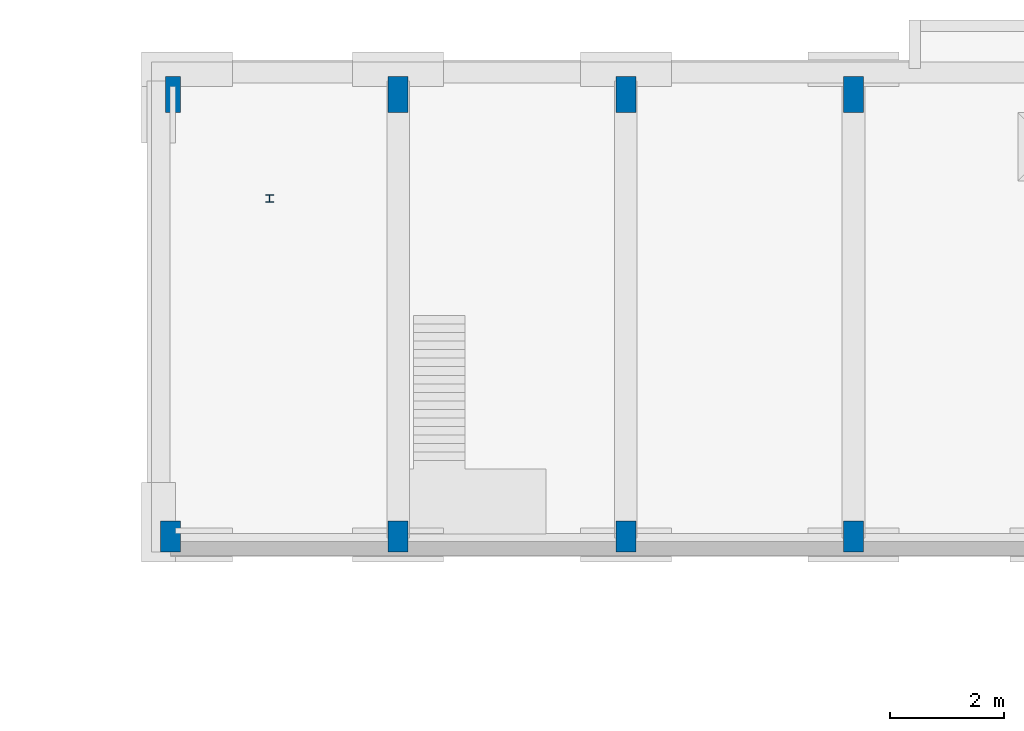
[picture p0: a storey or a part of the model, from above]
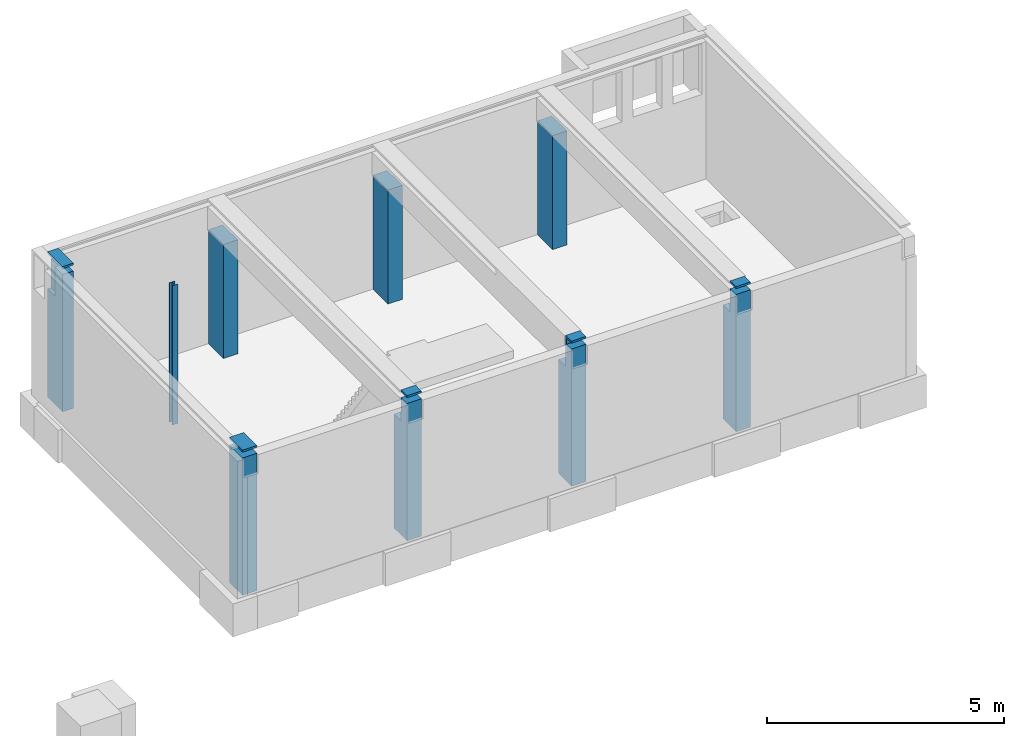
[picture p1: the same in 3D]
Properties of the parts of a building model (IFC2X3), part 1 of 5

# File
Description: ViewDefinition [Basis ILS 2.0, SurfaceGeometryAddOnView, QuantityTakeOffAddOnView], Option [Elements to export: Visible elements (on all stories)], Option [Partial Structure Display: Entire Model], Option [IFC Domain: All], Option [Structural Function: All Elements], Option [Convert Grid elements: On], Option [Convert IFC Annotations and Archicad 2D elements: On], Option [Convert 2D symbols of Doors and Windows: On], Option [Export geometries that Participates in Collision Detection only: On], Option [Split complex elements: On], Option [IFC Model position: Project Origin only], Option [Curtain Wall export mode: Single Element], Option [Railing export mode: Single Element], Option [Stair export mode: Single Element], Option [Properties To Export: Current Scheme properties only], Option [Space containment: Off], Option [Geometry to type objects: On], Option [Element Properties: Off], Option [Building Material Properties: Off], Option [Element Parameters: Off], Option [Component Parameters: Off], Option [IFC Base Quantities: On], Option [Door Window Parameters: Off], Option [IFC Space boundaries: Off], Option [Archicad Zone Categories as IFC Space classification data: Off], Option [Element Classifications: Off]
File name: C:\Users\Briquearchitectenint\BRIQUEarchitecten Dropbox\Kantoor\03-Projecten\BQ2409-ISK Leiden\2409-A-Werkmap\2409-archicad\#publish\ifc\2409-ISK Leiden-nieuw.ifc
Time: 2026-07-10T21:38:03
Author: Architect
Organization: Brique architecten
Written by: DDS_IFC v3.0
Made in: Graphisoft - Archicad - 27.0.0
Authorization: The authorising person

# IfcProject, ISK Leiden
Description: renovatie en verduurzaming; Phase: concept

# IfcSite, <site naam>
RefLatitude: 52, 8, 48, 473880; RefLongitude: 4, 28, 0, 806880; RefElevation: 0 mm
BaseQuantities - GrossPerimeter: 0 mm; GrossArea: 0 m2

# IfcBuilding, <Naam gebouw>
BaseQuantities - GrossFloorArea: 13806 m2

# IfcBuildingStorey (9)
In: <Naam gebouw>
Name | Elevation (mm) | NetHeight (mm) = GrossHeight (mm) = Height (mm) | GrossFloorArea (m2)
Kelder | -3730 | 2630 | 292.087
00 Begane grond | 0 | 3188 | 4961.05
01 1e verdieping | 4250 | 2095 | 4119.65
01 1e tussenverdieping | 3188 | 1062 | 354.603
02 2e tussenverdieping | 6345 | 2155 | 1089.99
02 2e verdieping | 8500 | 1063 | 2567.1
03 3e tussenverdieping | 9563 | 3207 | 387.066
-1 Fundering | -1100 | 1100 | 34.4343
04 4e verdieping | 12770 | 4250 | 0

# IfcSpace: ALG - ALGEMEEN (2)
In: 00 Begane grond
InteriorOrExteriorSpace: INTERNAL
Pset_SpaceCommon - WallCovering: / / /
Name | GrossFloorArea (m2) = NetFloorArea (m2) | GrossPerimeter (mm) = NetPerimeter (mm) | GrossVolume (m3) = NetVolume (m3)
nulpunt | 0.522146 | 7586.11 | 0.0261073
trafo | 0.96 | 4000 | 0.96

# IfcSpace: BVO (17)
InteriorOrExteriorSpace: INTERNAL
Pset_SpaceCommon - WallCovering: / / /
BaseQuantities - FinishFloorHeight: 0 mm
Name | In | LongName | Height (mm) = FinishCeilingHeight (mm) = ClearHeight (mm) | GrossFloorArea (m2) = GrossCeilingArea (m2) | NetFloorArea (m2) = SpaceNetFloorAreaBOMA (m2) = SpaceUsableFloorAreaBOMA (m2) = NetCeilingArea (m2) | GrossWallArea (m2) | NetWallArea (m2) | GrossPerimeter (mm) = NetPerimeter (mm) | GrossVolume (m3) | NetVolume (m3)
 | Kelder | Kelder | 3730 | 142.151 | 142.151 | 272.423 | 272.423 | 50240 | 530.224 | 530.224
 | -1 Fundering | Kelder | 1100 | 25.5443 | 25.5443 | 20.2501 | 20.2501 | 21801.9 | 28.0987 | 28.0987
 | -1 Fundering | Kelder | 1100 | 8.89 | 8.89 | 0 | 0 | 12080 | 9.779 | 9.779
 | 00 Begane grond | Hoogbouw | 4250 | 833.284 | 833.27 | 82.1003 | 71.7503 | 121988 | 3541.46 | 3541.46
 | 00 Begane grond | Aula | 4250 | 481.589 | 481.589 | 69.8649 | 59.5149 | 90371.5 | 2046.75 | 2046.75
 | 00 Begane grond | Bg tussenvp | 3188 | 127.776 | 127.776 | 4.7807 | 4.7807 | 53688.2 | 407.351 | 407.351
 | 00 Begane grond | Bg sport | 6345 | 250.491 | 250.491 | 141.047 | 141.047 | 65568.2 | 1589.37 | 1589.37
 | 01 1e tussenverdieping | 1e tussenvp | 3157 | 123.7 | 123.7 | 0.5059 | 0.5059 | 52370 | 390.521 | 390.521
 | 01 1e verdieping | Aula | 4250 | 542.57 | 542.57 | 61.7838 | 61.7838 | 98850.1 | 2305.92 | 2305.91
 | 01 1e verdieping | Hoogbouw | 4250 | 829.629 | 829.629 | 76.5567 | 66.2067 | 129466 | 3525.92 | 3525.92
 | 01 1e verdieping | Trappenhuis | 4250 | 62.0912 | 62.0912 | 5.95078 | 5.95078 | 34370 | 263.888 | 263.888
 | 02 2e tussenverdieping | 2e tussenvp | 3018 | 114.625 | 114.625 | 14.6042 | 14.6042 | 57628.8 | 345.937 | 345.937
 | 02 2e tussenverdieping | 2e tussenvp sport | 5715 | 252.613 | 252.613 | 153.593 | 153.593 | 66108.2 | 1443.69 | 1443.69
 | 02 2e verdieping | Hoogbouw | 4270 | 823.364 | 823.364 | 85.9745 | 85.9745 | 132562 | 3515.76 | 3515.76
 | 02 2e verdieping | Trappenhuis | 3560 | 62.8175 | 62.8175 | 6.0916 | 6.0916 | 34819.9 | 223.63 | 223.63
 | 03 3e tussenverdieping | 3e tussenvp | 3157 | 25.6769 | 25.6769 | 63.5105 | 63.5105 | 90538.2 | 81.0619 | 81.0619
 | 03 3e tussenverdieping | 3e tussenvp | 3157 | 123 | 123 | 3.11745 | 3.11745 | 52300 | 388.311 | 388.311

# IfcSpace: Badruimte (5)
InteriorOrExteriorSpace: INTERNAL
Pset_SpaceCommon - WallCovering: / / /
BaseQuantities - FinishFloorHeight: 0 mm
Name | In | LongName | Height (mm) = FinishCeilingHeight (mm) = ClearHeight (mm) | GrossFloorArea (m2) = NetFloorArea (m2) = SpaceNetFloorAreaBOMA (m2) = SpaceUsableFloorAreaBOMA (m2) = GrossCeilingArea (m2) = NetCeilingArea (m2) | GrossWallArea (m2) | NetWallArea (m2) | GrossPerimeter (mm) = NetPerimeter (mm) | GrossVolume (m3) | NetVolume (m3)
0.32 | 00 Begane grond | Douche 1 | 6345 | 6.15923 | 30.5355 | 28.4355 | 10283.4 | 39.0803 | 18.3422
0.36 | 00 Begane grond | Douche 2 | 3188 | 6.35991 | 22.1575 | 19.8575 | 10239.9 | 20.2754 | 18.9398
2.04 | 02 2e tussenverdieping | douche 3 | 3218.02 | 5.28496 | 17.8736 | 15.7736 | 9760.6 | 17.0071 | 17.0071
2.08 | 02 2e tussenverdieping | douche 4 | 3218.02 | 5.36145 | 21.682 | 19.612 | 9553.58 | 17.2533 | 16.2882
2.06 | 02 2e tussenverdieping | douche | 3218.02 | 4.24069 | 16.4628 | 14.3928 | 8472.97 | 13.6466 | 13.6466

# IfcSpace: Bergruimte (8)
InteriorOrExteriorSpace: INTERNAL
Pset_SpaceCommon - WallCovering: / / /
BaseQuantities - FinishFloorHeight: 0 mm
Name | In | LongName | Height (mm) = FinishCeilingHeight (mm) = ClearHeight (mm) | GrossFloorArea (m2) = NetFloorArea (m2) = SpaceNetFloorAreaBOMA (m2) = SpaceUsableFloorAreaBOMA (m2) = GrossCeilingArea (m2) = NetCeilingArea (m2) | GrossWallArea (m2) | NetWallArea (m2) | GrossPerimeter (mm) = NetPerimeter (mm) | GrossVolume (m3) | NetVolume (m3)
 | Kelder | Kelder | 2430 | 129.841 | 191.91 | 191.91 | 48240 | 315.514 | 315.514
0.38 | 00 Begane grond | Toestelb. | 3188 | 21.9559 | 27.1165 | 27.1165 | 19474 | 69.9955 | 65.5093
0.18b | 00 Begane grond | Voorraad | 4050 | 9.22525 | 31.1651 | 26.4311 | 12492.3 | 37.3623 | 37.3623
0.15 | 00 Begane grond | Stoelenberging | 4050 | 26.4333 | 40.568 | 36.1925 | 22262.2 | 107.055 | 107.055
1.30 | 01 1e tussenverdieping | Leermiddelen | 3157 | 11.9205 | 21.2914 | 21.2914 | 14479.4 | 37.6332 | 34.8914
1.29 | 01 1e tussenverdieping | Berg. & boiler | 3157 | 6.55712 | 24.395 | 24.395 | 11229.6 | 20.7008 | 19.1927
2.09 | 02 2e tussenverdieping | toestelb. 3 | 3218 | 21.6096 | 43.8857 | 30.1658 | 19979.1 | 69.5398 | 65.1248
3.03b | 02 2e verdieping | wk 3 | 4070 | 3.4722 | 22.8184 | 20.7484 | 7468.2 | 14.1319 | 14.1319

# IfcSpace: Functieruimte, 2.10
In: 02 2e tussenverdieping
LongName: Gymzaal; InteriorOrExteriorSpace: INTERNAL
BaseQuantities - Height: 7690 mm; FinishCeilingHeight: 7690 mm; FinishFloorHeight: 0 mm; ClearHeight: 7690 mm; GrossFloorArea: 223.728 m2; NetFloorArea: 223.728 m2; SpaceNetFloorAreaBOMA: 223.728 m2; SpaceUsableFloorAreaBOMA: 223.728 m2; GrossCeilingArea: 223.728 m2; NetCeilingArea: 223.728 m2; GrossWallArea: 142.568 m2; NetWallArea: 142.568 m2; GrossPerimeter: 63356.6 mm; NetPerimeter: 63356.6 mm; GrossVolume: 1720.47 m3; NetVolume: 1720.47 m3
Pset_SpaceCommon - WallCovering: / / /

# IfcSpace: GO (13)
LongName: GO; InteriorOrExteriorSpace: INTERNAL
Pset_SpaceCommon - WallCovering: / / /
BaseQuantities - FinishFloorHeight: 0 mm
Name | In | Height (mm) = FinishCeilingHeight (mm) = ClearHeight (mm) | GrossFloorArea (m2) = NetFloorArea (m2) = SpaceNetFloorAreaBOMA (m2) = SpaceUsableFloorAreaBOMA (m2) = GrossCeilingArea (m2) = NetCeilingArea (m2) | GrossWallArea (m2) | NetWallArea (m2) | GrossPerimeter (mm) = NetPerimeter (mm) | GrossVolume (m3) = NetVolume (m3)
02 | 00 Begane grond | 4050 | 773.536 | 99.9267 | 97.8567 | 154608 | 3132.82
01 | 00 Begane grond | 4050 | 459.481 | 93.6681 | 83.3181 | 94860 | 1860.9
04 | 00 Begane grond | 6145 | 229.615 | 181.334 | 181.334 | 62952.2 | 1410.98
03 | 00 Begane grond | 2988 | 115.949 | 93.6167 | 69.3387 | 50585.6 | 346.456
05 | 01 1e tussenverdieping | 2957 | 105.499 | 49.4467 | 45.7811 | 57559.4 | 311.961
06 | 01 1e verdieping | 4050 | 506.44 | 114.242 | 114.242 | 104408 | 2051.08
08 | 01 1e verdieping | 4050 | 757.15 | 77.9698 | 77.9698 | 144391 | 3066.46
07 | 01 1e verdieping | 4050 | 33.6334 | 5.95078 | 5.95078 | 23836.9 | 136.215
09 | 02 2e tussenverdieping | 3018 | 110.447 | 52.5559 | 42.3198 | 53405.6 | 333.329
10 | 02 2e tussenverdieping | 6225 | 229.759 | 211.972 | 211.972 | 62966.6 | 1430.25
11 | 02 2e verdieping | 4070 | 31.5014 | 4.89225 | 4.89225 | 23342 | 128.211
12 | 02 2e verdieping | 4070 | 756.798 | 58.1313 | 58.1313 | 144194 | 3080.17
13 | 03 3e tussenverdieping | 2957 | 106.108 | 73.4812 | 62.9368 | 59759.4 | 313.762

# IfcSpace: Kleedruimte (7)
InteriorOrExteriorSpace: INTERNAL
Pset_SpaceCommon - WallCovering: / / /
BaseQuantities - FinishFloorHeight: 0 mm
Name | In | LongName | Height (mm) = FinishCeilingHeight (mm) = ClearHeight (mm) | GrossFloorArea (m2) = NetFloorArea (m2) = SpaceNetFloorAreaBOMA (m2) = SpaceUsableFloorAreaBOMA (m2) = GrossCeilingArea (m2) = NetCeilingArea (m2) | GrossWallArea (m2) | NetWallArea (m2) | GrossPerimeter (mm) = NetPerimeter (mm) | GrossVolume (m3) | NetVolume (m3)
0.31 | 00 Begane grond | Kleedk. 1 | 3188 | 14.0689 | 46.9063 | 42.7363 | 20242 | 44.8515 | 42.0734
0.35 | 00 Begane grond | Kleedk. 2 | 3188 | 14.4726 | 58.2734 | 53.9034 | 20085.6 | 46.1387 | 43.3331
0.34 | 00 Begane grond | docent | 3188 | 8.94912 | 18.3415 | 12.0798 | 12069 | 28.5298 | 26.6505
0.33 | 00 Begane grond | stilte werkplek | 3188 | 4.36008 | 17.5512 | 14.7786 | 9173.4 | 13.8999 | 13.8999
2.03 | 02 2e tussenverdieping | kleedk. 3 | 3218 | 11.755 | 51.3375 | 47.1675 | 18078.1 | 37.8277 | 35.7285
2.07 | 02 2e tussenverdieping | kleedk. 4 | 3218 | 14.4365 | 61.3867 | 57.2467 | 20365.1 | 46.4566 | 43.858
2.05 | 02 2e tussenverdieping | docent | 3218 | 8.26177 | 32.8714 | 25.141 | 11854 | 26.5864 | 25.0993

# IfcSpace: OBJ - SEO Operator (6)
In: 00 Begane grond
InteriorOrExteriorSpace: INTERNAL
Pset_SpaceCommon - WallCovering: / / /
Name | GrossFloorArea (m2) = NetFloorArea (m2) | GrossPerimeter (mm) = NetPerimeter (mm) | GrossVolume (m3) = NetVolume (m3)
nulpunt | 0.0165662 | 5010.03 | 0.0397588
nulpunt | 0.185945 | 3918.91 | 0
2 x nulpunt | 0.005 | 300 | 0.003125
2 x nulpunt | 0.03125 | 1350 | 0.0044375

# IfcSpace: Onbenoemde ruimte (4)
InteriorOrExteriorSpace: INTERNAL
Pset_SpaceCommon - WallCovering: / / /
BaseQuantities - Height: 4050 mm; FinishCeilingHeight: 4050 mm; FinishFloorHeight: 0 mm; ClearHeight: 4050 mm
Name | In | LongName | GrossFloorArea (m2) = NetFloorArea (m2) = SpaceNetFloorAreaBOMA (m2) = SpaceUsableFloorAreaBOMA (m2) = GrossCeilingArea (m2) = NetCeilingArea (m2) | GrossWallArea (m2) | NetWallArea (m2) | GrossPerimeter (mm) = NetPerimeter (mm) | GrossVolume (m3) = NetVolume (m3)
0.18a | 00 Begane grond | Keuken uitgifte | 20.3712 | 53.4764 | 46.2207 | 18282.4 | 82.5033
0.03 | 00 Begane grond | Receptie | 10.125 | 52.335 | 42.6113 | 13100 | 41.0062
1.11 | 01 1e verdieping | garderobe | 7.09431 | 19.2205 | 19.2205 | 10745 | 28.732
1.20 | 01 1e verdieping | stiltewp. | 6.28236 | 34.9928 | 25.409 | 10491.7 | 25.4436

# IfcSpace: Technische ruimte (5)
InteriorOrExteriorSpace: INTERNAL
Pset_SpaceCommon - WallCovering: / / /
BaseQuantities - Height: 4050 mm; FinishCeilingHeight: 4050 mm; FinishFloorHeight: 0 mm; ClearHeight: 4050 mm
Name | In | LongName | GrossFloorArea (m2) = NetFloorArea (m2) = SpaceNetFloorAreaBOMA (m2) = SpaceUsableFloorAreaBOMA (m2) = GrossCeilingArea (m2) = NetCeilingArea (m2) | GrossWallArea (m2) | NetWallArea (m2) | GrossPerimeter (mm) = NetPerimeter (mm) | GrossVolume (m3) = NetVolume (m3)
0.20 | 00 Begane grond | inkoop | 11.2839 | 44.0257 | 44.0257 | 13518.1 | 45.6999
0.21 | 00 Begane grond | trafo | 9.90244 | 31.0377 | 31.0377 | 12599.9 | 40.1049
0.22 | 00 Begane grond | HKL | 1.80277 | 20.0733 | 15.1404 | 7216.32 | 7.3012
0.23 | 00 Begane grond | server | 8.50368 | 35.6978 | 35.6978 | 13048.5 | 34.4399
1.14b | 01 1e verdieping | wk 1 | 3.47188 | 22.778 | 20.708 | 7467.88 | 14.0611

# IfcSpace: Toiletruimte (12)
InteriorOrExteriorSpace: INTERNAL
BaseQuantities - FinishFloorHeight: 0 mm
Pset_SpaceCommon - WallCovering: / / /
Name | In | LongName | Height (mm) = FinishCeilingHeight (mm) = ClearHeight (mm) | GrossFloorArea (m2) = NetFloorArea (m2) = SpaceNetFloorAreaBOMA (m2) = SpaceUsableFloorAreaBOMA (m2) = GrossCeilingArea (m2) = NetCeilingArea (m2) | GrossWallArea (m2) | NetWallArea (m2) | GrossPerimeter (mm) = NetPerimeter (mm) | GrossVolume (m3) | NetVolume (m3)
0.37 | 00 Begane grond | WC | 3188 | 1.66847 | 15.4256 | 13.3556 | 5724.37 | 5.31907 | 4.96869
0.30 | 00 Begane grond | MIVA + douche | 3188 | 8.5775 | 10.2082 | 6.06824 | 12400 | 27.3451 | 25.5438
0.24b | 00 Begane grond | WC | 4050 | 12.8426 | 64.2849 | 64.2849 | 14636.3 | 52.0126 | 52.0126
0.24a | 00 Begane grond | WC | 4050 | 12.8489 | 47.287 | 47.287 | 14640.6 | 52.0381 | 52.0381
0.06 | 00 Begane grond | WC | 4050 | 6.78397 | 24.0019 | 21.9319 | 10696.6 | 27.4751 | 27.4751
0.16 | 00 Begane grond | WC | 4050 | 2.86688 | 0 | 0 | 7737.85 | 11.6108 | 11.6108
1.14a | 01 1e verdieping | WC | 4050 | 15.5571 | 69.3068 | 63.0946 | 17149.8 | 63.0064 | 63.0064
1.13 | 01 1e verdieping | WC | 4050 | 14.6073 | 66.0554 | 61.9131 | 17230.1 | 59.1597 | 59.1597
2.02 | 02 2e tussenverdieping | WC | 3218 | 1.38454 | 11.6355 | 9.56547 | 5091.84 | 4.45545 | 4.20624
2.11 | 02 2e tussenverdieping | WC | 3218 | 1.68421 | 13.8144 | 11.7444 | 5630.43 | 5.4198 | 5.11664
3.02 | 02 2e verdieping | WC | 4050 | 14.6073 | 66.3215 | 62.1792 | 17230.1 | 59.1596 | 59.1596
3.03a | 02 2e verdieping | WC | 4050 | 15.5571 | 69.1785 | 62.9662 | 17149.6 | 63.0061 | 63.0061

# IfcSpace: Verblijfsruimte (48)
InteriorOrExteriorSpace: INTERNAL
Pset_SpaceCommon - WallCovering: / / /
BaseQuantities - FinishFloorHeight: 0 mm
Name | In | LongName | Height (mm) = FinishCeilingHeight (mm) = ClearHeight (mm) | GrossFloorArea (m2) = NetFloorArea (m2) = SpaceNetFloorAreaBOMA (m2) = SpaceUsableFloorAreaBOMA (m2) = GrossCeilingArea (m2) = NetCeilingArea (m2) | GrossWallArea (m2) | NetWallArea (m2) | GrossPerimeter (mm) = NetPerimeter (mm) | GrossVolume (m3) | NetVolume (m3)
0.39 | 00 Begane grond | Gymzaal | 7620 | 223.656 | 140.513 | 140.513 | 62919.4 | 1704.26 | 1704.26
0.17 | 00 Begane grond | Teamleider | 4050 | 22.2198 | 19.0594 | 19.0594 | 19242.7 | 89.9901 | 89.9901
0.19 | 00 Begane grond | Projectruimte hardskills | 4050 | 89.93 | 76.7598 | 76.7598 | 40702.3 | 364.216 | 364.216
0.26b/c | 00 Begane grond | Studio | 4050 | 20.9398 | 54.759 | 47.0663 | 18630 | 84.806 | 84.806
0.11 | 00 Begane grond | Stafkamer | 4050 | 35.3005 | 44.5441 | 39.7316 | 24204.3 | 142.967 | 142.967
0.09 | 00 Begane grond | Ll coord. | 4050 | 12.4388 | 47.2689 | 39.6439 | 14871.3 | 50.3772 | 50.3772
0.07 | 00 Begane grond | Concierge/toezicht | 4050 | 28.5339 | 39.9575 | 33.332 | 21445.9 | 115.562 | 115.562
0.12 | 00 Begane grond | CVB kamer | 4050 | 35.2563 | 65.85 | 46.225 | 23863.3 | 142.788 | 141.899
0.08 | 00 Begane grond | Verzuim | 4050 | 19.4034 | 50.956 | 39.3685 | 17772.9 | 78.5839 | 78.0584
0.10 | 00 Begane grond | BS/HS | 4050 | 12.4388 | 46.8096 | 39.1846 | 14871.3 | 50.3772 | 50.3772
0.13 | 00 Begane grond | ICT | 4050 | 20.8846 | 57.0707 | 45.4457 | 18530 | 84.5827 | 84.0555
0.26d | 00 Begane grond | Tochtportaal | 4050 | 1.626 | 16.2566 | 14.3016 | 5168 | 6.5853 | 6.5853
0.26a | 00 Begane grond | Muzieklokaal | 4050 | 59.2646 | 85.2617 | 71.4739 | 31318 | 240.021 | 240.021
1.32 | 01 1e tussenverdieping | overleg | 3157 | 33.3068 | 30.5259 | 30.5259 | 23679.6 | 105.149 | 105.149
1.31 | 01 1e tussenverdieping | ICT-er | 3157 | 13.5727 | 12.2747 | 12.2747 | 19077.4 | 42.8489 | 39.8127
1.24 | 01 1e verdieping | Theorielokaal 08 | 4050 | 45.641 | 77.0806 | 71.8306 | 27734.2 | 184.846 | 184.846
1.25 | 01 1e verdieping | BiNask | 4050 | 83.3325 | 116.541 | 97.9406 | 39198 | 337.497 | 337.497
1.19 | 01 1e verdieping | Theorielokaal 05 | 4050 | 46.625 | 115.735 | 104.28 | 27639.7 | 188.831 | 188.831
1.15 | 01 1e verdieping | Theorielokaal 01 | 4050 | 45.9188 | 60.5851 | 60.5851 | 27398.7 | 185.971 | 185.971
1.17 | 01 1e verdieping | Theorielokaal 03 | 4050 | 45.9171 | 83.8149 | 72.3599 | 27398.2 | 185.964 | 185.964
1.16 | 01 1e verdieping | Theorielokaal 02 | 4050 | 45.9152 | 60.1034 | 60.1034 | 27397.5 | 185.957 | 185.957
1.18 | 01 1e verdieping | Theorielokaal 04 | 4050 | 45.9195 | 82.6765 | 72.2119 | 27399 | 185.974 | 185.974
1.23 | 01 1e verdieping | Theorielokaal 07 | 4050 | 45.2141 | 76.1875 | 68.8675 | 27198 | 183.117 | 183.117
1.22 | 01 1e verdieping | Theorielokaal 06 | 4050 | 45.2141 | 74.2698 | 69.0199 | 27198 | 183.117 | 183.117
1.06 | 01 1e verdieping | Beeldende vorming | 4050 | 64.6516 | 96.8078 | 77.8037 | 32506.1 | 261.839 | 261.272
1.05 | 01 1e verdieping | Beeldende vorming | 4050 | 61.8525 | 87.2269 | 69.4522 | 31753.3 | 250.503 | 249.694
1.09 | 01 1e verdieping | Teamkamer | 4050 | 86.276 | 79.217 | 69.6918 | 38820.4 | 349.418 | 349.418
1.03 | 01 1e verdieping | zorgmedew. | 4050 | 47.7883 | 81.0056 | 55.4522 | 30431.2 | 193.543 | 192.976
1.21b | 01 1e verdieping | schoolstaf | 4050 | 25.1076 | 38.5458 | 38.5458 | 20300 | 101.686 | 101.686
1.10 | 01 1e verdieping | Team wp. | 4050 | 15.2421 | 24.529 | 21.0578 | 16944.2 | 61.7307 | 61.7307
1.21a | 01 1e verdieping | teamleiders | 4050 | 16.7054 | 28.7552 | 28.7552 | 16580 | 67.6567 | 67.6567
1.08 | 01 1e verdieping | projectruimte softskills | 4050 | 115.906 | 156.512 | 70.5306 | 46231 | 469.418 | 469.418
3.14 | 02 2e verdieping | Lokaal alfa 3 | 8320 | 45.6776 | 75.2023 | 75.2023 | 27316.7 | 380.038 | 380.038
3.15 | 02 2e verdieping | Lokaal alfa 4 | 8320 | 45.6878 | 72.2829 | 72.2829 | 27319.3 | 380.123 | 380.123
3.16 | 02 2e verdieping | Theorielokaal 14 | 8320 | 52.1156 | 90.6495 | 90.6495 | 31197.9 | 433.602 | 433.602
3.12 | 02 2e verdieping | Lokaal alfa 1 | 8320 | 45.1822 | 57.5145 | 57.5145 | 27187.8 | 375.916 | 375.916
3.06 | 02 2e verdieping | Theorielokaal 10 | 8320 | 45.8537 | 66.9357 | 66.9357 | 27376.4 | 381.503 | 381.503
3.05 | 02 2e verdieping | Theorielokaal 09 | 8320 | 45.8728 | 62.1441 | 62.1441 | 27383 | 381.662 | 381.662
3.04 | 02 2e verdieping | Theorielokaal 08 | 8320 | 45.8924 | 60.0628 | 60.0628 | 27389.8 | 381.825 | 381.825
3.08 | 02 2e verdieping | Theorielokaal 12 | 8320 | 46.4185 | 28.9112 | 28.9112 | 27542 | 386.202 | 386.202
3.13 | 02 2e verdieping | Lokaal alfa 2 | 8320 | 45.6925 | 75.4918 | 75.4918 | 27320.5 | 380.162 | 380.162
3.07 | 02 2e verdieping | Theorielokaal 11 | 8320 | 45.8323 | 66.5697 | 66.5697 | 27369.3 | 381.325 | 381.325
3.11 | 02 2e verdieping | Adjuct dir | 4070 | 18.7946 | 47.9346 | 36.5646 | 17498 | 76.4941 | 76.4941
3.10 | 02 2e verdieping | Overleg | 4070 | 19.391 | 50.1403 | 38.1703 | 17898 | 78.9215 | 78.9215
3.09 | 02 2e verdieping | Ontvangst | 3207.5 | 23.6816 | 12.657 | 12.657 | 21556.5 | 75.9586 | 73.8748
3.22 | 03 3e tussenverdieping | Theorielokaal 13 | 3207 | 44.0846 | 52.6872 | 39.5864 | 28201.1 | 141.379 | 141.379
3.20 | 03 3e tussenverdieping | kolfruimte | 7457 | 12.9022 | 39.7428 | 35.5295 | 16390 | 96.2118 | 96.2118
3.21 | 03 3e tussenverdieping | Flexwp. | 3207 | 17.2151 | 35.0503 | 32.9803 | 19143.8 | 55.2088 | 55.2088

# IfcSpace: Verblijfsruimte - Multifunctioneel (2)
In: 00 Begane grond
InteriorOrExteriorSpace: INTERNAL
Pset_SpaceCommon - WallCovering: / / /
BaseQuantities - Height: 4050 mm; FinishCeilingHeight: 4050 mm; FinishFloorHeight: 0 mm; ClearHeight: 4050 mm
Name | LongName | GrossFloorArea (m2) = NetFloorArea (m2) = SpaceNetFloorAreaBOMA (m2) = SpaceUsableFloorAreaBOMA (m2) = GrossCeilingArea (m2) = NetCeilingArea (m2) | GrossWallArea (m2) | NetWallArea (m2) | GrossPerimeter (mm) = NetPerimeter (mm) | GrossVolume (m3) = NetVolume (m3)
0.02b | Ontvangst | 23.6898 | 22.3124 | 14.6324 | 19642 | 95.9435
0.25 | Pauzeruimte | 272.687 | 25.8595 | 25.8595 | 92060.7 | 1104.38

# IfcSpace: Verkeersruimte (23)
InteriorOrExteriorSpace: INTERNAL
Pset_SpaceCommon - WallCovering: / / /
BaseQuantities - FinishFloorHeight: 0 mm
Name | In | LongName | Height (mm) = FinishCeilingHeight (mm) = ClearHeight (mm) | GrossFloorArea (m2) = NetFloorArea (m2) = SpaceNetFloorAreaBOMA (m2) = SpaceUsableFloorAreaBOMA (m2) = GrossCeilingArea (m2) = NetCeilingArea (m2) | GrossWallArea (m2) | NetWallArea (m2) | GrossPerimeter (mm) = NetPerimeter (mm) | GrossVolume (m3) | NetVolume (m3)
0.01 | 00 Begane grond | Entree | 4050 | 22.3862 | 59.1316 | 33.2909 | 19618 | 90.6643 | 90.3821
0.05 | 00 Begane grond | Kluisjes | 4050 | 28.1222 | 59.1745 | 58.8221 | 22640 | 113.895 | 113.895
0.04e | 00 Begane grond | Stilte wp | 3018 | 31.6946 | 34.1227 | 25.9993 | 23174.6 | 95.6542 | 95.6542
0.02a | 00 Begane grond | Gang | 4050 | 70.7586 | 114.954 | 47.5741 | 45863.3 | 286.572 | 286.572
0.04b | 00 Begane grond | Stilte wp/pantry | 4050 | 18.2647 | 57.6545 | 39.8736 | 17544 | 73.9722 | 73.9722
0.04 | 00 Begane grond | Gang | 4050 | 109.969 | 81.9354 | 69.5154 | 101940 | 445.373 | 445.373
0.28 | 00 Begane grond | Lift | 4050 | 4.7519 | 51.2021 | 45.7421 | 8802 | 19.2452 | 19.2452
TR03.0 | 00 Begane grond | Trappenhuis | 4050 | 10.6696 | 9.26868 | 9.26868 | 13231.6 | 43.2117 | 43.2117
0.29 | 00 Begane grond | Gang | 3188 | 20.7786 | 53.2937 | 26.4975 | 18945.6 | 66.2422 | 61.8787
0.27 | 00 Begane grond | Gang | 4050 | 14.3771 | 62.3001 | 25.1901 | 15170 | 58.2271 | 58.2271
0.04c | 00 Begane grond | Stilte wp | 4050 | 3.31585 | 19.4824 | 11.8925 | 7324.91 | 13.4292 | 13.4292
0.04d | 00 Begane grond | Stilte wp | 4050 | 3.31594 | 27.3015 | 19.7115 | 7325 | 13.4295 | 13.4295
0.04a | 00 Begane grond | gang | 4050 | 26.3388 | 74.5939 | 27.8736 | 24950 | 106.672 | 106.672
1.28 | 01 1e tussenverdieping | Gang | 3157 | 44.4902 | 38.9281 | 35.2625 | 31855.6 | 140.456 | 137.598
1.01 | 01 1e verdieping | Gang | 4050 | 76.3796 | 143.516 | 75.3074 | 48392.4 | 309.337 | 309.337
1.26 | 01 1e verdieping | Gang | 4050 | 15.8647 | 0 | 0 | 15938.8 | 64.2519 | 64.2519
1.12 | 01 1e verdieping | Gang | 4050 | 166.942 | 0.6075 | 0.6075 | 86780 | 676.116 | 676.116
1.27 | 01 1e verdieping | Lift | 4050 | 4.75 | 0 | 0 | 8800 | 19.2375 | 19.2375
2.01 | 02 2e tussenverdieping | Gang | 3218 | 21.4588 | 37.3518 | 18.4997 | 23325.6 | 69.0544 | 65.2371
3.17 | 02 2e verdieping | Gang | 4070 | 15.7971 | 53.0432 | 26.2832 | 15940.1 | 64.294 | 64.294
3.01 | 02 2e verdieping | Gang | 4070 | 139.294 | 157.982 | 102.905 | 80051.1 | 566.927 | 566.927
3.18 | 02 2e verdieping | Lift | 4070 | 4.7519 | 51.2562 | 45.7962 | 8802 | 19.3402 | 19.3402
3.19 | 03 3e tussenverdieping | Gang | 3207 | 23.4871 | 41.3802 | 18.9304 | 23325.6 | 75.323 | 75.323

# IfcSpace: Verkeersruimte - trappenhuis (6)
LongName: Trappenhuis; InteriorOrExteriorSpace: INTERNAL
BaseQuantities - FinishFloorHeight: 0 mm
Pset_SpaceCommon - WallCovering: / / /
Name | In | Height (mm) = FinishCeilingHeight (mm) = ClearHeight (mm) | GrossFloorArea (m2) = GrossCeilingArea (m2) | NetFloorArea (m2) = SpaceNetFloorAreaBOMA (m2) = SpaceUsableFloorAreaBOMA (m2) = NetCeilingArea (m2) | GrossWallArea (m2) = NetWallArea (m2) | GrossPerimeter (mm) = NetPerimeter (mm) | GrossVolume (m3) | NetVolume (m3)
TR02.0 | 00 Begane grond | 4050 | 28.9263 | 25.6024 | 94.3165 | 23150 | 117.151 | 88.163
TR01.0 | 00 Begane grond | 4050 | 41.644 | 41.644 | 0 | 26022.8 | 168.658 | 168.658
TR02.1 | 01 1e verdieping | 4050 | 27.7764 | 27.7764 | 0 | 22520 | 112.494 | 112.494
TR01.1 | 01 1e verdieping | 4050 | 69.4572 | 69.4572 | 28.35 | 40926.7 | 281.302 | 281.302
TR02.3 | 02 2e verdieping | 4070 | 27.7768 | 27.7768 | 63.6715 | 22520.2 | 113.052 | 113.052
TR01.3 | 02 2e verdieping | 3530 | 70.0453 | 70.0453 | 48.3927 | 41103.8 | 247.26 | 247.26

# IfcBeam: ALG - ALGEMEEN 100 x 2438, 77_Balk_ALG
In: 01 1e tussenverdieping
Type - PredefinedType: BEAM
Material: ALG - ALGEMEEN
Pset_BeamCommon - Slope: 0 deg; IsExternal: no; LoadBearing: yes; Reference: ALG - ALGEMEEN 100 x 2438
BaseQuantities - NetSurfaceAreaExtrudedSides: 8.04978 m2; Length: 1620 mm; Width: 100 mm; Depth: 2437.5 mm; CrossSectionArea: 0.24375 m2; OuterSurfaceArea: 8.04978 m2; TotalSurfaceArea: 8.53728 m2; GrossSurfaceArea: 8.53728 m2; GrossVolume: 0.443625 m3; NetSurfaceArea: 8.53728 m2; NetVolume: 0.394389 m3

# IfcBeam: ALG - ALGEMEEN 100 x 2518, 77_Balk_ALG
In: 02 2e verdieping
Type - PredefinedType: BEAM
Material: ALG - ALGEMEEN
Pset_BeamCommon - Slope: 0 deg; IsExternal: no; LoadBearing: yes; Reference: ALG - ALGEMEEN 100 x 2518
BaseQuantities - NetSurfaceAreaExtrudedSides: 7.43705 m2; Length: 1450 mm; Width: 100 mm; Depth: 2517.5 mm; CrossSectionArea: 0.25175 m2; OuterSurfaceArea: 7.43705 m2; TotalSurfaceArea: 7.94055 m2; GrossSurfaceArea: 7.94055 m2; GrossVolume: 0.365038 m3; NetSurfaceArea: 7.94055 m2; NetVolume: 0.364603 m3

# IfcBeam: ALG - ALGEMEEN 100 x 900 (12)
Type - PredefinedType: BEAM
Material: ALG - ALGEMEEN
Pset_BeamCommon - Slope: 0 deg; IsExternal: no; LoadBearing: yes; Reference: ALG - ALGEMEEN 100 x 900
BaseQuantities - Width: 100 mm
Name | In | NetSurfaceAreaExtrudedSides (m2) = OuterSurfaceArea (m2) | Length (mm) | Depth (mm) | CrossSectionArea (m2) | TotalSurfaceArea (m2) = GrossSurfaceArea (m2) = NetSurfaceArea (m2) | GrossVolume (m3) = NetVolume (m3)
5 x 77_Balk_ALG | 01 1e tussenverdieping | 2.4 | 1200 | 900 | 0.09 | 2.58 | 0.108
77_Balk_ALG | 01 1e tussenverdieping | 2.37 | 1185 | 900 | 0.09 | 2.55 | 0.10665
77_Balk_ALG | 02 2e verdieping | 2.4 | 1200 | 900.001 | 0.0900001 | 2.58 | 0.108
5 x 77_Balk_ALG | 02 2e verdieping | 2.4 | 1200 | 900 | 0.09 | 2.58 | 0.108

# IfcBeam: ALG - ALGEMEEN 50 x 2518, 77_Balk_ALG
In: 02 2e verdieping
Type - PredefinedType: BEAM
Material: ALG - ALGEMEEN
Pset_BeamCommon - Slope: 0 deg; IsExternal: no; LoadBearing: yes; Reference: ALG - ALGEMEEN 50 x 2518
BaseQuantities - NetSurfaceAreaExtrudedSides: 8.22798 m2; Length: 1620 mm; Width: 50 mm; Depth: 2517.5 mm; CrossSectionArea: 0.125875 m2; OuterSurfaceArea: 8.22798 m2; TotalSurfaceArea: 8.47973 m2; GrossSurfaceArea: 8.47973 m2; GrossVolume: 0.229092 m3; NetSurfaceArea: 8.47973 m2; NetVolume: 0.203674 m3

# IfcBeam: ALG - ALGEMEEN 900 x 550, Info_Balk_ALG
In: 01 1e verdieping
Type - PredefinedType: BEAM
Material: ALG - ALGEMEEN
Pset_BeamCommon - Slope: 0 deg; IsExternal: no; LoadBearing: yes; Reference: ALG - ALGEMEEN 900 x 550
BaseQuantities - NetSurfaceAreaExtrudedSides: 64.8844 m2; Length: 27113.3 mm; Width: 900 mm; Depth: 550 mm; CrossSectionArea: 0.495 m2; OuterSurfaceArea: 64.8844 m2; TotalSurfaceArea: 65.8744 m2; GrossSurfaceArea: 65.8744 m2; GrossVolume: 13.9813 m3; NetSurfaceArea: 65.8744 m2; NetVolume: 10.081 m3

# IfcBeam: ALG - BUITENAFWERKING 120 x 230 (6)
In: 04 4e verdieping
Type - PredefinedType: BEAM
Material: ALG - BUITENAFWERKING
Pset_BeamCommon - IsExternal: no; LoadBearing: no; Reference: ALG - BUITENAFWERKING 120 x 230
BaseQuantities - Width: 120 mm; Depth: 230 mm; CrossSectionArea: 0.0276 m2
Name | Slope (deg) | NetSurfaceAreaExtrudedSides (m2) = OuterSurfaceArea (m2) | Length (mm) | TotalSurfaceArea (m2) = GrossSurfaceArea (m2) = NetSurfaceArea (m2) | GrossVolume (m3) | NetVolume (m3)
47_Balk_ALG | 0 | 5.35987 | 7776.96 | 5.41507 | 0.211332 | 0.211332
47_Balk_ALG | 0 | 2.89469 | 4299.54 | 2.94989 | 0.115985 | 0.115982
47_Balk_ALG | 35.85 | 2.33409 | 3899.11 | 2.38929 | 0.104295 | 0.0931982
47_Balk_ALG | 0 | 2.94163 | 4299.54 | 2.99683 | 0.115985 | 0.115985
47_Balk_ALG | -35.8508 | 1.81897 | 3898.99 | 1.87417 | 0.105559 | 0.105513
47_Balk_ALG | 0 | 1.90159 | 2869.99 | 1.95679 | 0.0761841 | 0.0761825

# IfcBeam: ALG - BUITENAFWERKING 120 x 300, 47_Balk_ALG
In: 04 4e verdieping
Type - PredefinedType: BEAM
Material: ALG - BUITENAFWERKING
Pset_BeamCommon - Slope: 0 deg; IsExternal: no; LoadBearing: no; Reference: ALG - BUITENAFWERKING 120 x 300
BaseQuantities - NetSurfaceAreaExtrudedSides: 5.66682 m2; Length: 6825.58 mm; Width: 120 mm; Depth: 300.001 mm; CrossSectionArea: 0.0360001 m2; OuterSurfaceArea: 5.66682 m2; TotalSurfaceArea: 5.73882 m2; GrossSurfaceArea: 5.73882 m2; GrossVolume: 0.245721 m3; NetSurfaceArea: 5.73882 m2; NetVolume: 0.2429 m3

# IfcBeam: ALG - BUITENAFWERKING 120 x 329 (5)
In: 04 4e verdieping
Type - PredefinedType: BEAM
Material: ALG - BUITENAFWERKING
Pset_BeamCommon - Slope: 0 deg; IsExternal: no; LoadBearing: no; Reference: ALG - BUITENAFWERKING 120 x 329
BaseQuantities - Width: 120 mm
Name | NetSurfaceAreaExtrudedSides (m2) = OuterSurfaceArea (m2) | Length (mm) | Depth (mm) | CrossSectionArea (m2) | TotalSurfaceArea (m2) = GrossSurfaceArea (m2) = NetSurfaceArea (m2) | GrossVolume (m3) | NetVolume (m3)
47_Balk_ALG | 42.9295 | 58390 | 329.252 | 0.0395103 | 43.0085 | 2.30226 | 2.15622
47_Balk_ALG | 15.5458 | 20310 | 329.3 | 0.039516 | 15.6248 | 0.797828 | 0.721311
47_Balk_ALG | 40.4395 | 58390 | 329.3 | 0.039516 | 40.5185 | 2.3026 | 1.85002
47_Balk_ALG | 6.84469 | 7995 | 329.3 | 0.039516 | 6.92372 | 0.313559 | 0.296417
47_Balk_ALG | 4.4974 | 5159.1 | 329.3 | 0.039516 | 4.57643 | 0.201496 | 0.196549

# IfcBeam: ALG - BUITENAFWERKING 120 x 330 (2)
In: 02 2e verdieping
Type - PredefinedType: BEAM
Material: ALG - BUITENAFWERKING
Pset_BeamCommon - Slope: 0 deg; IsExternal: no; LoadBearing: no; Reference: ALG - BUITENAFWERKING 120 x 330
BaseQuantities - Width: 120 mm; Depth: 330 mm; CrossSectionArea: 0.0396 m2
Name | NetSurfaceAreaExtrudedSides (m2) = OuterSurfaceArea (m2) | Length (mm) | TotalSurfaceArea (m2) = GrossSurfaceArea (m2) = NetSurfaceArea (m2) | GrossVolume (m3) | NetVolume (m3)
47_Balk_ALG | 8.94293 | 13975 | 9.02213 | 0.55341 | 0.435943
47_Balk_ALG | 7.09653 | 7885.04 | 7.17573 | 0.312247 | 0.312247

# IfcBeam: ALG - BUITENAFWERKING 120 x 340, 47_Balk_ALG
In: 02 2e verdieping
Type - PredefinedType: BEAM
Material: ALG - BUITENAFWERKING
Pset_BeamCommon - Slope: 0 deg; IsExternal: no; LoadBearing: no; Reference: ALG - BUITENAFWERKING 120 x 340
BaseQuantities - NetSurfaceAreaExtrudedSides: 7.62841 m2; Length: 10229.9 mm; Width: 120 mm; Depth: 339.999 mm; CrossSectionArea: 0.0407998 m2; OuterSurfaceArea: 7.62841 m2; TotalSurfaceArea: 7.71001 m2; GrossSurfaceArea: 7.71001 m2; GrossVolume: 0.41738 m3; NetSurfaceArea: 7.71001 m2; NetVolume: 0.358622 m3

# IfcBeam: ALG - BUITENAFWERKING 120 x 359, 47_Balk_ALG
In: 02 2e verdieping
Type - PredefinedType: BEAM
Material: ALG - BUITENAFWERKING
Pset_BeamCommon - Slope: 0 deg; IsExternal: no; LoadBearing: no; Reference: ALG - BUITENAFWERKING 120 x 359
BaseQuantities - NetSurfaceAreaExtrudedSides: 24.0627 m2; Length: 32090 mm; Width: 120 mm; Depth: 359.111 mm; CrossSectionArea: 0.0430933 m2; OuterSurfaceArea: 24.0627 m2; TotalSurfaceArea: 24.1489 m2; GrossSurfaceArea: 24.1489 m2; GrossVolume: 1.38286 m3; NetSurfaceArea: 24.1489 m2; NetVolume: 1.15479 m3

# IfcBeam: ALG - BUITENAFWERKING 145 x 230, 47_Balk_ALG
In: 04 4e verdieping
Type - PredefinedType: BEAM
Material: ALG - BUITENAFWERKING
Pset_BeamCommon - Slope: 0 deg; IsExternal: no; LoadBearing: no; Reference: ALG - BUITENAFWERKING 145 x 230
BaseQuantities - NetSurfaceAreaExtrudedSides: 5.66513 m2; Length: 7613.51 mm; Width: 145 mm; Depth: 230 mm; CrossSectionArea: 0.03335 m2; OuterSurfaceArea: 5.66513 m2; TotalSurfaceArea: 5.73183 m2; GrossSurfaceArea: 5.73183 m2; GrossVolume: 0.25191 m3; NetSurfaceArea: 5.73183 m2; NetVolume: 0.25191 m3

# IfcBeam: ALG - BUITENAFWERKING 145 x 332 (2)
In: 02 2e verdieping
Type - PredefinedType: BEAM
Material: ALG - BUITENAFWERKING
Pset_BeamCommon - Slope: 0 deg; IsExternal: no; LoadBearing: no; Reference: ALG - BUITENAFWERKING 145 x 332
BaseQuantities - Length: 16320 mm
Name | NetSurfaceAreaExtrudedSides (m2) = OuterSurfaceArea (m2) | Width (mm) | Depth (mm) | CrossSectionArea (m2) | TotalSurfaceArea (m2) = GrossSurfaceArea (m2) = NetSurfaceArea (m2) | GrossVolume (m3) | NetVolume (m3)
47_Balk_ALG | 15.3631 | 145 | 332.065 | 0.0481495 | 15.4594 | 0.785801 | 0.780149
47_Balk_ALG | 15.4885 | 145.002 | 332.067 | 0.0481502 | 15.5848 | 0.785813 | 0.785018

# IfcBeam: ALG - BUITENAFWERKING 159 x 360 (2)
Type - PredefinedType: BEAM
Material: ALG - BUITENAFWERKING
Pset_BeamCommon - Slope: 0 deg; IsExternal: no; LoadBearing: no; Reference: ALG - BUITENAFWERKING 159 x 360
BaseQuantities - Width: 159 mm; Depth: 360 mm; CrossSectionArea: 0.05724 m2
Name | In | NetSurfaceAreaExtrudedSides (m2) = OuterSurfaceArea (m2) | Length (mm) | TotalSurfaceArea (m2) = GrossSurfaceArea (m2) = NetSurfaceArea (m2) | GrossVolume (m3) | NetVolume (m3)
47_Balk_ALG | 02 2e verdieping | 10.013 | 10017.9 | 10.1275 | 0.585562 | 0.560907
47_Balk_ALG | 04 4e verdieping | 6.86584 | 6615.52 | 6.98032 | 0.390696 | 0.378609

# IfcBeam: ALG - BUITENAFWERKING 167 x 276, 47_Balk_ALG
In: 01 1e verdieping
Type - PredefinedType: BEAM
Material: ALG - BUITENAFWERKING
Pset_BeamCommon - Slope: 0 deg; IsExternal: no; LoadBearing: no; Reference: ALG - BUITENAFWERKING 167 x 276
BaseQuantities - NetSurfaceAreaExtrudedSides: 18.6204 m2; Length: 23773.8 mm; Width: 167.01 mm; Depth: 275.996 mm; CrossSectionArea: 0.0460939 m2; OuterSurfaceArea: 18.6204 m2; TotalSurfaceArea: 18.7126 m2; GrossSurfaceArea: 18.7126 m2; GrossVolume: 1.09198 m3; NetSurfaceArea: 18.7126 m2; NetVolume: 1.06291 m3

# IfcBeam: ALG - BUITENAFWERKING 167 x 277, 47_Balk_ALG
In: 01 1e verdieping
Type - PredefinedType: BEAM
Material: ALG - BUITENAFWERKING
Pset_BeamCommon - Slope: 0 deg; IsExternal: no; LoadBearing: no; Reference: ALG - BUITENAFWERKING 167 x 277
BaseQuantities - NetSurfaceAreaExtrudedSides: 3.3104 m2; Length: 4467.18 mm; Width: 167.01 mm; Depth: 276.902 mm; CrossSectionArea: 0.0462453 m2; OuterSurfaceArea: 3.3104 m2; TotalSurfaceArea: 3.40289 m2; GrossSurfaceArea: 3.40289 m2; GrossVolume: 0.202724 m3; NetSurfaceArea: 3.40289 m2; NetVolume: 0.189027 m3

# IfcBeam: ALG - BUITENAFWERKING 170 x 18 (6)
Type - PredefinedType: BEAM
Material: ALG - BUITENAFWERKING
Pset_BeamCommon - Slope: 0 deg; IsExternal: no; LoadBearing: no; Reference: ALG - BUITENAFWERKING 170 x 18
Name | In | NetSurfaceAreaExtrudedSides (m2) = OuterSurfaceArea (m2) | Length (mm) | Width (mm) | Depth (mm) | CrossSectionArea (m2) | TotalSurfaceArea (m2) = GrossSurfaceArea (m2) = NetSurfaceArea (m2) | GrossVolume (m3) | NetVolume (m3)
47_Balk_ALG | 02 2e verdieping | 6.08694 | 16200 | 170.01 | 17.9988 | 0.00305996 | 6.09306 | 0.0495715 | 0.0495514
2 x 47_Balk_ALG | 04 4e verdieping | 21.9179 | 58461.4 | 170 | 18.0026 | 0.00306045 | 21.924 | 0.178398 | 0.178398
47_Balk_ALG | 04 4e verdieping | 2.99233 | 8043.2 | 170 | 18.0026 | 0.00306045 | 2.99845 | 0.0243556 | 0.0243556
47_Balk_ALG | 04 4e verdieping | 7.60901 | 20406.4 | 170 | 18.0026 | 0.00306045 | 7.61513 | 0.0619326 | 0.0619326
47_Balk_ALG | 04 4e verdieping | 0.864801 | 2384.97 | 170 | 18.0026 | 0.00306045 | 0.870922 | 0.00703894 | 0.00703894

# IfcBeam: ALG - BUITENAFWERKING 175 x 18, 47_Balk_ALG
In: 02 2e verdieping
Type - PredefinedType: BEAM
Material: ALG - BUITENAFWERKING
Pset_BeamCommon - Slope: 0 deg; IsExternal: no; LoadBearing: no; Reference: ALG - BUITENAFWERKING 175 x 18
BaseQuantities - NetSurfaceAreaExtrudedSides: 6.25622 m2; Length: 16200 mm; Width: 175.26 mm; Depth: 17.9977 mm; CrossSectionArea: 0.00315427 m2; OuterSurfaceArea: 6.25622 m2; TotalSurfaceArea: 6.26253 m2; GrossSurfaceArea: 6.26253 m2; GrossVolume: 0.0510992 m3; NetSurfaceArea: 6.26253 m2; NetVolume: 0.0510706 m3

# IfcBeam: ALG - BUITENAFWERKING 190 x 18 (2)
In: 01 1e verdieping
Type - PredefinedType: BEAM
Material: ALG - BUITENAFWERKING
Pset_BeamCommon - Slope: 0 deg; IsExternal: no; LoadBearing: no; Reference: ALG - BUITENAFWERKING 190 x 18
Name | NetSurfaceAreaExtrudedSides (m2) = OuterSurfaceArea (m2) | Length (mm) | Width (mm) | Depth (mm) | CrossSectionArea (m2) | TotalSurfaceArea (m2) = GrossSurfaceArea (m2) = NetSurfaceArea (m2) | GrossVolume (m3) = NetVolume (m3)
47_Balk_ALG | 9.86065 | 23769.6 | 190.252 | 18.0022 | 0.00342497 | 9.8675 | 0.0810844
47_Balk_ALG | 1.82969 | 4488.18 | 190.248 | 17.9999 | 0.00342446 | 1.83654 | 0.0150438

# IfcBeam: ALG - BUITENAFWERKING 235 x 80 (14)
In: 04 4e verdieping
Type - PredefinedType: BEAM
Material: ALG - BUITENAFWERKING
Pset_BeamCommon - Slope: 0 deg; IsExternal: no; LoadBearing: no; Reference: ALG - BUITENAFWERKING 235 x 80
BaseQuantities - NetSurfaceAreaExtrudedSides: 0.188285 m2; Length: 300 mm; Width: 235 mm; Depth: 80 mm; CrossSectionArea: 0.0188 m2; OuterSurfaceArea: 0.188285 m2; TotalSurfaceArea: 0.225885 m2; GrossSurfaceArea: 0.225885 m2; GrossVolume: 0.00564 m3; NetSurfaceArea: 0.225885 m2; NetVolume: 0.00561139 m3

# IfcBeam: ALG - BUITENAFWERKING 50 x 400 (8)
In: 03 3e tussenverdieping
Type - PredefinedType: BEAM
Material: ALG - BUITENAFWERKING
BaseQuantities - NetSurfaceAreaExtrudedSides: 0.225 m2; Length: 250 mm; Width: 50 mm; Depth: 400 mm; CrossSectionArea: 0.02 m2; OuterSurfaceArea: 0.225 m2; TotalSurfaceArea: 0.265 m2; GrossSurfaceArea: 0.265 m2; GrossVolume: 0.005 m3; NetSurfaceArea: 0.265 m2; NetVolume: 0.005 m3
Pset_BeamCommon - Slope: 0 deg; IsExternal: no; LoadBearing: no; Reference: ALG - BUITENAFWERKING 50 x 400

# IfcBeam: ALG - BUITENAFWERKING 95 x 95 (2)
Type - PredefinedType: BEAM
Material: ALG - BUITENAFWERKING
Pset_BeamCommon - Slope: 0 deg; IsExternal: no; LoadBearing: no; Reference: ALG - BUITENAFWERKING 95 x 95
BaseQuantities - Length: 19880 mm; Width: 95 mm; Depth: 95 mm; CrossSectionArea: 0.009025 m2; GrossVolume: 0.179417 m3
Name | In | NetSurfaceAreaExtrudedSides (m2) = OuterSurfaceArea (m2) | TotalSurfaceArea (m2) = GrossSurfaceArea (m2) = NetSurfaceArea (m2) | NetVolume (m3)
41_Balk_ALG | 01 1e verdieping | 7.40024 | 7.41829 | 0.174626
41_Balk_ALG | 03 3e tussenverdieping | 7.41967 | 7.43772 | 0.175544

# IfcBeam: Aluminium daktrim (hoofdtrap) 45 x 485 (7)
In: 04 4e verdieping
Type - PredefinedType: BEAM
Pset_BeamCommon - IsExternal: no; LoadBearing: no; Reference: Aluminium daktrim (hoofdtrap) 45 x 485
BaseQuantities - CrossSectionArea: 0.000818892 m2
Name | Slope (deg) | NetSurfaceAreaExtrudedSides (m2) = OuterSurfaceArea (m2) | Length (mm) | TotalSurfaceArea (m2) = GrossSurfaceArea (m2) = NetSurfaceArea (m2) | GrossVolume (m3) = NetVolume (m3)
47_Balk_Aluminium | 0 | 5.84333 | 4399.95 | 5.84497 | 0.00354986
47_Balk_Aluminium | 0 | 5.83357 | 4392.74 | 5.8352 | 0.00354393
47_Balk_Aluminium | 0 | 10.606 | 7846.92 | 10.6077 | 0.00644102
47_Balk_Aluminium | 0 | 10.2705 | 7593.51 | 10.2721 | 0.00623731
47_Balk_Aluminium | -35.85 | 5.17675 | 3981.55 | 5.17839 | 0.0031439
47_Balk_Aluminium | 0 | 3.91115 | 2974.72 | 3.91279 | 0.002374
47_Balk_Aluminium | -35.85 | 5.14705 | 4057.79 | 5.14869 | 0.00312437

# IfcBeam: Aluminium daktrim 45 x 250 (13)
Type - PredefinedType: BEAM
BaseQuantities - CrossSectionArea: 0.000534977 m2
Pset_BeamCommon - Slope: 0 deg; IsExternal: no; LoadBearing: no; Reference: Aluminium daktrim 45 x 250
Name | In | NetSurfaceAreaExtrudedSides (m2) = OuterSurfaceArea (m2) | Length (mm) | TotalSurfaceArea (m2) = GrossSurfaceArea (m2) = NetSurfaceArea (m2) | GrossVolume (m3) | NetVolume (m3)
47_Balk_Aluminium | 03 3e tussenverdieping | 14.4204 | 16440 | 14.4214 | 0.00883763 | 0.00883763
47_Balk_Aluminium | 03 3e tussenverdieping | 12.4132 | 14146 | 12.4143 | 0.00760811 | 0.00760757
47_Balk_Aluminium | 03 3e tussenverdieping | 14.4161 | 16438.8 | 14.4172 | 0.00885199 | 0.00884561
47_Balk_Aluminium | 03 3e tussenverdieping | 28.4613 | 32432 | 28.4624 | 0.0174428 | 0.0174428
47_Balk_Aluminium | 03 3e tussenverdieping | 3.93521 | 4490 | 3.93628 | 0.00241171 | 0.00241171
47_Balk_Aluminium | 03 3e tussenverdieping | 20.8991 | 23819 | 20.9002 | 0.0128082 | 0.0128082
47_Balk_Aluminium | 03 3e tussenverdieping | 3.82207 | 4480 | 3.82314 | 0.00240633 | 0.00234467
47_Balk_Aluminium | 03 3e tussenverdieping | 7.17768 | 8175.02 | 7.17875 | 0.00439893 | 0.00439892
2 x 47_Balk_Aluminium | 04 4e verdieping | 51.3359 | 58485 | 51.337 | 0.0314617 | 0.0314617
47_Balk_Aluminium | 04 4e verdieping | 17.9235 | 20430 | 17.9246 | 0.0109846 | 0.0109846
47_Balk_Aluminium | 04 4e verdieping | 7.06529 | 8055 | 7.06636 | 0.00433002 | 0.00433002
47_Balk_Aluminium | 04 4e verdieping | 4.57536 | 5219.1 | 4.57643 | 0.00280404 | 0.00280404

# IfcBeam: Aluminium waterslag vliesgevel 63 x 132, 47_Balk_Aluminium
In: 02 2e verdieping
Type - PredefinedType: BEAM
Material: aluminium
Pset_BeamCommon - Slope: 0 deg; IsExternal: no; LoadBearing: no; Reference: Aluminium waterslag vliesgevel 63 x 132
BaseQuantities - NetSurfaceAreaExtrudedSides: 4.18195 m2; Length: 10229.9 mm; CrossSectionArea: 0.000403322 m2; OuterSurfaceArea: 4.18195 m2; TotalSurfaceArea: 4.18276 m2; GrossSurfaceArea: 4.18276 m2; GrossVolume: 0.00412597 m3; NetSurfaceArea: 4.18276 m2; NetVolume: 0.00412445 m3

# IfcBeam: Betonbanden 160 x 760 (25)
Type - PredefinedType: BEAM
Material: beton_gewapend_prefab
Pset_BeamCommon - Slope: 0 deg; IsExternal: no; LoadBearing: no; Reference: Betonbanden 160 x 760
BaseQuantities - CrossSectionArea: 0.0571 m2
Name | In | NetSurfaceAreaExtrudedSides (m2) = OuterSurfaceArea (m2) | Length (mm) | TotalSurfaceArea (m2) = GrossSurfaceArea (m2) = NetSurfaceArea (m2) | GrossVolume (m3) | NetVolume (m3)
41_Balk_Betonbanden | 00 Begane grond | 9.2869 | 4650 | 9.4011 | 0.26279 | 0.26279
41_Balk_Betonbanden | 00 Begane grond | 9.1859 | 4600 | 9.3001 | 0.259935 | 0.259935
41_Balk_Betonbanden | 00 Begane grond | 48.3669 | 24049.1 | 48.4811 | 1.36775 | 1.36775
41_Balk_Betonbanden | 01 1e verdieping | 37.0993 | 20650 | 37.2135 | 1.17367 | 1.08546
2 x 41_Balk_Betonbanden | 01 1e verdieping | 24.3921 | 12310 | 24.5063 | 0.700176 | 0.689138
41_Balk_Betonbanden | 01 1e verdieping | 77.5774 | 40645.5 | 77.6916 | 2.31813 | 2.2778
41_Balk_Betonbanden | 01 1e verdieping | 39.0888 | 20590 | 39.203 | 1.17297 | 1.14384
41_Balk_Betonbanden | 01 1e verdieping | 67.2536 | 35964.5 | 67.3678 | 2.05357 | 1.87375
41_Balk_Betonbanden | 01 1e verdieping | 53.2268 | 30275 | 53.341 | 1.7287 | 1.48287
41_Balk_Betonbanden | 01 1e verdieping | 27.1372 | 16660 | 27.2514 | 0.947988 | 0.819529
41_Balk_Betonbanden | 01 1e verdieping | 55.7181 | 32662 | 55.8323 | 1.85955 | 1.62924
41_Balk_Betonbanden | 01 1e verdieping | 3.18041 | 1720.92 | 3.29461 | 0.0955403 | 0.0899545
41_Balk_Betonbanden | 01 1e verdieping | 3.822 | 2275 | 3.9362 | 0.129902 | 0.102147
41_Balk_Betonbanden | 02 2e verdieping | 40.464 | 20650 | 40.5782 | 1.17367 | 1.14256
41_Balk_Betonbanden | 02 2e verdieping | 81.3706 | 40335 | 81.4848 | 2.3004 | 2.3004
41_Balk_Betonbanden | 02 2e verdieping | 67.8576 | 36335 | 67.9718 | 2.072 | 1.89093
41_Balk_Betonbanden | 03 3e tussenverdieping | 64.7142 | 32550 | 64.8284 | 1.8586 | 1.8275
41_Balk_Betonbanden | 03 3e tussenverdieping | 33.4088 | 16660 | 33.523 | 0.951 | 0.946536
41_Balk_Betonbanden | 03 3e tussenverdieping | 65.751 | 32550 | 65.8652 | 1.8586 | 1.8586
41_Balk_Betonbanden | 03 3e tussenverdieping | 33.4077 | 16660 | 33.5219 | 0.951 | 0.946304
41_Balk_Betonbanden | 04 4e verdieping | 39.3442 | 20650 | 39.4584 | 1.17367 | 1.11349
41_Balk_Betonbanden | 04 4e verdieping | 117.996 | 58705 | 118.11 | 3.34661 | 3.33539
41_Balk_Betonbanden | 04 4e verdieping | 41.5008 | 20650 | 41.615 | 1.17367 | 1.17367
41_Balk_Betonbanden | 04 4e verdieping | 118.365 | 58705 | 118.479 | 3.34661 | 3.34647

# IfcBeam: HEB160 160 x 160 (7)
In: 04 4e verdieping
Type - PredefinedType: BEAM
Material: staal C
Pset_BeamCommon - Slope: 0 deg; IsExternal: no; LoadBearing: yes; Reference: HEB160 160 x 160
BaseQuantities - CrossSectionArea: 0.005232 m2
Name | NetSurfaceAreaExtrudedSides (m2) = OuterSurfaceArea (m2) | Length (mm) | TotalSurfaceArea (m2) = GrossSurfaceArea (m2) = NetSurfaceArea (m2) | GrossVolume (m3) | NetVolume (m3)
3 x Info_Balk_HEB160 | 7.26294 | 7770.5 | 7.2734 | 0.040705 | 0.0402124
Info_Balk_HEB160 | 1.3047 | 1382.1 | 1.31516 | 0.00723114 | 0.00723114
3 x Info_Balk_HEB160 | 7.34432 | 7780 | 7.35478 | 0.040705 | 0.040705

# IfcBeam: HEB220 220 x 220 (25)
Type - PredefinedType: BEAM
Material: staal C
Pset_BeamCommon - Slope: 0 deg; IsExternal: no; LoadBearing: yes; Reference: HEB220 220 x 220
BaseQuantities - CrossSectionArea: 0.008826 m2
Name | In | NetSurfaceAreaExtrudedSides (m2) = OuterSurfaceArea (m2) | Length (mm) | TotalSurfaceArea (m2) = GrossSurfaceArea (m2) = NetSurfaceArea (m2) | GrossVolume (m3) | NetVolume (m3)
28_Balk_HEB220 | 01 1e tussenverdieping | 13.0845 | 10057.3 | 13.1022 | 0.0887654 | 0.0887654
28_Balk_HEB220 | 03 3e tussenverdieping | 13.0845 | 10057.3 | 13.1022 | 0.0887654 | 0.0887654
8 x Info_Balk_HEB220 | 04 4e verdieping | 8.3264 | 6400 | 8.34405 | 0.0564864 | 0.0564864
Info_Balk_HEB220 | 04 4e verdieping | 7.7519 | 5960 | 7.76955 | 0.052603 | 0.0525873
Info_Balk_HEB220 | 04 4e verdieping | 10.3079 | 7985.79 | 10.3256 | 0.070608 | 0.0700249
Info_Balk_HEB220 | 04 4e verdieping | 10.3202 | 8000 | 10.3379 | 0.070608 | 0.0700387
3 x Info_Balk_HEB220 | 04 4e verdieping | 8.27905 | 6400 | 8.2967 | 0.0564864 | 0.0559938
9 x Info_Balk_HEB220 | 04 4e verdieping | 7.75396 | 5960 | 7.77161 | 0.052603 | 0.052603

# IfcBeam: Profiel H algemeen 120 x 120, 28_Balk_Profiel
In: 04 4e verdieping
Type - PredefinedType: BEAM
Material: staal C
Pset_BeamCommon - Slope: 0 deg; IsExternal: no; LoadBearing: yes; Reference: Profiel H algemeen 120 x 120
BaseQuantities - NetSurfaceAreaExtrudedSides: 1.26168 m2; Length: 1833 mm; CrossSectionArea: 0.003277 m2; OuterSurfaceArea: 1.26168 m2; TotalSurfaceArea: 1.26824 m2; GrossSurfaceArea: 1.26824 m2; GrossVolume: 0.00622904 m3; NetSurfaceArea: 1.26824 m2; NetVolume: 0.00583032 m3

# IfcBeam: Profiel H algemeen 140 x 133 (5)
Type - PredefinedType: BEAM
Material: staal C
Pset_BeamCommon - Slope: 0 deg; IsExternal: no; LoadBearing: yes; Reference: Profiel H algemeen 140 x 133
BaseQuantities - CrossSectionArea: 0.00301801 m2
Name | In | NetSurfaceAreaExtrudedSides (m2) = OuterSurfaceArea (m2) | Length (mm) | TotalSurfaceArea (m2) = GrossSurfaceArea (m2) = NetSurfaceArea (m2) | GrossVolume (m3) | NetVolume (m3)
28_Balk_Profiel | -1 Fundering | 1.72676 | 2197 | 1.73279 | 0.00647362 | 0.00640391
28_Balk_Profiel | -1 Fundering | 1.4803 | 1895 | 1.48633 | 0.00550786 | 0.00547866
28_Balk_Profiel | -1 Fundering | 1.70673 | 2142.25 | 1.71277 | 0.00664198 | 0.00630527
28_Balk_Profiel | 01 1e tussenverdieping | 1.55775 | 1974 | 1.56378 | 0.00597565 | 0.00574953
28_Balk_Profiel | 02 2e verdieping | 1.55775 | 1974 | 1.56378 | 0.00620178 | 0.00574953

# IfcBeam: Profiel H algemeen 140 x 140 (6)
In: 04 4e verdieping
Type - PredefinedType: BEAM
Material: staal C
Pset_BeamCommon - Slope: 0 deg; IsExternal: no; LoadBearing: yes; Reference: Profiel H algemeen 140 x 140
BaseQuantities - CrossSectionArea: 0.004172 m2
Name | NetSurfaceAreaExtrudedSides (m2) = OuterSurfaceArea (m2) | Length (mm) | TotalSurfaceArea (m2) = GrossSurfaceArea (m2) = NetSurfaceArea (m2) | GrossVolume (m3) | NetVolume (m3)
4 x 28_Balk_Profiel | 3.0149 | 3650 | 3.02324 | 0.0152278 | 0.0152278
2 x 28_Balk_Profiel | 2.57907 | 3218 | 2.58741 | 0.0139308 | 0.0129786

# IfcBeam: Profiel H algemeen 160 x 152 (8)
Type - PredefinedType: BEAM
Material: staal C
Pset_BeamCommon - Slope: 0 deg; IsExternal: no; LoadBearing: yes; Reference: Profiel H algemeen 160 x 152
BaseQuantities - NetSurfaceAreaExtrudedSides: 3.40181 m2; Length: 3650 mm; CrossSectionArea: 0.00368423 m2; OuterSurfaceArea: 3.40181 m2; TotalSurfaceArea: 3.40918 m2; GrossSurfaceArea: 3.40918 m2; GrossVolume: 0.0134474 m3; NetSurfaceArea: 3.40918 m2; NetVolume: 0.0134474 m3
Name | In
4 x 28_Balk_Profiel | 01 1e tussenverdieping
4 x 28_Balk_Profiel | 02 2e verdieping

# IfcBeam: Profiel H algemeen 160 x 160 (3)
In: 04 4e verdieping
Type - PredefinedType: BEAM
Material: staal C
Pset_BeamCommon - Slope: -1 deg; IsExternal: no; LoadBearing: yes; Reference: Profiel H algemeen 160 x 160
BaseQuantities - NetSurfaceAreaExtrudedSides: 1.79388 m2; Length: 1903.08 mm; CrossSectionArea: 0.00584018 m2; OuterSurfaceArea: 1.79388 m2; TotalSurfaceArea: 1.80556 m2; GrossSurfaceArea: 1.80556 m2; GrossVolume: 0.011098 m3; NetSurfaceArea: 1.80556 m2; NetVolume: 0.011098 m3

# IfcBeam: Profiel H algemeen 180 x 171 (4)
Type - PredefinedType: BEAM
Material: staal C
Pset_BeamCommon - Slope: 0 deg; IsExternal: no; LoadBearing: yes; Reference: Profiel H algemeen 180 x 171
BaseQuantities - NetSurfaceAreaExtrudedSides: 3.8325 m2; Length: 3650 mm; CrossSectionArea: 0.00433204 m2; OuterSurfaceArea: 3.8325 m2; TotalSurfaceArea: 3.84117 m2; GrossSurfaceArea: 3.84117 m2; GrossVolume: 0.0158119 m3; NetSurfaceArea: 3.84117 m2; NetVolume: 0.0158119 m3
Name | In
2 x 28_Balk_Profiel | 01 1e tussenverdieping
2 x 28_Balk_Profiel | 02 2e verdieping

# IfcBeam: Profiel H algemeen 180 x 180, 28_Balk_Profiel
In: 02 2e verdieping
Type - PredefinedType: BEAM
Material: staal C
BaseQuantities - NetSurfaceAreaExtrudedSides: 3.95968 m2; Length: 3725 mm; CrossSectionArea: 0.00633203 m2; OuterSurfaceArea: 3.95968 m2; TotalSurfaceArea: 3.97234 m2; GrossSurfaceArea: 3.97234 m2; GrossVolume: 0.0235868 m3; NetSurfaceArea: 3.97234 m2; NetVolume: 0.0235868 m3
Pset_BeamCommon - Slope: 0 deg; IsExternal: no; LoadBearing: yes; Reference: Profiel H algemeen 180 x 180

# IfcBeam: Profiel H algemeen 200 x 200 (6)
Type - PredefinedType: BEAM
Material: staal C
BaseQuantities - CrossSectionArea: 0.00753 m2
Pset_BeamCommon - Slope: 0 deg; IsExternal: no; LoadBearing: yes; Reference: Profiel H algemeen 200 x 200
Name | In | NetSurfaceAreaExtrudedSides (m2) = OuterSurfaceArea (m2) | Length (mm) | TotalSurfaceArea (m2) = GrossSurfaceArea (m2) = NetSurfaceArea (m2) | GrossVolume (m3) | NetVolume (m3)
28_Balk_Profiel | 01 1e tussenverdieping | 4.67303 | 4200 | 4.68809 | 0.0313333 | 0.0289079
2 x 28_Balk_Profiel | 01 1e tussenverdieping | 6.63278 | 5611.49 | 6.64784 | 0.0422545 | 0.0422545
2 x 28_Balk_Profiel | 02 2e tussenverdieping | 6.63278 | 5611.49 | 6.64784 | 0.0422545 | 0.0422545
28_Balk_Profiel | 02 2e tussenverdieping | 4.55654 | 3991 | 4.5716 | 0.0313338 | 0.0289062

# IfcBeam: Profiel IPN algemeen 100 x 200 (3)
In: 02 2e verdieping
Type - PredefinedType: BEAM
Material: staal C
Pset_BeamCommon - Slope: 0 deg; IsExternal: no; LoadBearing: yes; Reference: Profiel IPN algemeen 100 x 200
BaseQuantities - CrossSectionArea: 0.00272488 m2
Name | NetSurfaceAreaExtrudedSides (m2) = OuterSurfaceArea (m2) | Length (mm) | TotalSurfaceArea (m2) = GrossSurfaceArea (m2) = NetSurfaceArea (m2) | GrossVolume (m3) | NetVolume (m3)
28_Balk_Profiel | 12.8212 | 16340 | 12.8266 | 0.0443883 | 0.0442792
28_Balk_Profiel | 25.4252 | 32282.5 | 25.4306 | 0.0878297 | 0.0878297
28_Balk_Profiel | 12.799 | 16287.2 | 12.8045 | 0.0444761 | 0.0441914

# IfcBeam: Profiel IPN algemeen 100 x 96, 28_Balk_Profiel
In: 02 2e verdieping
Type - PredefinedType: BEAM
Material: staal C
Pset_BeamCommon - Slope: 0 deg; IsExternal: no; LoadBearing: yes; Reference: Profiel IPN algemeen 100 x 96
BaseQuantities - NetSurfaceAreaExtrudedSides: 9.31203 m2; Length: 16000 mm; CrossSectionArea: 0.002 m2; OuterSurfaceArea: 9.31203 m2; TotalSurfaceArea: 9.31603 m2; GrossSurfaceArea: 9.31603 m2; GrossVolume: 0.032 m3; NetSurfaceArea: 9.31603 m2; NetVolume: 0.032 m3

# IfcBeam: Profiel IPN algemeen 113 x 260 (7)
In: 02 2e verdieping
Type - PredefinedType: BEAM
Material: staal C
Pset_BeamCommon - Slope: 0 deg; IsExternal: no; LoadBearing: yes; Reference: Profiel IPN algemeen 113 x 260
Name | NetSurfaceAreaExtrudedSides (m2) = OuterSurfaceArea (m2) | Length (mm) | CrossSectionArea (m2) | TotalSurfaceArea (m2) = GrossSurfaceArea (m2) = NetSurfaceArea (m2) | GrossVolume (m3) = NetVolume (m3)
28_Balk_Profiel | 30.6598 | 32165 | 0.00536555 | 30.6705 | 0.172583
5 x 28_Balk_Profiel | 30.6597 | 32165 | 0.00536554 | 30.6705 | 0.172582
28_Balk_Profiel | 15.5277 | 16290 | 0.00536555 | 15.5384 | 0.0874047

# IfcBeam: Profiel UPN algemeen 100 x 300 (4)
Type - PredefinedType: BEAM
Material: staal
Pset_BeamCommon - Slope: 0 deg; IsExternal: no; LoadBearing: yes; Reference: Profiel UPN algemeen 100 x 300
BaseQuantities - NetSurfaceAreaExtrudedSides: 10.78 m2; Length: 11000 mm; CrossSectionArea: 0.00588 m2; OuterSurfaceArea: 10.78 m2; TotalSurfaceArea: 10.7918 m2; GrossSurfaceArea: 10.7918 m2; GrossVolume: 0.06468 m3; NetSurfaceArea: 10.7918 m2; NetVolume: 0.06468 m3
Name | In
2 x 28_Balk_Profiel | 01 1e tussenverdieping
2 x 28_Balk_Profiel | 02 2e verdieping

# IfcBeam: Profiel UPN algemeen 70 x 180 (4)
Type - PredefinedType: BEAM
Material: staal
BaseQuantities - NetSurfaceAreaExtrudedSides: 0.694826 m2; Length: 1113.5 mm; CrossSectionArea: 0.00280401 m2; OuterSurfaceArea: 0.694826 m2; TotalSurfaceArea: 0.700434 m2; GrossSurfaceArea: 0.700434 m2; GrossVolume: 0.00312226 m3; NetSurfaceArea: 0.700434 m2; NetVolume: 0.00312226 m3
Pset_BeamCommon - Slope: 0 deg; IsExternal: no; LoadBearing: yes; Reference: Profiel UPN algemeen 70 x 180
Name | In
2 x 28_Balk_Profiel | 01 1e tussenverdieping
2 x 28_Balk_Profiel | 02 2e verdieping

# IfcBeam: RHS100X100X5 100 x 100 (4)
In: 04 4e verdieping
Type - PredefinedType: BEAM
Material: staal C
Pset_BeamCommon - Slope: 0 deg; IsExternal: no; LoadBearing: yes; Reference: RHS100X100X5 100 x 100
BaseQuantities - CrossSectionArea: 0.0019 m2
Name | NetSurfaceAreaExtrudedSides (m2) = OuterSurfaceArea (m2) | Length (mm) | TotalSurfaceArea (m2) = GrossSurfaceArea (m2) = NetSurfaceArea (m2) | GrossVolume (m3) | NetVolume (m3)
Info_Balk_RHS100X100X5 | 16.5522 | 21952.6 | 16.556 | 0.0418 | 0.0414678
Info_Balk_RHS100X100X5 | 16.6839 | 21952.6 | 16.6877 | 0.041791 | 0.0417098
Info_Balk_RHS100X100X5 | 9.10437 | 11990.5 | 9.10817 | 0.022791 | 0.0227611
Info_Balk_RHS100X100X5 | 9.05875 | 11990.5 | 9.06255 | 0.022791 | 0.0227283

# IfcBeam: beton 335 x 150 (45)
Type - PredefinedType: BEAM
Material: beton
Pset_BeamCommon - Slope: 0 deg; IsExternal: no; LoadBearing: no; Reference: beton 335 x 150
BaseQuantities - Width: 335 mm; Depth: 150 mm; CrossSectionArea: 0.05025 m2
Name | In | NetSurfaceAreaExtrudedSides (m2) = OuterSurfaceArea (m2) | Length (mm) | TotalSurfaceArea (m2) = GrossSurfaceArea (m2) = NetSurfaceArea (m2) | GrossVolume (m3) | NetVolume (m3)
2 x 41_Balk_beton | 00 Begane grond | 5.49359 | 6000 | 5.59409 | 0.3015 | 0.282644
6 x 41_Balk_beton | 00 Begane grond | 5.75695 | 5935 | 5.85745 | 0.3015 | 0.298234
2 x 41_Balk_beton | 00 Begane grond | 5.77682 | 6000 | 5.87732 | 0.3015 | 0.298993
41_Balk_beton | 00 Begane grond | 5.73691 | 6000 | 5.83741 | 0.3015 | 0.295453
41_Balk_beton | 00 Begane grond | 5.71724 | 6000 | 5.81774 | 0.3015 | 0.298018
6 x 41_Balk_beton | 00 Begane grond | 5.47128 | 5640.5 | 5.57178 | 0.283435 | 0.283435
41_Balk_beton | 00 Begane grond | 5.40686 | 5640.5 | 5.50736 | 0.283435 | 0.279396
2 x 41_Balk_beton | 00 Begane grond | 5.45621 | 5640.5 | 5.55671 | 0.283435 | 0.282304
41_Balk_beton | 00 Begane grond | 5.46375 | 5640.5 | 5.56425 | 0.283435 | 0.282776
41_Balk_beton | 00 Begane grond | 5.3484 | 5640.5 | 5.4489 | 0.283435 | 0.282784
41_Balk_beton | 00 Begane grond | 5.39724 | 5640.5 | 5.49774 | 0.283435 | 0.279307
2 x 41_Balk_beton | 01 1e verdieping | 5.72168 | 6000 | 5.82218 | 0.3015 | 0.296095
3 x 41_Balk_beton | 01 1e verdieping | 5.77682 | 6000 | 5.87732 | 0.3015 | 0.298993
41_Balk_beton | 01 1e verdieping | 5.7633 | 6000 | 5.8638 | 0.3015 | 0.299056
4 x 41_Balk_beton | 01 1e verdieping | 5.45621 | 5640.5 | 5.55671 | 0.283435 | 0.282304
41_Balk_beton | 01 1e verdieping | 5.46375 | 5640.5 | 5.56425 | 0.283435 | 0.283247
41_Balk_beton | 01 1e verdieping | 5.43485 | 5640.5 | 5.53535 | 0.283435 | 0.282105
4 x 41_Balk_beton | 02 2e verdieping | 5.45621 | 5640.5 | 5.55671 | 0.283435 | 0.282304
4 x 41_Balk_beton | 02 2e verdieping | 5.77682 | 6000 | 5.87732 | 0.3015 | 0.298993
41_Balk_beton | 02 2e verdieping | 1.70514 | 6000 | 1.80564 | 0.3015 | 0.0293952

# IfcBeam: beton_gewapend C 1000 x 900
In: -1 Fundering
Type - PredefinedType: BEAM
Material: beton_gewapend C
Pset_BeamCommon - Slope: 0 deg; IsExternal: no; LoadBearing: yes; Reference: beton_gewapend C 1000 x 900
BaseQuantities - NetSurfaceAreaExtrudedSides: 3.8 m2; Length: 1000 mm; Width: 1000 mm; Depth: 900 mm; CrossSectionArea: 0.9 m2; OuterSurfaceArea: 3.8 m2; TotalSurfaceArea: 5.6 m2; GrossSurfaceArea: 5.6 m2; GrossVolume: 0.9 m3; NetSurfaceArea: 5.6 m2; NetVolume: 0.9 m3

# IfcBeam: beton_gewapend C 1100 x 620 (5)
In: 01 1e verdieping
Type - PredefinedType: BEAM
Material: beton_gewapend C
Pset_BeamCommon - Slope: 0 deg; IsExternal: no; LoadBearing: yes; Reference: beton_gewapend C 1100 x 620
Name | NetVolume (m3) | GrossVolume (m3) | Length (mm) | NetSurfaceAreaExtrudedSides (m2) = OuterSurfaceArea (m2) | Width (mm) | Depth (mm) | CrossSectionArea (m2) | TotalSurfaceArea (m2) = GrossSurfaceArea (m2) = NetSurfaceArea (m2)
 | 0.74327 | 0.980484 | 1976.78
 | 5.63841 | 8.184 | 13600 | 23.2766 | 1100 | 620 | 0.682 | 24.6406
 | 3.5805 | 3.5805 | 5250 | 18.06 | 1100 | 620 | 0.682 | 19.424
 | 1.68392 | 1.68392 | 3395
 | 6.204 | 8.184 | 12000 | 24.48 | 1100 | 620 | 0.682 | 25.844

# IfcBeam: beton_gewapend C 1200 x 900
In: -1 Fundering
Type - PredefinedType: BEAM
Material: beton_gewapend C
Pset_BeamCommon - Slope: 0 deg; IsExternal: no; LoadBearing: yes; Reference: beton_gewapend C 1200 x 900
BaseQuantities - NetSurfaceAreaExtrudedSides: 6.72 m2; Length: 1600 mm; Width: 1200 mm; Depth: 900 mm; CrossSectionArea: 1.08 m2; OuterSurfaceArea: 6.72 m2; TotalSurfaceArea: 8.88 m2; GrossSurfaceArea: 8.88 m2; GrossVolume: 1.728 m3; NetSurfaceArea: 8.88 m2; NetVolume: 1.728 m3

# IfcBeam: beton_gewapend C 1300 x 600 (2)
In: 01 1e verdieping
Type - PredefinedType: BEAM
Material: beton_gewapend C
BaseQuantities - GrossVolume: 1.008 m3; Length: 1600 mm
Pset_BeamCommon - Slope: 0 deg; IsExternal: no; LoadBearing: yes; Reference: beton_gewapend C 1300 x 600
Name | NetVolume (m3)
 | 0.190606
 | 0.3936

# IfcBeam: beton_gewapend C 1300 x 620 (4)
In: 01 1e verdieping
Type - PredefinedType: BEAM
Material: beton_gewapend C
Pset_BeamCommon - Slope: 0 deg; IsExternal: no; LoadBearing: yes; Reference: beton_gewapend C 1300 x 620
BaseQuantities - GrossVolume: 1.0416 m3; Length: 1600 mm
Name | NetVolume (m3)
3 x  | 0.188
 | 1.0416

# IfcBeam: beton_gewapend C 1400 x 620
In: 01 1e verdieping
Type - PredefinedType: BEAM
Material: beton_gewapend C
Pset_BeamCommon - Slope: 0 deg; IsExternal: no; LoadBearing: yes; Reference: beton_gewapend C 1400 x 620
BaseQuantities - NetSurfaceAreaExtrudedSides: 4.0833 m2; Length: 1745 mm; Width: 1400 mm; Depth: 620 mm; CrossSectionArea: 0.868 m2; OuterSurfaceArea: 4.0833 m2; TotalSurfaceArea: 5.8193 m2; GrossSurfaceArea: 5.8193 m2; GrossVolume: 1.77506 m3; NetSurfaceArea: 5.8193 m2; NetVolume: 1.14821 m3

# IfcBeam: beton_gewapend C 1500 x 620 (6)
In: 01 1e verdieping
Type - PredefinedType: BEAM
Material: beton_gewapend C
Pset_BeamCommon - Slope: 0 deg; IsExternal: no; LoadBearing: yes; Reference: beton_gewapend C 1500 x 620
Name | NetVolume (m3) | GrossVolume (m3) | Length (mm)
 | 1.2896 | 1.2896 | 1600
2 x  | 0.1504 | 1.2896 | 1600
 | 1.88201 | 1.88201 | 2335
 | 1.66991 | 2.24595 | 2355 | BaseQuantities - NetSurfaceAreaExtrudedSides: 5.71404 m2; Width: 1500 mm; Depth: 620 mm; CrossSectionArea: 0.93 m2; OuterSurfaceArea: 5.71404 m2; TotalSurfaceArea: 7.57404 m2; GrossSurfaceArea: 7.57404 m2; NetSurfaceArea: 7.57404 m2
 | 0.17625 | 1.2896 | 1600

# IfcBeam: beton_gewapend C 1600 x 620 (2)
In: 01 1e verdieping
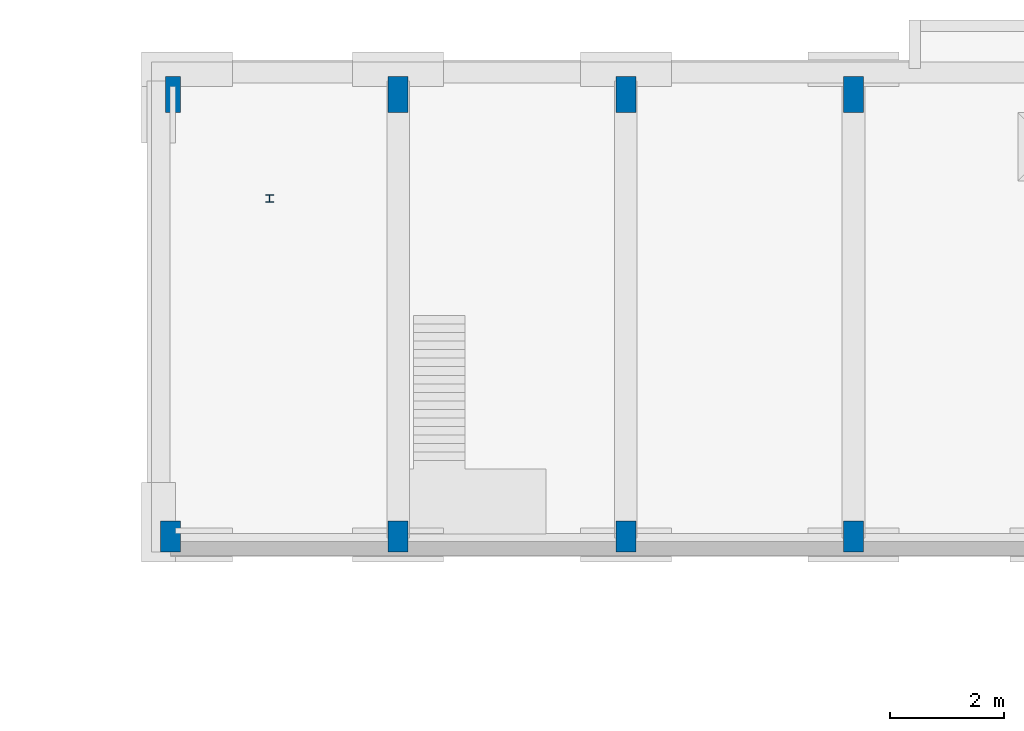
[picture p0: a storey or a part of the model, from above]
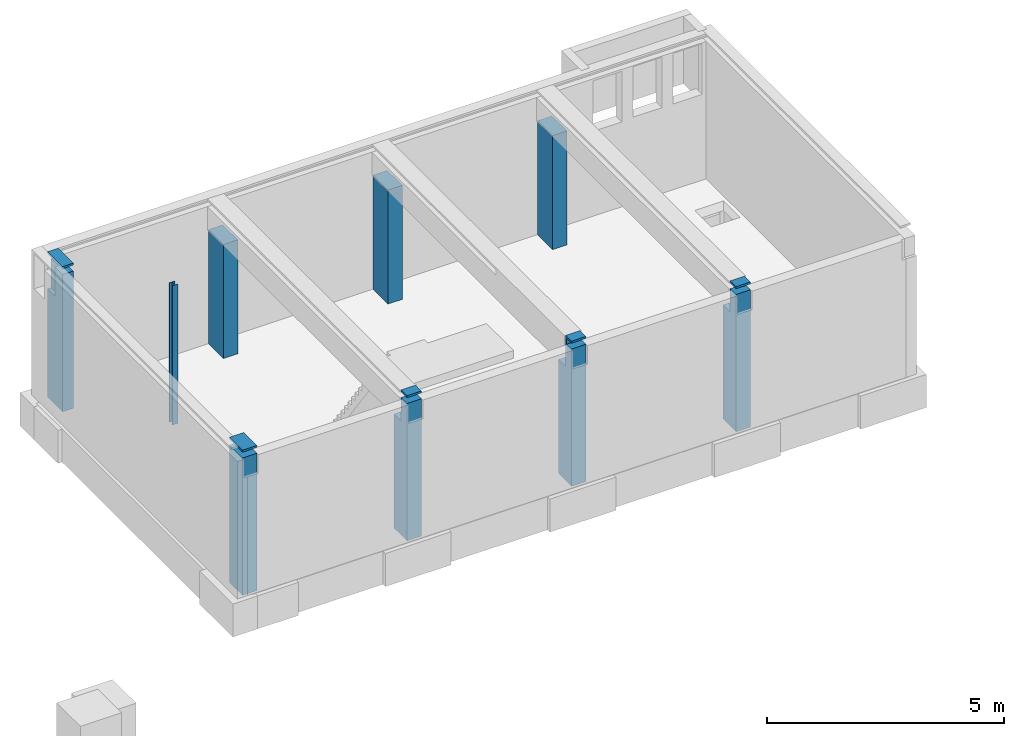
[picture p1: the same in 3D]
Properties of the parts of a building model (IFC2X3), part 2 of 5

# IfcBeam: beton_gewapend C 1600 x 620 (2)
Type - PredefinedType: BEAM
Material: beton_gewapend C
BaseQuantities - Width: 1600 mm; Depth: 620 mm; CrossSectionArea: 0.992 m2; GrossVolume: 8.3328 m3
Pset_BeamCommon - Slope: 0 deg; IsExternal: no; LoadBearing: yes; Reference: beton_gewapend C 1600 x 620
Name | NetSurfaceAreaExtrudedSides (m2) = OuterSurfaceArea (m2) | Length (mm) | TotalSurfaceArea (m2) = GrossSurfaceArea (m2) = NetSurfaceArea (m2) | NetVolume (m3)
 | 19.1284 | 8150 | 21.1124 | 5.67408
 | 17.9282 | 7350 | 19.9122 | 5.31987

# IfcBeam: beton_gewapend C 1600 x 850 (10)
In: Kelder
Type - PredefinedType: BEAM
Material: beton_gewapend C
Pset_BeamCommon - Slope: 0 deg; IsExternal: no; LoadBearing: yes; Reference: beton_gewapend C 1600 x 850
BaseQuantities - Width: 1600 mm; Depth: 850 mm; CrossSectionArea: 1.36 m2; GrossVolume: 0.816 m3
Name | NetSurfaceAreaExtrudedSides (m2) = OuterSurfaceArea (m2) | Length (mm) | TotalSurfaceArea (m2) = GrossSurfaceArea (m2) = NetSurfaceArea (m2) | NetVolume (m3)
2 x  | 0.445 | 200 | 3.165 | 0.145
 | 0.854 | 200 | 3.574 | 0.248
3 x  | 0.73 | 200 | 3.45 | 0.208
2 x  | 2.0115 | 600 | 4.7315 | 0.6244
 | 2.18537 | 600 | 4.90537 | 0.641306
 | 1.37563 | 600 | 4.09563 | 0.341158

# IfcBeam: beton_gewapend C 1600 x 900 (15)
In: -1 Fundering
Type - PredefinedType: BEAM
Material: beton_gewapend C
Pset_BeamCommon - Slope: 0 deg; IsExternal: no; LoadBearing: yes; Reference: beton_gewapend C 1600 x 900
Name | NetVolume (m3) | GrossVolume (m3) | Length (mm) | NetSurfaceAreaExtrudedSides (m2) = OuterSurfaceArea (m2) | Width (mm) | Depth (mm) | CrossSectionArea (m2) | TotalSurfaceArea (m2) = GrossSurfaceArea (m2) = NetSurfaceArea (m2)
 | 0.409172 | 1.02066 | 950
 | 0.768 | 1.152 | 800 | 3.08 | 1600 | 900 | 1.44 | 5.96
 | 0.768 | 1.152 | 600 | 2.64 | 1600 | 900 | 1.44 | 5.52
 | 0.56625 | 1.368 | 800 | 1.85656 | 1600 | 900 | 1.44 | 4.73656
 | 0.464944 | 0.912094 | 1150
 | 0.286125 | 0.792 | 600
 | 0.794599 | 0.99 | 800
2 x  | 1.44 | 1.44 | 1000 | 5 | 1600 | 900 | 1.44 | 7.88
 | 0.942611 | 0.99 | 1000
 | 1.38 | 2.304 | 1600 | 4.24 | 1600 | 900 | 1.44 | 7.12
 | 1.152 | 1.152 | 800 | 4 | 1600 | 900 | 1.44 | 6.88
 | 0.536 | 0.792 | 800
 | 0.576 | 1.152 | 800 | 2 | 1600 | 900 | 1.44 | 4.88
 | 0.268 | 0.792 | 800

# IfcBeam: beton_gewapend C 170 x 600
In: 04 4e verdieping
Type - PredefinedType: BEAM
Material: beton_gewapend C
Pset_BeamCommon - Slope: 0 deg; IsExternal: no; LoadBearing: yes; Reference: beton_gewapend C 170 x 600
BaseQuantities - NetSurfaceAreaExtrudedSides: 7.2788 m2; Length: 5870 mm; Width: 170 mm; Depth: 600 mm; CrossSectionArea: 0.102 m2; OuterSurfaceArea: 7.2788 m2; TotalSurfaceArea: 7.4828 m2; GrossSurfaceArea: 7.4828 m2; GrossVolume: 0.6273 m3; NetSurfaceArea: 7.4828 m2; NetVolume: 0.449055 m3

# IfcBeam: beton_gewapend C 180 x 1063 (3)
Type - PredefinedType: BEAM
Material: beton_gewapend C
Pset_BeamCommon - Slope: 0 deg; IsExternal: no; LoadBearing: yes; Reference: beton_gewapend C 180 x 1063
BaseQuantities - Width: 180 mm; Depth: 1062.5 mm; CrossSectionArea: 0.19125 m2
Name | In | NetSurfaceAreaExtrudedSides (m2) = OuterSurfaceArea (m2) | Length (mm) | TotalSurfaceArea (m2) = GrossSurfaceArea (m2) = NetSurfaceArea (m2) | GrossVolume (m3) | NetVolume (m3)
 | 01 1e verdieping | 8.2038 | 4050 | 8.5863 | 0.774562 | 0.687004
 | 01 1e verdieping | 13.7098 | 6670 | 14.0923 | 1.27564 | 1.14128
 | 02 2e verdieping | 10.2658 | 8470 | 10.6483 | 1.61989 | 0.924964

# IfcBeam: beton_gewapend C 180 x 850
In: 02 2e verdieping
Type - PredefinedType: BEAM
Material: beton_gewapend C
BaseQuantities - NetSurfaceAreaExtrudedSides: 7.88859 m2; Length: 8406 mm; Width: 180 mm; Depth: 850 mm; CrossSectionArea: 0.153 m2; OuterSurfaceArea: 7.88859 m2; TotalSurfaceArea: 8.19459 m2; GrossSurfaceArea: 8.19459 m2; GrossVolume: 1.29591 m3; NetSurfaceArea: 8.19459 m2; NetVolume: 0.789291 m3
Pset_BeamCommon - Slope: 0 deg; IsExternal: no; LoadBearing: yes; Reference: beton_gewapend C 180 x 850

# IfcBeam: beton_gewapend C 200 x 1200 (4)
In: -1 Fundering
Type - PredefinedType: BEAM
Material: beton_gewapend C
Pset_BeamCommon - Slope: 0 deg; IsExternal: no; LoadBearing: yes; Reference: beton_gewapend C 200 x 1200
BaseQuantities - Width: 200 mm; Depth: 1200 mm; CrossSectionArea: 0.24 m2
Name | NetSurfaceAreaExtrudedSides (m2) = OuterSurfaceArea (m2) | Length (mm) | TotalSurfaceArea (m2) = GrossSurfaceArea (m2) = NetSurfaceArea (m2) | GrossVolume (m3) | NetVolume (m3)
 | 78.7687 | 29025 | 79.2487 | 6.966 | 6.74088
 | 9.53509 | 4306.02 | 10.0151 | 1.03344 | 0.854459
 | 32.7066 | 13404.5 | 33.1866 | 3.38973 | 2.83815
 | 10.3382 | 4820.46 | 10.8182 | 1.10373 | 0.889247

# IfcBeam: beton_gewapend C 200 x 1220
In: -1 Fundering
Type - PredefinedType: BEAM
Material: beton_gewapend C
Pset_BeamCommon - Slope: 0 deg; IsExternal: no; LoadBearing: yes; Reference: beton_gewapend C 200 x 1220
BaseQuantities - NetSurfaceAreaExtrudedSides: 120.859 m2; Length: 44940 mm; Width: 200 mm; Depth: 1220 mm; CrossSectionArea: 0.244 m2; OuterSurfaceArea: 120.859 m2; TotalSurfaceArea: 121.347 m2; GrossSurfaceArea: 121.347 m2; GrossVolume: 10.9654 m3; NetSurfaceArea: 121.347 m2; NetVolume: 10.2906 m3

# IfcBeam: beton_gewapend C 200 x 400
In: -1 Fundering
Type - PredefinedType: BEAM
Material: beton_gewapend C
Pset_BeamCommon - Slope: 0 deg; IsExternal: no; LoadBearing: yes; Reference: beton_gewapend C 200 x 400
BaseQuantities - NetSurfaceAreaExtrudedSides: 3.35405 m2; Length: 2900 mm; Width: 200 mm; Depth: 400 mm; CrossSectionArea: 0.08 m2; OuterSurfaceArea: 3.35405 m2; TotalSurfaceArea: 3.51405 m2; GrossSurfaceArea: 3.51405 m2; GrossVolume: 0.2648 m3; NetSurfaceArea: 3.51405 m2; NetVolume: 0.219405 m3

# IfcBeam: beton_gewapend C 230 x 480
In: 01 1e verdieping
Type - PredefinedType: BEAM
Material: beton_gewapend C
BaseQuantities - NetSurfaceAreaExtrudedSides: 1.065 m2; Length: 750 mm; Width: 230 mm; Depth: 480 mm; CrossSectionArea: 0.1104 m2; OuterSurfaceArea: 1.065 m2; TotalSurfaceArea: 1.2858 m2; GrossSurfaceArea: 1.2858 m2; GrossVolume: 0.14673 m3; NetSurfaceArea: 1.2858 m2; NetVolume: 0.0828 m3
Pset_BeamCommon - Slope: 0 deg; IsExternal: no; LoadBearing: yes; Reference: beton_gewapend C 230 x 480

# IfcBeam: beton_gewapend C 250 x 1200 (2)
In: -1 Fundering
Type - PredefinedType: BEAM
Material: beton_gewapend C
BaseQuantities - Width: 250 mm; Depth: 1200 mm; CrossSectionArea: 0.3 m2; GrossVolume: 6.36 m3
Pset_BeamCommon - Slope: 0 deg; IsExternal: no; LoadBearing: yes; Reference: beton_gewapend C 250 x 1200
Name | NetSurfaceAreaExtrudedSides (m2) = OuterSurfaceArea (m2) | Length (mm) | TotalSurfaceArea (m2) = GrossSurfaceArea (m2) = NetSurfaceArea (m2) | NetVolume (m3)
 | 50.6328 | 21375 | 51.2328 | 5.47185
 | 55.2339 | 21200 | 55.8339 | 5.57923

# IfcBeam: beton_gewapend C 250 x 170
In: 02 2e verdieping
Type - PredefinedType: BEAM
Material: beton_gewapend C
Pset_BeamCommon - Slope: 0 deg; IsExternal: no; LoadBearing: yes; Reference: beton_gewapend C 250 x 170
BaseQuantities - NetSurfaceAreaExtrudedSides: 1.4 m2; Length: 4000 mm; Width: 250 mm; Depth: 170 mm; CrossSectionArea: 0.0425 m2; OuterSurfaceArea: 1.4 m2; TotalSurfaceArea: 1.485 m2; GrossSurfaceArea: 1.485 m2; GrossVolume: 0.184875 m3; NetSurfaceArea: 1.485 m2; NetVolume: 0.05 m3

# IfcBeam: beton_gewapend C 250 x 400
In: -1 Fundering
Type - PredefinedType: BEAM
Material: beton_gewapend C
Pset_BeamCommon - Slope: 0 deg; IsExternal: no; LoadBearing: yes; Reference: beton_gewapend C 250 x 400
BaseQuantities - NetSurfaceAreaExtrudedSides: 3.4 m2; Length: 3400 mm; Width: 250 mm; Depth: 400 mm; CrossSectionArea: 0.1 m2; OuterSurfaceArea: 3.4 m2; TotalSurfaceArea: 3.6 m2; GrossSurfaceArea: 3.6 m2; GrossVolume: 0.44 m3; NetSurfaceArea: 3.6 m2; NetVolume: 0.2125 m3

# IfcBeam: beton_gewapend C 250 x 650 (3)
In: Kelder
Type - PredefinedType: BEAM
Material: beton_gewapend C
BaseQuantities - Width: 250 mm; Depth: 650 mm; CrossSectionArea: 0.1625 m2
Pset_BeamCommon - Slope: 0 deg; IsExternal: no; LoadBearing: yes; Reference: beton_gewapend C 250 x 650
Name | NetSurfaceAreaExtrudedSides (m2) = OuterSurfaceArea (m2) | Length (mm) | TotalSurfaceArea (m2) = GrossSurfaceArea (m2) = NetSurfaceArea (m2) | GrossVolume (m3) = NetVolume (m3)
 | 1.71 | 1200 | 2.035 | 0.154375
 | 1.32769 | 862.608 | 1.65269 | 0.119861
 | 1.50769 | 962.608 | 1.83269 | 0.136111

# IfcBeam: beton_gewapend C 2650 x 620
In: 01 1e verdieping
Type - PredefinedType: BEAM
Material: beton_gewapend C
Pset_BeamCommon - Slope: 0 deg; IsExternal: no; LoadBearing: yes; Reference: beton_gewapend C 2650 x 620
BaseQuantities - NetSurfaceAreaExtrudedSides: 5.01315 m2; Length: 2537.73 mm; Width: 2650 mm; Depth: 620 mm; CrossSectionArea: 1.643 m2; OuterSurfaceArea: 5.01315 m2; TotalSurfaceArea: 8.29915 m2; GrossSurfaceArea: 8.29915 m2; GrossVolume: 4.67434 m3; NetSurfaceArea: 8.29915 m2; NetVolume: 1.58685 m3

# IfcBeam: beton_gewapend C 280 x 700 (3)
Type - PredefinedType: BEAM
Material: beton_gewapend C
Pset_BeamCommon - Slope: 0 deg; IsExternal: no; LoadBearing: yes; Reference: beton_gewapend C 280 x 700
BaseQuantities - Length: 19989.1 mm; Width: 280 mm; Depth: 700 mm; CrossSectionArea: 0.196 m2; GrossVolume: 3.91786 m3
Name | In | NetSurfaceAreaExtrudedSides (m2) = OuterSurfaceArea (m2) | TotalSurfaceArea (m2) = GrossSurfaceArea (m2) = NetSurfaceArea (m2) | NetVolume (m3)
 | 00 Begane grond | 35.5876 | 35.9796 | 3.51286
 | 01 1e tussenverdieping | 36.0475 | 36.4395 | 3.57608
 | 01 1e verdieping | 36.1861 | 36.5781 | 3.52884

# IfcBeam: beton_gewapend C 280 x 850 (2)
In: 02 2e verdieping
Type - PredefinedType: BEAM
Material: beton_gewapend C
BaseQuantities - Width: 280 mm; Depth: 850 mm; CrossSectionArea: 0.238 m2
Pset_BeamCommon - Slope: 0 deg; IsExternal: no; LoadBearing: yes; Reference: beton_gewapend C 280 x 850
Name | NetSurfaceAreaExtrudedSides (m2) = OuterSurfaceArea (m2) | Length (mm) | TotalSurfaceArea (m2) = GrossSurfaceArea (m2) = NetSurfaceArea (m2) | GrossVolume (m3) | NetVolume (m3)
 | 39.8123 | 20324.1 | 40.2883 | 4.86212 | 3.98269
 | 34.747 | 20066.6 | 35.223 | 4.77585 | 2.95447

# IfcBeam: beton_gewapend C 300 x 1150 (3)
In: -1 Fundering
Type - PredefinedType: BEAM
Material: beton_gewapend C
BaseQuantities - Width: 300 mm; Depth: 1150 mm; CrossSectionArea: 0.345 m2
Pset_BeamCommon - Slope: 0 deg; IsExternal: no; LoadBearing: yes; Reference: beton_gewapend C 300 x 1150
Name | NetSurfaceAreaExtrudedSides (m2) = OuterSurfaceArea (m2) | Length (mm) | TotalSurfaceArea (m2) = GrossSurfaceArea (m2) = NetSurfaceArea (m2) | GrossVolume (m3) | NetVolume (m3)
 | 29.9698 | 12010 | 30.6598 | 4.24695 | 3.73099
 | 51.4832 | 20070 | 52.1732 | 7.01557 | 6.40663
 | 24.6135 | 10410 | 25.3035 | 4.24695 | 3.21975

# IfcBeam: beton_gewapend C 300 x 470
In: 01 1e verdieping
Type - PredefinedType: BEAM
Material: beton_gewapend C
BaseQuantities - NetSurfaceAreaExtrudedSides: 22.8196 m2; Length: 15510 mm; Width: 300 mm; Depth: 470 mm; CrossSectionArea: 0.141 m2; OuterSurfaceArea: 22.8196 m2; TotalSurfaceArea: 23.1016 m2; GrossSurfaceArea: 23.1016 m2; GrossVolume: 2.27856 m3; NetSurfaceArea: 23.1016 m2; NetVolume: 2.07312 m3
Pset_BeamCommon - Slope: 0 deg; IsExternal: no; LoadBearing: yes; Reference: beton_gewapend C 300 x 470

# IfcBeam: beton_gewapend C 300 x 500 (2)
In: -1 Fundering
Type - PredefinedType: BEAM
Material: beton_gewapend C
BaseQuantities - Width: 300 mm; Depth: 500 mm; CrossSectionArea: 0.15 m2
Pset_BeamCommon - Slope: 0 deg; IsExternal: no; LoadBearing: yes; Reference: beton_gewapend C 300 x 500
Name | NetSurfaceAreaExtrudedSides (m2) = OuterSurfaceArea (m2) | Length (mm) | TotalSurfaceArea (m2) = GrossSurfaceArea (m2) = NetSurfaceArea (m2) | GrossVolume (m3) | NetVolume (m3)
 | 12.775 | 12775 | 13.075 | 2.145 | 1.34137
 | 6.9 | 6900 | 7.2 | 1.2675 | 0.7245

# IfcBeam: beton_gewapend C 300 x 600
In: 01 1e verdieping
Type - PredefinedType: BEAM
Material: beton_gewapend C
Pset_BeamCommon - Slope: 0 deg; IsExternal: no; LoadBearing: yes; Reference: beton_gewapend C 300 x 600
BaseQuantities - NetSurfaceAreaExtrudedSides: 18.387 m2; Length: 10215 mm; Width: 300 mm; Depth: 600 mm; CrossSectionArea: 0.18 m2; OuterSurfaceArea: 18.387 m2; TotalSurfaceArea: 18.747 m2; GrossSurfaceArea: 18.747 m2; GrossVolume: 1.8387 m3; NetSurfaceArea: 18.747 m2; NetVolume: 1.8387 m3

# IfcBeam: beton_gewapend C 300 x 620 (4)
In: 01 1e verdieping
Type - PredefinedType: BEAM
Material: beton_gewapend C
Pset_BeamCommon - Slope: 0 deg; IsExternal: no; LoadBearing: yes; Reference: beton_gewapend C 300 x 620
BaseQuantities - Width: 300 mm; Depth: 620 mm; CrossSectionArea: 0.186 m2
Name | NetSurfaceAreaExtrudedSides (m2) = OuterSurfaceArea (m2) | Length (mm) | TotalSurfaceArea (m2) = GrossSurfaceArea (m2) = NetSurfaceArea (m2) | GrossVolume (m3) | NetVolume (m3)
 | 21.6769 | 12160 | 22.0489 | 2.26176 | 2.17806
 | 37.3016 | 20495 | 37.6736 | 3.81207 | 3.77459
 | 18.7313 | 16140 | 19.1033 | 2.97414 | 2.22172
 | 39.9121 | 32490 | 40.2841 | 5.98734 | 4.53874

# IfcBeam: beton_gewapend C 350 x 1100
In: 01 1e verdieping
Type - PredefinedType: BEAM
Material: beton_gewapend C
Pset_BeamCommon - Slope: 0 deg; IsExternal: no; LoadBearing: yes; Reference: beton_gewapend C 350 x 1100
BaseQuantities - NetSurfaceAreaExtrudedSides: 18.48 m2; Length: 8000 mm; Width: 350 mm; Depth: 1100 mm; CrossSectionArea: 0.385 m2; OuterSurfaceArea: 18.48 m2; TotalSurfaceArea: 19.25 m2; GrossSurfaceArea: 19.25 m2; GrossVolume: 3.08 m3; NetSurfaceArea: 19.25 m2; NetVolume: 2.744 m3

# IfcBeam: beton_gewapend C 350 x 400
In: -1 Fundering
Type - PredefinedType: BEAM
Material: beton_gewapend C
BaseQuantities - NetSurfaceAreaExtrudedSides: 2.93354 m2; Length: 1985.67 mm; Width: 350 mm; Depth: 400 mm; CrossSectionArea: 0.14 m2; OuterSurfaceArea: 2.93354 m2; TotalSurfaceArea: 3.21354 m2; GrossSurfaceArea: 3.21354 m2; GrossVolume: 0.333994 m3; NetSurfaceArea: 3.21354 m2; NetVolume: 0.26557 m3
Pset_BeamCommon - Slope: 0 deg; IsExternal: no; LoadBearing: yes; Reference: beton_gewapend C 350 x 400

# IfcBeam: beton_gewapend C 350 x 550 (11)
In: 04 4e verdieping
Type - PredefinedType: BEAM
Material: beton_gewapend C
BaseQuantities - Length: 4005.55 mm; Width: 350 mm; Depth: 550 mm; CrossSectionArea: 0.1925 m2; GrossVolume: 0.771068 m3
Pset_BeamCommon - Slope: 0 deg; IsExternal: no; LoadBearing: yes; Reference: beton_gewapend C 350 x 550
Name | NetSurfaceAreaExtrudedSides (m2) = OuterSurfaceArea (m2) | TotalSurfaceArea (m2) = GrossSurfaceArea (m2) = NetSurfaceArea (m2) | NetVolume (m3)
 | 5.44722 | 5.83222 | 0.496611
 | 3.35966 | 3.74466 | 0.0993222
9 x  | 5.41355 | 5.79855 | 0.490719

# IfcBeam: beton_gewapend C 350 x 600 (39)
Type - PredefinedType: BEAM
Material: beton_gewapend C
Pset_BeamCommon - Slope: 0 deg; IsExternal: no; LoadBearing: yes; Reference: beton_gewapend C 350 x 600
BaseQuantities - Width: 350 mm; Depth: 600 mm; CrossSectionArea: 0.21 m2
Name | In | NetSurfaceAreaExtrudedSides (m2) = OuterSurfaceArea (m2) | Length (mm) | TotalSurfaceArea (m2) = GrossSurfaceArea (m2) = NetSurfaceArea (m2) | GrossVolume (m3) | NetVolume (m3)
5 x  | 01 1e verdieping | 5.24 | 4000 | 5.66 | 0.84 | 0.672
4 x  | 01 1e verdieping | 10.48 | 8000 | 10.9 | 1.68 | 1.344
 | 02 2e verdieping | 4.5195 | 3450 | 4.9395 | 0.841165 | 0.5796
8 x  | 02 2e verdieping | 4.57505 | 4005.55 | 4.99505 | 0.841165 | 0.589322
 | 02 2e verdieping | 5.24727 | 4005.55 | 5.66727 | 0.841165 | 0.672932
9 x  | 04 4e verdieping | 11.8182 | 8000 | 12.2382 | 1.68 | 1.13872
8 x  | 04 4e verdieping | 11.7832 | 7994.45 | 12.2032 | 1.67884 | 1.13293
 | 04 4e verdieping | 12.492 | 7994.45 | 12.912 | 1.67884 | 1.22329
 | 04 4e verdieping | 8.3274 | 7994.45 | 8.7474 | 1.67884 | 0.263115
 | 04 4e verdieping | 9.9177 | 7994.45 | 10.3377 | 1.67884 | 0.713193

# IfcBeam: beton_gewapend C 350 x 635 (2)
In: 01 1e verdieping
Type - PredefinedType: BEAM
Material: beton_gewapend C
Pset_BeamCommon - Slope: 0 deg; IsExternal: no; LoadBearing: yes; Reference: beton_gewapend C 350 x 635
BaseQuantities - NetSurfaceAreaExtrudedSides: 11.04 m2; Length: 8000 mm; Width: 350 mm; Depth: 635 mm; CrossSectionArea: 0.22225 m2; OuterSurfaceArea: 11.04 m2; TotalSurfaceArea: 11.4845 m2; GrossSurfaceArea: 11.4845 m2; GrossVolume: 1.778 m3; NetSurfaceArea: 11.4845 m2; NetVolume: 1.442 m3

# IfcBeam: beton_gewapend C 350 x 650 (47)
Type - PredefinedType: BEAM
Material: beton_gewapend C
BaseQuantities - Width: 350 mm; Depth: 650 mm; CrossSectionArea: 0.2275 m2
Pset_BeamCommon - Slope: 0 deg; IsExternal: no; LoadBearing: yes; Reference: beton_gewapend C 350 x 650
Name | In | NetSurfaceAreaExtrudedSides (m2) = OuterSurfaceArea (m2) | Length (mm) | TotalSurfaceArea (m2) = GrossSurfaceArea (m2) = NetSurfaceArea (m2) | GrossVolume (m3) | NetVolume (m3)
2 x  | -1 Fundering | 33.082 | 19460 | 33.537 | 4.70015 | 3.4055
 | -1 Fundering | 30.8228 | 19470 | 31.2778 | 4.70243 | 3.19769
 | -1 Fundering | 31.4925 | 18525 | 31.9475 | 4.70015 | 3.24187
 | -1 Fundering | 33.2321 | 20470 | 33.6871 | 4.70242 | 3.29043
 | -1 Fundering | 33.8995 | 19460 | 34.3545 | 4.70015 | 3.54857
 | -1 Fundering | 33.5935 | 19460 | 34.0485 | 4.70015 | 3.45665
 | -1 Fundering | 18.4453 | 10850.2 | 18.9003 | 2.74142 | 1.8988
2 x  | -1 Fundering | 18.785 | 11050 | 19.24 | 2.74138 | 1.93375
 | -1 Fundering | 17.3389 | 10199.4 | 17.7939 | 2.74138 | 1.78489
 | -1 Fundering | 16.3037 | 9799.99 | 16.7587 | 2.20106 | 1.67562
 | 01 1e verdieping | 6.02775 | 4275 | 6.48275 | 0.972563 | 0.793013
9 x  | 01 1e verdieping | 11.28 | 8000 | 11.735 | 1.82 | 1.484
3 x  | 01 1e verdieping | 5.64 | 4000 | 6.095 | 0.91 | 0.742
 | 01 1e verdieping | 5.62875 | 4000 | 6.08375 | 0.91 | 0.736038
 | 01 1e verdieping | 11.3812 | 8225 | 11.8362 | 1.87119 | 1.48794
 | 01 1e verdieping | 11.1307 | 8000 | 11.5857 | 1.82 | 1.40488
4 x  | 02 2e verdieping | 10.2065 | 8000 | 10.6615 | 1.82 | 1.34633
 | 02 2e verdieping | 10.1717 | 7725 | 10.6267 | 1.82 | 1.34059
 | 02 2e verdieping | 9.239 | 7725 | 9.694 | 1.81874 | 0.842655
8 x  | 02 2e verdieping | 10.1987 | 7994.45 | 10.6537 | 1.81874 | 1.3453
 | 02 2e verdieping | 11.2722 | 7994.45 | 11.7272 | 1.81874 | 1.48297
3 x  | 02 2e verdieping | 10.1992 | 8000 | 10.6542 | 1.82 | 1.3454
 | 02 2e verdieping | 10.1993 | 8000 | 10.6543 | 1.82 | 1.3454

# IfcBeam: beton_gewapend C 350 x 850 (8)
Type - PredefinedType: BEAM
Material: beton_gewapend C
BaseQuantities - Width: 350 mm; Depth: 850 mm; CrossSectionArea: 0.2975 m2; GrossVolume: 3.65925 m3
Pset_BeamCommon - Slope: 0 deg; IsExternal: no; LoadBearing: yes; Reference: beton_gewapend C 350 x 850
Name | In | NetSurfaceAreaExtrudedSides (m2) = OuterSurfaceArea (m2) | Length (mm) | TotalSurfaceArea (m2) = GrossSurfaceArea (m2) = NetSurfaceArea (m2) | NetVolume (m3)
3 x  | 01 1e tussenverdieping | 26.3095 | 12300 | 26.9045 | 3.13723
 | 01 1e tussenverdieping | 26.3465 | 12300 | 26.9415 | 3.1437
4 x  | 02 2e verdieping | 25.242 | 12020 | 25.837 | 2.9449

# IfcBeam: beton_gewapend C 350 x 950 (4)
In: -1 Fundering
Type - PredefinedType: BEAM
Material: beton_gewapend C
BaseQuantities - Length: 11650 mm; Width: 350 mm; Depth: 950 mm; CrossSectionArea: 0.3325 m2; GrossVolume: 3.87362 m3
Pset_BeamCommon - Slope: 0 deg; IsExternal: no; LoadBearing: yes; Reference: beton_gewapend C 350 x 950
Name | NetSurfaceAreaExtrudedSides (m2) = OuterSurfaceArea (m2) | TotalSurfaceArea (m2) = GrossSurfaceArea (m2) = NetSurfaceArea (m2) | NetVolume (m3)
 | 21.8181 | 22.4831 | 3.10308
 | 21.8071 | 22.4721 | 3.10115
2 x  | 21.8206 | 22.4856 | 3.10352

# IfcBeam: beton_gewapend C 400 x 800 (7)
Type - PredefinedType: BEAM
Material: beton_gewapend C
Pset_BeamCommon - Slope: 0 deg; IsExternal: no; LoadBearing: yes; Reference: beton_gewapend C 400 x 800
BaseQuantities - Width: 400 mm; Depth: 800 mm; CrossSectionArea: 0.32 m2
Name | In | NetSurfaceAreaExtrudedSides (m2) = OuterSurfaceArea (m2) | Length (mm) | TotalSurfaceArea (m2) = GrossSurfaceArea (m2) = NetSurfaceArea (m2) | GrossVolume (m3) | NetVolume (m3)
 | Kelder | 17.4646 | 8110 | 18.1046 | 2.5952 | 2.1758
 | Kelder | 17.031 | 8110 | 17.671 | 2.5952 | 2.1086
 | Kelder | 17.4645 | 8110 | 18.1045 | 2.5952 | 2.17362
2 x  | -1 Fundering | 17.405 | 7525 | 18.045 | 2.688 | 2.314
 | -1 Fundering | 28.8 | 12000 | 29.44 | 3.84 | 3.84
 | -1 Fundering | 27.84 | 12000 | 28.48 | 3.84 | 3.712

# IfcBeam: beton_gewapend C 400 x 850 (7)
In: Kelder
Type - PredefinedType: BEAM
Material: beton_gewapend C
BaseQuantities - Width: 400 mm; Depth: 850 mm; CrossSectionArea: 0.34 m2
Pset_BeamCommon - Slope: 0 deg; IsExternal: no; LoadBearing: yes; Reference: beton_gewapend C 400 x 850
Name | NetSurfaceAreaExtrudedSides (m2) = OuterSurfaceArea (m2) | Length (mm) | TotalSurfaceArea (m2) = GrossSurfaceArea (m2) = NetSurfaceArea (m2) | GrossVolume (m3) | NetVolume (m3)
 | 12.576 | 7860 | 13.256 | 2.72 | 1.8864
 | 21.6021 | 11460 | 22.2821 | 5.73241 | 2.85068
2 x  | 12.72 | 7950 | 13.4 | 2.72 | 1.908
 | 12.4356 | 6460 | 13.1156 | 2.1964 | 1.67156
 | 13.5712 | 7050 | 14.2512 | 2.397 | 1.82419
 | 30.8 | 16000 | 31.48 | 5.44001 | 4.14001

# IfcBeam: beton_gewapend C 400 x 900 (2)
In: -1 Fundering
Type - PredefinedType: BEAM
Material: beton_gewapend C
Pset_BeamCommon - Slope: 0 deg; IsExternal: no; LoadBearing: yes; Reference: beton_gewapend C 400 x 900
BaseQuantities - Width: 400 mm; Depth: 900 mm; CrossSectionArea: 0.36 m2
Name | NetSurfaceAreaExtrudedSides (m2) = OuterSurfaceArea (m2) | Length (mm) | TotalSurfaceArea (m2) = GrossSurfaceArea (m2) = NetSurfaceArea (m2) | GrossVolume (m3) | NetVolume (m3)
 | 7.91 | 3350 | 8.63 | 1.206 | 1.078
 | 5.434 | 2090 | 6.154 | 0.7524 | 0.7524

# IfcBeam: beton_gewapend C 410 x 650
In: -1 Fundering
Type - PredefinedType: BEAM
Material: beton_gewapend C
Pset_BeamCommon - Slope: 0 deg; IsExternal: no; LoadBearing: yes; Reference: beton_gewapend C 410 x 650
BaseQuantities - NetSurfaceAreaExtrudedSides: 2.0034 m2; Length: 945 mm; Width: 410 mm; Depth: 650 mm; CrossSectionArea: 0.2665 m2; OuterSurfaceArea: 2.0034 m2; TotalSurfaceArea: 2.5364 m2; GrossSurfaceArea: 2.5364 m2; GrossVolume: 0.258505 m3; NetSurfaceArea: 2.5364 m2; NetVolume: 0.251842 m3

# IfcBeam: beton_gewapend C 440 x 600
In: 01 1e verdieping
Type - PredefinedType: BEAM
Material: beton_gewapend C
BaseQuantities - NetSurfaceAreaExtrudedSides: 10.1037 m2; Length: 8000 mm; Width: 440 mm; Depth: 600 mm; CrossSectionArea: 0.264 m2; OuterSurfaceArea: 10.1037 m2; TotalSurfaceArea: 10.6317 m2; GrossSurfaceArea: 10.6317 m2; GrossVolume: 2.112 m3; NetSurfaceArea: 10.6317 m2; NetVolume: 1.6146 m3
Pset_BeamCommon - Slope: 0 deg; IsExternal: no; LoadBearing: yes; Reference: beton_gewapend C 440 x 600

# IfcBeam: beton_gewapend C 440 x 850 (4)
Type - PredefinedType: BEAM
Material: beton_gewapend C
Pset_BeamCommon - Slope: 0 deg; IsExternal: no; LoadBearing: yes; Reference: beton_gewapend C 440 x 850
BaseQuantities - Width: 440 mm; Depth: 850 mm; CrossSectionArea: 0.374 m2; GrossVolume: 4.6002 m3
Name | In | NetSurfaceAreaExtrudedSides (m2) = OuterSurfaceArea (m2) | Length (mm) | TotalSurfaceArea (m2) = GrossSurfaceArea (m2) = NetSurfaceArea (m2) | NetVolume (m3)
 | 01 1e tussenverdieping | 26.7389 | 12300 | 27.4869 | 4.09674
 | 01 1e tussenverdieping | 26.7549 | 12300 | 27.5029 | 4.16737
 | 02 2e verdieping | 26.1097 | 12020 | 26.8577 | 3.12057
 | 02 2e verdieping | 24.5436 | 12300 | 25.2916 | 3.50092

# IfcBeam: beton_gewapend C 450 x 900 (6)
In: -1 Fundering
Type - PredefinedType: BEAM
Material: beton_gewapend C
Pset_BeamCommon - Slope: 0 deg; IsExternal: no; LoadBearing: yes; Reference: beton_gewapend C 450 x 900
BaseQuantities - Width: 450 mm; Depth: 900 mm; CrossSectionArea: 0.405 m2
Name | NetSurfaceAreaExtrudedSides (m2) = OuterSurfaceArea (m2) | Length (mm) | TotalSurfaceArea (m2) = GrossSurfaceArea (m2) = NetSurfaceArea (m2) | GrossVolume (m3) | NetVolume (m3)
 | 40.2792 | 21059.1 | 41.0892 | 8.75472 | 6.93059
 | 40.6378 | 20869.1 | 41.4478 | 8.53298 | 7.00984
 | 21.9339 | 11300 | 22.7439 | 4.6575 | 3.77248
 | 38.619 | 20424.1 | 39.429 | 8.53298 | 6.88713
 | 40.988 | 21154.1 | 41.798 | 8.71118 | 7.08044
 | 19.313 | 9904.08 | 20.123 | 4.01115 | 3.34264

# IfcBeam: beton_gewapend C 465 x 600
In: 01 1e verdieping
Type - PredefinedType: BEAM
Material: beton_gewapend C
Pset_BeamCommon - Slope: 0 deg; IsExternal: no; LoadBearing: yes; Reference: beton_gewapend C 465 x 600
BaseQuantities - NetSurfaceAreaExtrudedSides: 17.1678 m2; Length: 8060 mm; Width: 465 mm; Depth: 600 mm; CrossSectionArea: 0.279 m2; OuterSurfaceArea: 17.1678 m2; TotalSurfaceArea: 17.7258 m2; GrossSurfaceArea: 17.7258 m2; GrossVolume: 2.28083 m3; NetSurfaceArea: 17.7258 m2; NetVolume: 2.24874 m3

# IfcBeam: beton_gewapend C 475 x 350
In: -1 Fundering
Type - PredefinedType: BEAM
Material: beton_gewapend C
Pset_BeamCommon - Slope: 0 deg; IsExternal: no; LoadBearing: yes; Reference: beton_gewapend C 475 x 350
BaseQuantities - NetSurfaceAreaExtrudedSides: 5.55226 m2; Length: 3365 mm; Width: 475 mm; Depth: 350.001 mm; CrossSectionArea: 0.16625 m2; OuterSurfaceArea: 5.55226 m2; TotalSurfaceArea: 5.88476 m2; GrossSurfaceArea: 5.88476 m2; GrossVolume: 0.659183 m3; NetSurfaceArea: 5.88476 m2; NetVolume: 0.559433 m3

# IfcBeam: beton_gewapend C 500 x 500
In: -1 Fundering
Type - PredefinedType: BEAM
Material: beton_gewapend C
BaseQuantities - NetSurfaceAreaExtrudedSides: 5.84415 m2; Length: 3890 mm; Width: 499.584 mm; Depth: 500.002 mm; CrossSectionArea: 0.249793 m2; OuterSurfaceArea: 5.84415 m2; TotalSurfaceArea: 6.34374 m2; GrossSurfaceArea: 6.34374 m2; GrossVolume: 0.971696 m3; NetSurfaceArea: 6.34374 m2; NetVolume: 0.781138 m3
Pset_BeamCommon - Slope: 0 deg; IsExternal: no; LoadBearing: yes; Reference: beton_gewapend C 500 x 500

# IfcBeam: beton_gewapend C 500 x 600 (4)
In: 01 1e verdieping
Type - PredefinedType: BEAM
Material: beton_gewapend C
Pset_BeamCommon - Slope: 0 deg; IsExternal: no; LoadBearing: yes; Reference: beton_gewapend C 500 x 600
BaseQuantities - Width: 500 mm; Depth: 600 mm; CrossSectionArea: 0.3 m2
Name | NetSurfaceAreaExtrudedSides (m2) = OuterSurfaceArea (m2) | Length (mm) | TotalSurfaceArea (m2) = GrossSurfaceArea (m2) = NetSurfaceArea (m2) | GrossVolume (m3) | NetVolume (m3)
 | 6.424 | 4400 | 7.024 | 1.32 | 1.056
 | 3.21259 | 2200.41 | 3.81259 | 0.660122 | 0.528097
 | 14.1584 | 9864.59 | 14.7584 | 2.95938 | 2.30653
 | 9.68 | 4400 | 10.28 | 1.32 | 1.32

# IfcBeam: beton_gewapend C 500 x 850
In: Kelder
Type - PredefinedType: BEAM
Material: beton_gewapend C
Pset_BeamCommon - Slope: 0 deg; IsExternal: no; LoadBearing: yes; Reference: beton_gewapend C 500 x 850
BaseQuantities - NetSurfaceAreaExtrudedSides: 0.616256 m2; Length: 290 mm; Width: 500 mm; Depth: 850 mm; CrossSectionArea: 0.425 m2; OuterSurfaceArea: 0.616256 m2; TotalSurfaceArea: 1.46626 m2; GrossSurfaceArea: 1.46626 m2; GrossVolume: 0.12325 m3; NetSurfaceArea: 1.46626 m2; NetVolume: 0.0996889 m3

# IfcBeam: beton_gewapend C 510 x 1200
In: -1 Fundering
Type - PredefinedType: BEAM
Material: beton_gewapend C
BaseQuantities - NetSurfaceAreaExtrudedSides: 6.3357 m2; Length: 2500.1 mm; Width: 510 mm; Depth: 1200 mm; CrossSectionArea: 0.612 m2; OuterSurfaceArea: 6.3357 m2; TotalSurfaceArea: 7.5597 m2; GrossSurfaceArea: 7.5597 m2; GrossVolume: 1.53003 m3; NetSurfaceArea: 7.5597 m2; NetVolume: 0.885198 m3
Pset_BeamCommon - Slope: 0 deg; IsExternal: no; LoadBearing: yes; Reference: beton_gewapend C 510 x 1200

# IfcBeam: beton_gewapend C 550 x 900
In: -1 Fundering
Type - PredefinedType: BEAM
Material: beton_gewapend C
BaseQuantities - NetSurfaceAreaExtrudedSides: 53.7039 m2; Length: 21269.1 mm; Width: 550.007 mm; Depth: 900 mm; CrossSectionArea: 0.495006 m2; OuterSurfaceArea: 53.7039 m2; TotalSurfaceArea: 54.6939 m2; GrossSurfaceArea: 54.6939 m2; GrossVolume: 10.5283 m3; NetSurfaceArea: 54.6939 m2; NetVolume: 9.81036 m3
Pset_BeamCommon - Slope: 0 deg; IsExternal: no; LoadBearing: yes; Reference: beton_gewapend C 550 x 900

# IfcBeam: beton_gewapend C 580 x 900
In: -1 Fundering
Type - PredefinedType: BEAM
Material: beton_gewapend C
Pset_BeamCommon - Slope: 0 deg; IsExternal: no; LoadBearing: yes; Reference: beton_gewapend C 580 x 900
BaseQuantities - NetSurfaceAreaExtrudedSides: 3.328 m2; Length: 1600 mm; Width: 580 mm; Depth: 900 mm; CrossSectionArea: 0.522 m2; OuterSurfaceArea: 3.328 m2; TotalSurfaceArea: 4.372 m2; GrossSurfaceArea: 4.372 m2; GrossVolume: 0.8352 m3; NetSurfaceArea: 4.372 m2; NetVolume: 0.696 m3

# IfcBeam: beton_gewapend C 600 x 1150 (8)
In: -1 Fundering
Type - PredefinedType: BEAM
Material: beton_gewapend C
Pset_BeamCommon - Slope: 0 deg; IsExternal: no; LoadBearing: yes; Reference: beton_gewapend C 600 x 1150
BaseQuantities - Width: 600 mm; Depth: 1150 mm; CrossSectionArea: 0.69 m2
Name | NetSurfaceAreaExtrudedSides (m2) = OuterSurfaceArea (m2) | Length (mm) | TotalSurfaceArea (m2) = GrossSurfaceArea (m2) = NetSurfaceArea (m2) | GrossVolume (m3) | NetVolume (m3)
 | 5.22441 | 2700 | 6.60441 | 1.863 | 1.06532
4 x  | 0.798 | 600 | 2.178 | 0.414 | 0.1854
 | 1.1438 | 860 | 2.5238 | 0.8004 | 0.26574
 | 1.5785 | 1160 | 2.9585 | 0.8004 | 0.3615
 | 7.90738 | 2700 | 9.28738 | 1.863 | 1.70318

# IfcBeam: beton_gewapend C 600 x 480
In: 01 1e verdieping
Type - PredefinedType: BEAM
Material: beton_gewapend C
BaseQuantities - NetSurfaceAreaExtrudedSides: 7.776 m2; Length: 3600 mm; Width: 600 mm; Depth: 480 mm; CrossSectionArea: 0.288 m2; OuterSurfaceArea: 7.776 m2; TotalSurfaceArea: 8.352 m2; GrossSurfaceArea: 8.352 m2; GrossVolume: 1.2672 m3; NetSurfaceArea: 8.352 m2; NetVolume: 1.0368 m3
Pset_BeamCommon - Slope: 0 deg; IsExternal: no; LoadBearing: yes; Reference: beton_gewapend C 600 x 480

# IfcBeam: beton_gewapend C 600 x 500
In: -1 Fundering
Type - PredefinedType: BEAM
Material: beton_gewapend C
BaseQuantities - NetSurfaceAreaExtrudedSides: 0.975001 m2; Length: 750 mm; Width: 600 mm; Depth: 500 mm; CrossSectionArea: 0.3 m2; OuterSurfaceArea: 0.975001 m2; TotalSurfaceArea: 1.575 m2; GrossSurfaceArea: 1.575 m2; GrossVolume: 0.225 m3; NetSurfaceArea: 1.575 m2; NetVolume: 0.1575 m3
Pset_BeamCommon - Slope: 0 deg; IsExternal: no; LoadBearing: yes; Reference: beton_gewapend C 600 x 500

# IfcBeam: beton_gewapend C 600 x 650 (41)
In: -1 Fundering
Type - PredefinedType: BEAM
Material: beton_gewapend C
Pset_BeamCommon - Slope: 0 deg; IsExternal: no; LoadBearing: yes; Reference: beton_gewapend C 600 x 650
BaseQuantities - Width: 600 mm
Name | NetSurfaceAreaExtrudedSides (m2) = OuterSurfaceArea (m2) | Length (mm) | Depth (mm) | CrossSectionArea (m2) | TotalSurfaceArea (m2) = GrossSurfaceArea (m2) = NetSurfaceArea (m2) | GrossVolume (m3) | NetVolume (m3)
 | 2.27693 | 1600 | 650.055 | 0.390033 | 3.05699 | 0.624053 | 0.25085
5 x  | 2.85832 | 1905.55 | 650 | 0.39 | 3.63832 | 0.743163 | 0.238193
4 x  | 2.5232 | 1520 | 650 | 0.39 | 3.3032 | 0.7098 | 0.48336
 | 2.25511 | 1600 | 650.055 | 0.390033 | 3.03518 | 0.624053 | 0.262123
7 x  | 2.4 | 1600 | 650 | 0.39 | 3.18 | 0.624 | 0.2
2 x  | 2.35943 | 1600 | 650.055 | 0.390033 | 3.13949 | 0.624053 | 0.275162
2 x  | 0.9 | 600 | 650 | 0.39 | 1.68 | 0.234 | 0.075
6 x  | 1.76 | 800 | 650 | 0.39 | 2.54 | 0.39 | 0.24
 | 3.817 | 1735 | 650 | 0.39 | 4.597 | 0.75465 | 0.5205
 | 3.6595 | 2485 | 650 | 0.39 | 4.4395 | 0.96915 | 0.300017
 | 2.06026 | 1400 | 650 | 0.39 | 2.84026 | 0.624 | 0.171079
 | 2.76026 | 1905.55 | 650 | 0.39 | 3.54026 | 0.743163 | 0.225936
 | 2.24 | 1600 | 650 | 0.39 | 3.02 | 0.624 | 0.18
 | 2.1 | 1400 | 650 | 0.39 | 2.88 | 0.624 | 0.175
 | 1.323 | 735 | 650 | 0.39 | 2.103 | 0.36465 | 0.119437
 | 2.39999 | 1600 | 650 | 0.39 | 3.17999 | 0.624 | 0.199997
 | 2.19975 | 999.886 | 650 | 0.39 | 2.97975 | 0.389956 | 0.299966
 | 4.17278 | 2781.85 | 650 | 0.39 | 4.95278 | 1.08492 | 0.347732
 | 4.8 | 3200 | 650 | 0.39 | 5.58 | 1.248 | 0.4
 | 3.6314 | 1650.64 | 650 | 0.39 | 4.4114 | 0.721749 | 0.495191
 | 0.99 | 600 | 650 | 0.39 | 1.77 | 0.234 | 0.08625

# IfcBeam: beton_gewapend C 600 x 850 (3)
In: Kelder
Type - PredefinedType: BEAM
Material: beton_gewapend C
Pset_BeamCommon - Slope: 0 deg; IsExternal: no; LoadBearing: yes; Reference: beton_gewapend C 600 x 850
BaseQuantities - Width: 600 mm; Depth: 850 mm; CrossSectionArea: 0.51 m2
Name | NetSurfaceAreaExtrudedSides (m2) = OuterSurfaceArea (m2) | Length (mm) | TotalSurfaceArea (m2) = GrossSurfaceArea (m2) = NetSurfaceArea (m2) | GrossVolume (m3) | NetVolume (m3)
 | 1.54251 | 800 | 2.56251 | 0.714 | 0.193626
 | 2.93163 | 1400 | 3.95163 | 0.714 | 0.560556
 | 3.0329 | 1310 | 4.0529 | 0.6681 | 0.547512

# IfcBeam: beton_gewapend C 600 x 900 (7)
In: -1 Fundering
Type - PredefinedType: BEAM
Material: beton_gewapend C
Pset_BeamCommon - Slope: 0 deg; IsExternal: no; LoadBearing: yes; Reference: beton_gewapend C 600 x 900
BaseQuantities - Width: 600 mm; Depth: 900 mm; CrossSectionArea: 0.54 m2
Name | NetSurfaceAreaExtrudedSides (m2) = OuterSurfaceArea (m2) | Length (mm) | TotalSurfaceArea (m2) = GrossSurfaceArea (m2) = NetSurfaceArea (m2) | GrossVolume (m3) | NetVolume (m3)
 | 0.78 | 600 | 1.86 | 0.324 | 0.05175
 | 2.64 | 1600 | 3.72 | 0.864 | 0.18
 | 7.69888 | 3325 | 8.77888 | 1.50469 | 1.23931
 | 0.99 | 600 | 2.07 | 0.324 | 0.0675
 | 0.751837 | 400 | 1.83184 | 0.324 | 0.0495919
 | 0.714712 | 400 | 1.79471 | 0.324 | 0.0470606
 | 5.12917 | 1755 | 6.20917 | 1.0557 | 0.934117

# IfcBeam: beton_gewapend C 61 x 500
In: -1 Fundering
Type - PredefinedType: BEAM
Material: beton_gewapend C
BaseQuantities - NetSurfaceAreaExtrudedSides: 4.36153 m2; Length: 3890 mm; Width: 60.6062 mm; Depth: 500.002 mm; CrossSectionArea: 0.0303032 m2; OuterSurfaceArea: 4.36153 m2; TotalSurfaceArea: 4.42214 m2; GrossSurfaceArea: 4.42214 m2; GrossVolume: 0.11788 m3; NetSurfaceArea: 4.42214 m2; NetVolume: 0.11788 m3
Pset_BeamCommon - Slope: 0 deg; IsExternal: no; LoadBearing: yes; Reference: beton_gewapend C 61 x 500

# IfcBeam: beton_gewapend C 635 x 650 (2)
In: -1 Fundering
Type - PredefinedType: BEAM
Material: beton_gewapend C
Pset_BeamCommon - Slope: 0 deg; IsExternal: no; LoadBearing: yes; Reference: beton_gewapend C 635 x 650
BaseQuantities - Width: 635 mm; Depth: 650 mm; CrossSectionArea: 0.41275 m2
Name | NetSurfaceAreaExtrudedSides (m2) = OuterSurfaceArea (m2) | Length (mm) | TotalSurfaceArea (m2) = GrossSurfaceArea (m2) = NetSurfaceArea (m2) | GrossVolume (m3) | NetVolume (m3)
 | 2.47684 | 1017.28 | 3.30234 | 0.419884 | 0.362725
 | 1.21224 | 600.007 | 2.03774 | 0.247653 | 0.193288

# IfcBeam: beton_gewapend C 800 x 480 (2)
In: 01 1e verdieping
Type - PredefinedType: BEAM
Material: beton_gewapend C
Pset_BeamCommon - Slope: 0 deg; IsExternal: no; LoadBearing: yes; Reference: beton_gewapend C 800 x 480
BaseQuantities - Width: 800 mm; Depth: 480 mm; CrossSectionArea: 0.384 m2
Name | NetSurfaceAreaExtrudedSides (m2) = OuterSurfaceArea (m2) | Length (mm) | TotalSurfaceArea (m2) = GrossSurfaceArea (m2) = NetSurfaceArea (m2) | GrossVolume (m3) | NetVolume (m3)
 | 53.3864 | 20854.1 | 54.1544 | 9.12201 | 8.00796
 | 11.264 | 4400 | 12.032 | 1.6896 | 1.6896

# IfcBeam: beton_gewapend C 800 x 620 (12)
In: 01 1e verdieping
Type - PredefinedType: BEAM
Material: beton_gewapend C
Pset_BeamCommon - Slope: 0 deg; IsExternal: no; LoadBearing: yes; Reference: beton_gewapend C 800 x 620
BaseQuantities - Width: 800 mm; Depth: 620 mm; CrossSectionArea: 0.496 m2
Name | NetSurfaceAreaExtrudedSides (m2) = OuterSurfaceArea (m2) | Length (mm) | TotalSurfaceArea (m2) = GrossSurfaceArea (m2) = NetSurfaceArea (m2) | GrossVolume (m3) | NetVolume (m3)
 | 27.5616 | 15840 | 28.5536 | 8.00544 | 5.95584
2 x  | 12.0558 | 4245 | 13.0478 | 2.10552 | 2.10552
 | 27.798 | 15990 | 28.79 | 8.07984 | 6.012
 | 4.57774 | 2645 | 5.56974 | 1.51032 | 0.99428
 | 6.9976 | 4650 | 7.9896 | 2.3064 | 0.670286
 | 7.9053 | 4400 | 8.8973 | 2.1824 | 1.75412
 | 8.13049 | 4525.11 | 9.12249 | 2.24445 | 1.80416
 | 56.8 | 20000 | 57.792 | 9.92 | 9.92
 | 6.003 | 3450 | 6.995 | 2.2568 | 1.2972
 | 12.8998 | 4650 | 13.8918 | 2.3064 | 2.28409
 | 12.496 | 4400 | 13.488 | 2.1824 | 2.1824

# IfcBeam: beton_gewapend C 870 x 480
In: 01 1e verdieping
Type - PredefinedType: BEAM
Material: beton_gewapend C
Pset_BeamCommon - Slope: 0 deg; IsExternal: no; LoadBearing: yes; Reference: beton_gewapend C 870 x 480
BaseQuantities - NetSurfaceAreaExtrudedSides: 2.32649 m2; Length: 1029.08 mm; Width: 870 mm; Depth: 480 mm; CrossSectionArea: 0.4176 m2; OuterSurfaceArea: 2.32649 m2; TotalSurfaceArea: 3.16169 m2; GrossSurfaceArea: 3.16169 m2; GrossVolume: 0.429742 m3; NetSurfaceArea: 3.16169 m2; NetVolume: 0.32677 m3

# IfcBeam: beton_gewapend C 950 x 650
In: -1 Fundering
Type - PredefinedType: BEAM
Material: beton_gewapend C
Pset_BeamCommon - Slope: 0 deg; IsExternal: no; LoadBearing: yes; Reference: beton_gewapend C 950 x 650
BaseQuantities - NetSurfaceAreaExtrudedSides: 6.58125 m2; Length: 3375 mm; Width: 950 mm; Depth: 650 mm; CrossSectionArea: 0.6175 m2; OuterSurfaceArea: 6.58125 m2; TotalSurfaceArea: 7.81625 m2; GrossSurfaceArea: 7.81625 m2; GrossVolume: 2.36194 m3; NetSurfaceArea: 7.81625 m2; NetVolume: 1.60313 m3

# IfcBeam: beton_gewapend_prefab 400 x 880 (4)
In: 03 3e tussenverdieping
Type - PredefinedType: BEAM
Material: beton_gewapend_prefab
Pset_BeamCommon - Slope: 0 deg; IsExternal: no; LoadBearing: yes; Reference: beton_gewapend_prefab 400 x 880
BaseQuantities - NetSurfaceAreaExtrudedSides: 38.818 m2; Length: 16035 mm; Width: 400 mm; Depth: 880 mm; CrossSectionArea: 0.352 m2; OuterSurfaceArea: 38.818 m2; TotalSurfaceArea: 39.522 m2; GrossSurfaceArea: 39.522 m2; GrossVolume: 5.34337 m3; NetSurfaceArea: 39.522 m2; NetVolume: 5.33479 m3

# IfcBeam: beton_gewapend_prefab 400 x 896 (4)
In: 03 3e tussenverdieping
Type - PredefinedType: BEAM
Material: beton_gewapend_prefab
Pset_BeamCommon - Slope: 7.79221 deg; IsExternal: no; LoadBearing: yes; Reference: beton_gewapend_prefab 400 x 896
BaseQuantities - NetVolume: 0.00589056 m3; GrossVolume: 0.00589056 m3; Length: 89.1605 mm

# IfcBeam: beton_gewapend_prefab 400 x 900 (4)
In: 03 3e tussenverdieping
Type - PredefinedType: BEAM
Material: beton_gewapend_prefab
Pset_BeamCommon - Slope: -8.48638 deg; IsExternal: no; LoadBearing: yes; Reference: beton_gewapend_prefab 400 x 900
BaseQuantities - NetVolume: 0.209156 m3; GrossVolume: 0.209156 m3; Length: 1761.8 mm

# IfcBeam: stalen gevelschermafdekker 255 x 35 (4)
In: 04 4e verdieping
Type - PredefinedType: BEAM
Material: staal
Pset_BeamCommon - Slope: 0 deg; IsExternal: no; LoadBearing: yes; Reference: stalen gevelschermafdekker 255 x 35
BaseQuantities - CrossSectionArea: 0.000312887 m2
Name | NetSurfaceAreaExtrudedSides (m2) = OuterSurfaceArea (m2) | Length (mm) | TotalSurfaceArea (m2) = GrossSurfaceArea (m2) = NetSurfaceArea (m2) | GrossVolume (m3) = NetVolume (m3)
Info_Balk_stalen | 3.89538 | 6449.96 | 3.89601 | 0.00194125
2 x Info_Balk_stalen | 26.3894 | 42270 | 26.3901 | 0.0131489
Info_Balk_stalen | 3.90229 | 6461.03 | 3.90292 | 0.00194469

# IfcBuildingElementPart (1683)
Name | In | Material
329 x gipsplaat | 00 Begane grond | gipsplaat
84 x isolatie_steenwol LSW | 00 Begane grond | isolatie_steenwol LSW
2 x kalkzandsteen C | 00 Begane grond | kalkzandsteen C
3 x metselwerk AFW | 00 Begane grond | metselwerk AFW
metselwerk C | 00 Begane grond | metselwerk C
9 x metal_stud | 00 Begane grond | metal_stud
12 x isolatie_houtvezel | 00 Begane grond | isolatie_houtvezel
12 x hout_OSB | 00 Begane grond | hout_OSB
6 x brandwerende_bekleding | 00 Begane grond | brandwerende_bekleding
6 x folie_dampdicht | 00 Begane grond | folie_dampdicht
6 x folie_dampopen | 00 Begane grond | folie_dampopen
6 x metaal - Aluminium gevelplaat | 00 Begane grond | metaal - Aluminium gevelplaat
isolatie _steenwol_hard | 00 Begane grond | isolatie _steenwol_hard
6 x isolatie_steenwol | 00 Begane grond | isolatie_steenwol
2 x ALG - ISOLATIE met lijn | 00 Begane grond | ALG - ISOLATIE met lijn
2 x Rubber | 00 Begane grond | Rubber
2 x gevelafwerking type 3 - Aluminium RAL1036 | 00 Begane grond | gevelafwerking type 3 - Aluminium RAL1036
isolatie_kunststof_zacht | 00 Begane grond | isolatie_kunststof_zacht
2 x isolatie _steenwol_hard | 01 1e tussenverdieping | isolatie _steenwol_hard
2 x folie_dampopen | 01 1e tussenverdieping | folie_dampopen
2 x isolatie_houtvezel | 01 1e tussenverdieping | isolatie_houtvezel
2 x brandwerende_bekleding | 01 1e tussenverdieping | brandwerende_bekleding
2 x hout_OSB | 01 1e tussenverdieping | hout_OSB
2 x folie_dampdicht | 01 1e tussenverdieping | folie_dampdicht
43 x gipsplaat | 01 1e tussenverdieping | gipsplaat
2 x metaal - Aluminium gevelplaat | 01 1e tussenverdieping | metaal - Aluminium gevelplaat
2 x metal_stud | 01 1e tussenverdieping | metal_stud
12 x isolatie_steenwol LSW | 01 1e tussenverdieping | isolatie_steenwol LSW
4 x kalkzandsteen C | 01 1e verdieping | kalkzandsteen C
5 x metselwerk AFW | 01 1e verdieping | metselwerk AFW
247 x gipsplaat | 01 1e verdieping | gipsplaat
64 x isolatie_steenwol LSW | 01 1e verdieping | isolatie_steenwol LSW
6 x metal_stud | 01 1e verdieping | metal_stud
8 x metaal - Aluminium gevelplaat | 01 1e verdieping | metaal - Aluminium gevelplaat
8 x folie_dampopen | 01 1e verdieping | folie_dampopen
8 x brandwerende_bekleding | 01 1e verdieping | brandwerende_bekleding
8 x isolatie_houtvezel | 01 1e verdieping | isolatie_houtvezel
8 x folie_dampdicht | 01 1e verdieping | folie_dampdicht
8 x hout_OSB | 01 1e verdieping | hout_OSB
metselwerk C | 01 1e verdieping | metselwerk C
cement | 01 1e verdieping | cement
beton_gewapend_vloer C | 01 1e verdieping | beton_gewapend_vloer C
8 x isolatie_steenwol | 01 1e verdieping | isolatie_steenwol
79 x gipsplaat | 02 2e tussenverdieping | gipsplaat
21 x isolatie_steenwol LSW | 02 2e tussenverdieping | isolatie_steenwol LSW
3 x hout_OSB | 02 2e tussenverdieping | hout_OSB
3 x isolatie_houtvezel | 02 2e tussenverdieping | isolatie_houtvezel
2 x folie_dampdicht | 02 2e tussenverdieping | folie_dampdicht
2 x brandwerende_bekleding | 02 2e tussenverdieping | brandwerende_bekleding
2 x folie_dampopen | 02 2e tussenverdieping | folie_dampopen
2 x metaal - Aluminium gevelplaat | 02 2e tussenverdieping | metaal - Aluminium gevelplaat
4 x isolatie_steenwol | 02 2e tussenverdieping | isolatie_steenwol
2 x metal_stud | 02 2e tussenverdieping | metal_stud
isolatie _steenwol_hard | 02 2e tussenverdieping | isolatie _steenwol_hard
113 x gipsplaat | 02 2e verdieping | gipsplaat
30 x isolatie_steenwol LSW | 02 2e verdieping | isolatie_steenwol LSW
4 x metal_stud | 02 2e verdieping | metal_stud
metselwerk C | 02 2e verdieping | metselwerk C
metselwerk AFW | 02 2e verdieping | metselwerk AFW
3 x hout_OSB | 02 2e verdieping | hout_OSB
3 x folie_dampdicht | 02 2e verdieping | folie_dampdicht
3 x metaal - Aluminium gevelplaat | 02 2e verdieping | metaal - Aluminium gevelplaat
3 x brandwerende_bekleding | 02 2e verdieping | brandwerende_bekleding
3 x folie_dampopen | 02 2e verdieping | folie_dampopen
3 x isolatie_houtvezel | 02 2e verdieping | isolatie_houtvezel
4 x isolatie_steenwol | 02 2e verdieping | isolatie_steenwol
4 x ALG - ISOLATIE met lijn | 02 2e verdieping | ALG - ISOLATIE met lijn
4 x Rubber | 02 2e verdieping | Rubber
4 x gevelafwerking type 3 - Aluminium RAL1036 | 02 2e verdieping | gevelafwerking type 3 - Aluminium RAL1036
2 x isolatie_kunststof_zacht | 02 2e verdieping | isolatie_kunststof_zacht
2 x isolatie_houtvezel | 03 3e tussenverdieping | isolatie_houtvezel
2 x hout_OSB | 03 3e tussenverdieping | hout_OSB
40 x gipsplaat | 03 3e tussenverdieping | gipsplaat
12 x isolatie_steenwol LSW | 03 3e tussenverdieping | isolatie_steenwol LSW
24 x aluminium | 03 3e tussenverdieping | aluminium
36 x aluminium | 04 4e verdieping | aluminium
310 x gevelafwerking type 3 - Aluminium RAL1036 | 04 4e verdieping | gevelafwerking type 3 - Aluminium RAL1036
2 x Rubber | 04 4e verdieping | Rubber
2 x ALG - ISOLATIE met lijn | 04 4e verdieping | ALG - ISOLATIE met lijn
isolatie_kunststof_zacht | 04 4e verdieping | isolatie_kunststof_zacht

# IfcBuildingElementProxy: Boekenkast 04 27 KM (12)
Type - ElementType: Massing; PredefinedType: USERDEFINED
Name | In
5 x 72_Brandslanghaspelkast_Lege | 00 Begane grond
7 x 72_Brandslanghaspelkast_Lege | 02 2e tussenverdieping

# IfcBuildingElementProxy: Zonnepaneel 27 KM (53)
Type - ElementType: PROVISIONFORVOID; PredefinedType: USERDEFINED
Name | In
6 x 61_Sanitair-x_Lege | 03 3e tussenverdieping
47 x 61_Sanitair-x_Lege | 04 4e verdieping

# IfcBuildingElementProxy: nulpunt_brique, 99_Wasmachine_Lege
In: 00 Begane grond
Type - ElementType: Massing; PredefinedType: USERDEFINED
Material: ALG - ALGEMEEN

# IfcColumn: ALG - ALGEMEEN 100 x 200 (8)
Type - PredefinedType: COLUMN
Material: ALG - ALGEMEEN
Pset_ColumnCommon - Slope: 90 deg; IsExternal: no; LoadBearing: yes; Reference: ALG - ALGEMEEN 100 x 200
BaseQuantities - Width: 100 mm; Depth: 200 mm; CrossSectionArea: 0.02 m2
Name | In | Length (mm) | OuterSurfaceArea (m2) | TotalSurfaceArea (m2) = GrossSurfaceArea (m2) | GrossVolume (m3) = NetVolume (m3)
4 x 77_Kolom_ALG | 00 Begane grond | 2434.5 | 1.4607 | 1.4807 | 0.04869
4 x 77_Kolom_ALG | 02 2e tussenverdieping | 2514.5 | 1.5087 | 1.5287 | 0.05029

# IfcColumn: ALG - ALGEMEEN 110 x 210 (4)
Type - PredefinedType: COLUMN
Material: ALG - ALGEMEEN
Pset_ColumnCommon - Slope: 90 deg; IsExternal: no; LoadBearing: yes; Reference: ALG - ALGEMEEN 110 x 210
BaseQuantities - Width: 110 mm; Depth: 210.001 mm; CrossSectionArea: 0.0231001 m2
Name | In | Length (mm) | OuterSurfaceArea (m2) | TotalSurfaceArea (m2) = GrossSurfaceArea (m2) | GrossVolume (m3) = NetVolume (m3)
2 x 77_Kolom_ALG | 00 Begane grond | 2434.5 | 1.5581 | 1.5812 | 0.0562383
2 x 77_Kolom_ALG | 02 2e tussenverdieping | 2514.5 | 1.6093 | 1.6324 | 0.0580862

# IfcColumn: ALG - ALGEMEEN D100 (2)
Type - PredefinedType: COLUMN
Material: ALG - ALGEMEEN
Pset_ColumnCommon - Slope: 90 deg; IsExternal: no; LoadBearing: yes; Reference: ALG - ALGEMEEN D100
BaseQuantities - Width: 100 mm; Depth: 100 mm; CrossSectionArea: 0.00785398 m2
Name | In | Length (mm) | OuterSurfaceArea (m2) | TotalSurfaceArea (m2) = GrossSurfaceArea (m2) | GrossVolume (m3) = NetVolume (m3)
77_Kolom_ALG | 00 Begane grond | 2484.5 | 0.775523 | 0.783177 | 0.0190155
77_Kolom_ALG | 02 2e tussenverdieping | 2514.5 | 0.784887 | 0.792541 | 0.0192451

# IfcColumn: HEB220 220 x 220 (46)
In: 04 4e verdieping
Type - PredefinedType: COLUMN
Material: staal C
Pset_ColumnCommon - Slope: 90 deg; IsExternal: no; LoadBearing: yes; Reference: HEB220 220 x 220
BaseQuantities - CrossSectionArea: 0.008826 m2
Name | Length (mm) | OuterSurfaceArea (m2) | TotalSurfaceArea (m2) = GrossSurfaceArea (m2) | GrossVolume (m3) = NetVolume (m3)
2 x 28_Kolom_HEB220 | 2630 | 3.42163 | 3.43928 | 0.0232124
22 x 28_Kolom_HEB220 | 474.266 | 0.61702 | 0.634672 | 0.00418587
20 x 28_Kolom_HEB220 | 2595.73 | 3.37705 | 3.3947 | 0.02291
2 x 28_Kolom_HEB220 | 2375.73 | 3.09083 | 3.10848 | 0.0209682

# IfcColumn: Profiel H algemeen 100 x 96 (18)
Type - PredefinedType: COLUMN
Material: staal C
Pset_ColumnCommon - Slope: 90 deg; IsExternal: no; LoadBearing: yes; Reference: Profiel H algemeen 100 x 96
BaseQuantities - CrossSectionArea: 0.002 m2
Name | In | Length (mm) | OuterSurfaceArea (m2) | TotalSurfaceArea (m2) = GrossSurfaceArea (m2) | GrossVolume (m3) = NetVolume (m3)
2 x 28_Kolom_Profiel | 00 Begane grond | 5495 | 3.19809 | 3.20209 | 0.01099
14 x 28_Kolom_Profiel | 01 1e verdieping | 3790 | 2.20578 | 2.20978 | 0.00758
28_Kolom_Profiel | 02 2e tussenverdieping | 5575 | 3.24465 | 3.24865 | 0.01115
28_Kolom_Profiel | 02 2e tussenverdieping | 5545 | 3.22719 | 3.23119 | 0.01109

# IfcColumn: Profiel H algemeen 120 x 120 (8)
Type - PredefinedType: COLUMN
Material: staal C
Pset_ColumnCommon - Slope: 90 deg; IsExternal: no; LoadBearing: yes; Reference: Profiel H algemeen 120 x 120
BaseQuantities - CrossSectionArea: 0.00327702 m2
Name | In | Length (mm) | OuterSurfaceArea (m2) | TotalSurfaceArea (m2) = GrossSurfaceArea (m2) | GrossVolume (m3) = NetVolume (m3)
4 x 28_Kolom_Profiel | 00 Begane grond | 5495 | 3.885 | 3.89155 | 0.0180072
4 x 28_Kolom_Profiel | 02 2e tussenverdieping | 5545 | 3.92035 | 3.9269 | 0.0181711

# IfcColumn: Profiel H algemeen 140 x 133, 28_Kolom_Profiel
In: Kelder
Type - PredefinedType: COLUMN
Material: staal C
Pset_ColumnCommon - Slope: 90 deg; IsExternal: no; LoadBearing: yes; Reference: Profiel H algemeen 140 x 133
BaseQuantities - Length: 3580 mm; CrossSectionArea: 0.00321001 m2; OuterSurfaceArea: 2.91413 m2; TotalSurfaceArea: 2.92055 m2; GrossSurfaceArea: 2.92055 m2; GrossVolume: 0.0114918 m3; NetVolume: 0.0114918 m3

# IfcColumn: Profiel H algemeen 160 x 160 (4)
Type - PredefinedType: COLUMN
Material: staal C
Pset_ColumnCommon - Slope: 90 deg; IsExternal: no; LoadBearing: yes; Reference: Profiel H algemeen 160 x 160
BaseQuantities - CrossSectionArea: 0.00523218 m2
Name | In | Length (mm) | OuterSurfaceArea (m2) | TotalSurfaceArea (m2) = GrossSurfaceArea (m2) | GrossVolume (m3) = NetVolume (m3)
28_Kolom_Profiel | 00 Begane grond | 3188 | 1.66044 | 1.66858 | 0.0097502
28_Kolom_Profiel | 01 1e verdieping | 2095 | 1.97768 | 1.98815 | 0.0109614
28_Kolom_Profiel | 02 2e tussenverdieping | 2155 | 2.03432 | 2.04479 | 0.0112754
28_Kolom_Profiel | 03 3e tussenverdieping | 3207 | 3.02741 | 3.03788 | 0.0167796

# IfcColumn: Profiel UPN algemeen 60 x 140 (16)
Type - PredefinedType: COLUMN
Material: staal
BaseQuantities - Length: 700 mm; CrossSectionArea: 0.00204001 m2; OuterSurfaceArea: 0.354202 m2; TotalSurfaceArea: 0.358282 m2; GrossSurfaceArea: 0.358282 m2; GrossVolume: 0.00142801 m3; NetVolume: 0.00142801 m3
Pset_ColumnCommon - Slope: 90 deg; IsExternal: no; LoadBearing: yes; Reference: Profiel UPN algemeen 60 x 140
Name | In
8 x 28_Kolom_Profiel | 00 Begane grond
8 x 28_Kolom_Profiel | 02 2e tussenverdieping

# IfcColumn: Profiel vierkant 100 x 100 (4)
Type - PredefinedType: COLUMN
Material: staal C
Pset_ColumnCommon - Slope: 90 deg; IsExternal: no; LoadBearing: yes; Reference: Profiel vierkant 100 x 100
Name | In | Length (mm) | CrossSectionArea (m2) | OuterSurfaceArea (m2) | TotalSurfaceArea (m2) = GrossSurfaceArea (m2) | GrossVolume (m3) = NetVolume (m3)
28_Kolom_Profiel | 00 Begane grond | 12060 | 0.00294411 | 8.87649 | 8.88238 | 0.035506
28_Kolom_Profiel | 01 1e verdieping | 7820 | 0.002944 | 5.75552 | 5.76141 | 0.0230221
2 x 28_Kolom_Profiel | 01 1e verdieping | 9960 | 0.00294406 | 7.3307 | 7.33659 | 0.0293228

# IfcColumn: aluminium 60 x 130 (22)
Type - PredefinedType: COLUMN
Material: aluminium
BaseQuantities - Width: 60 mm; Depth: 130 mm; CrossSectionArea: 0.0078 m2
Pset_ColumnCommon - Slope: 90 deg; IsExternal: no; Reference: aluminium 60 x 130
Name | In | Length (mm) | OuterSurfaceArea (m2) | TotalSurfaceArea (m2) = GrossSurfaceArea (m2) | GrossVolume (m3) = NetVolume (m3)
11 x 41_Kolom_aluminium | 00 Begane grond | 5685 | 2.1603 | 2.1759 | 0.044343
11 x 41_Kolom_aluminium | 02 2e tussenverdieping | 5715 | 2.1717 | 2.1873 | 0.044577

# IfcColumn: aluminium zetwerk hoek vliesgevel 272 x 272 (4)
Type - PredefinedType: COLUMN
BaseQuantities - CrossSectionArea: 0.0582721 m2
Pset_ColumnCommon - Slope: 90 deg; IsExternal: no; LoadBearing: yes; Reference: aluminium zetwerk hoek vliesgevel 272 x 272
Name | In | Length (mm) | OuterSurfaceArea (m2) | TotalSurfaceArea (m2) = GrossSurfaceArea (m2) | GrossVolume (m3) = NetVolume (m3)
41_Kolom_aluminium | 00 Begane grond | 12060 | 25.2897 | 25.4062 | 0.702762
41_Kolom_aluminium | 02 2e verdieping | 3545 | 7.42519 | 7.53064 | 0.203351
41_Kolom_aluminium | 02 2e verdieping | 5785 | 12.123 | 12.2263 | 0.333121
41_Kolom_aluminium | 04 4e verdieping | 1535 | 3.21108 | 3.31453 | 0.0855928

# IfcColumn: beton_gewapend C 110 x 108 (8)
Type - PredefinedType: COLUMN
Material: beton_gewapend C
BaseQuantities - Length: 4050 mm; Width: 110 mm; CrossSectionArea: 0.0118442 m2; OuterSurfaceArea: 1.76316 m2
Pset_ColumnCommon - Slope: 90 deg; IsExternal: no; LoadBearing: yes; Reference: beton_gewapend C 110 x 108
Name | In | Depth (mm) | TotalSurfaceArea (m2) = GrossSurfaceArea (m2) | GrossVolume (m3) = NetVolume (m3)
4 x 28_Kolom_beton_gewapend | 01 1e verdieping | 107.674 | 1.78685 | 0.047969
4 x 28_Kolom_beton_gewapend | 02 2e verdieping | 107.675 | 1.77501 | 0.0479691

# IfcColumn: beton_gewapend C 350 x 550 (78)
Type - PredefinedType: COLUMN
Material: beton_gewapend C
Pset_ColumnCommon - Slope: 90 deg; IsExternal: no; LoadBearing: yes; Reference: beton_gewapend C 350 x 550
BaseQuantities - Width: 350 mm; Depth: 550 mm; CrossSectionArea: 0.1925 m2
Name | In | Length (mm) | OuterSurfaceArea (m2) | TotalSurfaceArea (m2) = GrossSurfaceArea (m2) | GrossVolume (m3) = NetVolume (m3)
32 x 28_Kolom_beton_gewapend | 01 1e verdieping | 4050 | 7.29 | 7.675 | 0.779625
28_Kolom_beton_gewapend | 01 1e verdieping | 4050 | 6.237 | 6.479 | 0.49005
28_Kolom_beton_gewapend | 01 1e verdieping | 4100 | 7.38 | 7.765 | 0.78925
28_Kolom_beton_gewapend | 01 1e verdieping | 4100 | 6.847 | 7.102 | 0.52275
28_Kolom_beton_gewapend | 01 1e verdieping | 4050 | 5.103 | 5.191 | 0.1782
12 x 28_Kolom_beton_gewapend | 02 2e verdieping | 3990 | 7.182 | 7.567 | 0.768075
27 x 28_Kolom_beton_gewapend | 02 2e verdieping | 4050 | 7.29 | 7.4825 | 0.779625
2 x 28_Kolom_beton_gewapend | 02 2e verdieping | 3990 | 7.0665 | 7.4515 | 0.759
28_Kolom_beton_gewapend | 02 2e verdieping | 3990 | 6.1446 | 6.3866 | 0.48279

# IfcColumn: betonblok C 108 x 110 (4)
Type - PredefinedType: COLUMN
Material: betonblok C
BaseQuantities - Width: 107.7 mm; Depth: 110 mm
Pset_ColumnCommon - Slope: 90 deg; IsExternal: no; LoadBearing: yes; Reference: betonblok C 108 x 110
Name | In | Length (mm) | CrossSectionArea (m2) | OuterSurfaceArea (m2) | TotalSurfaceArea (m2) = GrossSurfaceArea (m2) | GrossVolume (m3) = NetVolume (m3)
28_Kolom_betonblok | 00 Begane grond | 6205 | 0.011847 | 1.77685 | 1.79769 | 0.0572219
28_Kolom_betonblok | 00 Begane grond | 6175 | 0.011847 | 1.89269 | 1.90454 | 0.063775
28_Kolom_betonblok | 01 1e verdieping | 6245 | 0.0118471 | 1.7085 | 1.72649 | 0.0561854
28_Kolom_betonblok | 01 1e verdieping | 6245 | 0.0118471 | 1.91668 | 1.93762 | 0.0645496

# IfcColumn: betonblok C 110 x 108 (4)
In: 00 Begane grond
Type - PredefinedType: COLUMN
Material: betonblok C
BaseQuantities - Width: 110 mm; Depth: 107.675 mm; CrossSectionArea: 0.0118442 m2
Pset_ColumnCommon - Slope: 90 deg; IsExternal: no; LoadBearing: yes; Reference: betonblok C 110 x 108
Name | Length (mm) | OuterSurfaceArea (m2) | TotalSurfaceArea (m2) = GrossSurfaceArea (m2) | GrossVolume (m3) = NetVolume (m3)
2 x 28_Kolom_betonblok | 4130 | 1.79799 | 1.82168 | 0.0489166
28_Kolom_betonblok | 4250 | 1.5747 | 1.59085 | 0.0419527
28_Kolom_betonblok | 3137.5 | 1.36591 | 1.37775 | 0.0371612

# IfcColumn: betonblok C 175 x 195 (4)
Type - PredefinedType: COLUMN
Material: betonblok C
BaseQuantities - Width: 175.001 mm; Depth: 195 mm; CrossSectionArea: 0.0341251 m2
Pset_ColumnCommon - Slope: 90 deg; IsExternal: no; LoadBearing: yes; Reference: betonblok C 175 x 195
Name | In | Length (mm) | OuterSurfaceArea (m2) | TotalSurfaceArea (m2) = GrossSurfaceArea (m2) | GrossVolume (m3) = NetVolume (m3)
28_Kolom_betonblok | 00 Begane grond | 4250 | 2.77232 | 2.82692 | 0.129846
28_Kolom_betonblok | 00 Begane grond | 3137.5 | 1.46496 | 1.47871 | 0.0743789
28_Kolom_betonblok | 01 1e verdieping | 3227.5 | 2.08685 | 2.1551 | 0.0978538
28_Kolom_betonblok | 01 1e verdieping | 6095 | 3.73811 | 3.78003 | 0.172249

# IfcColumn: betonblok C 260 x 635, 28_Kolom_betonblok
In: Kelder
Type - PredefinedType: COLUMN
Material: betonblok C
Pset_ColumnCommon - Slope: 90 deg; IsExternal: no; LoadBearing: yes; Reference: betonblok C 260 x 635
BaseQuantities - Length: 3580 mm; Width: 260 mm; Depth: 635 mm; CrossSectionArea: 0.1651 m2; OuterSurfaceArea: 6.11195 m2; TotalSurfaceArea: 6.44215 m2; GrossSurfaceArea: 6.44215 m2; GrossVolume: 0.571296 m3; NetVolume: 0.571296 m3

# IfcColumn: betonblok C 350 x 550 (64)
Type - PredefinedType: COLUMN
Material: betonblok C
BaseQuantities - Width: 350 mm; Depth: 550 mm; CrossSectionArea: 0.1925 m2
Pset_ColumnCommon - Slope: 90 deg; IsExternal: no; LoadBearing: yes; Reference: betonblok C 350 x 550
Name | In | Length (mm) | OuterSurfaceArea (m2) | TotalSurfaceArea (m2) = GrossSurfaceArea (m2) | GrossVolume (m3) = NetVolume (m3)
28_Kolom_betonblok | Kelder | 3730 | 5.83319 | 6.11319 | 0.62177
28_Kolom_betonblok | Kelder | 3580 | 5.8265 | 6.1065 | 0.6209
28_Kolom_betonblok | Kelder | 3580 | 6.444 | 6.829 | 0.68915
28_Kolom_betonblok | Kelder | 3730 | 5.83319 | 6.11319 | 0.621737
13 x 28_Kolom_betonblok | 00 Begane grond | 3600 | 6.48 | 6.865 | 0.693
28_Kolom_betonblok | 00 Begane grond | 2515 | 4.527 | 4.912 | 0.484137
7 x 28_Kolom_betonblok | 00 Begane grond | 3650 | 6.525 | 6.91 | 0.697812
2 x 28_Kolom_betonblok | 00 Begane grond | 3615 | 6.4935 | 6.8785 | 0.694444
5 x 28_Kolom_betonblok | 00 Begane grond | 3650 | 6.525 | 6.91 | 0.697813
28_Kolom_betonblok | 00 Begane grond | 4250 | 5.49661 | 5.73741 | 0.458253
5 x 28_Kolom_betonblok | 00 Begane grond | 3650 | 6.57 | 6.955 | 0.702625
28_Kolom_betonblok | 00 Begane grond | 3650 | 6.5025 | 6.8875 | 0.693875
28_Kolom_betonblok | 00 Begane grond | 4130 | 3.6177 | 3.8267 | 0.406505
28_Kolom_betonblok | 00 Begane grond | 4070 | 5.55781 | 5.79981 | 0.457851
28_Kolom_betonblok | 00 Begane grond | 3615 | 6.507 | 6.892 | 0.695887
28_Kolom_betonblok | 00 Begane grond | 3600 | 6.3025 | 6.6625 | 0.60425
28_Kolom_betonblok | 00 Begane grond | 3150 | 5.67 | 6.055 | 0.606375
28_Kolom_betonblok | 00 Begane grond | 3600 | 6.075 | 6.46 | 0.649687
28_Kolom_betonblok | 00 Begane grond | 4070 | 6.82854 | 7.1751 | 0.742715
28_Kolom_betonblok | 00 Begane grond | 4070 | 3.73964 | 3.94864 | 0.412815
28_Kolom_betonblok | 00 Begane grond | 4250 | 7.5001 | 7.8851 | 0.795053
28_Kolom_betonblok | 01 1e verdieping | 6095 | 8.08438 | 8.27056 | 0.861669
28_Kolom_betonblok | 01 1e verdieping | 4050 | 5.48124 | 5.72204 | 0.43762
28_Kolom_betonblok | 01 1e verdieping | 3620 | 6.471 | 6.6635 | 0.692037
28_Kolom_betonblok | 01 1e verdieping | 4050 | 4.32437 | 4.48806 | 0.429264
28_Kolom_betonblok | 01 1e verdieping | 4050 | 6.59932 | 6.79377 | 0.688157
28_Kolom_betonblok | 01 1e verdieping | 4130 | 5.6826 | 5.8641 | 0.44649
28_Kolom_betonblok | 01 1e verdieping | 3227.5 | 4.29201 | 4.63927 | 0.478803
28_Kolom_betonblok | 01 1e verdieping | 4050 | 3.7665 | 3.9755 | 0.423225
28_Kolom_betonblok | 01 1e verdieping | 3880 | 3.5805 | 3.7895 | 0.402325
28_Kolom_betonblok | 02 2e verdieping | 4050 | 4.42474 | 4.52924 | 0.460026
28_Kolom_betonblok | 02 2e verdieping | 4050 | 5.68688 | 5.84165 | 0.626829
28_Kolom_betonblok | 02 2e verdieping | 3610 | 4.65883 | 4.71933 | 0.360816
28_Kolom_betonblok | 02 2e verdieping | 4050 | 5.17757 | 5.32609 | 0.563974
28_Kolom_betonblok | 02 2e verdieping | 3720 | 4.81333 | 4.99483 | 0.361961
28_Kolom_betonblok | 02 2e verdieping | 3660 | 6.54355 | 6.73605 | 0.699835
28_Kolom_betonblok | 02 2e verdieping | 3610 | 6.498 | 6.6905 | 0.694925

# IfcColumn: betonblok C 350 x 635 (3)
In: Kelder
Type - PredefinedType: COLUMN
Material: betonblok C
Pset_ColumnCommon - Slope: 90 deg; IsExternal: no; LoadBearing: yes; Reference: betonblok C 350 x 635
BaseQuantities - Length: 2930 mm; Width: 350 mm; Depth: 635 mm; CrossSectionArea: 0.22225 m2; OuterSurfaceArea: 5.7721 m2; TotalSurfaceArea: 5.99435 m2; GrossSurfaceArea: 5.99435 m2; GrossVolume: 0.651193 m3; NetVolume: 0.651193 m3

# IfcColumn: betonblok C 350 x 650 (24)
Type - PredefinedType: COLUMN
Material: betonblok C
Pset_ColumnCommon - Slope: 90 deg; IsExternal: no; LoadBearing: yes; Reference: betonblok C 350 x 650
BaseQuantities - Width: 350 mm; Depth: 650 mm; CrossSectionArea: 0.2275 m2
Name | In | Length (mm) | OuterSurfaceArea (m2) | TotalSurfaceArea (m2) = GrossSurfaceArea (m2) | GrossVolume (m3) = NetVolume (m3)
28_Kolom_betonblok | 00 Begane grond | 5525 | 7.14309 | 7.24709 | 1.16069
4 x 28_Kolom_betonblok | 00 Begane grond | 5495 | 10.99 | 10.99 | 1.25011
28_Kolom_betonblok | 00 Begane grond | 5495 | 7.2534 | 7.2534 | 1.19654
28_Kolom_betonblok | 00 Begane grond | 5525 | 8.17359 | 8.38349 | 0.976836
3 x 28_Kolom_betonblok | 00 Begane grond | 5345 | 8.67147 | 8.89644 | 0.896432
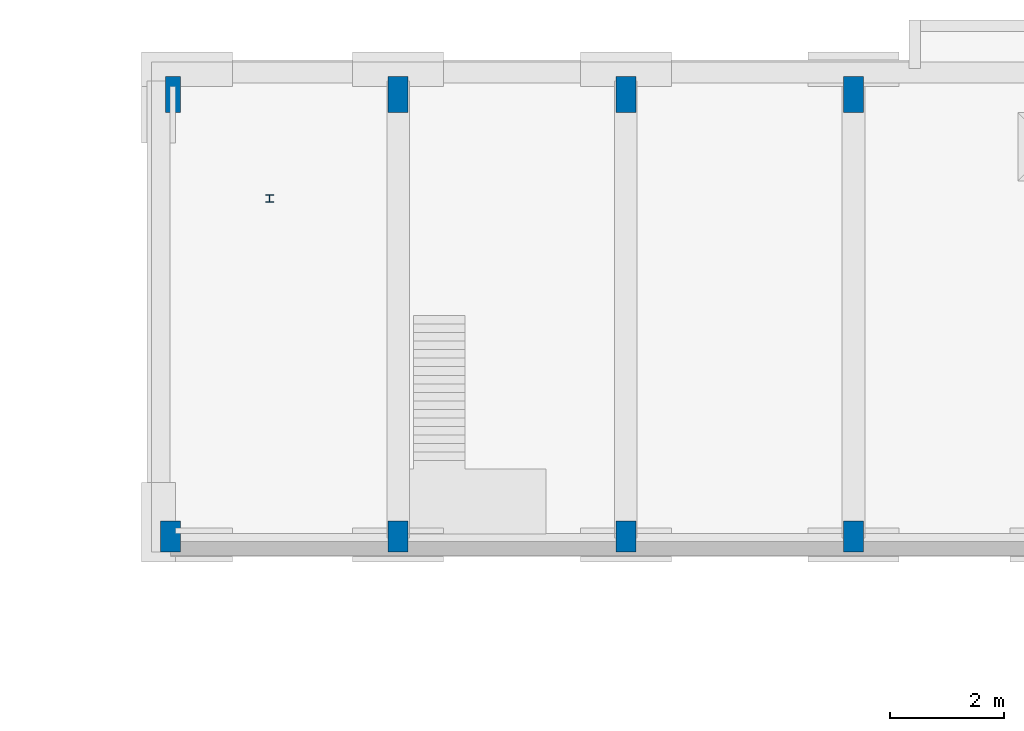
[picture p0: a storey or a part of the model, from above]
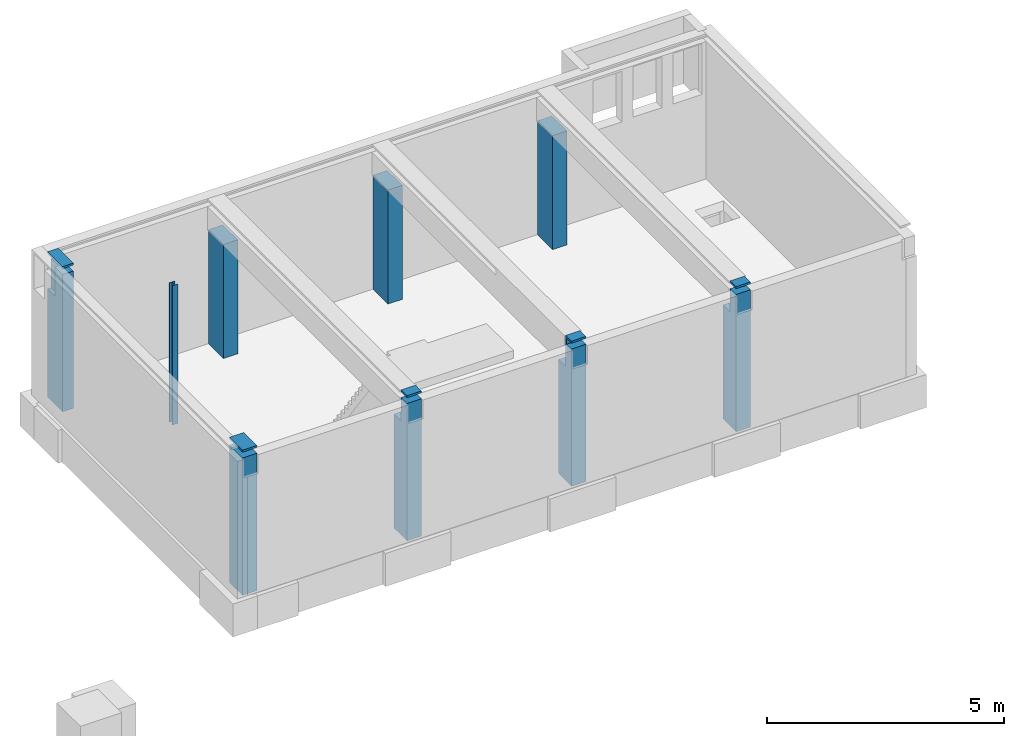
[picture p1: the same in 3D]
Properties of the parts of a building model (IFC2X3), part 3 of 5

# IfcColumn: betonblok C 350 x 650 (24)
Name | In | Length (mm) | OuterSurfaceArea (m2) | TotalSurfaceArea (m2) = GrossSurfaceArea (m2) | GrossVolume (m3) = NetVolume (m3)
28_Kolom_betonblok | 00 Begane grond | 5525 | 7.99376 | 8.21397 | 1.09992
28_Kolom_betonblok | 00 Begane grond | 5345 | 9.46763 | 9.6926 | 1.03576
28_Kolom_betonblok | 01 1e verdieping | 5545 | 7.63752 | 8.02515 | 1.03527
2 x 28_Kolom_betonblok | 01 1e verdieping | 5395 | 8.7391 | 9.0821 | 0.902143
28_fc_betonblok | 01 1e verdieping | 5395 | 8.7391 | 9.0821 | 0.902143
28_Kolom_betonblok | 01 1e verdieping | 5545 | 7.28512 | 7.69888 | 1.03285
4 x 28_Kolom_betonblok | 01 1e verdieping | 5545 | 11.09 | 11.545 | 1.26149
28_Kolom_betonblok | 01 1e verdieping | 5395 | 8.7391 | 9.0821 | 0.902142
28_Kolom_betonblok | 01 1e verdieping | 5545 | 7.3197 | 7.75845 | 1.20752
28_Kolom_betonblok | 01 1e verdieping | 5545 | 7.1984 | 7.61972 | 1.1681

# IfcColumn: betonblok C 400 x 3100, 28_Kolom_betonblok
In: 00 Begane grond
Type - PredefinedType: COLUMN
Material: betonblok C
Pset_ColumnCommon - Slope: 90 deg; IsExternal: no; LoadBearing: yes; Reference: betonblok C 400 x 3100
BaseQuantities - Length: 14310 mm; Width: 400.001 mm; Depth: 3100 mm; CrossSectionArea: 1.24 m2; OuterSurfaceArea: 92.0707 m2; TotalSurfaceArea: 93.3107 m2; GrossSurfaceArea: 93.3107 m2; GrossVolume: 16.3254 m3; NetVolume: 16.3254 m3

# IfcColumn: betonblok C 450 x 700 (8)
In: 01 1e verdieping
Type - PredefinedType: COLUMN
Material: betonblok C
Pset_ColumnCommon - Slope: 90 deg; IsExternal: no; LoadBearing: yes; Reference: betonblok C 450 x 700
BaseQuantities - Length: 4250 mm; Width: 450 mm; Depth: 700 mm; CrossSectionArea: 0.315 m2
Name | OuterSurfaceArea (m2) | TotalSurfaceArea (m2) = GrossSurfaceArea (m2) | GrossVolume (m3) = NetVolume (m3)
4 x 28_Kolom_betonblok | 9.29227 | 9.64227 | 1.17328
4 x 28_Kolom_betonblok | 9.303 | 9.653 | 1.17355

# IfcColumn: betonblok C 500 x 750 (14)
In: -1 Fundering
Type - PredefinedType: COLUMN
Material: betonblok C
Pset_ColumnCommon - Slope: 90 deg; IsExternal: no; LoadBearing: yes; Reference: betonblok C 500 x 750
BaseQuantities - Width: 500 mm; Depth: 750 mm; CrossSectionArea: 0.375 m2
Name | Length (mm) | OuterSurfaceArea (m2) | TotalSurfaceArea (m2) = GrossSurfaceArea (m2) | GrossVolume (m3) = NetVolume (m3)
6 x 28_Kolom_betonblok | 3800 | 9.5 | 9.875 | 1.425
3 x 28_Kolom_betonblok | 3620 | 9.05 | 9.05 | 1.3575
28_Kolom_betonblok | 4150 | 10.375 | 11.125 | 1.55625
28_Kolom_betonblok | 4520 | 11.12 | 11.87 | 1.6275
28_Kolom_betonblok | 4720 | 11.0742 | 11.4492 | 1.74718
28_Kolom_betonblok | 4640 | 11.5672 | 11.9422 | 1.73429
28_Kolom_betonblok | 4720 | 10.9157 | 11.2907 | 1.72455

# IfcColumn: betonblok C D200 (4)
In: Kelder
Type - PredefinedType: COLUMN
Material: betonblok C
Pset_ColumnCommon - Slope: 90 deg; IsExternal: no; LoadBearing: yes; Reference: betonblok C D200
BaseQuantities - Length: 3029.98 mm; Width: 200 mm; Depth: 200 mm; CrossSectionArea: 0.0314159 m2; OuterSurfaceArea: 1.89836 m2; TotalSurfaceArea: 1.96048 m2; GrossSurfaceArea: 1.96048 m2; GrossVolume: 0.094106 m3; NetVolume: 0.094106 m3

# IfcCovering: ALG Vloer 200, 43_Vloer_ALG
In: 02 2e tussenverdieping
Type - PredefinedType: CEILING
Material: ALG - CONSTRUCTIEF VLOER
BaseQuantities - GrossArea: 1.4 m2; NetArea: 1.4 m2
Pset_CoveringCommon - Material: ALG Vloer

# IfcCovering: PA-01a 40 (93)
Type - PredefinedType: CEILING
Material: systeemplafond 600*600 kleur wit
Pset_CoveringCommon - Material: PA-01a
Name | In | GrossArea (m2) | NetArea (m2)
45_Vloer_PA-01a | 00 Begane grond | 1.476 | 1.476
45_Vloer_PA-01a | 00 Begane grond | 2.66964 | 2.66964
45_Vloer_PA-01a | 00 Begane grond | 25.9327 | 25.9327
45_Vloer_PA-01a | 00 Begane grond | 8.37202 | 8.37202
45_Vloer_PA-01a | 00 Begane grond | 20.3904 | 20.1497
45_Vloer_PA-01a | 00 Begane grond | 9.0265 | 9.0265
45_Vloer_PA-01a | 00 Begane grond | 20.7993 | 20.7993
45_Vloer_PA-01a | 00 Begane grond | 6.78471 | 6.78471
45_Vloer_PA-01a | 00 Begane grond | 7.55435 | 7.55435
45_Vloer_PA-01a | 00 Begane grond | 20.3751 | 20.3751
45_Vloer_PA-01a | 00 Begane grond | 26.3627 | 26.3627
45_Vloer_PA-01a | 00 Begane grond | 0.00460593 | 0.00460593
45_Vloer_PA-01a | 00 Begane grond | 175.009 | 168.847
45_Vloer_PA-01a | 00 Begane grond | 37.9491 | 37.9491
45_Vloer_PA-01a | 00 Begane grond | 5.90256e-07 | 5.90256e-07
45_Vloer_PA-01a | 00 Begane grond | 1.50647 | 1.50647
45_Vloer_PA-01a | 00 Begane grond | 4.55185 | 4.54611
45_Vloer_PA-01a | 00 Begane grond | 26.6866 | 26.6555
45_Vloer_PA-01a | 00 Begane grond | 16.741 | 16.6852
45_Vloer_PA-01a | 00 Begane grond | 28.5577 | 28.5266
2 x 45_Vloer_PA-01a | 00 Begane grond | 28.503 | 28.503
45_Vloer_PA-01a | 00 Begane grond | 16.0876 | 16.0876
45_Vloer_PA-01a | 00 Begane grond | 7.8295 | 7.8295
45_Vloer_PA-01a | 01 1e tussenverdieping | 24.6603 | 24.6603
45_Vloer_PA-01a | 01 1e tussenverdieping | 23.6458 | 23.2725
45_Vloer_PA-01a | 01 1e tussenverdieping | 6.55713 | 6.55713
45_Vloer_PA-01a | 01 1e verdieping | 13.3153 | 13.3153
45_Vloer_PA-01a | 01 1e verdieping | 30.1286 | 30.1286
45_Vloer_PA-01a | 01 1e verdieping | 86.272 | 86.272
45_Vloer_PA-01a | 01 1e verdieping | 65.137 | 64.4677
45_Vloer_PA-01a | 01 1e verdieping | 17.9042 | 17.5689
45_Vloer_PA-01a | 01 1e verdieping | 8.08458 | 7.92363
45_Vloer_PA-01a | 01 1e verdieping | 38.7011 | 38.3861
45_Vloer_PA-01a | 01 1e verdieping | 60.9374 | 60.6224
45_Vloer_PA-01a | 01 1e verdieping | 116.006 | 116.006
45_Vloer_PA-01a | 01 1e verdieping | 7.12252 | 6.87109
45_Vloer_PA-01a | 01 1e verdieping | 15.412 | 15.3765
45_Vloer_PA-01a | 01 1e verdieping | 13.6592 | 13.6592
45_Vloer_PA-01a | 01 1e verdieping | 7.52503 | 7.46463
2 x 45_Vloer_PA-01a | 01 1e verdieping | 13.6593 | 13.6593
5 x 45_Vloer_PA-01a | 01 1e verdieping | 28.4893 | 28.4893
4 x 45_Vloer_PA-01a | 01 1e verdieping | 28.5032 | 28.5032
45_Vloer_PA-01a | 01 1e verdieping | 28.4614 | 28.4614
2 x 45_Vloer_PA-01a | 01 1e verdieping | 13.6659 | 13.6659
45_Vloer_PA-01a | 01 1e verdieping | 20.7368 | 20.7189
45_Vloer_PA-01a | 01 1e verdieping | 27.3319 | 27.3319
45_Vloer_PA-01a | 01 1e verdieping | 6.06627 | 6.05757
45_Vloer_PA-01a | 01 1e verdieping | 3.46938 | 3.46938
45_Vloer_PA-01a | 01 1e verdieping | 1.29 | 1.29
45_Vloer_PA-01a | 01 1e verdieping | 1.335 | 1.335
45_Vloer_PA-01a | 01 1e verdieping | 16.0776 | 15.9516
45_Vloer_PA-01a | 02 2e tussenverdieping | 1.26258 | 1.26258
45_Vloer_PA-01a | 02 2e tussenverdieping | 1.63819 | 1.63819
45_Vloer_PA-01a | 02 2e tussenverdieping | 8.25903 | 8.25903
45_Vloer_PA-01a | 02 2e verdieping | 19.39 | 18.9329
45_Vloer_PA-01a | 02 2e verdieping | 13.6355 | 13.6355
45_Vloer_PA-01a | 02 2e verdieping | 30.1118 | 30.1118
45_Vloer_PA-01a | 02 2e verdieping | 28.4409 | 28.4409
45_Vloer_PA-01a | 02 2e verdieping | 13.7077 | 13.6474
4 x 45_Vloer_PA-01a | 02 2e verdieping | 28.5904 | 28.4645
2 x 45_Vloer_PA-01a | 02 2e verdieping | 28.6429 | 28.5485
45_Vloer_PA-01a | 02 2e verdieping | 13.7092 | 13.6488
45_Vloer_PA-01a | 02 2e verdieping | 13.6628 | 13.6628
45_Vloer_PA-01a | 02 2e verdieping | 28.5028 | 28.5028
45_Vloer_PA-01a | 02 2e verdieping | 18.8478 | 18.8478
2 x 45_Vloer_PA-01a | 02 2e verdieping | 28.4961 | 28.4961
45_Vloer_PA-01a | 02 2e verdieping | 13.6529 | 13.6529
45_Vloer_PA-01a | 02 2e verdieping | 13.7071 | 13.6467
45_Vloer_PA-01a | 02 2e verdieping | 13.7077 | 13.6473
45_Vloer_PA-01a | 02 2e verdieping | 27.3253 | 27.3253
45_Vloer_PA-01a | 02 2e verdieping | 19.0838 | 18.6502
45_Vloer_PA-01a | 02 2e verdieping | 3.4722 | 3.4722
45_Vloer_PA-01a | 02 2e verdieping | 0.15375 | 0.024375
45_Vloer_PA-01a | 02 2e verdieping | 0.126772 | 0.020098
45_Vloer_PA-01a | 02 2e verdieping | 0.00442801 | 0.000702
45_Vloer_PA-01a | 03 3e tussenverdieping | 44.2096 | 44.2096
45_Vloer_PA-01a | 03 3e tussenverdieping | 17.3104 | 17.3104
45_Vloer_PA-01a | 03 3e tussenverdieping | 12.8292 | 12.8292

# IfcCovering: PA-01b 40 (8)
Type - PredefinedType: CEILING
Material: systeemplafond 600*600 vochtbestendig
Pset_CoveringCommon - Material: PA-01b
Name | In | GrossArea (m2) | NetArea (m2)
45_Vloer_PA-01b | 00 Begane grond | 8.74395 | 8.74395
45_Vloer_PA-01b | 00 Begane grond | 14.8236 | 14.8214
45_Vloer_PA-01b | 00 Begane grond | 6.19077 | 6.18298
45_Vloer_PA-01b | 00 Begane grond | 6.14791 | 6.14791
45_Vloer_PA-01b | 00 Begane grond | 14.4018 | 14.4018
45_Vloer_PA-01b | 02 2e tussenverdieping | 19.9601 | 19.9452
45_Vloer_PA-01b | 02 2e tussenverdieping | 9.03905 | 9.03905
45_Vloer_PA-01b | 02 2e tussenverdieping | 12.2977 | 12.0839

# IfcCovering: PA-01c 40 (12)
Type - PredefinedType: CEILING
Material: systeemplafond 600*600
Pset_CoveringCommon - Material: PA-01c
Name | In | GrossArea (m2) | NetArea (m2)
45_Vloer_PA-01c | 00 Begane grond | 142.666 | 142.437
45_Vloer_PA-01c | 00 Begane grond | 10.1287 | 10.1287
45_Vloer_PA-01c | 00 Begane grond | 14.3771 | 14.3771
45_Vloer_PA-01c | 00 Begane grond | 27.1343 | 27.1343
45_Vloer_PA-01c | 01 1e tussenverdieping | 20.4367 | 20.4367
45_Vloer_PA-01c | 01 1e tussenverdieping | 12.385 | 12.385
45_Vloer_PA-01c | 01 1e verdieping | 192.853 | 192.661
45_Vloer_PA-01c | 01 1e verdieping | 76.0501 | 73.6727
45_Vloer_PA-01c | 02 2e tussenverdieping | 20.4577 | 20.2581
45_Vloer_PA-01c | 02 2e verdieping | 175.701 | 175.508
45_Vloer_PA-01c | 02 2e verdieping | 27.78 | 26.9
45_Vloer_PA-01c | 03 3e tussenverdieping | 33.4828 | 33.4828

# IfcCovering: PA-01d 40 (3)
In: 00 Begane grond
Type - PredefinedType: CEILING
Material: systeemplafond 600*600 kleur ntb.
Pset_CoveringCommon - Material: PA-01d
Name | GrossArea (m2) | NetArea (m2)
45_Vloer_PA-01d | 10.125 | 10.125
45_Vloer_PA-01d | 20.5386 | 20.4112
45_Vloer_PA-01d | 6.88491 | 6.88491

# IfcCovering: PA-03 25 (8)
In: 00 Begane grond
Type - PredefinedType: CEILING
Material: Gipsplafond Rigitone
Pset_CoveringCommon - Material: PA-03
Name | GrossArea (m2) = NetArea (m2)
5 x 45_Vloer_PA-03 | 28.6526
45_Vloer_PA-03 | 28.3727
45_Vloer_PA-03 | 28.1391
45_Vloer_PA-03 | 118.057

# IfcCovering: PA-04 40 (12)
Type - PredefinedType: CEILING
Material: geïntegreerd balvast lamellenplafond
Pset_CoveringCommon - Material: PA-04
Name | In | GrossArea (m2) | NetArea (m2)
45_Vloer_PA-04 | 00 Begane grond | 21.4239 | 21.4239
45_Vloer_PA-04 | 01 1e tussenverdieping | 41.298 | 41.1972
2 x 45_Vloer_PA-04 | 01 1e tussenverdieping | 41.8822 | 41.6815
45_Vloer_PA-04 | 01 1e tussenverdieping | 41.4232 | 41.3221
45_Vloer_PA-04 | 01 1e tussenverdieping | 41.8822 | 41.78
45_Vloer_PA-04 | 02 2e tussenverdieping | 21.3628 | 21.3628
2 x 45_Vloer_PA-04 | 03 3e tussenverdieping | 41.3721 | 41.3721
45_Vloer_PA-04 | 03 3e tussenverdieping | 41.7727 | 41.7727
45_Vloer_PA-04 | 03 3e tussenverdieping | 41.7727 | 41.6631
45_Vloer_PA-04 | 03 3e tussenverdieping | 41.6478 | 41.5382

# IfcCovering: PA-05 1, 45_Vloer_PA-05
In: 00 Begane grond
Type - PredefinedType: CEILING
Material: schilderwerk
BaseQuantities - GrossArea: 6.405 m2; NetArea: 6.405 m2
Pset_CoveringCommon - Material: PA-05

# IfcCovering: PA-06 25, 45_Vloer_PA-06
In: 02 2e verdieping
Type - PredefinedType: CEILING
Material: akoestisch spuitwerk
Pset_CoveringCommon - Material: PA-06
BaseQuantities - GrossArea: 3.96881 m2; NetArea: 3.96881 m2

# IfcCovering: PA-08 40, 45_Vloer_PA-08
In: 00 Begane grond
Type - PredefinedType: CEILING
Material: aftimmering/koven multiplex
BaseQuantities - GrossArea: 1.5841 m2; NetArea: 1.5841 m2
Pset_CoveringCommon - Material: PA-08

# IfcCovering: PA-09 40 (2)
In: 00 Begane grond
Type - PredefinedType: CEILING
Material: verlaagd gipsvezelplaat plafond brandwerend
Pset_CoveringCommon - Material: PA-09
Name | GrossArea (m2) | NetArea (m2)
45_Vloer_PA-09 | 11.3208 | 11.2643
45_Vloer_PA-09 | 9.72347 | 9.61357

# IfcCovering: PA-10 400, 45_Vloer_PA-10
In: 00 Begane grond
Type - PredefinedType: CEILING
Material: gipsplafond met isolatie
BaseQuantities - GrossArea: 20.5386 m2; NetArea: 20.4112 m2
Pset_CoveringCommon - Material: PA-10

# IfcCovering: VA-01a 3 (26)
Type - PredefinedType: CEILING
Material: Vinyl type 01a
Pset_CoveringCommon - Material: VA-01a
Name | In | GrossArea (m2) = NetArea (m2)
43_Vloer_VA-01a | 00 Begane grond | 26.2187
43_Vloer_VA-01a | 00 Begane grond | 22.5482
43_Vloer_VA-01a | 00 Begane grond | 8.35272
43_Vloer_VA-01a | 01 1e tussenverdieping | 18.374
43_Vloer_VA-01a | 01 1e verdieping | 45.7561
43_Vloer_VA-01a | 01 1e verdieping | 45.7621
43_Vloer_VA-01a | 01 1e verdieping | 45.9152
43_Vloer_VA-01a | 01 1e verdieping | 45.7706
43_Vloer_VA-01a | 01 1e verdieping | 83.6352
43_Vloer_VA-01a | 01 1e verdieping | 46.3941
43_Vloer_VA-01a | 01 1e verdieping | 46.3568
43_Vloer_VA-01a | 01 1e verdieping | 46.1614
43_Vloer_VA-01a | 01 1e verdieping | 46.2614
43_Vloer_VA-01a | 02 2e tussenverdieping | 22.8132
43_Vloer_VA-01a | 02 2e verdieping | 45.5273
43_Vloer_VA-01a | 02 2e verdieping | 45.6668
43_Vloer_VA-01a | 02 2e verdieping | 45.7501
43_Vloer_VA-01a | 02 2e verdieping | 45.7588
43_Vloer_VA-01a | 02 2e verdieping | 52.3791
43_Vloer_VA-01a | 02 2e verdieping | 45.7504
43_Vloer_VA-01a | 02 2e verdieping | 45.6771
43_Vloer_VA-01a | 02 2e verdieping | 45.7038
43_Vloer_VA-01a | 02 2e verdieping | 46.4116
43_Vloer_VA-01a | 02 2e verdieping | 45.7721
43_Vloer_VA-01a | 03 3e tussenverdieping | 46.7527
43_Vloer_VA-01a | 03 3e tussenverdieping | 24.1877

# IfcCovering: VA-01b 3 (12)
Type - PredefinedType: CEILING
Material: Vinyl type 01b
Pset_CoveringCommon - Material: VA-01b
Name | In | GrossArea (m2) | NetArea (m2)
43_Vloer_VA-01b | 00 Begane grond | 37.1854 | 37.1854
43_Vloer_VA-01b | 00 Begane grond | 9.59199 | 9.59199
43_Vloer_VA-01b | 00 Begane grond | 28.5339 | 28.0539
43_Vloer_VA-01b | 00 Begane grond | 232.363 | 210.722
43_Vloer_VA-01b | 00 Begane grond | 5.61701 | 5.61701
43_Vloer_VA-01b | 00 Begane grond | 150.938 | 150.938
43_Vloer_VA-01b | 00 Begane grond | 171.046 | 171.046
43_Vloer_VA-01b | 00 Begane grond | 26.3681 | 26.3681
43_Vloer_VA-01b | 01 1e tussenverdieping | 45.4497 | 45.4497
43_Vloer_VA-01b | 01 1e verdieping | 183.146 | 183.146
43_Vloer_VA-01b | 01 1e verdieping | 79.0351 | 79.0343
43_Vloer_VA-01b | 02 2e verdieping | 177.934 | 177.934

# IfcCovering: VA-01d 3 (2)
In: 01 1e verdieping
Type - PredefinedType: CEILING
Material: Vinyl type 01d
Pset_CoveringCommon - Material: VA-01d
Name | GrossArea (m2) = NetArea (m2)
43_Vloer_VA-01d | 89.0747
43_Vloer_VA-01d | 7.56059

# IfcCovering: VA-01e 3 (3)
Type - PredefinedType: CEILING
Material: Vinyl type 01e (1)
Pset_CoveringCommon - Material: VA-01e
Name | In | GrossArea (m2) | NetArea (m2)
43_Vloer_VA-01e | 00 Begane grond | 91.6484 | 91.6484
43_Vloer_VA-01e | 00 Begane grond | 9.3831 | 9.3831
43_Vloer_VA-01e | 01 1e verdieping | 130.548 | 130.546

# IfcCovering: VA-01f 3 (19)
In: 00 Begane grond
Type - PredefinedType: CEILING
Material: Vinyl type 01f
Pset_CoveringCommon - Material: VA-01f
Name | GrossArea (m2) = NetArea (m2)
6 x 43_Vloer_VA-01f | 1.2075
6 x 43_Vloer_VA-01f | 2.51125
7 x 43_Vloer_VA-01f | 2.0075

# IfcCovering: VA-02a 3 (15)
Type - PredefinedType: CEILING
Material: Gietvloer type 02a
Pset_CoveringCommon - Material: VA-02a
Name | In | GrossArea (m2) | NetArea (m2)
43_Vloer_VA-02a | 00 Begane grond | 7.03127 | 7.03127
43_Vloer_VA-02a | 00 Begane grond | 15.2927 | 15.2905
43_Vloer_VA-02a | 00 Begane grond | 12.8459 | 12.8459
43_Vloer_VA-02a | 00 Begane grond | 23.5635 | 23.5635
43_Vloer_VA-02a | 00 Begane grond | 1.81027 | 1.81027
43_Vloer_VA-02a | 00 Begane grond | 12.8456 | 12.8456
43_Vloer_VA-02a | 00 Begane grond | 3.15972 | 3.15972
43_Vloer_VA-02a | 01 1e verdieping | 15.7845 | 15.7845
43_Vloer_VA-02a | 01 1e verdieping | 19.1332 | 19.1332
43_Vloer_VA-02a | 01 1e verdieping | 2.87611 | 2.87611
43_Vloer_VA-02a | 02 2e tussenverdieping | 14.916 | 14.916
43_Vloer_VA-02a | 02 2e tussenverdieping | 20.828 | 20.828
43_Vloer_VA-02a | 02 2e tussenverdieping | 1.74642 | 1.74642
43_Vloer_VA-02a | 02 2e tussenverdieping | 1.42339 | 1.42339
43_Vloer_VA-02a | 02 2e verdieping | 35.052 | 35.052

# IfcCovering: VA-02b 3 (5)
Type - PredefinedType: CEILING
Material: Gietvloer type 02b
Pset_CoveringCommon - Material: VA-02b
Name | In | GrossArea (m2) = NetArea (m2)
43_Vloer_VA-02b | 00 Begane grond | 6.67951
43_Vloer_VA-02b | 00 Begane grond | 6.80991
43_Vloer_VA-02b | 02 2e tussenverdieping | 5.36124
43_Vloer_VA-02b | 02 2e tussenverdieping | 5.37008
43_Vloer_VA-02b | 02 2e tussenverdieping | 4.39579

# IfcCovering: VA-03 3 (2)
Type - PredefinedType: CEILING
Material: sportvloer
Pset_CoveringCommon - Material: VA-03
Name | In | GrossArea (m2) = NetArea (m2)
43_Vloer_VA-03 | 00 Begane grond | 247.922
43_Vloer_VA-03 | 02 2e tussenverdieping | 237.002

# IfcCovering: VA-04 3 (2)
In: 00 Begane grond
Type - PredefinedType: CEILING
Material: schoonloopmat
Pset_CoveringCommon - Material: VA-04
Name | GrossArea (m2) = NetArea (m2)
43_Vloer_VA-04 | 22.5514
43_Vloer_VA-04 | 7.02632

# IfcCovering: VA-05 3 (23)
Type - PredefinedType: CEILING
Material: tapijttegel
Pset_CoveringCommon - Material: VA-05
Name | In | GrossArea (m2) | NetArea (m2)
43_Vloer_VA-05 | 00 Begane grond | 62.1351 | 62.1351
43_Vloer_VA-05 | 00 Begane grond | 22.1312 | 22.1312
2 x 43_Vloer_VA-05 | 00 Begane grond | 12.8201 | 12.8201
43_Vloer_VA-05 | 00 Begane grond | 19.4823 | 19.4823
43_Vloer_VA-05 | 00 Begane grond | 33.3242 | 32.5492
43_Vloer_VA-05 | 00 Begane grond | 35.3904 | 35.0154
43_Vloer_VA-05 | 00 Begane grond | 35.5411 | 35.5411
43_Vloer_VA-05 | 00 Begane grond | 20.9638 | 20.9638
43_Vloer_VA-05 | 00 Begane grond | 10.125 | 10.125
43_Vloer_VA-05 | 00 Begane grond | 3.56147 | 3.56147
43_Vloer_VA-05 | 00 Begane grond | 3.56156 | 3.56156
43_Vloer_VA-05 | 00 Begane grond | 21.3291 | 21.3291
43_Vloer_VA-05 | 01 1e tussenverdieping | 13.2315 | 13.2315
43_Vloer_VA-05 | 01 1e tussenverdieping | 34.7472 | 34.7472
43_Vloer_VA-05 | 01 1e verdieping | 116.538 | 116.223
43_Vloer_VA-05 | 01 1e verdieping | 43.7071 | 43.7071
43_Vloer_VA-05 | 01 1e verdieping | 15.3228 | 15.3228
43_Vloer_VA-05 | 01 1e verdieping | 48.1346 | 47.8176
43_Vloer_VA-05 | 01 1e verdieping | 6.79202 | 6.79202
43_Vloer_VA-05 | 02 2e verdieping | 41.3295 | 41.3295
43_Vloer_VA-05 | 03 3e tussenverdieping | 18.7071 | 18.7071
43_Vloer_VA-05 | 03 3e tussenverdieping | 13.7303 | 13.7303

# IfcCovering: VA-06 3 (5)
Type - PredefinedType: CEILING
Material: Behoud natuursteen tegels
Pset_CoveringCommon - Material: VA-06
Name | In | GrossArea (m2) | NetArea (m2)
43_Vloer_VA-06 | 00 Begane grond | 21.8999 | 21.8999
43_Vloer_VA-06 | 01 1e verdieping | 32.7483 | 32.7474
43_Vloer_VA-06 | 01 1e verdieping | 10.4017 | 10.4017
43_Vloer_VA-06 | 02 2e verdieping | 31.9462 | 31.9408
43_Vloer_VA-06 | 02 2e verdieping | 11.3056 | 11.3056

# IfcCovering: VA-09 3, 43_Vloer_VA-09
In: 00 Begane grond
Type - PredefinedType: CEILING
Material: Gietvloer HACCP type 09
BaseQuantities - GrossArea: 29.5577 m2; NetArea: 29.4952 m2
Pset_CoveringCommon - Material: VA-09

# IfcCovering: aftimmering/koven multiplex 10 (3)
In: 01 1e verdieping
Type - PredefinedType: CEILING
Material: aftimmering/koven multiplex
Pset_CoveringCommon - Material: aftimmering/koven multiplex
Name | GrossArea (m2) = NetArea (m2)
2 x 45_Vloer_aftimmering/koven | 1.4664
45_Vloer_aftimmering/koven | 2.36384

# IfcCovering: aftimmering/koven multiplex 1050, 45_Vloer_aftimmering/koven
In: 02 2e verdieping
Type - PredefinedType: CEILING
Material: aftimmering/koven multiplex
Pset_CoveringCommon - Material: aftimmering/koven multiplex
BaseQuantities - GrossArea: 0 m2; NetArea: 0 m2

# IfcCovering: aftimmering/koven multiplex 1060, 45_Vloer_aftimmering/koven
In: 00 Begane grond
Type - PredefinedType: CEILING
Material: aftimmering/koven multiplex
Pset_CoveringCommon - Material: aftimmering/koven multiplex
BaseQuantities - GrossArea: 0.5475 m2; NetArea: 0.5475 m2

# IfcCovering: aftimmering/koven multiplex 1100 (5)
Type - PredefinedType: CEILING
Material: aftimmering/koven multiplex
Pset_CoveringCommon - Material: aftimmering/koven multiplex
Name | In | GrossArea (m2) = NetArea (m2)
3 x 45_Vloer_aftimmering/koven | 00 Begane grond | 0.1825
45_Vloer_aftimmering/koven | 01 1e verdieping | 0.500921
45_Vloer_aftimmering/koven | 01 1e verdieping | 0.0446274

# IfcCovering: aftimmering/koven multiplex 1170, 45_Vloer_aftimmering/koven
In: 01 1e verdieping
Type - PredefinedType: CEILING
Material: aftimmering/koven multiplex
Pset_CoveringCommon - Material: aftimmering/koven multiplex
BaseQuantities - GrossArea: 1.92 m2; NetArea: 0.52 m2

# IfcCovering: aftimmering/koven multiplex 20 (2)
Type - PredefinedType: CEILING
Material: aftimmering/koven multiplex
Pset_CoveringCommon - Material: aftimmering/koven multiplex
Name | In | GrossArea (m2) = NetArea (m2)
45_Vloer_aftimmering/koven | 02 2e tussenverdieping | 0.7299
45_Vloer_aftimmering/koven | 02 2e verdieping | 1.92797

# IfcCovering: aftimmering/koven multiplex 280, 45_Vloer_aftimmering/koven
In: 02 2e tussenverdieping
Type - PredefinedType: CEILING
Material: aftimmering/koven multiplex
Pset_CoveringCommon - Material: aftimmering/koven multiplex
BaseQuantities - GrossArea: 0.0811 m2; NetArea: 0.0811 m2

# IfcCovering: aftimmering/koven multiplex 340, 45_Vloer_aftimmering/koven
In: 02 2e verdieping
Type - PredefinedType: CEILING
Material: aftimmering/koven multiplex
Pset_CoveringCommon - Material: aftimmering/koven multiplex
BaseQuantities - GrossArea: 0.453094 m2; NetArea: 0.453094 m2

# IfcCovering: aftimmering/koven multiplex 40, 45_Vloer_aftimmering/koven
In: 01 1e tussenverdieping
Type - PredefinedType: CEILING
Material: aftimmering/koven multiplex
Pset_CoveringCommon - Material: aftimmering/koven multiplex
BaseQuantities - GrossArea: 8.64744 m2; NetArea: 8.64744 m2

# IfcCovering: aftimmering/koven multiplex 537, 45_Vloer_aftimmering/koven
In: 01 1e tussenverdieping
Type - PredefinedType: CEILING
Material: aftimmering/koven multiplex
Pset_CoveringCommon - Material: aftimmering/koven multiplex
BaseQuantities - GrossArea: 0.200811 m2; NetArea: 0.200811 m2

# IfcCovering: aftimmering/koven multiplex 543, 45_Vloer_aftimmering/koven
In: 01 1e verdieping
Type - PredefinedType: CEILING
Material: aftimmering/koven multiplex
Pset_CoveringCommon - Material: aftimmering/koven multiplex
BaseQuantities - GrossArea: 0.740079 m2; NetArea: 0.740079 m2

# IfcCovering: aftimmering/koven multiplex 545, 45_Vloer_aftimmering/koven
In: 00 Begane grond
Type - PredefinedType: CEILING
Material: aftimmering/koven multiplex
BaseQuantities - GrossArea: 1.5841 m2; NetArea: 1.5841 m2
Pset_CoveringCommon - Material: aftimmering/koven multiplex

# IfcCovering: aftimmering/koven multiplex 565, 45_Vloer_aftimmering/koven
In: 00 Begane grond
Type - PredefinedType: CEILING
Material: aftimmering/koven multiplex
Pset_CoveringCommon - Material: aftimmering/koven multiplex
BaseQuantities - GrossArea: 1.58979 m2; NetArea: 1.58979 m2

# IfcCovering: aftimmering/koven multiplex 584, 45_Vloer_aftimmering/koven
In: 02 2e verdieping
Type - PredefinedType: CEILING
Material: aftimmering/koven multiplex
Pset_CoveringCommon - Material: aftimmering/koven multiplex
BaseQuantities - GrossArea: 0.5475 m2; NetArea: 0.5475 m2

# IfcCovering: aftimmering/koven multiplex 600, 45_Vloer_aftimmering/koven
In: 00 Begane grond
Type - PredefinedType: CEILING
Material: aftimmering/koven multiplex
BaseQuantities - GrossArea: 0.446446 m2; NetArea: 0.446446 m2
Pset_CoveringCommon - Material: aftimmering/koven multiplex

# IfcCovering: aftimmering/koven multiplex 625, 45_Vloer_aftimmering/koven
In: 00 Begane grond
Type - PredefinedType: CEILING
Material: aftimmering/koven multiplex
BaseQuantities - GrossArea: 5.90918 m2; NetArea: 5.90918 m2
Pset_CoveringCommon - Material: aftimmering/koven multiplex

# IfcCovering: aftimmering/koven multiplex 734, 45_Vloer_aftimmering/koven
In: 02 2e verdieping
Type - PredefinedType: CEILING
Material: aftimmering/koven multiplex
Pset_CoveringCommon - Material: aftimmering/koven multiplex
BaseQuantities - GrossArea: 0.88 m2; NetArea: 0.34 m2

# IfcCovering: koven gips 1060, 45_Vloer_koven
In: 01 1e verdieping
Type - PredefinedType: CEILING
Material: koven gips
Pset_CoveringCommon - Material: koven gips
BaseQuantities - GrossArea: 0.517643 m2; NetArea: 0.163876 m2

# IfcCovering: koven gips 1070, 45_Vloer_koven
In: 00 Begane grond
Type - PredefinedType: CEILING
Material: koven gips
Pset_CoveringCommon - Material: koven gips
BaseQuantities - GrossArea: 15.3714 m2; NetArea: 15.3714 m2

# IfcCovering: koven gips 1100, 45_Vloer_koven
In: 00 Begane grond
Type - PredefinedType: CEILING
Material: koven gips
Pset_CoveringCommon - Material: koven gips
BaseQuantities - GrossArea: 9.67746 m2; NetArea: 9.67746 m2

# IfcCovering: koven gips 40, 45_Vloer_koven
In: 00 Begane grond
Type - PredefinedType: CEILING
Material: koven gips
Pset_CoveringCommon - Material: koven gips
BaseQuantities - GrossArea: 2.18441 m2; NetArea: 2.18441 m2

# IfcCovering: koven gips 427, 45_Vloer_koven
In: 01 1e tussenverdieping
Type - PredefinedType: CEILING
Material: koven gips
Pset_CoveringCommon - Material: koven gips
BaseQuantities - GrossArea: 0.977736 m2; NetArea: 0.977736 m2

# IfcCovering: koven gips 488, 45_Vloer_koven
In: 02 2e tussenverdieping
Type - PredefinedType: CEILING
Material: koven gips
Pset_CoveringCommon - Material: koven gips
BaseQuantities - GrossArea: 0.163875 m2; NetArea: 0.163875 m2

# IfcCovering: koven gips 510 (2)
In: 00 Begane grond
Type - PredefinedType: CEILING
Material: koven gips
Pset_CoveringCommon - Material: koven gips
Name | GrossArea (m2) = NetArea (m2)
45_Vloer_koven | 0.878959
45_Vloer_koven | 0.346471

# IfcCovering: koven gips 565, 45_Vloer_koven
In: 00 Begane grond
Type - PredefinedType: CEILING
Material: koven gips
Pset_CoveringCommon - Material: koven gips
BaseQuantities - GrossArea: 1.2775 m2; NetArea: 1.2775 m2

# IfcCovering: koven gips 620, 45_Vloer_koven
In: 02 2e verdieping
Type - PredefinedType: CEILING
Material: koven gips
Pset_CoveringCommon - Material: koven gips
BaseQuantities - GrossArea: 0.138 m2; NetArea: 0.138 m2

# IfcCovering: koven gips 825, 45_Vloer_koven
In: 00 Begane grond
Type - PredefinedType: CEILING
Material: koven gips
BaseQuantities - GrossArea: 0.318959 m2; NetArea: 0.0290109 m2
Pset_CoveringCommon - Material: koven gips

# IfcCurtainWall: Curtain Wall Type (6)
Pset_CurtainWallCommon - Reference: Type vliesgevel; IsExternal: yes
Name | In | Material | Width (mm) | Length (mm) | Height (mm) | GrossSideArea (m2) = NetSideArea (m2)
21_BU-D-35_ | 00 Begane grond | glas (11), aluminium (29) | 139 | 3532.99 | 12025 | 42.4842
21_BU-D-31_ | 00 Begane grond | glas (54), aluminium (135) | 0 | 11577.5 | 11925 | 138.062
21_BU-D-01_ | 00 Begane grond | glas (85), aluminium (414) | 0 | 58746.9 | 3484.97 | 204.731
21_BU-D-32_ | 01 1e verdieping | glas (25), aluminium (60) | 0 | 7275.5 | 9665 | 70.3177
21_BU-D-33_ | 02 2e verdieping | glas (20), aluminium (52) | 0 | 9692.49 | 5360 | 51.9517
21_BU-D-35_ | 04 4e verdieping | glas (4), aluminium (14) | 0 | 9691.98 | 1110 | 10.7581

# IfcDistributionFlowElement: Regenpijp 27 (22)
Type - PredefinedType: AIRRELEASE
Name | In
2 x 52_Wasmachine_Lege | 00 Begane grond
52_Wasmachine_Lege | 01 1e tussenverdieping
2 x 52_Wasmachine_Lege | 01 1e verdieping
3 x 52_Wasmachine_Lege | 02 2e tussenverdieping
3 x 52_Wasmachine_Lege | 02 2e verdieping
2 x 52_Wasmachine_Lege | 03 3e tussenverdieping
9 x 52_Wasmachine_Lege | 04 4e verdieping

# IfcDoor: D1 27 (18)
Type - OperationType: SINGLE_SWING_LEFT; ParameterTakesPrecedence: no; Sizeable: no
OverallHeight: 2367 mm
BaseQuantities - Height: 2367 mm
Name | In | OverallWidth (mm) = Width (mm) | IsExternal | Frame / Draaiend deel = Stofdorpel = Vensterbank = Ventilatierooster = Rollaag / Latei = Afwerking dagkant buiten = Afwerking dagkant binnen = Zonwering - behuizing | Deurblad | Onderdorpel | Spouwlat | Zonwering - isolatie | Glas | Perimeter (mm) | Area (m2) | Volume (m3) = NetVolume (m3) | Depth (mm)
22_BI-A-06_305 | 00 Begane grond | 1034 | no | arcering (01) | arcering (02) | % | Naaldhout (01) | Loofhout | RAL 4007 | 6802 | 2.44748 | 0.126632 | 160
3 x 22_BI-A-01_305 | 00 Begane grond | 1034 | no | arcering (01) | arcering (02) | % | Naaldhout (01) | Loofhout | RAL 4007 | 6802 | 2.44748 | 0.126632 | 150
22_BI-A-05_305 | 00 Begane grond | 1034 | no | arcering (01) | arcering (02) | % | Naaldhout (01) | Loofhout | RAL 4007 | 6802 | 2.44748 | 0.126632 | 160
22_BI-A-03_305 | 00 Begane grond | 984 | no | arcering (01) | arcering (02) | % | Naaldhout (01) | Loofhout | RAL 4007 | 6702 | 2.32913 | 0.120851 | 150
22_BI-A-04_305 | 00 Begane grond | 900 | yes | n.v.t. | n.v.t. | n.v.t. | n.v.t. | n.v.t. | Glas - algemeen | 6534 | 2.1303 | 0.0890662 | 150
2 x 22_BI-A-01_305 | 00 Begane grond | 984 | no | arcering (01) | arcering (02) | % | Naaldhout (01) | Loofhout | RAL 4007 | 6702 | 2.32913 | 0.121605 | 150
2 x 22_BI-A-04_305 | 01 1e tussenverdieping | 1034 | yes | n.v.t. | n.v.t. | n.v.t. | n.v.t. | n.v.t. | Glas - algemeen | 6802 | 2.44748 | 0.125832 | 150
22_BI-A-04_305 | 01 1e verdieping | 1034 | yes | n.v.t. | n.v.t. | n.v.t. | n.v.t. | n.v.t. | Glas - algemeen | 6802 | 2.44748 | 0.125832 | 150
22_BI-A-03_305 | 01 1e verdieping | 984 | no | arcering (01) | arcering (02) | % | Naaldhout (01) | Loofhout | RAL 4007 | 6702 | 2.32913 | 0.120851 | 150
2 x 22_BI-A-06_305 | 02 2e tussenverdieping | 1034 | no | arcering (01) | arcering (02) | % | Naaldhout (01) | Loofhout | RAL 4007 | 6802 | 2.44748 | 0.126632 | 150
22_BI-A-05_305 | 02 2e tussenverdieping | 1034 | no | arcering (01) | arcering (02) | % | Naaldhout (01) | Loofhout | RAL 4007 | 6802 | 2.44748 | 0.126632 | 160
22_BI-A-04_305 | 02 2e tussenverdieping | 1034 | yes | n.v.t. | n.v.t. | n.v.t. | n.v.t. | n.v.t. | Glas - algemeen | 6802 | 2.44748 | 0.125832 | 150
22_BI-A-04_305 | 02 2e verdieping | 1034 | yes | n.v.t. | n.v.t. | n.v.t. | n.v.t. | n.v.t. | Glas - algemeen | 6802 | 2.44748 | 0.126632 | 150

# IfcDoor: D1 27 (18)
Type - OperationType: SINGLE_SWING_RIGHT; ParameterTakesPrecedence: no; Sizeable: no
Name | In | OverallHeight (mm) | OverallWidth (mm) | Frame / Draaiend deel = Stofdorpel = Vensterbank = Ventilatierooster = Rollaag / Latei = Afwerking dagkant buiten = Afwerking dagkant binnen = Zonwering - behuizing | Deurblad | Onderdorpel | Spouwlat | Zonwering - isolatie | Glas | IsExternal | Height (mm) | Width (mm) | Perimeter (mm) | Area (m2) | Volume (m3) = NetVolume (m3) | Depth (mm)
22_BI-A-01 sp_305 | 00 Begane grond | 2434 | 1034 | arcering (01) | arcering (02) | % | Naaldhout (01) | Loofhout | RAL 4007 | no | 2434 | 1034 | 6936 | 2.51676 | 0.130067 | 150
2 x 22_BI-A-01 sp_305 | 00 Begane grond | 2367 | 1034 | arcering (01) | arcering (02) | % | Naaldhout (01) | Loofhout | RAL 4007 | no | 2367 | 1034 | 6802 | 2.44748 | 0.126632 | 150
22_BI-A-02 sp_305 | 00 Begane grond | 2367 | 1034 | arcering (01) | arcering (02) | % | Naaldhout (01) | Loofhout | RAL 4007 | no | 2367 | 1034 | 6802 | 2.44748 | 0.0784854 | 150
22_BI-A-04 sp_305 | 00 Begane grond | 2367 | 1034 | n.v.t. | n.v.t. | n.v.t. | n.v.t. | n.v.t. | Glas - algemeen | yes | 2367 | 1034 | 6802 | 2.44748 | 0.125832 | 150
22_BI-A-07_305 | 00 Begane grond | 2370 | 1064 | n.v.t. | n.v.t. | n.v.t. | n.v.t. | n.v.t. | Glas - algemeen | yes | 2370 | 1064 | 6868 | 2.52168 | 0.127559 | 150
22_BI-A-01 sp_305 | 00 Begane grond | 2367 | 1034 | arcering (01) | arcering (02) | % | Naaldhout (01) | Loofhout | RAL 4007 | no | 2367 | 1034 | 6802 | 2.44748 | 0.125221 | 150
22_BI-A-03 sp_305 | 00 Begane grond | 2367 | 984 | arcering (01) | arcering (02) | % | Naaldhout (01) | Loofhout | RAL 4007 | no | 2367 | 984.005 | 6702.01 | 2.32913 | 0.120851 | 150
21_BU-D-06_305 | 00 Begane grond | 2345 | 990 | n.v.t. | n.v.t. | n.v.t. | n.v.t. | n.v.t. | Glas - algemeen | no | 2345 | 990 | 6670 | 2.32155 | 0.0514159 | 420
22__305 | 00 Begane grond | 2362.2 | 900 | arcering (01) | arcering (02) | % | Naaldhout (01) | Loofhout | RAL 4007 | no | 2362.2 | 900 | 6524.41 | 2.12598 | 0 | 150
2 x 22_BI-A-06 sp_305 | 01 1e verdieping | 2367 | 1034 | arcering (01) | arcering (02) | % | Naaldhout (01) | Loofhout | RAL 4007 | no | 2367 | 1034 | 6802 | 2.44748 | 0.126632 | 150
22_BI-A-04 sp_305 | 01 1e verdieping | 2367 | 1034 | n.v.t. | n.v.t. | n.v.t. | n.v.t. | n.v.t. | Glas - algemeen | yes | 2367 | 1034 | 6802 | 2.44748 | 0.125832 | 150
22_BI-A-04 sp_305 | 01 1e verdieping | 2367 | 984 | arcering (01) | arcering (02) | % | Naaldhout (01) | Loofhout | RAL 4007 | no | 2367 | 984 | 6702 | 2.32913 | 0.120851 | 150
22_BI-A-01 sp_305 | 02 2e tussenverdieping | 2367 | 1034 | arcering (01) | arcering (02) | % | Naaldhout (01) | Loofhout | RAL 4007 | no | 2367 | 1034 | 6802 | 2.44748 | 0.126632 | 150
22_BI-A-04 sp_305 | 02 2e verdieping | 2367 | 1034 | n.v.t. | n.v.t. | n.v.t. | n.v.t. | n.v.t. | Glas - algemeen | yes | 2367 | 1034 | 6802 | 2.44748 | 0.125832 | 150
22_BI-A-06 sp_305 | 03 3e tussenverdieping | 2367 | 1034 | arcering (01) | arcering (02) | % | Naaldhout (01) | Loofhout | RAL 4007 | no | 2367 | 1034 | 6802 | 2.44748 | 0.126632 | 160
47_BU-F-02_305 | 04 4e verdieping | 2367 | 1034 | n.v.t. | n.v.t. | n.v.t. | n.v.t. | n.v.t. | Glas - algemeen | no | 2246.96 | 1034 | 6561.92 | 2.60114 | 0.101674 | 18.0001

# IfcDoor: D1 27 (11)
Type - ParameterTakesPrecedence: no; Sizeable: no
Pset_DoorCommon - IsExternal: yes
Material - Frame / Draaiend deel: n.v.t.; Deurblad: n.v.t.; Onderdorpel: n.v.t.; Stofdorpel: n.v.t.; Vensterbank: n.v.t.; Ventilatierooster: n.v.t.; Spouwlat: n.v.t.; Rollaag / Latei: n.v.t.; Afwerking dagkant buiten: n.v.t.; Afwerking dagkant binnen: n.v.t.; Zonwering - behuizing: n.v.t.; Zonwering - isolatie: n.v.t.; Glas: Glas - algemeen
Name | In | OverallHeight (mm) | OverallWidth (mm) | Height (mm) | Width (mm) | Perimeter (mm) | Area (m2) | Volume (m3) = NetVolume (m3) | Depth (mm)
22_BI-H-02_305 | 00 Begane grond | 2434 | 1979.9 | 2434 | 1979.9 | 8827.8 | 4.81908 | 0.0674747 | 150
22__305 | 00 Begane grond | 2300 | 1600 | 2300 | 1600 | 7800 | 3.68 | 0.057 | 150
22_BI-H-01_305 | 00 Begane grond | 2517 | 6514 | 2517 | 6514 | 18062 | 16.3957 | 0.12777 | 150
22__305 | 00 Begane grond | 2300 | 1200 | 1062 | 1200 | 4524 | 1.2744 | 0.0522 | 214
22_BI-H-03_305 | 00 Begane grond | 2487.5 | 3295 | 0 | 0 | 0 | 0 | 0.0817668 | 150
22__305 | 01 1e verdieping | 2300 | 1600 | 2300 | 1600 | 7800 | 3.68 | 0.057 | 150
22__305 | 01 1e verdieping | 2300 | 1200 | 2155 | 1200 | 6710 | 2.586 | 0.0522 | 214
22_BI-H-11_305 | 01 1e verdieping | 2367 | 1034 | 2367 | 1034 | 6802 | 2.44748 | 0.0566217 | 150
22_BI-H-03_305 | 02 2e tussenverdieping | 2367 | 3188.21 | 2367 | 3188.21 | 11110.4 | 7.5465 | 0.0782715 | 160
22__305 | 02 2e verdieping | 2300 | 1600 | 2300 | 1600 | 7800 | 3.68 | 0.057 | 150
22__305 | 02 2e verdieping | 2300 | 1200 | 2300 | 1200 | 7000 | 2.76 | 0.0522 | 214

# IfcDoor: D1 bl 27 (2)
In: 01 1e verdieping
Type - OperationType: SINGLE_SWING_LEFT; ParameterTakesPrecedence: no; Sizeable: no
Pset_DoorCommon - IsExternal: no
Material - Glas: Glas - algemeen
Name | OverallHeight (mm) = Height (mm) | OverallWidth (mm) = Width (mm) | Perimeter (mm) | Area (m2) | Volume (m3) = NetVolume (m3) | Depth (mm) | Frame / Draaiend deel = Stofdorpel = Vensterbank = Ventilatierooster = Rollaag / Latei = Afwerking dagkant buiten = Afwerking dagkant binnen = Zonwering - behuizing | Deurblad | Onderdorpel | Spouwlat | Zonwering - isolatie
21_BU-A-12c_305 | 3454 | 1267.01 | 9442.02 | 4.37625 | 0.106908 | 420 | n.v.t. | n.v.t. | n.v.t. | n.v.t. | n.v.t.
22_BI-E-04_305 | 3000 | 984 | 7968 | 2.952 | 0.176405 | 150 | arcering (01) | arcering (02) | % | Naaldhout (01) | Loofhout

# IfcDoor: D1 bl 27 (2)
Type - OperationType: SINGLE_SWING_RIGHT; ParameterTakesPrecedence: no; Sizeable: no
OverallHeight: 3000 mm; OverallWidth: 984 mm
Material - Frame / Draaiend deel: arcering (01); Deurblad: arcering (02); Onderdorpel: %; Stofdorpel: arcering (01); Vensterbank: arcering (01); Ventilatierooster: arcering (01); Spouwlat: Naaldhout (01); Rollaag / Latei: arcering (01); Afwerking dagkant buiten: arcering (01); Afwerking dagkant binnen: arcering (01); Zonwering - behuizing: arcering (01); Zonwering - isolatie: Loofhout; Glas: Glas - algemeen
BaseQuantities - Height: 3000 mm; Width: 984 mm; Perimeter: 7968 mm; Area: 2.952 m2; Volume: 0.176405 m3; Depth: 150 mm; NetVolume: 0.176405 m3
Pset_DoorCommon - IsExternal: no
Name | In
22_BI-E-05_305 | 00 Begane grond
22_BI-E-04 sp_305 | 01 1e verdieping

# IfcDoor: D1 bl zl1-b 27 (8)
Type - OperationType: SINGLE_SWING_LEFT; ParameterTakesPrecedence: no; Sizeable: no
OverallHeight: 3000 mm
Material - Frame / Draaiend deel: arcering (01); Deurblad: arcering (02); Onderdorpel: %; Stofdorpel: arcering (01); Vensterbank: arcering (01); Ventilatierooster: arcering (01); Spouwlat: Naaldhout (01); Rollaag / Latei: arcering (01); Afwerking dagkant buiten: arcering (01); Afwerking dagkant binnen: arcering (01); Zonwering - behuizing: arcering (01); Zonwering - isolatie: Loofhout; Glas: Glas - algemeen
Pset_DoorCommon - IsExternal: no
BaseQuantities - Height: 3000 mm; Depth: 150 mm
Name | In | OverallWidth (mm) = Width (mm) | Perimeter (mm) | Area (m2) | Volume (m3) = NetVolume (m3)
22_BI-E-02b_305 | 00 Begane grond | 3650 | 13300 | 8.334 | 0.225096
22_BI-E-02_305 | 00 Begane grond | 3650 | 13300 | 8.334 | 0.252604
22_BI-E-02_305 | 01 1e verdieping | 1867 | 9734 | 5.601 | 0.176117
22_BI-E-02_305 | 01 1e verdieping | 1867 | 9734 | 5.601 | 0.176992
2 x 22_BI-E-02_305 | 02 2e verdieping | 1867 | 9734 | 5.601 | 0.175647
22_BI-E-02_305 | 02 2e verdieping | 1967 | 9934 | 5.901 | 0.177235
22_BI-E-02_305 | 02 2e verdieping | 3650 | 13300 | 7.5492 | 0.216937

# IfcDoor: D1 bl zl1-b 27 (4)
Type - OperationType: SINGLE_SWING_RIGHT; ParameterTakesPrecedence: no; Sizeable: no
OverallHeight: 3000 mm
Material - Frame / Draaiend deel: arcering (01); Deurblad: arcering (02); Onderdorpel: %; Stofdorpel: arcering (01); Vensterbank: arcering (01); Ventilatierooster: arcering (01); Spouwlat: Naaldhout (01); Rollaag / Latei: arcering (01); Afwerking dagkant buiten: arcering (01); Afwerking dagkant binnen: arcering (01); Zonwering - behuizing: arcering (01); Zonwering - isolatie: Loofhout; Glas: Glas - algemeen
Pset_DoorCommon - IsExternal: no
BaseQuantities - Height: 3000 mm; Depth: 150 mm
Name | In | OverallWidth (mm) = Width (mm) | Perimeter (mm) | Area (m2) | Volume (m3) = NetVolume (m3)
2 x 22_BI-E-02 sp_305 | 01 1e verdieping | 1867 | 9734 | 5.601 | 0.176992
22_BI-E-02 sp_305 | 02 2e verdieping | 1867 | 9734 | 5.601 | 0.175647
22_BI-E-02 sp_305 | 02 2e verdieping | 3650 | 13300 | 7.5492 | 0.216811

# IfcDoor: D1 bl zl2 27 (28)
Type - OperationType: USERDEFINED; ParameterTakesPrecedence: no; Sizeable: no
Material - Glas: Glas - algemeen
Pset_DoorCommon - IsExternal: no
Name | In | OverallHeight (mm) = Height (mm) | OverallWidth (mm) | Frame / Draaiend deel = Stofdorpel = Vensterbank = Ventilatierooster = Rollaag / Latei = Afwerking dagkant buiten = Afwerking dagkant binnen = Zonwering - behuizing | Deurblad | Onderdorpel | Spouwlat | Zonwering - isolatie | Width (mm) | Perimeter (mm) | Area (m2) | Volume (m3) = NetVolume (m3) | Depth (mm)
21_BU-F-01_305 | 00 Begane grond | 3472 | 3104 | n.v.t. | n.v.t. | n.v.t. | n.v.t. | n.v.t. | 3104 | 13152 | 10.7771 | 0.363136 | 420
21_BU-F-01_305 | 00 Begane grond | 3472 | 3104 | n.v.t. | n.v.t. | n.v.t. | n.v.t. | n.v.t. | 3104 | 13152 | 10.7771 | 0.416056 | 420
22_BI-F-08_305 | 00 Begane grond | 3000 | 3875 | arcering (01) | arcering (02) | % | Naaldhout (01) | Loofhout | 3875 | 13750 | 11.625 | 0.0988146 | 150
22_BI-F-02 sp_305 | 00 Begane grond | 3000 | 2541.67 | arcering (01) | arcering (02) | % | Naaldhout (01) | Loofhout | 2541.67 | 11083.3 | 7.625 | 0.0970546 | 150
22_BI-F-03_305 | 00 Begane grond | 3000 | 1604.17 | arcering (01) | arcering (02) | % | Naaldhout (01) | Loofhout | 1604.17 | 9208.33 | 4.8125 | 0.0958171 | 150
22_BI-F-02_305 | 00 Begane grond | 3000 | 2541.67 | arcering (01) | arcering (02) | % | Naaldhout (01) | Loofhout | 2541.67 | 11083.3 | 7.625 | 0.0970546 | 150
22_BI-F-07_305 | 00 Begane grond | 3000 | 2707.81 | arcering (01) | arcering (02) | % | Naaldhout (01) | Loofhout | 2707.81 | 11415.6 | 8.12344 | 0.0972739 | 150
22_BI-F-04_305 | 00 Begane grond | 3000 | 6541.67 | arcering (01) | arcering (02) | % | Naaldhout (01) | Loofhout | 6541.67 | 19083.3 | 19.625 | 0.102335 | 150
22_BI-F-05_305 | 00 Begane grond | 3000 | 3875 | arcering (01) | arcering (02) | % | Naaldhout (01) | Loofhout | 3875 | 13750 | 11.625 | 0.0988146 | 150
22_BI-F-01_305 | 00 Begane grond | 3000 | 3862.5 | arcering (01) | arcering (02) | % | Naaldhout (01) | Loofhout | 3862.5 | 13725 | 11.5875 | 0.0987981 | 150
22_BI-F-15_305 | 01 1e verdieping | 3000 | 5925.07 | arcering (01) | arcering (02) | % | Naaldhout (01) | Loofhout | 5925.07 | 17850.1 | 17.7752 | 0.101598 | 150
2 x 22_BI-E-03_305 | 01 1e verdieping | 3000 | 3650 | arcering (01) | arcering (02) | % | Naaldhout (01) | Loofhout | 3650 | 13300 | 8.65402 | 0.250042 | 150
22_BI-F-11_305 | 01 1e verdieping | 3000 | 3200 | arcering (01) | arcering (02) | % | Naaldhout (01) | Loofhout | 3200 | 12400 | 9.6 | 0.0979236 | 150
22_BI-F-19_305 | 01 1e verdieping | 3000 | 4264.04 | arcering (01) | arcering (02) | % | Naaldhout (01) | Loofhout | 4264.04 | 14528.1 | 12.7921 | 0.0992588 | 150
22_BI-F-13_305 | 01 1e verdieping | 3000 | 3850 | arcering (01) | arcering (02) | % | Naaldhout (01) | Loofhout | 3850 | 13700 | 11.55 | 0.0987816 | 150
22_BI-F-12_305 | 01 1e verdieping | 3000 | 4300.53 | arcering (01) | arcering (02) | % | Naaldhout (01) | Loofhout | 4300.53 | 14601.1 | 12.9016 | 0.0993763 | 150
2 x 22_BI-E-03 sp_305 | 01 1e verdieping | 3000 | 3650 | arcering (01) | arcering (02) | % | Naaldhout (01) | Loofhout | 3650 | 13300 | 8.65402 | 0.250042 | 150
22_BI-F-14_305 | 01 1e verdieping | 3000 | 3175.04 | arcering (01) | arcering (02) | % | Naaldhout (01) | Loofhout | 3175.04 | 12350.1 | 9.52513 | 0.097748 | 150
22_BI-F-18_305 | 01 1e verdieping | 3000 | 4151.56 | arcering (01) | arcering (02) | % | Naaldhout (01) | Loofhout | 4151.57 | 14303.1 | 12.4547 | 0.0993263 | 150
22_BI-F-16_305 | 01 1e verdieping | 3000 | 4151.56 | arcering (01) | arcering (02) | % | Naaldhout (01) | Loofhout | 4151.57 | 14303.1 | 12.4547 | 0.0991103 | 150
22_BI-F-22_305 | 02 2e verdieping | 3000 | 3990 | arcering (01) | arcering (02) | % | Naaldhout (01) | Loofhout | 3990 | 13980 | 11.97 | 0.0989664 | 150
22_BI-F-23_305 | 02 2e verdieping | 3000 | 3790 | arcering (01) | arcering (02) | % | Naaldhout (01) | Loofhout | 3790 | 13580 | 11.37 | 0.0987024 | 150
2 x 22_BI-E-03_305 | 02 2e verdieping | 3000 | 3650 | arcering (01) | arcering (02) | % | Naaldhout (01) | Loofhout | 3650 | 13300 | 8.65402 | 0.248757 | 150
22_BI-E-03 sp_305 | 02 2e verdieping | 3000 | 3650 | arcering (01) | arcering (02) | % | Naaldhout (01) | Loofhout | 3650 | 13300 | 8.65402 | 0.248696 | 150
22_BI-E-03 sp_305 | 02 2e verdieping | 3000 | 3650 | arcering (01) | arcering (02) | % | Naaldhout (01) | Loofhout | 3650 | 13300 | 8.65402 | 0.24863 | 150

# IfcDoor: D1 zl1-b 27 (7)
Type - OperationType: SINGLE_SWING_LEFT; ParameterTakesPrecedence: no; Sizeable: no
OverallHeight: 2367 mm
BaseQuantities - Height: 2367 mm; Depth: 150 mm
Material - Glas: Glas - algemeen
Pset_DoorCommon - IsExternal: no
Name | In | OverallWidth (mm) = Width (mm) | Perimeter (mm) | Area (m2) | Volume (m3) = NetVolume (m3) | Frame / Draaiend deel = Stofdorpel = Vensterbank = Ventilatierooster = Rollaag / Latei = Afwerking dagkant buiten = Afwerking dagkant binnen = Zonwering - behuizing | Deurblad | Onderdorpel | Spouwlat | Zonwering - isolatie
22_BI-C-01_305 | 00 Begane grond | 1750 | 8234 | 4.14225 | 0.154625 | n.v.t. | n.v.t. | n.v.t. | n.v.t. | n.v.t.
22_BI-E-16_305 | 01 1e tussenverdieping | 2675.28 | 10084.6 | 6.33238 | 0.185016 | arcering (01) | arcering (02) | % | Naaldhout (01) | Loofhout
22_BI-E-15_305 | 01 1e tussenverdieping | 2675.28 | 10084.6 | 6.33238 | 0.185815 | arcering (01) | arcering (02) | % | Naaldhout (01) | Loofhout
22_BI-C-01_305 | 01 1e verdieping | 1750 | 8234 | 4.14225 | 0.154625 | n.v.t. | n.v.t. | n.v.t. | n.v.t. | n.v.t.
22_BI-C-01_305 | 02 2e verdieping | 1750 | 8234 | 4.14225 | 0.153214 | n.v.t. | n.v.t. | n.v.t. | n.v.t. | n.v.t.
22_BI-E-18_305 | 03 3e tussenverdieping | 4530 | 13794 | 10.7225 | 0.24746 | arcering (01) | arcering (02) | % | Naaldhout (01) | Loofhout
22_BI-E-19_305 | 03 3e tussenverdieping | 2600 | 9934 | 6.1542 | 0.16681 | n.v.t. | n.v.t. | n.v.t. | n.v.t. | n.v.t.

# IfcDoor: D1 zl1-b 27 (8)
Type - OperationType: SINGLE_SWING_RIGHT; ParameterTakesPrecedence: no; Sizeable: no
OverallHeight: 2367 mm
Material - Glas: Glas - algemeen
Pset_DoorCommon - IsExternal: no
BaseQuantities - Height: 2367 mm; Depth: 150 mm
Name | In | OverallWidth (mm) = Width (mm) | Frame / Draaiend deel = Stofdorpel = Vensterbank = Ventilatierooster = Rollaag / Latei = Afwerking dagkant buiten = Afwerking dagkant binnen = Zonwering - behuizing | Deurblad | Onderdorpel | Spouwlat | Zonwering - isolatie | Perimeter (mm) | Area (m2) | Volume (m3) = NetVolume (m3)
22_BI-E-06_305 | 00 Begane grond | 3250 | arcering (01) | arcering (02) | % | Naaldhout (01) | Loofhout | 11234 | 7.69275 | 0.214396
22_BI-C-02 sp_305 | 00 Begane grond | 1500 | n.v.t. | n.v.t. | n.v.t. | n.v.t. | n.v.t. | 7734 | 3.5505 | 0.150007
22_BI-C-01 sp_305 | 00 Begane grond | 1750 | n.v.t. | n.v.t. | n.v.t. | n.v.t. | n.v.t. | 8234 | 4.14225 | 0.154625
22_BI-E-17_305 | 01 1e tussenverdieping | 4530 | arcering (01) | arcering (02) | % | Naaldhout (01) | Loofhout | 13794 | 10.7225 | 0.248259
22_BI-C-01 sp_305 | 01 1e verdieping | 1750 | n.v.t. | n.v.t. | n.v.t. | n.v.t. | n.v.t. | 8234 | 4.14225 | 0.154625
22_BI-C-03_305 | 01 1e verdieping | 1466.51 | n.v.t. | n.v.t. | n.v.t. | n.v.t. | n.v.t. | 7667.02 | 3.47123 | 0.10184
22_BI-C-01 sp_305 | 02 2e verdieping | 1750 | n.v.t. | n.v.t. | n.v.t. | n.v.t. | n.v.t. | 8234 | 4.14225 | 0.153214
22_BI-E-20_305 | 03 3e tussenverdieping | 1780 | n.v.t. | n.v.t. | n.v.t. | n.v.t. | n.v.t. | 8294 | 4.21326 | 0.154284

# IfcDoor: D1 zl2 27 (2)
In: 00 Begane grond
Type - OperationType: USERDEFINED; ParameterTakesPrecedence: no; Sizeable: no
OverallHeight: 2400 mm
Material - Frame / Draaiend deel: arcering (01); Deurblad: arcering (02); Onderdorpel: %; Stofdorpel: arcering (01); Vensterbank: arcering (01); Ventilatierooster: arcering (01); Spouwlat: Naaldhout (01); Rollaag / Latei: arcering (01); Afwerking dagkant buiten: arcering (01); Afwerking dagkant binnen: arcering (01); Zonwering - behuizing: arcering (01); Zonwering - isolatie: Loofhout; Glas: Glas - algemeen
Pset_DoorCommon - IsExternal: no
BaseQuantities - Height: 2400 mm; Depth: 150 mm
Name | OverallWidth (mm) = Width (mm) | Perimeter (mm) | Area (m2) | Volume (m3) = NetVolume (m3)
22_BI-F-27_305 | 1747.5 | 8295 | 4.194 | 0.0960698
22_BI-F-27 sp_305 | 1706.71 | 8213.41 | 4.09609 | 0.096016

# IfcDoor: D2 27 (3)
Type - OperationType: DOUBLE_DOOR_SINGLE_SWING; ParameterTakesPrecedence: no; Sizeable: no
OverallHeight: 2367 mm
Material - Frame / Draaiend deel: n.v.t.; Deurblad: n.v.t.; Onderdorpel: n.v.t.; Stofdorpel: n.v.t.; Vensterbank: n.v.t.; Ventilatierooster: n.v.t.; Spouwlat: n.v.t.; Rollaag / Latei: n.v.t.; Afwerking dagkant buiten: n.v.t.; Afwerking dagkant binnen: n.v.t.; Zonwering - behuizing: n.v.t.; Zonwering - isolatie: n.v.t.; Glas: Glas - algemeen
Pset_DoorCommon - IsExternal: no
BaseQuantities - Height: 2367 mm
Name | In | OverallWidth (mm) = Width (mm) | Perimeter (mm) | Area (m2) | Volume (m3) = NetVolume (m3) | Depth (mm)
22_BI-B-01a_305 | 00 Begane grond | 2084 | 8902 | 4.93283 | 0.230452 | 160
22_BI-B-01_305 | 00 Begane grond | 1849.34 | 8432.68 | 4.37739 | 0.207071 | 150
22_BI-B-02_305 | 01 1e verdieping | 1600.2 | 7934.4 | 3.78767 | 0.182248 | 150

# IfcDoor: D2 bl 27, 21_BU-C-02_305
In: 00 Begane grond
Type - OperationType: DOUBLE_DOOR_SINGLE_SWING; ParameterTakesPrecedence: no; Sizeable: no
OverallHeight: 3452 mm; OverallWidth: 1837 mm
Material - Frame / Draaiend deel: n.v.t.; Deurblad: n.v.t.; Onderdorpel: n.v.t.; Stofdorpel: n.v.t.; Vensterbank: n.v.t.; Ventilatierooster: n.v.t.; Spouwlat: n.v.t.; Rollaag / Latei: n.v.t.; Afwerking dagkant buiten: n.v.t.; Afwerking dagkant binnen: n.v.t.; Zonwering - behuizing: n.v.t.; Zonwering - isolatie: n.v.t.; Glas: Glas - algemeen
Pset_DoorCommon - IsExternal: no
BaseQuantities - Height: 3452 mm; Width: 1837 mm; Perimeter: 10578 mm; Area: 6.34132 m2; Volume: 0.148911 m3; Depth: 420 mm; NetVolume: 0.148911 m3

# IfcDoor: D2 bl zl1 27 (2)
In: 00 Begane grond
Type - OperationType: USERDEFINED; ParameterTakesPrecedence: no; Sizeable: no
OverallHeight: 3452 mm; OverallWidth: 3104 mm
Material - Frame / Draaiend deel: n.v.t.; Deurblad: n.v.t.; Onderdorpel: n.v.t.; Stofdorpel: n.v.t.; Vensterbank: n.v.t.; Ventilatierooster: n.v.t.; Spouwlat: n.v.t.; Rollaag / Latei: n.v.t.; Afwerking dagkant buiten: n.v.t.; Afwerking dagkant binnen: n.v.t.; Zonwering - behuizing: n.v.t.; Zonwering - isolatie: n.v.t.; Glas: Glas - algemeen
Pset_DoorCommon - IsExternal: no
BaseQuantities - Height: 3452 mm; Width: 3104 mm; Perimeter: 13112 mm; Area: 10.715 m2; Volume: 0.217654 m3; Depth: 420 mm; NetVolume: 0.217654 m3

# IfcDoor: D2 bl zl2 27 (13)
Type - OperationType: USERDEFINED; ParameterTakesPrecedence: no; Sizeable: no
OverallHeight: 3000 mm
BaseQuantities - Height: 3000 mm
Material - Glas: Glas - algemeen
Name | In | OverallWidth (mm) = Width (mm) | IsExternal | Perimeter (mm) | Area (m2) | Volume (m3) = NetVolume (m3) | Depth (mm) | Frame / Draaiend deel = Stofdorpel = Vensterbank = Ventilatierooster = Rollaag / Latei = Afwerking dagkant buiten = Afwerking dagkant binnen = Zonwering - behuizing | Deurblad | Onderdorpel | Spouwlat | Zonwering - isolatie
21_BI-D-02_305 | 00 Begane grond | 3450 | no | 12900 | 10.35 | 0.22762 | 270 | arcering (01) | arcering (02) | % | Naaldhout (01) | Loofhout
22_BI-D-03_305 | 00 Begane grond | 3450 | yes | 12900 | 10.35 | 0.228588 | 150 | n.v.t. | n.v.t. | n.v.t. | n.v.t. | n.v.t.
22_BI-D-06_305 | 00 Begane grond | 3450 | yes | 12900 | 10.35 | 0.219935 | 270 | n.v.t. | n.v.t. | n.v.t. | n.v.t. | n.v.t.
22_BI-F-30_305 | 00 Begane grond | 3650 | no | 13300 | 10.95 | 0.0599764 | 125 | arcering (01) | arcering (02) | % | Naaldhout (01) | Loofhout
22_BI-D-04_305 | 00 Begane grond | 3650 | yes | 13300 | 10.95 | 0.231038 | 150 | n.v.t. | n.v.t. | n.v.t. | n.v.t. | n.v.t.
22_BI-D-03_305 | 01 1e verdieping | 3450 | yes | 12900 | 10.35 | 0.228588 | 150 | n.v.t. | n.v.t. | n.v.t. | n.v.t. | n.v.t.
21_BI-D-06_305 | 01 1e verdieping | 3450 | yes | 12900 | 10.35 | 0.223171 | 403.5 | n.v.t. | n.v.t. | n.v.t. | n.v.t. | n.v.t.
21_BI-D-06_305 | 01 1e verdieping | 3450 | yes | 12900 | 10.35 | 0.228588 | 270 | n.v.t. | n.v.t. | n.v.t. | n.v.t. | n.v.t.
22_BI-F-17_305 | 01 1e verdieping | 2875 | no | 11750 | 8.625 | 0.180817 | 150 | arcering (01) | arcering (02) | % | Naaldhout (01) | Loofhout
22_BI-D-04_305 | 01 1e verdieping | 3650 | yes | 13300 | 10.95 | 0.229398 | 150 | n.v.t. | n.v.t. | n.v.t. | n.v.t. | n.v.t.
22_BI-D-03_305 | 02 2e verdieping | 3450 | yes | 12900 | 10.35 | 0.228588 | 150 | n.v.t. | n.v.t. | n.v.t. | n.v.t. | n.v.t.
21_BI-D-06_305 | 02 2e verdieping | 3450 | yes | 12900 | 10.35 | 0.228588 | 270 | n.v.t. | n.v.t. | n.v.t. | n.v.t. | n.v.t.
22_BI-D-04_305 | 02 2e verdieping | 3650 | yes | 13300 | 10.95 | 0.231038 | 150 | n.v.t. | n.v.t. | n.v.t. | n.v.t. | n.v.t.

# IfcDoor: D2 zl2 27 (2)
Type - OperationType: USERDEFINED; ParameterTakesPrecedence: no; Sizeable: no
OverallHeight: 2367 mm; OverallWidth: 3450 mm
Pset_DoorCommon - IsExternal: yes
Material - Frame / Draaiend deel: n.v.t.; Deurblad: n.v.t.; Onderdorpel: n.v.t.; Stofdorpel: n.v.t.; Vensterbank: n.v.t.; Ventilatierooster: n.v.t.; Spouwlat: n.v.t.; Rollaag / Latei: n.v.t.; Afwerking dagkant buiten: n.v.t.; Afwerking dagkant binnen: n.v.t.; Zonwering - behuizing: n.v.t.; Zonwering - isolatie: n.v.t.; Glas: Glas - algemeen
BaseQuantities - Height: 2367 mm; Width: 3450 mm; Perimeter: 11634 mm; Area: 8.16615 m2; Volume: 0.180621 m3; Depth: 160 mm; NetVolume: 0.180621 m3
Name | In
22_BI-D-05_305 | 00 Begane grond
22_BI-D-05_305 | 02 2e tussenverdieping

# IfcDoor: DS1 voor wand 27 (6)
Type - OperationType: SLIDING_TO_LEFT; ParameterTakesPrecedence: no; Sizeable: no
OverallHeight: 2100 mm
Pset_DoorCommon - IsExternal: yes
Material - Frame / Draaiend deel: n.v.t.; Deurblad: n.v.t.; Onderdorpel: n.v.t.; Stofdorpel: n.v.t.; Vensterbank: n.v.t.; Spouwlat: n.v.t.; Rollaag / Latei: n.v.t.; Afwerking dagkant buiten: n.v.t.; Afwerking dagkant binnen: n.v.t.; Zonwering - behuizing: n.v.t.; Zonwering - isolatie: n.v.t.; Glas: Glas - algemeen
Name | In | OverallWidth (mm) = Width (mm) | Height (mm) | Perimeter (mm) | Area (m2) | Volume (m3) = NetVolume (m3) | Depth (mm)
22_liftdeur_305 | 00 Begane grond | 1300 | 2100 | 6800 | 2.73 | 0.5733 | 150
22_liftdeur_305 | 00 Begane grond | 900 | 1062 | 3924 | 0.9558 | 0.3969 | 214
22_liftdeur_305 | 01 1e verdieping | 1300 | 2100 | 6800 | 2.73 | 0.5733 | 150
22_liftdeur_305 | 01 1e verdieping | 900 | 2100 | 6000 | 1.89 | 0.3969 | 214
22_liftdeur_305 | 02 2e verdieping | 1300 | 2100 | 6800 | 2.73 | 0.5733 | 150
22_liftdeur_305 | 02 2e verdieping | 900 | 2100 | 6000 | 1.89 | 0.3969 | 214

# IfcDoor: DSn 27 (2)
In: 00 Begane grond
Type - OperationType: USERDEFINED; ParameterTakesPrecedence: no; Sizeable: no
Material - Frame / Draaiend deel: n.v.t.; Deurblad: n.v.t.; Onderdorpel: n.v.t.; Stofdorpel: n.v.t.; Vensterbank: n.v.t.; Ventilatierooster: n.v.t.; Spouwlat: n.v.t.; Rollaag / Latei: n.v.t.; Afwerking dagkant buiten: n.v.t.; Afwerking dagkant binnen: n.v.t.; Zonwering - behuizing: n.v.t.; Zonwering - isolatie: n.v.t.; Glas: Glas - algemeen
Pset_DoorCommon - IsExternal: no
Name | OverallHeight (mm) = Height (mm) | OverallWidth (mm) = Width (mm) | Perimeter (mm) | Area (m2) | Volume (m3) = NetVolume (m3) | Depth (mm)
22_BI-G-01_305 | 3000 | 3850 | 13700 | 11.55 | 0.207758 | 150
21_BU-E-01_305 | 2450 | 3870 | 12640 | 9.4815 | 0.404599 | 312.5

# IfcFurnishingElement: Buitenbank 02 27 (2)
In: 00 Begane grond
Type - ElementType: CHAIR

# IfcOpeningElement (475)
Name | In | Height (mm) | Width (mm) | Depth (mm) | Area (m2) | Volume (m3)
3 x 22_Opening_ | Kelder | 1300 | 700 | 250 | 0.91 | 0.2275
22_vloerluik_ | -1 Fundering |  |  | 150 | 0.0176715 | 0.00265747
23_Opening_ | -1 Fundering | 700 | 712.608 | 0 | 0.498826 | 0
2 x 23_pompput_ | -1 Fundering | 500 | 500 | 50 | 0.25 | 0.0125
3 x 22_vloerluik_ | -1 Fundering |  |  | 250 | 0.0019635 | 0.000492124
3 x 22_vloerluik_ | -1 Fundering |  |  | 250 | 0.0176715 | 0.00442911
21_BI-D-02_305 | 00 Begane grond | 3000 | 3450 | 270 | 10.35 | 0.22762
22_BI-H-02_305 | 00 Begane grond | 2434 | 1979.9 | 150 | 4.81908 | 0.0674747
22_BI-A-01 sp_305 | 00 Begane grond | 2434 | 1034 | 150 | 2.51676 | 0.130067
22_BI-B-01a_305 | 00 Begane grond | 2367 | 2084 | 160 | 4.93283 | 0.230452
22_BI-A-06_305 | 00 Begane grond | 2367 | 1034 | 160 | 2.44748 | 0.126632
22_liftdeur_305 | 00 Begane grond | 2100 | 1300 | 150 | 2.73 | 0.5733
22__305 | 00 Begane grond | 2300 | 1600 | 150 | 3.68 | 0.057
22_BI-D-03_305 | 00 Begane grond | 3000 | 3450 | 150 | 10.35 | 0.228588
3 x 22_BI-A-01_305 | 00 Begane grond | 2367 | 1034 | 150 | 2.44748 | 0.126632
2 x 22_BI-A-01 sp_305 | 00 Begane grond | 2367 | 1034 | 150 | 2.44748 | 0.126632
22_BI-D-06_305 | 00 Begane grond | 3000 | 3450 | 270 | 10.35 | 0.219935
22_54-x_305 | 00 Begane grond | 0.5 | 3450 | 160 | 0.001725 | 0
22_BI-E-21_305 | 00 Begane grond | 1267 | 1200 | 160 | 1.5204 | 0.0356389
22_BI-D-05_305 | 00 Begane grond | 2367 | 3450 | 160 | 8.16615 | 0.180621
22_BI-A-05_305 | 00 Begane grond | 2367 | 1034 | 160 | 2.44748 | 0.126632
22__305 | 00 Begane grond | 2100 | 1034 | 70 | 2.1714 | 0
22_BI-G-01_305 | 00 Begane grond | 3000 | 3850 | 150 | 11.55 | 0.207758
22_BI-E-04_305 | 00 Begane grond | 1464 | 3111.63 | 150 | 4.55543 | 0.0881675
22_BI-A-02 sp_305 | 00 Begane grond | 2367 | 1034 | 150 | 2.44748 | 0.0784854
22_BI-F-31_305 | 00 Begane grond | 2479.5 | 484.078 | 150 | 1.20027 | 0.00300827
22__305 | 00 Begane grond | 2100 | 1000 | 150 | 2.1 | 0
22__305 | 00 Begane grond | 2300 | 1000 | 150 | 2.3 | 0
22_BI-E-02b_305 | 00 Begane grond | 3000 | 3650 | 150 | 8.334 | 0.225096
22_BI-A-04 sp_305 | 00 Begane grond | 2367 | 1034 | 150 | 2.44748 | 0.125832
22_BI-E-06_305 | 00 Begane grond | 2367 | 3250 | 150 | 7.69275 | 0.214396
22_BI-A-07_305 | 00 Begane grond | 2370 | 1064 | 150 | 2.52168 | 0.127559
22__305 | 00 Begane grond | 2367 | 2000 | 150 | 4.734 | 0
43_Opening_ | 00 Begane grond | 250 | 250 | 3 | 0.0625 | 0.0001875
22_BU-B-02_305 | 00 Begane grond | 2377 | 5328.92 | 312.5 | 12.6669 | 0.247398
8 x 21_BU-B-04_305 | 00 Begane grond | 3353.98 | 2000 | 420 | 6.70795 | 0.175669
21_BU-B-03_305 | 00 Begane grond | 3353.98 | 1940 | 420 | 6.50671 | 0.171278
21_BU-B-03 sp_305 | 00 Begane grond | 3353.98 | 1940 | 420 | 6.50671 | 0.171278
21_BU-E-01_305 | 00 Begane grond | 2450 | 3870 | 312.5 | 9.4815 | 0.404599
23_Opening_ | 00 Begane grond | 600 | 600 | 0 | 0.36 | 0
23_Opening_ | 00 Begane grond | 800 | 593.345 | 0 | 0.474676 | 0
2 x 23_vloerluik_ | 00 Begane grond | 600 | 800 | 80 | 0.48 | 0.0384
23_Opening_ | 00 Begane grond | 583.164 | 600 | 0 | 0.349898 | 0
23_Opening_ | 00 Begane grond | 500 | 990.337 | 0 | 0.495169 | 0
8 x 21_BU-A-01b_305 | 00 Begane grond | 3450 | 1326 | 420 | 4.5747 | 0.0894829
8 x 21_BU-A-01a_305 | 00 Begane grond | 3450 | 1702 | 420 | 5.8719 | 0.0836093
2 x 21_BU-C-01_305 | 00 Begane grond | 3452 | 3104 | 420 | 10.715 | 0.217654
6 x 21_BU-A-01b sp_305 | 00 Begane grond | 3450 | 1326 | 420 | 4.5747 | 0.0894829
5 x 21_BU-A-01a sp_305 | 00 Begane grond | 3450 | 1702 | 420 | 5.8719 | 0.0836093
21_BU-C-02_305 | 00 Begane grond | 3452 | 1837 | 420 | 6.34132 | 0.148911
21_BU-F-01_305 | 00 Begane grond | 3472 | 3104 | 420 | 10.7771 | 0.363136
21_BU-F-01_305 | 00 Begane grond | 3472 | 3104 | 420 | 10.7771 | 0.416056
2 x 23_Opening_ | 00 Begane grond | 250 | 250 | 30 | 0.0625 | 0.001875
3 x 23_Opening_ | 00 Begane grond | 225 | 225 | 30 | 0.050625 | 0.00151875
2 x 23_Opening_ | 00 Begane grond | 190 | 190 | 30 | 0.0361 | 0.001083
22_BI-C-04_305 | 00 Begane grond | 3200 | 2400 | 150 | 7.68 | 0.100806
22_BI-F-08_305 | 00 Begane grond | 3000 | 3875 | 150 | 11.625 | 0.0988146
22_BI-E-01_305 | 00 Begane grond | 2000 | 3649.93 | 150 | 7.29987 | 0.127019
22_BI-C-01_305 | 00 Begane grond | 2367 | 1750 | 150 | 4.14225 | 0.154625
22_BI-C-02 sp_305 | 00 Begane grond | 2367 | 1500 | 150 | 3.5505 | 0.150007
22_BI-C-01 sp_305 | 00 Begane grond | 2367 | 1750 | 150 | 4.14225 | 0.154625
22_BI-E-02_305 | 00 Begane grond | 3000 | 3650 | 150 | 8.334 | 0.252604
22_BI-F-02 sp_305 | 00 Begane grond | 3000 | 2541.67 | 150 | 7.625 | 0.0970546
22_BI-F-02_305 | 00 Begane grond | 3000 | 2541.67 | 150 | 7.625 | 0.0970546
22_BI-F-01_305 | 00 Begane grond | 3000 | 3862.5 | 150 | 11.5875 | 0.0987981
22_BI-F-03_305 | 00 Begane grond | 3000 | 1604.17 | 150 | 4.8125 | 0.0958171
22_BI-F-07_305 | 00 Begane grond | 3000 | 2707.81 | 150 | 8.12344 | 0.0972739
22_BI-F-04_305 | 00 Begane grond | 3000 | 6541.67 | 150 | 19.625 | 0.102335
22_BI-F-05_305 | 00 Begane grond | 3000 | 3875 | 150 | 11.625 | 0.0988146
22_BI-H-01_305 | 00 Begane grond | 2517 | 6514 | 150 | 16.3957 | 0.12777
22__305 | 00 Begane grond | 1552 | 3350.39 | 150 | 5.1998 | 0.0310205
22_BI-F-30_305 | 00 Begane grond | 3000 | 3650 | 125 | 10.95 | 0.0599764
43_vloerluik_ | 00 Begane grond | 800 | 600 | 3 | 0.48 | 0.00144
2 x 43_vloerluik_ | 00 Begane grond | 800 | 600 | 0 | 0.48 | 0
43_vloerluik_ | 00 Begane grond | 500 | 800 | 3 | 0.4 | 0.0012
22_BI-A-01 sp_305 | 00 Begane grond | 2367 | 1034 | 150 | 2.44748 | 0.125221
22_BI-A-03 sp_305 | 00 Begane grond | 2367 | 984.005 | 150 | 2.32913 | 0.120851
22_BI-A-03_305 | 00 Begane grond | 2367 | 984 | 150 | 2.32913 | 0.120851
22__305 | 00 Begane grond | 1471 | 3650 | 150 | 5.36915 | 0
22_BI-F-29_305 | 00 Begane grond | 2400 | 430 | 125 | 1.032 | 0.0034249
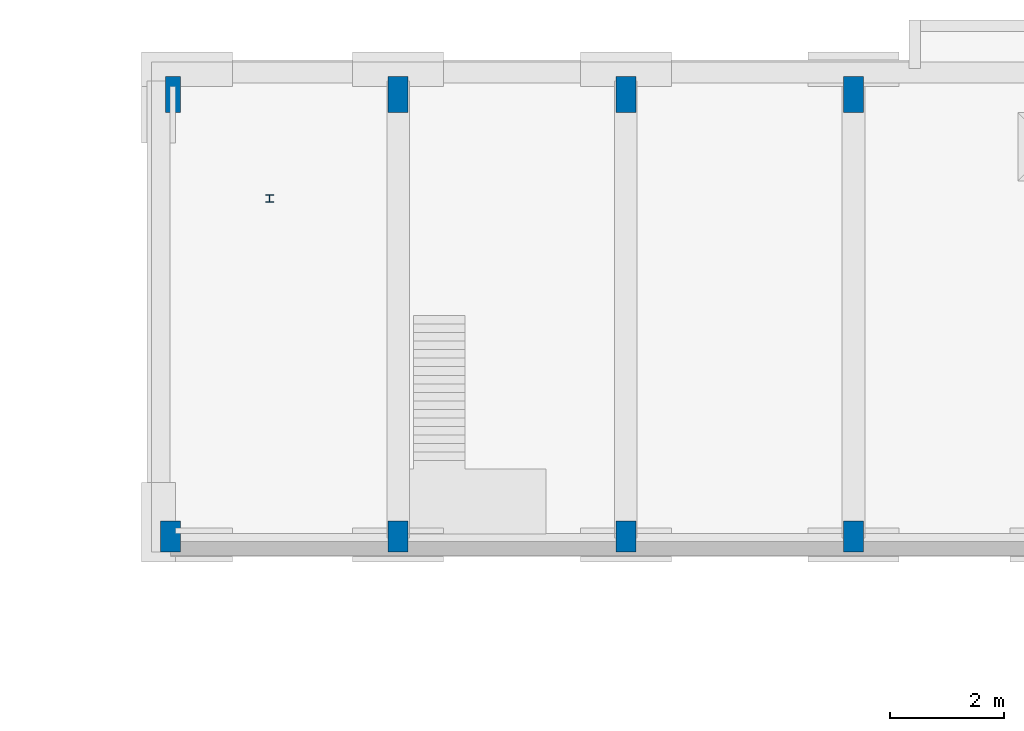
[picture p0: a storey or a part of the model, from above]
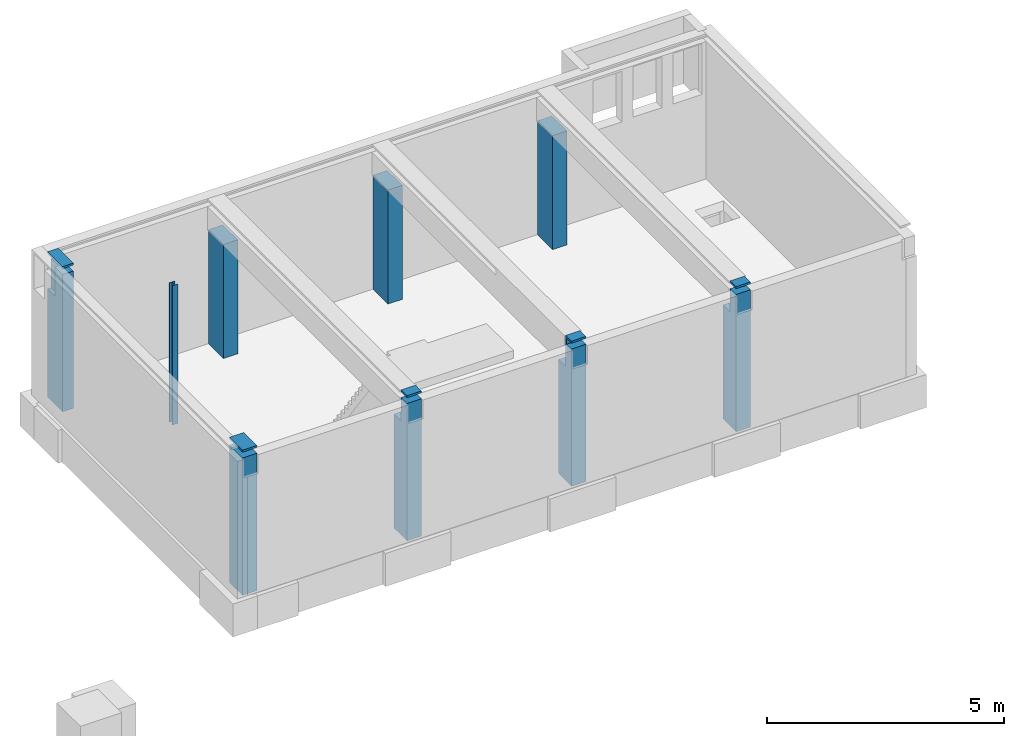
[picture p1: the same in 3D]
Properties of the parts of a building model (IFC2X3), part 4 of 5

# IfcOpeningElement (475)
Name | In | Height (mm) | Width (mm) | Depth (mm) | Area (m2) | Volume (m3)
22_BI-F-28_305 | 00 Begane grond | 2400 | 1225 | 125 | 2.94 | 0.00479866
22_BI-F-27_305 | 00 Begane grond | 2400 | 1747.5 | 150 | 4.194 | 0.0960698
22_BI-F-27 sp_305 | 00 Begane grond | 2400 | 1706.71 | 150 | 4.09609 | 0.096016
21__305 | 00 Begane grond | 3536.94 | 3928 | 420 | 13.8931 | 0
21_BU-D-06_305 | 00 Begane grond | 2345 | 990 | 420 | 2.32155 | 0.0514159
22__305 | 00 Begane grond | 1552 | 1545.04 | 150 | 2.39791 | 0.0179758
22__305 | 00 Begane grond | 2362.2 | 900 | 150 | 2.12598 | 0
22_BI-A-04_305 | 00 Begane grond | 2367 | 900 | 150 | 2.1303 | 0.0890662
22__305 | 00 Begane grond | 1062 | 1200 | 214 | 1.2744 | 0.0522
22_liftdeur_305 | 00 Begane grond | 1062 | 900 | 214 | 0.9558 | 0.3969
22_vloerluik_ | 00 Begane grond |  |  | 150 | 0.00384845 | 0.000578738
22_BI-H-03_305 | 00 Begane grond | 0 | 0 | 150 | 0 | 0.0817668
22_BI-D-04_305 | 00 Begane grond | 3000 | 3650 | 150 | 10.95 | 0.231038
22_BI-E-05_305 | 00 Begane grond | 3000 | 984 | 150 | 2.952 | 0.176405
2 x 22_BI-A-01_305 | 00 Begane grond | 2367 | 984 | 150 | 2.32913 | 0.121605
22_BI-B-01_305 | 00 Begane grond | 2367 | 1849.34 | 150 | 4.37739 | 0.207071
23_Opening_ | 00 Begane grond | 1500 | 1500 | 50 | 2.25 | 0.1125
23_Opening_ | 00 Begane grond | 1900 | 2500 | 50 | 4.75 | 0.2375
23_Opening_ | 00 Begane grond | 185.911 | 5500 | 0 | 1.02251 | 0
23_Opening_ | 00 Begane grond | 175 | 5500 | 50 | 0.9625 | 0.048125
23_Opening_ | 00 Begane grond |  |  | 50 | 25.6842 | 1.28421
23_vloerluik_ | 00 Begane grond | 800 | 600 | 50 | 0.48 | 0.024
23_vloerluik_ | 00 Begane grond | 560 | 800 | 50 | 0.448 | 0.0224
2 x 23_vloerluik_ | 00 Begane grond | 600 | 800 | 50 | 0.48 | 0.024
23_kelderluik_ | 00 Begane grond | 600 | 800 | 250 | 0.48 | 0.12
23_vloersparing_ | 00 Begane grond | 500 | 1000 | 250 | 0.5 | 0.125
23_kruipluik_ | 00 Begane grond | 800 | 600 | 250 | 0.48 | 0.12
23_vloersparing_ | 00 Begane grond | 400 | 400 | 250 | 0.16 | 0.04
3 x 23_vloersparing_ | 00 Begane grond |  |  | 250 | 0.0019635 | 0.000492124
23_vloersparing_ | 00 Begane grond |  |  | 232 | 0.0201062 | 0.00503935
2 x 23_pompput_ | 00 Begane grond | 143 | 3104 | 57 | 0.443872 | 0.0253007
23_pompput_ | 00 Begane grond | 2208.1 | 3338 | 18 | 7.37064 | 0.131404
23_kruipluik_ | 00 Begane grond | 250 | 200 | 250 | 0.05 | 0.0125
23_Opening_ | 00 Begane grond |  |  | 150 | 25.7617 | 3.86426
23_vloerluik_ | 00 Begane grond | 600 | 800 | 150 | 0.48 | 0.072
23_vloerluik_ | 00 Begane grond | 560 | 800 | 150 | 0.448 | 0.0672
22__305 | 00 Begane grond | 1900 | 2349.9 | 150 | 4.4648 | 0
4 x 28_pompput_ | 01 1e tussenverdieping | 125 | 620 | 50 | 0.0775 | 0.003875
21_BU-B-12_305 | 01 1e tussenverdieping | 2377 | 5328.92 | 397.5 | 12.6669 | 0.247398
22__305 | 01 1e tussenverdieping | 2500 | 1200 | 270 | 3 | 0
22__305 | 01 1e tussenverdieping | 2005 | 1200 | 270 | 2.406 | 0
22__305 | 01 1e tussenverdieping | 2100 | 900 | 270 | 1.89 | 0
22_BI-E-14_305 | 01 1e tussenverdieping | 2367 | 3450 | 160 | 8.16615 | 0.13798
23_Opening_ | 01 1e tussenverdieping | 1200 | 700 | 180 | 0.84 | 0.1512
23_Opening_ | 01 1e tussenverdieping | 290.621 | 5500 | 0 | 1.59842 | 0
23_Opening_ | 01 1e tussenverdieping | 1250 | 890 | 180 | 1.1125 | 0.20025
23_Opening_ | 01 1e tussenverdieping | 175 | 5500 | 150 | 0.9625 | 0.144375
22_BI-E-16_305 | 01 1e tussenverdieping | 2367 | 2675.28 | 150 | 6.33238 | 0.185016
22_BI-E-15_305 | 01 1e tussenverdieping | 2367 | 2675.28 | 150 | 6.33238 | 0.185815
22_BI-E-17_305 | 01 1e tussenverdieping | 2367 | 4530 | 150 | 10.7225 | 0.248259
23_Opening_ | 01 1e tussenverdieping | 1000.02 | 600 | 30 | 0.600013 | 0.00054
22_BU-B-11_305 | 01 1e tussenverdieping | 2377 | 5328.92 | 397.5 | 12.6669 | 0.235611
2 x 22_BI-A-04_305 | 01 1e tussenverdieping | 2367 | 1034 | 150 | 2.44748 | 0.125832
23_Opening_ | 01 1e verdieping |  |  | 150 | 0.960027 | 0.144004
23_Opening_ | 01 1e verdieping |  |  | 150 | 0.96 | 0.144
23_Opening_ | 01 1e verdieping | 1800 | 1650 | 120 | 2.97 | 0.3564
23_Opening_ | 01 1e verdieping | 1800 | 1860 | 120 | 3.348 | 0.40176
23_Opening_ | 01 1e verdieping |  |  | 120 | 4.75 | 0.57
23__ | 01 1e verdieping |  |  | 120 | 0.81 | 0.0971136
23_Opening_ | 01 1e verdieping | 450 | 470 | 120 | 0.2115 | 0.02538
21_BI-D-06_305 | 01 1e verdieping | 3000 | 3450 | 403.5 | 10.35 | 0.223171
22_liftdeur_305 | 01 1e verdieping | 2100 | 1300 | 150 | 2.73 | 0.5733
22__305 | 01 1e verdieping | 2300 | 1600 | 150 | 3.68 | 0.057
22_BI-D-03_305 | 01 1e verdieping | 3000 | 3450 | 150 | 10.35 | 0.228588
22_BI-C-01 sp_305 | 01 1e verdieping | 2367 | 1750 | 150 | 4.14225 | 0.154625
22_BI-C-01_305 | 01 1e verdieping | 2367 | 1750 | 150 | 4.14225 | 0.154625
2 x 22_Opening_ | 01 1e verdieping |  |  | 150 | 5.3862 | 0.80793
22_BI-F-15_305 | 01 1e verdieping | 3000 | 5925.07 | 150 | 17.7752 | 0.101598
3 x 21_BU-A-13b sp_305 | 01 1e verdieping | 3259.59 | 1267 | 420 | 4.1299 | 0.0885023
4 x 21_BU-A-13a sp_305 | 01 1e verdieping | 3259.59 | 1837 | 420 | 5.98787 | 0.0907757
21_BU-A-13b sp_305 | 01 1e verdieping | 3254.59 | 1267 | 420 | 4.12357 | 0.0884344
6 x 21_BU-A-12a_305 | 01 1e verdieping | 3450 | 1837 | 420 | 6.33765 | 0.0944533
5 x 21_BU-A-12b_305 | 01 1e verdieping | 3450 | 1267 | 420 | 4.37115 | 0.0910865
21_BU-A-12c_305 | 01 1e verdieping | 3454 | 1267.01 | 420 | 4.37625 | 0.106908
3 x 21_BU-A-12a_305 | 01 1e verdieping | 3454 | 1837 | 420 | 6.345 | 0.0945305
2 x 21_BU-A-12b_305 | 01 1e verdieping | 3454 | 1267 | 420 | 4.37622 | 0.103448
21_BU-A-12b_305 | 01 1e verdieping | 3454 | 1267 | 420 | 4.37622 | 0.097124
21_BU-A-14a_305 | 01 1e verdieping | 3454 | 1758.99 | 420 | 6.07556 | 0.0774251
21_BI-D-06_305 | 01 1e verdieping | 3000 | 3450 | 270 | 10.35 | 0.228588
8 x 21_BU-A-12a sp_305 | 01 1e verdieping | 3450 | 1702 | 420 | 5.8719 | 0.0853376
8 x 21_BU-A-12b sp_305 | 01 1e verdieping | 3450 | 1326 | 420 | 4.5747 | 0.0863644
2 x 23_Opening_ | 01 1e verdieping | 1500 | 900 | 0 | 1.35 | 0
22_BI-E-04_305 | 01 1e verdieping | 3000 | 984 | 150 | 2.952 | 0.176405
3 x 22_BI-E-01_305 | 01 1e verdieping | 1700 | 3649.9 | 150 | 6.20483 | 0.115561
4 x 22_BI-E-01_305 | 01 1e verdieping | 1700 | 1850 | 150 | 3.145 | 0.0641439
2 x 22_BI-E-03_305 | 01 1e verdieping | 3000 | 3650 | 150 | 8.65402 | 0.250042
2 x 22_vitrine_305 | 01 1e verdieping | 2367 | 2666 | 150 | 6.31042 | 0
22_BI-E-04 sp_305 | 01 1e verdieping | 3000 | 984 | 150 | 2.952 | 0.176405
22_BI-E-02_305 | 01 1e verdieping | 3000 | 1867 | 150 | 5.601 | 0.176117
22_BI-C-03_305 | 01 1e verdieping | 2367 | 1466.51 | 150 | 3.47123 | 0.10184
2 x 43_Opening_ | 01 1e verdieping | 600 | 1300 | 0 | 0.78 | 0
43_Opening_ | 01 1e verdieping |  |  | 0 | 0.15 | 0
2 x 22_BI-A-06 sp_305 | 01 1e verdieping | 2367 | 1034 | 150 | 2.44748 | 0.126632
22_BI-F-10_305 | 01 1e verdieping | 3000 | 2183.12 | 150 | 6.54935 | 0.00598945
22_BI-F-11_305 | 01 1e verdieping | 3000 | 3200 | 150 | 9.6 | 0.0979236
22_BI-F-19_305 | 01 1e verdieping | 3000 | 4264.04 | 150 | 12.7921 | 0.0992588
22_BI-A-04_305 | 01 1e verdieping | 2367 | 1034 | 150 | 2.44748 | 0.125832
22_BI-F-12_305 | 01 1e verdieping | 3000 | 4300.53 | 150 | 12.9016 | 0.0993763
22_BI-F-13_305 | 01 1e verdieping | 3000 | 3850 | 150 | 11.55 | 0.0987816
22_BI-A-04 sp_305 | 01 1e verdieping | 2367 | 1034 | 150 | 2.44748 | 0.125832
22_BI-B-02_305 | 01 1e verdieping | 2367 | 1600.2 | 150 | 3.78767 | 0.182248
23_Opening_ | 01 1e verdieping |  |  | 0 | 0.961041 | 0
23_Opening_ | 01 1e verdieping |  |  | 0 | 0.960027 | 0
4 x 21_BU-A-12a sp_305 | 01 1e verdieping | 3450 | 1837 | 420 | 6.33765 | 0.0944533
4 x 21_BU-A-12b sp_305 | 01 1e verdieping | 3450 | 1267 | 420 | 4.37115 | 0.0910865
22__305 | 01 1e verdieping | 1238 | 1200 | 214 | 1.4856 | 0
22__305 | 01 1e verdieping | 2155 | 1200 | 214 | 2.586 | 0.0522
22_liftdeur_305 | 01 1e verdieping | 2100 | 900 | 214 | 1.89 | 0.3969
22_BI-F-17_305 | 01 1e verdieping | 3000 | 2875 | 150 | 8.625 | 0.180817
2 x 22_BI-F-10_305 | 01 1e verdieping | 3000 | 2183.12 | 150 | 6.54935 | 0.00591565
22_BI-D-04_305 | 01 1e verdieping | 3000 | 3650 | 150 | 10.95 | 0.229398
22_BI-E-01_305 | 01 1e verdieping | 1700 | 3650 | 150 | 6.205 | 0.115563
22_BI-E-02_305 | 01 1e verdieping | 3000 | 1867 | 150 | 5.601 | 0.176992
2 x 22_BI-E-03 sp_305 | 01 1e verdieping | 3000 | 3650 | 150 | 8.65402 | 0.250042
2 x 22_BI-E-02 sp_305 | 01 1e verdieping | 3000 | 1867 | 150 | 5.601 | 0.176992
22_BI-H-11_305 | 01 1e verdieping | 2367 | 1034 | 150 | 2.44748 | 0.0566217
22_Opening_ | 01 1e verdieping | 2367 | 3620 | 150 | 8.56854 | 1.28447
22_BI-F-14_305 | 01 1e verdieping | 3000 | 3175.04 | 150 | 9.52513 | 0.097748
21_BU-A-15b_305 | 01 1e verdieping | 3454 | 1267 | 420 | 4.37622 | 0.097124
21_BU-A-15a_305 | 01 1e verdieping | 3454 | 1837 | 420 | 6.345 | 0.0861159
21_BU-A-14b_305 | 01 1e verdieping | 3454 | 1060.48 | 420 | 3.66291 | 0.102038
22_BI-A-04 sp_305 | 01 1e verdieping | 2367 | 984 | 150 | 2.32913 | 0.120851
22_BI-A-03_305 | 01 1e verdieping | 2367 | 984 | 150 | 2.32913 | 0.120851
22__305 | 01 1e verdieping | 1840 | 1534.04 | 150 | 2.82264 | 0
10 x 21_BU-A-12b_305 | 01 1e verdieping | 3450 | 1326 | 420 | 4.5747 | 0.0863644
10 x 21_BU-A-12a_305 | 01 1e verdieping | 3450 | 1702 | 420 | 5.8719 | 0.0853376
10 x 21__305 | 01 1e verdieping | 3454 | 3104 | 420 | 10.7212 | 0
22_BI-F-18_305 | 01 1e verdieping | 3000 | 4151.57 | 150 | 12.4547 | 0.0993263
22_BI-F-16_305 | 01 1e verdieping | 3000 | 4151.57 | 150 | 12.4547 | 0.0991103
23_Opening_ | 02 2e tussenverdieping |  |  | 0 | 10.2377 | 0
23_Opening_ | 02 2e tussenverdieping | 1200 | 700 | 200 | 0.84 | 0.168
23_Opening_ | 02 2e tussenverdieping | 1249.75 | 700.128 | 0 | 0.874985 | 0
23_Opening_ | 02 2e tussenverdieping | 290.621 | 5500 | 0 | 1.59842 | 0
23_Opening_ | 02 2e tussenverdieping | 175 | 5500 | 150 | 0.9625 | 0.144375
2 x 22_BI-A-06_305 | 02 2e tussenverdieping | 2367 | 1034 | 150 | 2.44748 | 0.126632
22_BI-E-21_305 | 02 2e tussenverdieping | 1267 | 1200 | 160 | 1.5204 | 0.0356389
22_BI-D-05_305 | 02 2e tussenverdieping | 2367 | 3450 | 160 | 8.16615 | 0.180621
22__305 | 02 2e tussenverdieping | 2100 | 3500 | 160 | 7.35 | 0
22_BI-A-05_305 | 02 2e tussenverdieping | 2367 | 1034 | 160 | 2.44748 | 0.126632
22_BI-H-03_305 | 02 2e tussenverdieping | 2367 | 3188.21 | 160 | 7.5465 | 0.0782715
21_BU-B-23_305 | 02 2e tussenverdieping | 3453.97 | 1940 | 420 | 6.70071 | 0.158791
8 x 21_BU-B-24_305 | 02 2e tussenverdieping | 3453.97 | 2000 | 420 | 6.90795 | 0.162728
21_BU-B-23 sp_305 | 02 2e tussenverdieping | 3453.97 | 1940 | 420 | 6.70071 | 0.158791
3 x 23_Opening_ | 02 2e tussenverdieping | 225 | 225 | 30 | 0.050625 | 0.00151875
4 x 23_Opening_ | 02 2e tussenverdieping | 190 | 190 | 30 | 0.0361 | 0.001083
22__305 | 02 2e tussenverdieping | 2100 | 1000 | 150 | 2.1 | 0
22_BI-A-04_305 | 02 2e tussenverdieping | 2367 | 1034 | 150 | 2.44748 | 0.125832
22__305 | 02 2e tussenverdieping | 2300 | 900 | 150 | 2.07 | 0
22_BI-A-01 sp_305 | 02 2e tussenverdieping | 2367 | 1034 | 150 | 2.44748 | 0.126632
23_Opening_ | 02 2e tussenverdieping | 1000 | 600 | 30 | 0.6 | 0.00054
23_Opening_ | 02 2e tussenverdieping | 1249.75 | 890 | 200 | 1.11228 | 0.212538
23_Opening_ | 02 2e verdieping | 450 | 400 | 120 | 0.18 | 0.0216
23_Opening_ | 02 2e verdieping | 1800 | 1650 | 120 | 2.97 | 0.3564
23_Opening_ | 02 2e verdieping | 1900 | 2500 | 120 | 4.75 | 0.57
23_Opening_ | 02 2e verdieping | 1800 | 1860 | 120 | 3.348 | 0.40176
22_liftdeur_305 | 02 2e verdieping | 2100 | 1300 | 150 | 2.73 | 0.5733
22__305 | 02 2e verdieping | 2300 | 1600 | 150 | 3.68 | 0.057
22_BI-D-03_305 | 02 2e verdieping | 3000 | 3450 | 150 | 10.35 | 0.228588
22_39-Gx_305 | 02 2e verdieping | 0 | 0 | 160 | 0 | 0
27_Opening_ | 02 2e verdieping | 1000 | 1400 | 100 | 1.4 | 0.14
22_BI-F-22_305 | 02 2e verdieping | 3000 | 3990 | 150 | 11.97 | 0.0989664
22_BI-F-23_305 | 02 2e verdieping | 3000 | 3790 | 150 | 11.37 | 0.0987024
21_BI-D-06_305 | 02 2e verdieping | 3000 | 3450 | 270 | 10.35 | 0.228588
8 x 21_BU-A-22a sp_305 | 02 2e verdieping | 3450 | 1702 | 420 | 5.8719 | 0.0853376
8 x 21_BU-A-22b sp_305 | 02 2e verdieping | 3450 | 1326 | 420 | 4.5747 | 0.0863644
2 x 23_Opening_ | 02 2e verdieping | 1500 | 900 | 0 | 1.35 | 0
22_BI-A-04_305 | 02 2e verdieping | 2367 | 1034 | 150 | 2.44748 | 0.126632
22_BI-A-04 sp_305 | 02 2e verdieping | 2367 | 1034 | 150 | 2.44748 | 0.125832
10 x 21_BU-A-22a_305 | 02 2e verdieping | 3450 | 1702 | 420 | 5.8719 | 0.0853376
10 x 21_BU-A-22b_305 | 02 2e verdieping | 3450 | 1326 | 420 | 4.5747 | 0.0863644
22_liftdeur_305 | 02 2e verdieping | 2100 | 900 | 214 | 1.89 | 0.3969
22__305 | 02 2e verdieping | 2300 | 1200 | 214 | 2.76 | 0.0522
3 x 22_BI-E-01_305 | 02 2e verdieping | 1700 | 3649.93 | 150 | 6.20489 | 0.115562
22_BI-E-01_305 | 02 2e verdieping | 1700 | 1845.21 | 150 | 3.13686 | 0.0640708
22_BI-E-02_305 | 02 2e verdieping | 3000 | 1967 | 150 | 5.901 | 0.177235
22_BI-E-01_305 | 02 2e verdieping | 1700 | 1743.22 | 150 | 2.96347 | 0.0625127
22_BI-E-02_305 | 02 2e verdieping | 3000 | 3650 | 150 | 7.5492 | 0.216937
2 x 22_BI-E-03_305 | 02 2e verdieping | 3000 | 3650 | 150 | 8.65402 | 0.248757
2 x 22_BI-E-02_305 | 02 2e verdieping | 3000 | 1867 | 150 | 5.601 | 0.175647
22_BI-C-01_305 | 02 2e verdieping | 2367 | 1750 | 150 | 4.14225 | 0.153214
22_BI-C-01 sp_305 | 02 2e verdieping | 2367 | 1750 | 150 | 4.14225 | 0.153214
22_BI-D-04_305 | 02 2e verdieping | 3000 | 3650 | 150 | 10.95 | 0.231038
22_BI-E-01_305 | 02 2e verdieping | 1700 | 1839.66 | 150 | 3.12742 | 0.0639859
22_BI-E-01_305 | 02 2e verdieping | 1700 | 3649.9 | 150 | 6.20483 | 0.115561
22_BI-E-01_305 | 02 2e verdieping | 1700 | 1850 | 150 | 3.145 | 0.0641439
22_BI-E-02 sp_305 | 02 2e verdieping | 3000 | 1867 | 150 | 5.601 | 0.175647
22_BI-E-03 sp_305 | 02 2e verdieping | 3000 | 3650 | 150 | 8.65402 | 0.248696
22_BI-E-02 sp_305 | 02 2e verdieping | 3000 | 3650 | 150 | 7.5492 | 0.216811
22_BI-E-03 sp_305 | 02 2e verdieping | 3000 | 3650 | 150 | 8.65402 | 0.24863
23_Opening_ | 03 3e tussenverdieping | 1200 | 700 | 150 | 0.84 | 0.126
23_Opening_ | 03 3e tussenverdieping |  |  | 150 | 10.2366 | 1.53549
23_Opening_ | 03 3e tussenverdieping | 175 | 5500 | 150 | 0.9625 | 0.144375
23_Opening_ | 03 3e tussenverdieping | 1250 | 890 | 150 | 1.1125 | 0.159375
23_Opening_ | 03 3e tussenverdieping | 290.621 | 5500 | 0 | 1.59842 | 0
22_BI-A-06 sp_305 | 03 3e tussenverdieping | 2367 | 1034 | 160 | 2.44748 | 0.126632
21_BU-B-31_305 | 03 3e tussenverdieping | 2377 | 5328.92 | 312.5 | 12.6669 | 0.247398
22_BI-E-18_305 | 03 3e tussenverdieping | 2367 | 4530 | 150 | 10.7225 | 0.24746
22_BI-E-14_305 | 03 3e tussenverdieping | 2367 | 3450 | 160 | 8.16615 | 0.122248
22_BI-E-19_305 | 03 3e tussenverdieping | 2367 | 2600 | 150 | 6.1542 | 0.16681
22_BI-E-20_305 | 03 3e tussenverdieping | 2367 | 1780 | 150 | 4.21326 | 0.154284
23_Opening_ | 03 3e tussenverdieping | 1000 | 600 | 0 | 0.6 | 0
22_BI-A-06 sp_305 | 03 3e tussenverdieping | 2300 | 1034 | 70 | 2.3782 | 0
21_BU-B-32_305 | 03 3e tussenverdieping | 2377 | 5328.92 | 312.5 | 12.6669 | 0.205897
27_Opening_ | 04 4e verdieping | 1000 | 700 | 150 | 0.7 | 0.105
27_Opening_ | 04 4e verdieping | 1000 | 1700 | 150 | 1.7 | 0.255
27_Opening_ | 04 4e verdieping | 1900 | 2500 | 150 | 4.75 | 0.7125
27_Opening_ | 04 4e verdieping | 1200 | 700 | 150 | 0.84 | 0.126
27_Opening_ | 04 4e verdieping | 1255 | 890 | 150 | 1.11695 | 0.167543
27_Opening_ | 04 4e verdieping | 1700 | 1000 | 150 | 1.7 | 0.255
47_Opening_ | 04 4e verdieping | 1289.65 | 3700 | 18 | 4.77171 | 0.00352033
47_BU-F-02_305 | 04 4e verdieping | 2246.96 | 1034 | 18.0001 | 2.60114 | 0.101674

# IfcRailing: Railing Type (24)
Pset_RailingCommon - IsExternal: yes
Name | In | Material | GrossVolume (m3) = NetVolume (m3) | Length (mm)
34_Reling_ | 00 Begane grond | staal balustrade (4), aluminium (3) | 0.123454 | 8390.81
34_Reling_ | 00 Begane grond | staal balustrade (4), aluminium (3) | 0.181386 | 11919.2
34_Reling_ | 00 Begane grond | staal balustrade (30), hout AFW (20) | 0.213267 | 18468.2
34_Reling_ | 00 Begane grond | staal balustrade (9), hout AFW (5) | 0.0521956 | 5070.41
34_Reling_ | 01 1e tussenverdieping | staal balustrade (8), hout AFW (4) | 0.045365 | 3650
34_Reling_ | 01 1e tussenverdieping | staal balustrade (15), hout AFW (7) | 0.0502139 | 4388.34
2 x 34_Reling_ | 01 1e tussenverdieping | staal balustrade (23) | 0.0159147 | 2059.26
34_Reling_ | 01 1e verdieping | staal balustrade (35) | 0.0263599 | 3640.26
34_Reling_ | 01 1e verdieping | staal balustrade (45) | 0.0311924 | 4220.26
34_Reling_ | 01 1e verdieping | staal balustrade (38), hout AFW (21) | 0.219458 | 18656.8
34_Reling_ | 01 1e verdieping | staal balustrade (9), hout AFW (4) | 0.0417097 | 4107.43
34_Reling_ | 01 1e verdieping | staal balustrade (8), hout AFW (4) | 0.0432375 | 3465
34_Reling_ | 02 2e tussenverdieping | staal balustrade (45) | 0.031245 | 4257.88
34_Reling_ | 02 2e tussenverdieping | staal balustrade (8), hout AFW (4) | 0.045365 | 3650
34_Reling_ | 02 2e tussenverdieping | staal balustrade (9), hout AFW (3) | 0.0218354 | 2034.74
34_Reling_ | 02 2e tussenverdieping | staal balustrade (16), hout AFW (7) | 0.048043 | 4496.03
34_Reling_ | 02 2e tussenverdieping | staal balustrade (35) | 0.0264125 | 3677.88
34_Reling_ | 02 2e tussenverdieping | staal balustrade (39) | 0.028643 | 3238.53
34_Reling_ | 02 2e verdieping | staal balustrade (45) | 0.03065 | 3832.89
34_Reling_ | 02 2e verdieping | staal balustrade (35) | 0.0258177 | 3252.89
34_Reling_ | 03 3e tussenverdieping | staal balustrade (8), hout AFW (4) | 0.045365 | 3650
34_Reling_ | 03 3e tussenverdieping | staal balustrade (9), hout AFW (4) | 0.0461633 | 3768.98
34_Reling_ | 03 3e tussenverdieping | staal balustrade (58) | 0.0442375 | 5068.22

# IfcRoof (8)
Pset_RoofCommon - IsExternal: yes
Name | In | Material | TotalSurfaceArea (m2)
27_Dak_ALG | 01 1e verdieping | ALG - ISOLATIE | 162.342
27_Dak_ALG | 02 2e verdieping | ALG - ISOLATIE | 257.731
27_Dak_ALG | 02 2e verdieping | ALG - ISOLATIE | 256.33
27_Dak_ALG | 03 3e tussenverdieping | ALG - ISOLATIE | 571.825
27_Dak_ALG | 03 3e tussenverdieping | ALG - ISOLATIE | 579.894
27_Dak_beton_gewapend_prefab | 04 4e verdieping | beton_gewapend_prefab vloer | 29.0934
27_Dak_ALG | 04 4e verdieping | ALG - ISOLATIE | 28.715
27_Dak_hout | 04 4e verdieping | hout C | 6.91305

# IfcSlab: ALG - ALGEMEEN 200 (2)
In: 00 Begane grond
Material: ALG - ALGEMEEN
Pset_SlabCommon - IsExternal: no
BaseQuantities - Width: 200 mm
Name | LoadBearing | Perimeter (mm) | GrossArea (m2) | NetArea (m2) | GrossVolume (m3) | NetVolume (m3)
23_Vloer_ALG | yes | 24218 | 32.2994 | 32.1129 | 6.45989 | 6.42258
23_Vloer_ALG | no | 13100 | 10.125 | 10.125 | 2.025 | 2.025

# IfcSlab: ALG - ALGEMEEN 45 (3)
Material: ALG - ALGEMEEN
BaseQuantities - Width: 45 mm
Pset_SlabCommon - IsExternal: no
Name | In | Perimeter (mm) | GrossArea (m2) | NetArea (m2) | GrossVolume (m3) | NetVolume (m3) | LoadBearing
47_Vloer_ALG | 03 3e tussenverdieping | 89682 | 425.6 | 27.8761 | 19.152 | 1.25442 | no
47_Vloer_ALG | 04 4e verdieping | 111000 | 383.373 | 32.9838 | 17.2518 | 1.48427 | yes
47_Vloer_ALG | 04 4e verdieping | 68679.8 | 22.9627 | 22.9627 | 1.03332 | 1.03332 | yes

# IfcSlab: ALG - ISOLATIE 100, 23_Vloer_ALG
In: 00 Begane grond
Material: ALG - ISOLATIE
Pset_SlabCommon - IsExternal: no; LoadBearing: yes
BaseQuantities - Width: 100 mm; Perimeter: 63410 mm; GrossArea: 213.19 m2; NetArea: 213.19 m2; GrossVolume: 21.319 m3; NetVolume: 21.319 m3

# IfcSlab: ALG - ISOLATIE 140 (2)
In: 04 4e verdieping
Material: ALG - ISOLATIE
Pset_SlabCommon - IsExternal: no; LoadBearing: yes
BaseQuantities - Width: 140 mm
Name | Perimeter (mm) | GrossArea (m2) = NetArea (m2) | GrossVolume (m3) = NetVolume (m3)
27_Vloer_ALG | 20395.9 | 20.2449 | 2.83428
27_Vloer_ALG | 23115.9 | 30.4072 | 4.25701

# IfcSlab: ALG - ISOLATIE 80 (2)
In: 00 Begane grond
Material: ALG - ISOLATIE
Pset_SlabCommon - IsExternal: no; LoadBearing: yes
BaseQuantities - Width: 80 mm
Name | Perimeter (mm) | GrossArea (m2) | NetArea (m2) | GrossVolume (m3) | NetVolume (m3)
23_Vloer_ALG | 181484 | 1152.25 | 1130.57 | 92.1578 | 90.4238
23_Vloer_ALG | 181583 | 1231.05 | 1210.13 | 98.4842 | 96.8104

# IfcSlab: ALG - ISOLATIE 85 (3)
In: 00 Begane grond
Material: ALG - ISOLATIE
BaseQuantities - Width: 85 mm
Pset_SlabCommon - IsExternal: no; LoadBearing: yes
Name | Perimeter (mm) | GrossArea (m2) = NetArea (m2) | GrossVolume (m3) = NetVolume (m3)
23_Vloer_ALG | 26727.6 | 42.1773 | 3.58507
23_Vloer_ALG | 30077.6 | 51.6939 | 4.39398
23_Vloer_ALG | 20927.6 | 24.6315 | 2.09368

# IfcSlab: GA-11 40, 45_Vloer_GA-11
In: 00 Begane grond
Material: Buitenplafond cf. K&M-staat
BaseQuantities - Width: 40 mm; Perimeter: 97720.7 mm; GrossArea: 287.464 m2; NetArea: 285.016 m2; GrossVolume: 11.4985 m3; NetVolume: 11.4007 m3
Pset_SlabCommon - IsExternal: no; LoadBearing: yes

# IfcSlab: Zwevende dekvloer 110, 23_Vloer_Zwevende
In: 00 Begane grond
Material: Zwevende dekvloer
BaseQuantities - Width: 110 mm; Perimeter: 26599.6 mm; GrossArea: 43.2121 m2; NetArea: 43.2121 m2; GrossVolume: 4.75334 m3; NetVolume: 4.75334 m3
Pset_SlabCommon - IsExternal: no; LoadBearing: yes

# IfcSlab: Zwevende dekvloer 30 (6)
Material: Zwevende dekvloer
Pset_SlabCommon - IsExternal: no; LoadBearing: yes
BaseQuantities - Width: 30 mm
Name | In | Perimeter (mm) | GrossArea (m2) | NetArea (m2) | GrossVolume (m3) | NetVolume (m3)
23_Vloer_Zwevende | 00 Begane grond | 13399.6 | 2.95677 | 2.95677 | 0.0887032 | 0.0887032
23_Vloer_Zwevende | 00 Begane grond | 8292 | 0.1886 | 0.1886 | 0.00565799 | 0.00565799
23_Vloer_Zwevende | 01 1e tussenverdieping | 54674.6 | 114.053 | 114.035 | 3.42159 | 3.42105
23_Vloer_Zwevende | 02 2e tussenverdieping | 58250.8 | 103.432 | 103.414 | 3.10296 | 3.10241
23_Vloer_Zwevende | 02 2e verdieping | 76020.9 | 237.197 | 236.162 | 7.11592 | 7.08485
23_Vloer_Zwevende | 03 3e tussenverdieping | 60158.8 | 104.646 | 103.504 | 3.13939 | 3.10511

# IfcSlab: Zwevende dekvloer 50, 23_Vloer_Zwevende
In: 00 Begane grond
Material: Zwevende dekvloer
Pset_SlabCommon - IsExternal: no; LoadBearing: yes
BaseQuantities - Width: 50 mm; Perimeter: 80279.9 mm; GrossArea: 340.078 m2; NetArea: 337.48 m2; GrossVolume: 17.0039 m3; NetVolume: 16.8741 m3

# IfcSlab: beton 250, 23_Vloer_beton
In: Kelder
Material: beton
Pset_SlabCommon - IsExternal: no; LoadBearing: yes
BaseQuantities - Width: 250 mm; Perimeter: 2825.22 mm; GrossArea: 0.498826 m2; NetArea: 0.498826 m2; GrossVolume: 0.124706 m3; NetVolume: 0.124706 m3

# IfcSlab: beton 30 (6)
Material: beton
BaseQuantities - Width: 30 mm
Pset_SlabCommon - IsExternal: no; LoadBearing: yes
Name | In | Perimeter (mm) | GrossArea (m2) | NetArea (m2) | GrossVolume (m3) | NetVolume (m3)
23_Vloer_beton | 00 Begane grond | 63332.6 | 227.399 | 223.197 | 6.82197 | 6.69592
23_Vloer_beton | 00 Begane grond | 4530 | 0.53865 | 0.53865 | 0.0161595 | 0.0161595
23_Vloer_beton | 00 Begane grond | 23858 | 30.9978 | 30.9978 | 0.929934 | 0.929934
23_Vloer_beton | 00 Begane grond | 89700 | 473.487 | 473.052 | 14.2046 | 14.1916
23_Vloer_beton | 00 Begane grond | 89160 | 473.497 | 473.062 | 14.2049 | 14.1919
23_Vloer_beton | 02 2e tussenverdieping | 61992.6 | 220.024 | 200.454 | 6.60073 | 6.01361

# IfcSlab: beton_gewapend_prefab vloer 220 (2)
In: 04 4e verdieping
Material: beton_gewapend_prefab vloer
Pset_SlabCommon - IsExternal: no; LoadBearing: yes
BaseQuantities - Width: 220 mm
Name | Perimeter (mm) | GrossArea (m2) = NetArea (m2) | GrossVolume (m3) = NetVolume (m3)
27_Vloer_beton_gewapend_prefab | 23313.8 | 30.808 | 6.77776
27_Vloer_beton_gewapend_prefab | 20713 | 20.916 | 4.60152

# IfcSlab: beton_gewapend_prefab vloer 30, 23_Vloer_beton_gewapend_prefab
In: 00 Begane grond
Material: beton_gewapend_prefab vloer
Pset_SlabCommon - IsExternal: no; LoadBearing: yes
BaseQuantities - Width: 30 mm; Perimeter: 41928.2 mm; GrossArea: 16.1313 m2; NetArea: 16.1313 m2; GrossVolume: 0.483938 m3; NetVolume: 0.483938 m3

# IfcSlab: beton_gewapend_vloer C 120 (7)
Material: beton_gewapend_vloer C
Pset_SlabCommon - IsExternal: no; LoadBearing: yes
BaseQuantities - Width: 120 mm
Name | In | Perimeter (mm) | GrossArea (m2) | NetArea (m2) | GrossVolume (m3) | NetVolume (m3)
23_Vloer_beton_gewapend_vloer | 00 Begane grond | 65132.6 | 245.992 | 245.992 | 29.5191 | 29.5191
23_Vloer_beton_gewapend_vloer | 00 Begane grond | 858 | 0.0459 | 0.0459 | 0.005508 | 0.005508
23_Vloer_beton_gewapend_vloer | 00 Begane grond | 778 | 0.0369 | 0.0369 | 0.004428 | 0.004428
23_Vloer_beton_gewapend_vloer | 01 1e verdieping | 121938 | 808.444 | 796.355 | 97.0132 | 95.5626
23_Vloer_beton_gewapend_vloer | 02 2e tussenverdieping | 63748.2 | 238.053 | 238.053 | 28.5664 | 28.5664
23_Vloer_beton_gewapend_vloer | 02 2e verdieping | 121760 | 806.939 | 795.691 | 96.8326 | 95.4829
23_Vloer_beton_gewapend_vloer | 02 2e verdieping | 23749.9 | 32.6374 | 32.6374 | 3.91649 | 3.91649

# IfcSlab: beton_gewapend_vloer C 150 (9)
Material: beton_gewapend_vloer C
Pset_SlabCommon - IsExternal: no; LoadBearing: yes
BaseQuantities - Width: 150 mm
Name | In | Perimeter (mm) | GrossArea (m2) | NetArea (m2) | GrossVolume (m3) | NetVolume (m3)
23_Vloer_beton_gewapend_vloer | 00 Begane grond | 174760 | 1298.44 | 1260.29 | 194.766 | 189.043
23_Vloer_beton_gewapend_vloer | 01 1e tussenverdieping | 3746.8 | 0.80808 | 0.80808 | 0.121212 | 0.121212
23_Vloer_beton_gewapend_vloer | 01 1e verdieping | 112920 | 569.745 | 567.825 | 85.4618 | 85.1738
27_Vloer_beton_gewapend_vloer | 01 1e verdieping | 10100 | 3.13566 | 3.13566 | 0.470349 | 0.470349
23_Vloer_beton_gewapend_vloer | 02 2e tussenverdieping | 3668 | 0.7608 | 0.7608 | 0.11412 | 0.11412
23_Vloer_beton_gewapend_vloer | 02 2e tussenverdieping | 19990.6 | 24.2148 | 24.2148 | 3.63222 | 3.63222
23_Vloer_beton_gewapend_vloer | 03 3e tussenverdieping | 52119.9 | 120.61 | 107.508 | 18.0915 | 16.1263
23_Vloer_beton_gewapend_vloer | 03 3e tussenverdieping | 3670 | 0.762 | 0.762 | 0.1143 | 0.1143
27_Vloer_beton_gewapend_vloer | 04 4e verdieping | 158012 | 1200.06 | 1189.25 | 180.009 | 178.387

# IfcSlab: beton_gewapend_vloer C 180, 23_Vloer_beton_gewapend_vloer
In: 01 1e tussenverdieping
Material: beton_gewapend_vloer C
Pset_SlabCommon - IsExternal: no; LoadBearing: yes
BaseQuantities - Width: 180 mm; Perimeter: 52565.5 mm; GrossArea: 126.339 m2; NetArea: 123.424 m2; GrossVolume: 22.7698 m3; NetVolume: 22.2451 m3

# IfcSlab: beton_gewapend_vloer C 200 (5)
Material: beton_gewapend_vloer C
Pset_SlabCommon - IsExternal: no; LoadBearing: yes
BaseQuantities - Width: 200 mm
Name | In | Perimeter (mm) | GrossArea (m2) | NetArea (m2) | GrossVolume (m3) | NetVolume (m3)
23_Vloer_beton_gewapend_vloer | Kelder | 7580 | 2.257 | 2.257 | 0.4514 | 0.4514
23_Vloer_beton_gewapend_vloer | 00 Begane grond | 29977.5 | 54.7121 | 54.7121 | 10.9424 | 10.9424
23_Vloer_beton_gewapend_vloer | 00 Begane grond | 22227.8 | 29.7093 | 29.7093 | 5.94185 | 5.94185
23_Vloer_beton_gewapend_vloer | 02 2e tussenverdieping | 28470 | 49.5405 | 47.738 | 9.95622 | 9.59572
23_Vloer_beton_gewapend_vloer | 02 2e tussenverdieping | 27420 | 44.9269 | 43.8642 | 8.98538 | 8.77285

# IfcSlab: beton_gewapend_vloer C 220, 27_Vloer_beton_gewapend_vloer
In: 01 1e verdieping
Material: beton_gewapend_vloer C
BaseQuantities - Width: 220 mm; Perimeter: 29870 mm; GrossArea: 2.947 m2; NetArea: 2.947 m2; GrossVolume: 0.64834 m3; NetVolume: 0.64834 m3
Pset_SlabCommon - IsExternal: no; LoadBearing: yes

# IfcSlab: beton_gewapend_vloer C 250 (4)
Material: beton_gewapend_vloer C
Pset_SlabCommon - IsExternal: no; LoadBearing: yes
BaseQuantities - Width: 250 mm
Name | In | Perimeter (mm) | GrossArea (m2) | NetArea (m2) | GrossVolume (m3) | NetVolume (m3)
23_Vloer_beton_gewapend_vloer | Kelder | 50240 | 142.151 | 141.661 | 35.5378 | 35.4153
23_Vloer_beton_gewapend_vloer | -1 Fundering | 10400 | 6.67 | 6.67 | 1.6675 | 1.6675
23_Vloer_beton_gewapend_vloer | 00 Begane grond | 23065.9 | 25.0553 | 15.1713 | 8.01845 | 5.54744
23_Vloer_beton_gewapend_vloer | 00 Begane grond | 26727.6 | 44.4931 | 44.4931 | 11.1233 | 11.1233

# IfcSlab: beton_gewapend_vloer C 300, 23_Vloer_beton_gewapend_vloer
In: -1 Fundering
Material: beton_gewapend_vloer C
Pset_SlabCommon - IsExternal: no; LoadBearing: yes
BaseQuantities - Width: 300 mm; Perimeter: 22965.9 mm; GrossArea: 24.4897 m2; NetArea: 23.9897 m2; GrossVolume: 7.4719 m3; NetVolume: 7.3219 m3

# IfcSlab: beton_gewapend_vloer C 50, 23_Vloer_beton_gewapend_vloer
In: 02 2e tussenverdieping
Material: beton_gewapend_vloer C
BaseQuantities - Width: 50 mm; Perimeter: 41458.2 mm; GrossArea: 15.9433 m2; NetArea: 15.9433 m2; GrossVolume: 0.797164 m3; NetVolume: 0.797164 m3
Pset_SlabCommon - IsExternal: no; LoadBearing: yes

# IfcSlab: betonvloer-kurk 150 150, 27_Vloer_betonvloer-kurk
In: 01 1e verdieping
BaseQuantities - Width: 150 mm; Perimeter: 71408.2 mm; GrossArea: 162.283 m2; NetArea: 161.952 m2; GrossVolume: 24.3623 m3; NetVolume: 24.3126 m3
Pset_SlabCommon - IsExternal: no; LoadBearing: yes

# IfcSlab: isolatie_xps_zwevende_dekvloer 30 (4)
Material: isolatie_xps_zwevende_dekvloer
Pset_SlabCommon - IsExternal: no; LoadBearing: yes
BaseQuantities - Width: 30 mm
Name | In | Perimeter (mm) | GrossArea (m2) | NetArea (m2) | GrossVolume (m3) | NetVolume (m3)
23_Vloer_isolatie_xps_zwevende_dekvloer | 01 1e verdieping | 96819 | 281.34 | 280.993 | 8.44021 | 8.42979
23_Vloer_isolatie_xps_zwevende_dekvloer | 01 1e verdieping | 75672.1 | 235.89 | 228.787 | 7.0767 | 6.86361
23_Vloer_isolatie_xps_zwevende_dekvloer | 01 1e verdieping | 140938 | 434.159 | 433.83 | 13.0248 | 13.0149
23_Vloer_isolatie_xps_zwevende_dekvloer | 02 2e verdieping | 96148.3 | 285.269 | 280.431 | 8.55806 | 8.41294

# IfcSlab: vloer gasbetonplaat 100 100, 27_Vloer_vloer
In: 02 2e verdieping
Material: cellenbeton
Pset_SlabCommon - IsExternal: no; LoadBearing: yes
BaseQuantities - Width: 100 mm; Perimeter: 96948.8 mm; GrossArea: 524.284 m2; NetArea: 493.313 m2; GrossVolume: 52.7146 m3; NetVolume: 49.6176 m3

# IfcSlab: zandcementdeklvoer 30 (3)
Material: zandcementdeklvoer
Pset_SlabCommon - IsExternal: no; LoadBearing: yes
BaseQuantities - Width: 30 mm
Name | In | Perimeter (mm) | GrossArea (m2) | NetArea (m2) | GrossVolume (m3) | NetVolume (m3)
23_Vloer_zandcementdeklvoer | 01 1e verdieping | 49463.2 | 78.2155 | 77.353 | 2.34647 | 2.32059
23_Vloer_zandcementdeklvoer | 01 1e verdieping | 118207 | 235.341 | 235.341 | 7.06022 | 7.06022
23_Vloer_zandcementdeklvoer | 02 2e verdieping | 110699 | 217.513 | 216.166 | 6.52541 | 6.48501

# IfcSlab: zandcementdeklvoer 50, 23_Vloer_zandcementdeklvoer
In: 00 Begane grond
Material: zandcementdeklvoer
BaseQuantities - Width: 50 mm; Perimeter: 219403 mm; GrossArea: 1028.66 m2; NetArea: 974.703 m2; GrossVolume: 51.4329 m3; NetVolume: 48.7352 m3
Pset_SlabCommon - IsExternal: no; LoadBearing: yes

# IfcStair (11)
Pset_StairCommon - IsExternal: no
Name | In | Material | Length (mm) | Height (mm) | GrossVolume (m3) = NetVolume (m3)
24_Trap_ | Kelder | beton (2) | 5028.94 | 3730 | 1.29912
24_Trap_ | 00 Begane grond | beton (3), natuursteen AFW (48) | 11200 | 4250 | 7.4093
24_Trap_ | 00 Begane grond | beton (3) | 11270 | 4250 | 4.01947
24_Trap_ | 00 Begane grond | beton (2) | 9113.96 | 4250 | 3.89964
24_Trap_ | 01 1e tussenverdieping | staal (8) | 1440 | 1062 | 0.131023
24_Trap_ | 01 1e verdieping | beton (3), natuursteen AFW (48) | 11200 | 4250 | 7.4093
24_Trap_ | 01 1e verdieping | beton (3) | 9587.99 | 4250 | 3.46912
24_Trap_ | 01 1e verdieping | staal (14) | 2880 | 2095 | 0.260455
24_Trap_ | 02 2e tussenverdieping | staal (14) | 2880 | 2155 | 0.261508
24_Trap_ | 02 2e verdieping | beton (2) | 6604.98 | 1096 | 2.24069
24_Trap_ | 02 2e verdieping | staal (11) | 2903.04 | 1063 | 0.241135

# IfcWall: ALG - ALGEMEEN 100, 22_Binnenwand_ALG
In: 00 Begane grond
Material: ALG - ALGEMEEN
Pset_WallCommon - IsExternal: no; LoadBearing: no
BaseQuantities - Length: 3150.02 mm; Height: 4250 mm; Width: 100 mm; GrossFootprintArea: 0.259002 m2; NetFootprintArea: 0.259002 m2; GrossSideArea: 9.32408 m2; NetSideArea: 9.32408 m2; GrossVolume: 0.932408 m3; NetVolume: 0.932408 m3

# IfcWall: ALG - BINNENWAND 100 (4)
Material: ALG - BINNENWAND
Pset_WallCommon - IsExternal: no; LoadBearing: no
BaseQuantities - Length: 65 mm; Width: 100 mm; GrossFootprintArea: 0.0065 m2; NetFootprintArea: 0.0065 m2
Name | In | Height (mm) | GrossSideArea (m2) = NetSideArea (m2) | GrossVolume (m3) = NetVolume (m3)
22_Binnenwand_ALG | 01 1e verdieping | 4250 | 0.26845 | 0.026845
3 x 22_Binnenwand_ALG | 02 2e verdieping | 4050 | 0.26325 | 0.026325

# IfcWall: ALG - BINNENWAND 110 (3)
In: 00 Begane grond
Material: ALG - BINNENWAND
Pset_WallCommon - LoadBearing: no
BaseQuantities - Width: 110 mm
Name | IsExternal | Length (mm) | Height (mm) | GrossFootprintArea (m2) = NetFootprintArea (m2) | GrossSideArea (m2) = NetSideArea (m2) | GrossVolume (m3) = NetVolume (m3)
21_Binnenwand_ALG | yes | 8555 | 4250 | 0.9471 | 32.5345 | 3.57713
21_Binnenwand_ALG | yes | 8505 | 4250 | 0.8261 | 23.9404 | 2.63344
22_Binnenwand_ALG | no | 400 | 4200 | 0.0319 | 1.17583 | 0.130647

# IfcWall: ALG - BINNENWAND 120, 22_Binnenwand_ALG
In: 00 Begane grond
Material: ALG - BINNENWAND
Pset_WallCommon - IsExternal: no; LoadBearing: no
BaseQuantities - Length: 4000.01 mm; Height: 4250 mm; Width: 120 mm; GrossFootprintArea: 0.486002 m2; NetFootprintArea: 0.486002 m2; GrossSideArea: 16.5146 m2; NetSideArea: 16.5146 m2; GrossVolume: 1.98175 m3; NetVolume: 1.98175 m3

# IfcWall: ALG - BINNENWAND 200, 22_Binnenwand_ALG
In: 01 1e verdieping
Material: ALG - BINNENWAND
BaseQuantities - Length: 324.089 mm; Height: 4250 mm; Width: 200 mm; GrossFootprintArea: 0.0648179 m2; NetFootprintArea: 0.0648179 m2; GrossSideArea: 1.33849 m2; NetSideArea: 1.33849 m2; GrossVolume: 0.267698 m3; NetVolume: 0.267698 m3
Pset_WallCommon - IsExternal: no; LoadBearing: no

# IfcWall: ALG - BUITENAFWERKING 10 (75)
Material: ALG - BUITENAFWERKING
Pset_WallCommon - IsExternal: no; LoadBearing: no
BaseQuantities - Width: 10 mm
Name | In | Length (mm) | Height (mm) | GrossFootprintArea (m2) = NetFootprintArea (m2) | GrossSideArea (m2) = NetSideArea (m2) | GrossVolume (m3) = NetVolume (m3)
42_Binnenwand_ALG | 01 1e verdieping | 67 | 999 | 0.000670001 | 0.0668325 | 0.000667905
10 x 42_Binnenwand_ALG | 01 1e verdieping | 67 | 929 | 0.00067 | 0.062243 | 0.00062243
7 x 42_Binnenwand_ALG | 01 1e verdieping | 67 | 996 | 0.00067 | 0.066732 | 0.00066732
2 x 42_Binnenwand_ALG | 01 1e verdieping | 3514 | 67 | 0.03514 | 0.235438 | 0.00235438
2 x 42_Binnenwand_ALG | 01 1e verdieping | 67 | 999 | 0.00067 | 0.066933 | 0.00066933
42_Binnenwand_ALG | 01 1e verdieping | 3649.93 | 1200 | 0.0364993 | 4.37992 | 0.0437992
3 x 42_Binnenwand_ALG | 01 1e verdieping | 67 | 996 | 0.000670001 | 0.0667321 | 0.000667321
42_Binnenwand_ALG | 01 1e verdieping | 67 | 899 | 0.00000134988 | 0.000121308 | 0.00000121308
4 x 42_Binnenwand_ALG | 01 1e verdieping | 67 | 912 | 0.00067 | 0.061104 | 0.00061104
42_Binnenwand_ALG | 01 1e verdieping | 1766.13 | 1200 | 0.0176613 | 2.11936 | 0.0211936
2 x 42_Binnenwand_ALG | 01 1e verdieping | 2548.07 | 84 | 0.0254807 | 0.214038 | 0.00214038
42_Binnenwand_ALG | 01 1e verdieping | 782.664 | 1200 | 0.00782664 | 0.939197 | 0.00939197
2 x 42_Binnenwand_ALG | 01 1e verdieping | 1698.27 | 67 | 0.0169827 | 0.113784 | 0.00113784
2 x 42_Binnenwand_ALG | 01 1e verdieping | 714.73 | 67 | 0.0071473 | 0.0478869 | 0.000478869
42_Binnenwand_ALG | 01 1e verdieping | 837.657 | 1200 | 0.00837657 | 1.00519 | 0.0100519
42_Binnenwand_ALG | 01 1e verdieping | 896.484 | 1200 | 0.00896484 | 1.07578 | 0.0107578
42_Binnenwand_ALG | 01 1e verdieping | 853.564 | 1200 | 0.00853564 | 1.02428 | 0.0102428
42_Binnenwand_ALG | 01 1e verdieping | 835.6 | 1292.72 | 0.008356 | 1.0802 | 0.010802
42_Binnenwand_ALG | 01 1e verdieping | 850.583 | 1292.72 | 0.00850583 | 1.09957 | 0.0109957
42_Binnenwand_ALG | 01 1e verdieping | 907.6 | 1292.72 | 0.009076 | 1.17328 | 0.0117328
42_Binnenwand_ALG | 01 1e verdieping | 898 | 1292.72 | 0.00898 | 1.16087 | 0.0116087
5 x 42_Binnenwand_ALG | 02 2e verdieping | 67 | 0 | 0 | 0.000335 | 0
2 x 42_Binnenwand_ALG | 02 2e verdieping | 3514 | 0 | 0 | 0.01757 | 0
42_Binnenwand_ALG | 02 2e verdieping | 67 | 1002 | 0.00067 | 0.066933 | 0.000669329
2 x 42_Binnenwand_ALG | 02 2e verdieping | 907.789 | 1292 | 0.00907789 | 1.17286 | 0.0117286
3 x 42_Binnenwand_ALG | 02 2e verdieping | 850 | 1292 | 0.0085 | 1.0982 | 0.010982
42_Binnenwand_ALG | 02 2e verdieping | 3645.59 | 1292 | 0.0364559 | 4.7101 | 0.047101
42_Binnenwand_ALG | 02 2e verdieping | 3649.93 | 1292 | 0.0364993 | 4.71571 | 0.0471571
42_Binnenwand_ALG | 02 2e verdieping | 874.716 | 1292 | 0.00874716 | 1.13013 | 0.0113013
42_Binnenwand_ALG | 02 2e verdieping | 919.815 | 1292 | 0.00919815 | 1.1884 | 0.011884
42_Binnenwand_ALG | 02 2e verdieping | 1775.45 | 1292 | 0.0177545 | 2.29389 | 0.0229389
42_Binnenwand_ALG | 02 2e verdieping | 903.506 | 1292 | 0.00903506 | 1.16733 | 0.0116733
42_Binnenwand_ALG | 02 2e verdieping | 912.592 | 1292 | 0.00912592 | 1.17907 | 0.0117907
42_Binnenwand_ALG | 02 2e verdieping | 1680.54 | 1292 | 0.0168054 | 2.17126 | 0.0217126
2 x 42_Binnenwand_ALG | 02 2e verdieping | 3646 | 1292 | 0.03646 | 4.71063 | 0.0471063
42_Binnenwand_ALG | 02 2e verdieping | 845.543 | 1292 | 0.00845543 | 1.09244 | 0.0109244
42_Binnenwand_ALG | 02 2e verdieping | 900.411 | 1292 | 0.00900411 | 1.16333 | 0.0116333
42_Binnenwand_ALG | 02 2e verdieping | 872.753 | 1292 | 0.00872753 | 1.1276 | 0.011276
42_Binnenwand_ALG | 02 2e verdieping | 1766.13 | 1292 | 0.0176613 | 2.28185 | 0.0228185
42_Binnenwand_ALG | 02 2e verdieping | 2612 | 1292 | 0.02612 | 3.3747 | 0.033747
42_Binnenwand_ALG | 02 2e verdieping | 850.303 | 1292 | 0.00850303 | 1.09859 | 0.0109859

# IfcWall: ALG - BUITENAFWERKING 15 (3)
In: 01 1e verdieping
Material: ALG - BUITENAFWERKING
BaseQuantities - Height: 100 mm; Width: 15 mm
Pset_WallCommon - IsExternal: no; LoadBearing: no
Name | Length (mm) | GrossFootprintArea (m2) = NetFootprintArea (m2) | GrossSideArea (m2) = NetSideArea (m2) | GrossVolume (m3) = NetVolume (m3)
42_Binnenwand_ALG | 1766.27 | 0.0264941 | 0.173978 | 0.00258533
42_Binnenwand_ALG | 782.664 | 0.01174 | 0.0770924 | 0.00114561
42_Binnenwand_ALG | 2616 | 0.03924 | 0.257676 | 0.00382911

# IfcWall: ALG - BUITENAFWERKING 20, 42_Binnenwand_ALG
In: 01 1e verdieping
Material: ALG - BUITENAFWERKING
BaseQuantities - Length: 3649.93 mm; Height: 97 mm; Width: 20 mm; GrossFootprintArea: 0.0729987 m2; NetFootprintArea: 0.0729987 m2; GrossSideArea: 0.354044 m2; NetSideArea: 0.354044 m2; GrossVolume: 0.00708087 m3; NetVolume: 0.00708087 m3
Pset_WallCommon - IsExternal: no; LoadBearing: no

# IfcWall: ALG - BUITENBLAD 200 (4)
Material: ALG - BUITENBLAD
Pset_WallCommon - IsExternal: yes; LoadBearing: no
BaseQuantities - Width: 200 mm
Name | In | Length (mm) | Height (mm) | GrossFootprintArea (m2) = NetFootprintArea (m2) | GrossSideArea (m2) = NetSideArea (m2) | GrossVolume (m3) = NetVolume (m3)
21_Binnenwand_ALG | Kelder | 2850 | 1730 | 0.57 | 4.9305 | 0.9861
21_Binnenwand_ALG | Kelder | 750 | 1730 | 0.17 | 1.4705 | 0.2941
21_Binnenwand_ALG | Kelder | 750 | 1730 | 0.13 | 1.1245 | 0.2249
21_Binnenwand_ALG | 00 Begane grond | 125 | 2997 | 0.025 | 0.374625 | 0.074925

# IfcWall: ALG - BUITENBLAD 404, 21_Binnenwand_ALG
In: 01 1e verdieping
Material: ALG - BUITENBLAD
Pset_WallCommon - IsExternal: yes; LoadBearing: no
BaseQuantities - Length: 3450.23 mm; Height: 4066.64 mm; Width: 403.5 mm; GrossFootprintArea: 0.0000945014 m2; NetFootprintArea: 0.0000945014 m2; GrossSideArea: 14.0309 m2; NetSideArea: 3.69121 m2; GrossVolume: 5.66145 m3; NetVolume: 1.4894 m3

# IfcWall: ALG - ISOLATIE 85 (57)
In: -1 Fundering
Material: ALG - ISOLATIE
BaseQuantities - Width: 85 mm
Pset_WallCommon - IsExternal: yes; LoadBearing: no
Name | Length (mm) | Height (mm) | GrossFootprintArea (m2) = NetFootprintArea (m2) | GrossSideArea (m2) = NetSideArea (m2) | GrossVolume (m3) = NetVolume (m3)
21_Binnenwand_ALG | 442.492 | 1150 | 0.0412243 | 0.409241 | 0.0347855
21_Binnenwand_ALG | 2784.99 | 900 | 0.236724 | 2.41573 | 0.205337
12 x 21_Binnenwand_ALG | 300 | 900 | 0.0255 | 0.27 | 0.02295
21_Binnenwand_ALG | 1815 | 900 | 0.154275 | 1.6335 | 0.138847
4 x 21_Binnenwand_ALG | 685 | 900 | 0.058225 | 0.6165 | 0.0524025
21_Binnenwand_ALG | 2965 | 900 | 0.252025 | 2.6685 | 0.226822
2 x 21_Binnenwand_ALG | 3015 | 900 | 0.256275 | 2.7135 | 0.230647
21_Binnenwand_ALG | 19385 | 500 | 1.64772 | 9.6925 | 0.823863
21_Binnenwand_ALG | 860 | 900 | 0.0731 | 0.774 | 0.06579
21_Binnenwand_ALG | 860 | 900 | 0.080325 | 0.808 | 0.06868
21_Binnenwand_ALG | 2965 | 900 | 0.252025 | 2.6685 | 0.226823
21_Binnenwand_ALG | 2785 | 1150 | 0.236725 | 2.39215 | 0.203333
21_Binnenwand_ALG | 1815 | 900 | 0.154275 | 1.6335 | 0.138848
21_Binnenwand_ALG | 400 | 1150 | 0.034 | 0.377287 | 0.0320694
21_Binnenwand_ALG | 9741.62 | 1150 | 0.824425 | 9.46947 | 0.804905
21_Binnenwand_ALG | 44856.7 | 900 | 3.81643 | 39.2189 | 3.33361
21_Binnenwand_ALG | 817.287 | 1150 | 0.0694694 | 0.874497 | 0.0743323
21_Binnenwand_ALG | 21300.4 | 750 | 1.81053 | 15.1087 | 1.23094
21_Binnenwand_ALG | 685 | 750 | 0.06545 | 0.5159 | 0.0438515
21_Binnenwand_ALG | 5335.77 | 920 | 0.461192 | 4.95178 | 0.420901
3 x 21_Binnenwand_ALG | 269.354 | 920 | 0.0228951 | 0.247806 | 0.0210635
2 x 21_Binnenwand_ALG | 652.533 | 920 | 0.0554653 | 0.60033 | 0.0510281
21_Binnenwand_ALG | 3210.77 | 920 | 0.272489 | 2.9493 | 0.25069
21_Binnenwand_ALG | 3210.77 | 920 | 0.273342 | 2.95853 | 0.251475
2 x 21_Binnenwand_ALG | 195.918 | 920 | 0.016653 | 0.180244 | 0.0153207
21_Binnenwand_ALG | 295.62 | 920 | 0.0210888 | 0.228256 | 0.0194017
21_Binnenwand_ALG | 685 | 1050 | 0.058225 | 0.6527 | 0.0554795
21_Binnenwand_ALG | 125 | 1150 | 0.010625 | 0.13375 | 0.0113687
21_Binnenwand_ALG | 238.418 | 620 | 0.0202655 | 0.147819 | 0.0125646
21_Binnenwand_ALG | 797.777 | 1150 | 0.067811 | 0.853621 | 0.0725578
21_Binnenwand_ALG | 124.974 | 1150 | 0.00339775 | 0.0427717 | 0.00363559
21_Binnenwand_ALG | 20065 | 670 | 1.68677 | 13.1923 | 1.13014
21_Binnenwand_ALG | 75 | 1050 | 0.0099875 | 0.073 | 0.00618625
21_Binnenwand_ALG | 75 | 670 | 0.006375 | 0.0495 | 0.0042
21_Binnenwand_ALG | 961.582 | 780 | 0.0817345 | 0.676149 | 0.0574727
21_Binnenwand_ALG | 7194.54 | 920 | 0.618761 | 6.64448 | 0.564781
21_Binnenwand_ALG | 12125 | 1150 | 1.03062 | 13.4587 | 1.15104
21_Binnenwand_ALG | 3290.67 | 270 | 0.279707 | 0.888482 | 0.075521

# IfcWall: Gevelbeplating golf 18 x 2900 (4)
In: 04 4e verdieping
Pset_WallCommon - IsExternal: yes; LoadBearing: no
BaseQuantities - Height: 2900 mm; Width: 18.0001 mm
Name | Length (mm) | GrossFootprintArea (m2) = NetFootprintArea (m2) | GrossSideArea (m2) | NetSideArea (m2) | GrossVolume (m3) | NetVolume (m3)
47_Binnenwand_Gevelbeplating | 42233.6 | 0.0405183 | 137.094 | 133.013 | 0.117752 | 0.114248
47_Binnenwand_Gevelbeplating | 42233.6 | 0.0412199 | 136.824 | 134.223 | 0.117514 | 0.115281
47_Binnenwand_Gevelbeplating | 6413.62 | 0.00643398 | 20.8342 | 20.8342 | 0.0178946 | 0.0178946
47_Binnenwand_Gevelbeplating | 6413.62 | 0.0064326 | 20.8311 | 20.8311 | 0.0178919 | 0.0178919

# IfcWall: HSB_285 gevelbeplating 420 (17)
Pset_WallCommon - IsExternal: yes; LoadBearing: no
BaseQuantities - Width: 420 mm
Name | In | Length (mm) | Height (mm) | GrossFootprintArea (m2) = NetFootprintArea (m2) | GrossSideArea (m2) | NetSideArea (m2) | GrossVolume (m3) | NetVolume (m3)
21_Binnenwand_HSB_285 | 00 Begane grond | 20214.1 | 6345 | 8.47936 | 116.872 | 51.1356 | 52.1287 | 24.2485
21_Binnenwand_HSB_285 | 00 Begane grond | 36077 | 4250 | 14.4658 | 133.648 | 50.5593 | 58.3769 | 23.1232
21_Binnenwand_HSB_285 | 00 Begane grond | 39930 | 4100 | 16.7688 | 151.45 | 46.4797 | 67.7685 | 23.6739
21_Binnenwand_HSB_285 | 00 Begane grond | 4272.43 | 3546.98 | 1.75636 | 13.9958 | 0.103533 | 6.22835 | 0.393281
21_Binnenwand_HSB_285 | 00 Begane grond | 175 | 4250 | 0.0735 | 0.74375 | 0.74375 | 0.312375 | 0.312375
21_Binnenwand_HSB_285 | 01 1e verdieping | 16000 | 4070 | 4.34047 | 60.2071 | 19.7424 | 26.3528 | 9.35757
21_Binnenwand_HSB_285 | 01 1e verdieping | 24090 | 4250 | 10.1689 | 91.4941 | 27.2362 | 39.723 | 12.7347
21_Binnenwand_HSB_285 | 01 1e verdieping | 14276.4 | 4250 | 5.99607 | 55.417 | 17.1777 | 24.6046 | 8.54411
21_Binnenwand_HSB_285 | 01 1e verdieping | 36317 | 4250 | 15.2531 | 137.554 | 54.466 | 60.4941 | 25.4836
21_Binnenwand_HSB_285 | 01 1e verdieping | 16386 | 4070 | 6.8386 | 62.0516 | 19.2164 | 26.7548 | 8.76402
21_Binnenwand_HSB_285 | 01 1e verdieping | 6296.81 | 4250 | 2.64274 | 26.1264 | 11.7436 | 11.2127 | 5.17191
21_Binnenwand_HSB_285 | 01 1e verdieping | 40065 | 4100 | 11.5003 | 152.031 | 44.7447 | 67.8492 | 22.7856
21_Binnenwand_HSB_285 | 01 1e verdieping | 175 | 4250 | 0.0735 | 0.74375 | 0.74375 | 0.312375 | 0.312375
21_Binnenwand_HSB_285 | 02 2e tussenverdieping | 20000 | 6425 | 2.25968 | 125.134 | 57.4358 | 53.2689 | 24.5572
21_Binnenwand_HSB_285 | 02 2e verdieping | 36317 | 4270 | 15.2531 | 150.461 | 66.8878 | 62.0223 | 26.9217
21_Binnenwand_HSB_285 | 02 2e verdieping | 40065 | 4050 | 11.4989 | 150.832 | 46.3828 | 67.0132 | 23.1412
21_Binnenwand_HSB_285 | 02 2e verdieping | 174.999 | 4270 | 0.0734998 | 0.747248 | 0.747248 | 0.313844 | 0.313844

# IfcWall: HSB_285 gevelbeplating Brise Soleil 398 (4)
Pset_WallCommon - IsExternal: yes; LoadBearing: no
BaseQuantities - Width: 397.5 mm
Name | In | Length (mm) | Height (mm) | GrossFootprintArea (m2) = NetFootprintArea (m2) | GrossSideArea (m2) | NetSideArea (m2) | GrossVolume (m3) | NetVolume (m3)
22_Binnenwand_HSB_285 | 00 Begane grond | 5980 | 3008 | 2.37705 | 17.9796 | 17.9796 | 7.14681 | 7.14681
21_Binnenwand_HSB_285 | 01 1e tussenverdieping | 5980 | 2977 | 2.37517 | 17.5704 | 5.08186 | 7.06734 | 2.03672
22_Binnenwand_HSB_285 | 01 1e tussenverdieping | 5982.82 | 2977 | 2.37817 | 17.8019 | 5.13502 | 7.07616 | 2.04108
21_Binnenwand_HSB_285 | 02 2e tussenverdieping | 5982.78 | 3218 | 2.37816 | 19.1629 | 19.1629 | 7.65066 | 7.65066

# IfcWall: HSB_285 zonder gevelbeplating 313 (9)
BaseQuantities - Width: 312.5 mm
Pset_WallCommon - IsExternal: yes; LoadBearing: no
Name | In | Length (mm) | Height (mm) | GrossFootprintArea (m2) = NetFootprintArea (m2) | GrossSideArea (m2) | NetSideArea (m2) | GrossVolume (m3) | NetVolume (m3)
22_Binnenwand_HSB_285 | 00 Begane grond | 5982.78 | 3008 | 1.86962 | 17.9883 | 5.32144 | 5.62033 | 1.66194
21_Binnenwand_HSB_285 | 00 Begane grond | 3850 | 4250 | 1.24906 | 16.6323 | 7.17535 | 5.29809 | 2.33573
21_Binnenwand_HSB_285 | 00 Begane grond | 22571 | 547.5 | 7.05344 | 11.7753 | 11.7753 | 3.67911 | 3.67911
21_Binnenwand_HSB_285 | 00 Begane grond | 4366.75 | 552.024 | 1.36196 | 2.08611 | 2.08611 | 0.616598 | 0.616598
21_Binnenwand_HSB_285 | 00 Begane grond | 13422.5 | 520 | 4.19452 | 6.46268 | 6.46268 | 2.01959 | 2.01959
21_Binnenwand_HSB_285 | 00 Begane grond | 22215 | 553.025 | 6.92648 | 12.1125 | 12.1125 | 3.8221 | 3.8221
22_Binnenwand_HSB_285 | 02 2e tussenverdieping | 5982.78 | 3038 | 1.86962 | 18.1757 | 18.1757 | 5.6799 | 5.6799
21_Binnenwand_HSB_285 | 03 3e tussenverdieping | 5980.5 | 2977 | 1.86891 | 17.795 | 5.12813 | 5.55884 | 1.60045
21_Binnenwand_HSB_285 | 03 3e tussenverdieping | 5980 | 2977 | 1.86875 | 17.7944 | 5.12758 | 5.56 | 1.60161

# IfcWall: MS-01 GF 150 ECO DGS/2.100.2.A 150 (147)
Pset_WallCommon - IsExternal: no; LoadBearing: no
BaseQuantities - Width: 150 mm
Name | In | Length (mm) | Height (mm) | GrossFootprintArea (m2) = NetFootprintArea (m2) | GrossSideArea (m2) | NetSideArea (m2) | GrossVolume (m3) | NetVolume (m3)
22_Binnenwand_MS-01 | 00 Begane grond | 8000 | 4070 | 1.19469 | 28.5533 | 28.5533 | 4.26574 | 4.26574
22_Binnenwand_MS-01 | 00 Begane grond | 1575 | 4067 | 0.241562 | 6.43094 | 6.43094 | 0.982435 | 0.982435
22_Binnenwand_MS-01 | 00 Begane grond | 7825 | 4070 | 0.725757 | 31.6723 | 24.3424 | 4.77558 | 3.67609
22_Binnenwand_MS-01 | 00 Begane grond | 4464.98 | 3570 | 0.669747 | 15.8373 | 15.8373 | 2.38843 | 2.38843
22_Binnenwand_MS-01 | 00 Begane grond | 3450 | 620 | 0.043125 | 12.4097 | 2.07 | 1.87009 | 0.319125
22_Binnenwand_MS-01 | 00 Begane grond | 886 | 4070 | 0.116494 | 3.09727 | 3.09727 | 0.47413 | 0.47413
22_Binnenwand_MS-01 | 00 Begane grond | 6157.78 | 2978 | 0.613467 | 18.3379 | 13.4429 | 2.75068 | 2.01644
22_Binnenwand_MS-01 | 00 Begane grond | 6157.78 | 2978 | 0.613467 | 18.3348 | 13.4429 | 2.75022 | 2.01644
22_Binnenwand_MS-01 | 00 Begane grond | 5896.5 | 4070 | 0.724063 | 23.9733 | 16.9704 | 3.57819 | 2.52776
22_Binnenwand_MS-01 | 00 Begane grond | 4000 | 3600 | 0.606824 | 13.8922 | 2.50533 | 2.17176 | 0.443613
22_Binnenwand_MS-01 | 00 Begane grond | 3452.5 | 2978 | 0.476556 | 10.2127 | 9.46891 | 1.54049 | 1.42891
22_Binnenwand_MS-01 | 00 Begane grond | 5540 | 2978 | 0.5259 | 16.4883 | 11.9439 | 2.47325 | 1.79158
22_Binnenwand_MS-01 | 00 Begane grond | 3950 | 2978 | 0.4425 | 11.7544 | 9.4574 | 1.76316 | 1.41861
22_Binnenwand_MS-01 | 00 Begane grond | 6107.78 | 2978 | 0.85125 | 16.8918 | 16.8918 | 2.53308 | 2.53308
22_Binnenwand_MS-01 | 00 Begane grond | 2119.97 | 2978 | 0.317995 | 6.31327 | 6.31327 | 0.94699 | 0.94699
22_Binnenwand_MS-01 | 00 Begane grond | 8000 | 4070 | 1.05553 | 32.5988 | 24.2679 | 4.92544 | 3.67581
22_Binnenwand_MS-01 | 00 Begane grond | 8000 | 3620 | 0.519988 | 27.7676 | 17.6323 | 4.14921 | 2.629
22_Binnenwand_MS-01 | 00 Begane grond | 7478.38 | 4100 | 0.962158 | 26.8194 | 24.3009 | 4.0229 | 3.64513
22_Binnenwand_MS-01 | 00 Begane grond | 3850 | 4097 | 0.2775 | 15.722 | 10.994 | 2.35829 | 1.64909
22_Binnenwand_MS-01 | 00 Begane grond | 7982.27 | 4100 | 1.19734 | 28.6311 | 28.6311 | 4.29466 | 4.29466
22_Binnenwand_MS-01 | 00 Begane grond | 125 | 4070 | 0.0134375 | 0.483312 | 0.483312 | 0.0546906 | 0.0546906
22_Binnenwand_MS-01 | 00 Begane grond | 5810.97 | 4070 | 0.861763 | 23.2469 | 15.5669 | 3.47226 | 2.32026
22_Binnenwand_MS-01 | 00 Begane grond | 3925 | 4070 | 0.0556251 | 15.8861 | 4.27275 | 2.39254 | 0.650537
22_Binnenwand_MS-01 | 00 Begane grond | 4893.96 | 3600 | 0.73722 | 17.2079 | 17.2079 | 2.52493 | 2.52493
22_Binnenwand_MS-01 | 00 Begane grond | 15665 | 4070 | 0.375922 | 62.7619 | 23.4466 | 9.39865 | 3.49907
22_Binnenwand_MS-01 | 00 Begane grond | 15999.9 | 4070 | 1.49634 | 64.1551 | 36.6991 | 9.67113 | 5.55127
22_Binnenwand_MS-01 | 00 Begane grond | 12026.8 | 4070 | 0.832231 | 48.2032 | 26.5011 | 7.24829 | 3.98619
22_Binnenwand_MS-01 | 00 Begane grond | 11000 | 4070 | 0.0540625 | 43.0621 | 11.4437 | 6.47489 | 1.73214
22_Binnenwand_MS-01 | 00 Begane grond | 7590 | 4100 | 1.1385 | 27.3091 | 27.3091 | 4.09636 | 4.09636
22_Binnenwand_MS-01 | 00 Begane grond | 4750 | 4100 | 0.729062 | 18.8537 | 18.8537 | 2.84393 | 2.84393
22_Binnenwand_MS-01 | 00 Begane grond | 4649.96 | 4100 | 0.708744 | 19.0672 | 19.0672 | 2.86008 | 2.86008
22_Binnenwand_MS-01 | 00 Begane grond | 3400 | 4100 | 0.3549 | 13.465 | 11.0175 | 2.01975 | 1.65263
22_Binnenwand_MS-01 | 00 Begane grond | 4649.96 | 4100 | 0.704994 | 18.7887 | 18.7887 | 2.8183 | 2.8183
22_Binnenwand_MS-01 | 00 Begane grond | 3241.7 | 2978 | 0.486255 | 9.65378 | 9.65378 | 1.44807 | 1.44807
22_Binnenwand_MS-01 | 00 Begane grond | 1320.21 | 4070 | 0.198032 | 4.87476 | 4.87476 | 0.731214 | 0.731214
22_Binnenwand_MS-01 | 00 Begane grond | 2068.03 | 4067 | 0.310203 | 8.32797 | 3.67561 | 1.2492 | 0.551341
22_Binnenwand_MS-01 | 00 Begane grond | 2356 | 3005 | 0.3534 | 6.98554 | 6.98554 | 1.04783 | 1.04783
22_Binnenwand_MS-01 | 00 Begane grond | 929.579 | 4070 | 0.150062 | 3.83355 | 3.83355 | 0.610689 | 0.610689
22_Binnenwand_MS-01 | 00 Begane grond | 619.25 | 4070 | 0.087575 | 2.483 | 2.483 | 0.356425 | 0.356425
22_Binnenwand_MS-01 | 00 Begane grond | 3825 | 4100 | 0.57375 | 14.5691 | 9.19999 | 2.11351 | 1.30814
22_Binnenwand_MS-01 | 00 Begane grond | 2499.95 | 4070 | 0.374992 | 10.1748 | 10.1748 | 1.52622 | 1.52622
22_Binnenwand_MS-01 | 00 Begane grond | 3512.46 | 4100 | 0.0228125 | 12.8645 | 4.62444 | 1.90359 | 0.66758
22_Binnenwand_MS-01 | 00 Begane grond | 2650 | 4100 | 0.398906 | 10.8396 | 6.20897 | 1.60813 | 0.92033
22_Binnenwand_MS-01 | 00 Begane grond | 1274.67 | 4070 | 0.0562 | 5.18789 | 3.05759 | 0.778184 | 0.458639
22_Binnenwand_MS-01 | 00 Begane grond | 20.0912 | 4067 | 0.00301368 | 0.081711 | 0.081711 | 0.0122567 | 0.0122567
22_Binnenwand_MS-01 | 00 Begane grond | 4050 | 2975 | 0.6075 | 12.0487 | 12.0487 | 1.80731 | 1.80731
22_Binnenwand_MS-01 | 00 Begane grond | 280 | 4070 | 0.0366875 | 1.1141 | 1.1141 | 0.149316 | 0.149316
22_Binnenwand_MS-01 | 00 Begane grond | 2340 | 3005 | 0.351 | 6.9381 | 6.9381 | 1.04072 | 1.04072
22_Binnenwand_MS-01 | 00 Begane grond | 95 | 4070 | 0.0195625 | 0.411341 | 0.411341 | 0.07954 | 0.07954
22_Binnenwand_MS-01 | 00 Begane grond | 3985 | 4250 | 0.05025 | 16.8207 | 5.87617 | 2.5236 | 0.881497
22_Binnenwand_MS-01 | 00 Begane grond | 4050 | 4070 | 0.6075 | 16.1075 | 16.1075 | 2.41613 | 2.41613
22_Binnenwand_MS-01 | 00 Begane grond | 4727.75 | 4250 | 0.709163 | 16.88 | 16.88 | 2.532 | 2.532
22_Binnenwand_MS-01 | 00 Begane grond | 1159 | 4067 | 0.0209375 | 4.68823 | 1.73919 | 0.685442 | 0.243085
22_Binnenwand_MS-01 | 00 Begane grond | 1042.46 | 4100 | 0.161681 | 4.29667 | 4.29667 | 0.662438 | 0.662438
22_Binnenwand_MS-01 | 00 Begane grond | 999.46 | 4070 | 0.149919 | 4.02482 | 4.02482 | 0.603724 | 0.603724
22_Binnenwand_MS-01 | 00 Begane grond | 6310.6 | 4100 | 0.379926 | 25.8411 | 16.8088 | 3.85769 | 2.50323
22_Binnenwand_MS-01 | 00 Begane grond | 1103.73 | 1000 | 0.165559 | 1.10373 | 1.10373 | 0.165559 | 0.165559
22_Binnenwand_MS-01 | 00 Begane grond | 1115.05 | 4070 | 0.167257 | 4.50637 | 4.50637 | 0.675303 | 0.675303
22_Binnenwand_MS-01 | 00 Begane grond | 75.0044 | 4067 | 0.00593933 | 0.188932 | 0.188932 | 0.022807 | 0.022807
22_Binnenwand_MS-01 | 00 Begane grond | 2424.51 | 4100 | 0.374927 | 9.76987 | 5.30932 | 1.45415 | 0.784829
22_Binnenwand_MS-01 | 01 1e tussenverdieping | 2714.99 | 3004 | 0.407249 | 8.10154 | 8.10154 | 1.22202 | 1.22202
22_Binnenwand_MS-01 | 01 1e tussenverdieping | 6022.78 | 3007 | 0.531677 | 17.8588 | 11.5344 | 2.69055 | 1.7419
22_Binnenwand_MS-01 | 01 1e tussenverdieping | 3638.41 | 2927 | 0.149783 | 10.6443 | 4.31594 | 1.60969 | 0.660126
22_Binnenwand_MS-01 | 01 1e tussenverdieping | 6022.78 | 2977 | 0.223917 | 17.9223 | 7.20658 | 2.68893 | 1.08104
22_Binnenwand_MS-01 | 01 1e tussenverdieping | 4150 | 3127 | 0.357301 | 13.0024 | 8.11056 | 1.9499 | 1.21658
22_Binnenwand_MS-01 | 01 1e tussenverdieping | 3758.8 | 2927 | 0.510687 | 9.91099 | 9.91099 | 1.47477 | 1.47477
22_Binnenwand_MS-01 | 01 1e verdieping | 7971 | 4100 | 1.19564 | 32.669 | 32.669 | 4.90211 | 4.90211
22_Binnenwand_MS-01 | 01 1e verdieping | 7925 | 4100 | 1.18875 | 32.4925 | 32.4925 | 4.87387 | 4.87387
22_Binnenwand_MS-01 | 01 1e verdieping | 3450 | 580 | 0.5175 | 12.3406 | 2.001 | 1.8511 | 0.30015
22_Binnenwand_MS-01 | 01 1e verdieping | 8042 | 4100 | 1.2063 | 29.129 | 29.129 | 4.36935 | 4.36935
22_Binnenwand_MS-01 | 01 1e verdieping | 8334.55 | 4250 | 0.722239 | 34.1906 | 25.9061 | 5.11679 | 3.87411
22_Binnenwand_MS-01 | 01 1e verdieping | 7880 | 4050 | 1.182 | 28.47 | 28.47 | 4.2705 | 4.2705
22_Binnenwand_MS-01 | 01 1e verdieping | 7923 | 4100 | 1.18845 | 32.4843 | 32.4843 | 4.87264 | 4.87264
22_Binnenwand_MS-01 | 01 1e verdieping | 7998.79 | 4100 | 1.19982 | 28.9406 | 28.9406 | 4.3427 | 4.3427
22_Binnenwand_MS-01 | 01 1e verdieping | 1850.01 | 4050 | 0.299199 | 7.7905 | 7.7905 | 1.21086 | 1.21086
22_Binnenwand_MS-01 | 01 1e verdieping | 3975 | 3570 | 0.59625 | 14.1788 | 14.1788 | 2.12682 | 2.12682
22_Binnenwand_MS-01 | 01 1e verdieping | 7995.39 | 4100 | 1.19931 | 32.7811 | 32.7811 | 4.91717 | 4.91717
22_Binnenwand_MS-01 | 01 1e verdieping | 8895.94 | 4250 | 0.0225 | 36.2287 | 13.1135 | 5.16483 | 1.69755
22_Binnenwand_MS-01 | 01 1e verdieping | 7997.86 | 4100 | 1.19968 | 32.7912 | 32.7912 | 4.91869 | 4.91869
22_Binnenwand_MS-01 | 01 1e verdieping | 6750 | 997 | 1.0125 | 6.72975 | 6.72975 | 1.00946 | 1.00946
22_Binnenwand_MS-01 | 01 1e verdieping | 5675 | 4100 | 0.8475 | 23.106 | 23.106 | 3.4659 | 3.4659
22_Binnenwand_MS-01 | 01 1e verdieping | 28000 | 4100 | 2.2938 | 113.794 | 56.9509 | 17.2366 | 8.70819
22_Binnenwand_MS-01 | 01 1e verdieping | 1466.5 | 1703 | 0 | 5.77583 | 2.30682 | 0.854707 | 0.334224
22_Binnenwand_MS-01 | 01 1e verdieping | 6022.78 | 3038 | 0.593218 | 18.2832 | 13.3883 | 2.74338 | 2.00913
22_Binnenwand_MS-01 | 01 1e verdieping | 4945.04 | 4250 | 0.419602 | 21.043 | 14.4937 | 3.17504 | 2.19264
22_Binnenwand_MS-01 | 01 1e verdieping | 3475 | 4250 | 0.04125 | 14.7585 | 5.16815 | 2.21378 | 0.775222
22_Binnenwand_MS-01 | 01 1e verdieping | 4350.04 | 4247 | 0.0129 | 18.4746 | 5.6953 | 2.76736 | 0.850459
22_Binnenwand_MS-01 | 01 1e verdieping | 1806.19 | 4100 | 0.114685 | 6.93167 | 4.4873 | 1.08212 | 0.715463
22_Binnenwand_MS-01 | 01 1e verdieping | 8300.58 | 4050 | 0.0705169 | 33.3414 | 8.91332 | 5.03704 | 1.37285
22_Binnenwand_MS-01 | 01 1e verdieping | 1995 | 4100 | 0.138838 | 7.1164 | 4.66892 | 1.0501 | 0.68298
22_Binnenwand_MS-01 | 01 1e verdieping | 662.5 | 4250 | 0.0940625 | 2.70581 | 2.70581 | 0.387278 | 0.387278
22_Binnenwand_MS-01 | 01 1e verdieping | 2225.21 | 4250 | 0.0990639 | 9.48371 | 5.69604 | 1.44115 | 0.872999
22_Binnenwand_MS-01 | 01 1e verdieping | 2895 | 4070 | 0.0059375 | 11.729 | 6.37101 | 1.74155 | 0.937846
22_Binnenwand_MS-01 | 01 1e verdieping | 15774.5 | 4070 | 1.28 | 64.1699 | 42.4614 | 9.62548 | 6.36921
22_Binnenwand_MS-01 | 01 1e verdieping | 3825 | 4250 | 0.527171 | 16.0543 | 5.11481 | 2.41546 | 0.774535
22_Binnenwand_MS-01 | 01 1e verdieping | 3780 | 4250 | 0.577624 | 16.0973 | 16.0973 | 2.45488 | 2.45488
22_Binnenwand_MS-01 | 01 1e verdieping | 6192.49 | 4250 | 0.766554 | 26.2343 | 15.2377 | 3.917 | 2.26751
22_Binnenwand_MS-01 | 01 1e verdieping | 651.368 | 4250 | 0.0977053 | 2.76656 | 2.76656 | 0.414972 | 0.414972
22_Binnenwand_MS-01 | 01 1e verdieping | 724.945 | 4250 | 0.103429 | 3.03845 | 3.03845 | 0.439254 | 0.439254
22_Binnenwand_MS-01 | 01 1e verdieping | 15892.5 | 4070 | 1.89509 | 64.1524 | 54.6368 | 9.64907 | 8.22177
22_Binnenwand_MS-01 | 01 1e verdieping | 28000 | 4100 | 2.79469 | 114.739 | 59.1464 | 17.2142 | 8.87439
22_Binnenwand_MS-01 | 01 1e verdieping | 1320 | 4250 | 0.198 | 5.55852 | 5.55852 | 0.833779 | 0.833779
22_Binnenwand_MS-01 | 01 1e verdieping | 2337.5 | 4250 | 0.080025 | 9.88061 | 5.22826 | 1.48794 | 0.790083
22_Binnenwand_MS-01 | 01 1e verdieping | 2820 | 4070 | 0.423 | 11.4404 | 11.4404 | 1.72068 | 1.72068
22_Binnenwand_MS-01 | 01 1e verdieping | 2895 | 4070 | 0.439562 | 11.8081 | 11.8081 | 1.78902 | 1.78902
22_Binnenwand_MS-01 | 01 1e verdieping | 444.999 | 4250 | 0.0614374 | 1.86469 | 1.86469 | 0.261109 | 0.261109
22_Binnenwand_MS-01 | 01 1e verdieping | 1534.04 | 4247 | 0.230107 | 6.46173 | 3.69244 | 0.970259 | 0.553867
22_Binnenwand_MS-01 | 01 1e verdieping | 6389.07 | 4250 | 0.335625 | 27.1535 | 14.6988 | 4.07303 | 2.20482
22_Binnenwand_MS-01 | 01 1e verdieping | 6751.38 | 4247 | 0.389973 | 28.6731 | 16.2309 | 4.30097 | 2.43463
22_Binnenwand_MS-01 | 02 2e tussenverdieping | 6492.78 | 3068 | 0.688027 | 19.7345 | 14.9078 | 2.96017 | 2.23616
22_Binnenwand_MS-01 | 02 2e tussenverdieping | 6022.78 | 3038 | 0.598318 | 18.2911 | 13.7497 | 2.74367 | 2.06246
22_Binnenwand_MS-01 | 02 2e tussenverdieping | 3685 | 3035 | 0.55275 | 11.1103 | 11.1103 | 1.67575 | 1.67575
22_Binnenwand_MS-01 | 02 2e tussenverdieping | 6182.78 | 3038 | 0.927417 | 18.7833 | 18.7833 | 2.81749 | 2.81749
22_Binnenwand_MS-01 | 02 2e tussenverdieping | 1802.75 | 3038 | 0.270412 | 5.47675 | 5.47675 | 0.821512 | 0.821512
22_Binnenwand_MS-01 | 02 2e tussenverdieping | 3950 | 3038 | 0.4575 | 11.9899 | 9.92257 | 1.79848 | 1.48839
22_Binnenwand_MS-01 | 02 2e tussenverdieping | 683.217 | 3038 | 0.102483 | 2.06253 | 2.06253 | 0.309379 | 0.309379
22_Binnenwand_MS-01 | 02 2e tussenverdieping | 2090 | 3035 | 0.187275 | 6.29382 | 3.84634 | 0.949298 | 0.582176
22_Binnenwand_MS-01 | 02 2e tussenverdieping | 1750 | 3035 | 0.2625 | 5.24125 | 5.24125 | 0.786188 | 0.786188
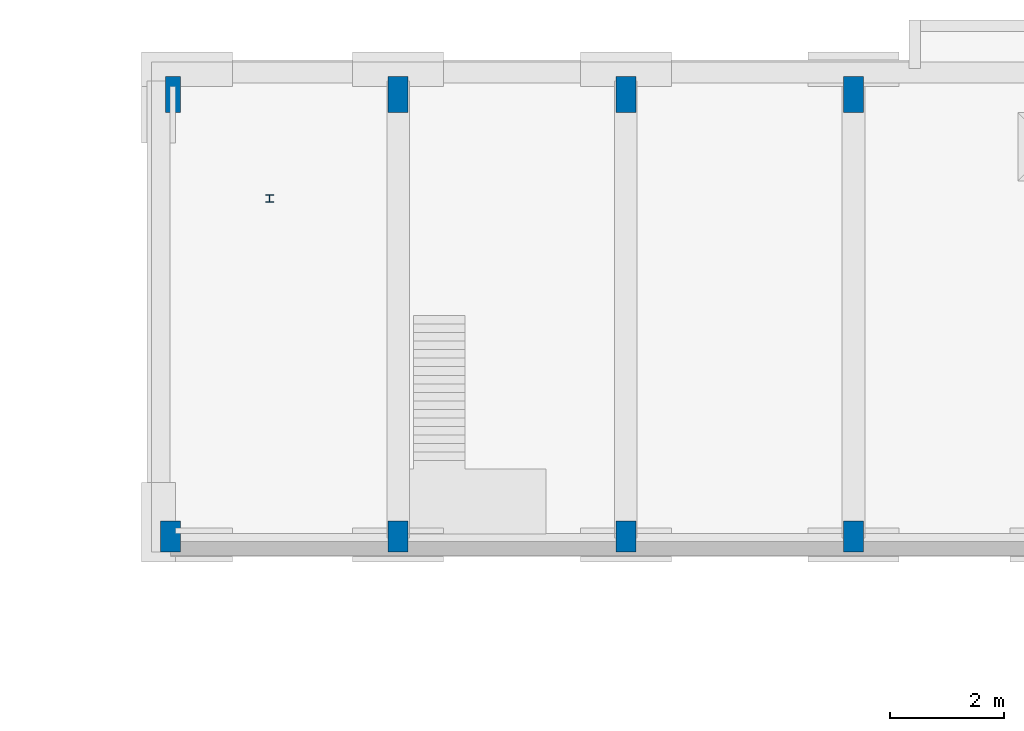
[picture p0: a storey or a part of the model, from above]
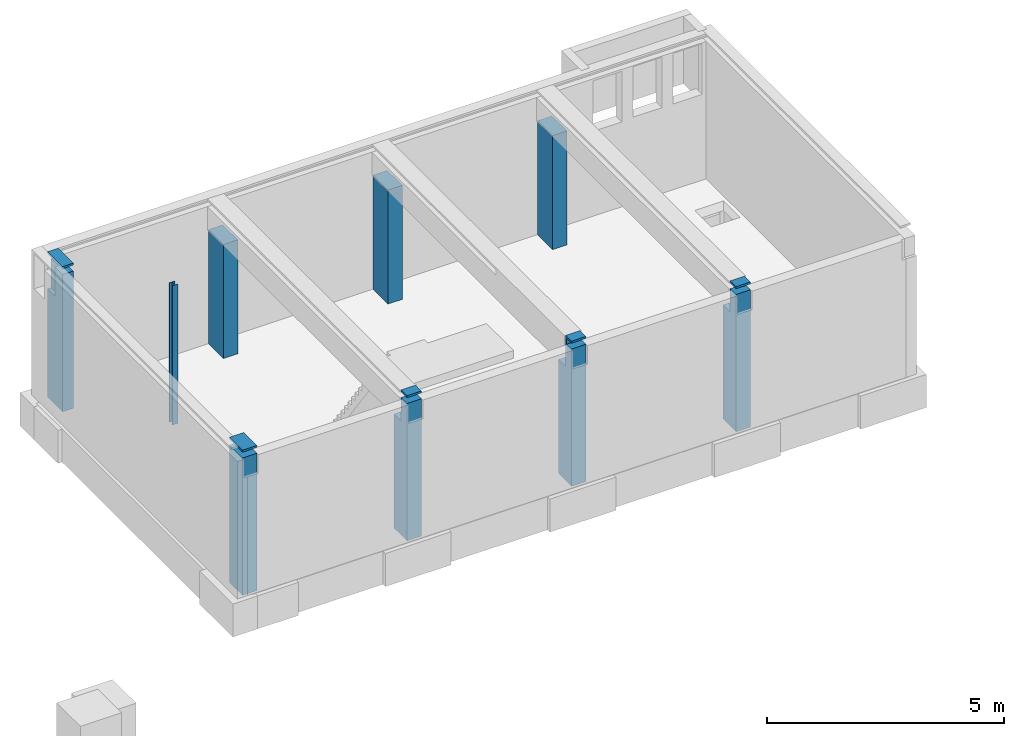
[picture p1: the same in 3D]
Properties of the parts of a building model (IFC2X3), part 5 of 5

# IfcWall: MS-01 GF 150 ECO DGS/2.100.2.A 150 (147)
Name | In | Length (mm) | Height (mm) | GrossFootprintArea (m2) = NetFootprintArea (m2) | GrossSideArea (m2) | NetSideArea (m2) | GrossVolume (m3) | NetVolume (m3)
22_Binnenwand_MS-01 | 02 2e tussenverdieping | 2162.5 | 3035 | 0.324375 | 6.47669 | 6.47669 | 0.971503 | 0.971503
22_Binnenwand_MS-01 | 02 2e tussenverdieping | 1622 | 3038 | 0.2433 | 4.86276 | 4.86276 | 0.729413 | 0.729413
22_Binnenwand_MS-01 | 02 2e tussenverdieping | 236.787 | 3038 | 0.0408305 | 0.738346 | 0.738346 | 0.124043 | 0.124043
22_Binnenwand_MS-01 | 02 2e tussenverdieping | 84.9999 | 3038 | 0.00743749 | 0.239242 | 0.239242 | 0.0225951 | 0.0225951
22_Binnenwand_MS-01 | 02 2e verdieping | 3450 | 620 | 0.5175 | 12.4786 | 2.139 | 1.8718 | 0.32085
22_Binnenwand_MS-01 | 02 2e verdieping | 7998.48 | 4050 | 1.19977 | 32.3939 | 32.3939 | 4.85908 | 4.85908
22_Binnenwand_MS-01 | 02 2e verdieping | 7999.41 | 4200 | 1.19991 | 29.3632 | 29.3632 | 4.40443 | 4.40443
22_Binnenwand_MS-01 | 02 2e verdieping | 7997.55 | 4050 | 1.19963 | 32.3901 | 32.3901 | 4.85851 | 4.85851
22_Binnenwand_MS-01 | 02 2e verdieping | 8010 | 4270 | 1.2015 | 33.8563 | 33.8563 | 5.0783 | 5.0783
22_Binnenwand_MS-01 | 02 2e verdieping | 7925 | 4270 | 1.2 | 33.5194 | 33.5194 | 5.07838 | 5.07838
22_Binnenwand_MS-01 | 02 2e verdieping | 8010 | 4270 | 1.19025 | 29.012 | 29.012 | 4.35178 | 4.35178
22_Binnenwand_MS-01 | 02 2e verdieping | 7923.01 | 4270 | 1.1997 | 33.8478 | 33.8478 | 5.07717 | 5.07717
22_Binnenwand_MS-01 | 02 2e verdieping | 8000 | 4050 | 1.20531 | 32.2293 | 32.2293 | 4.87657 | 4.87657
22_Binnenwand_MS-01 | 02 2e verdieping | 7996.63 | 4050 | 1.19949 | 32.3863 | 32.3863 | 4.85794 | 4.85794
22_Binnenwand_MS-01 | 02 2e verdieping | 7930 | 4267 | 0.11725 | 33.6909 | 10.369 | 5.07182 | 1.57431
22_Binnenwand_MS-01 | 02 2e verdieping | 4676.07 | 3607 | 0.67891 | 16.3255 | 16.3255 | 2.44882 | 2.44882
22_Binnenwand_MS-01 | 02 2e verdieping | 199.998 | 4270 | 0.0412503 | 0.758578 | 0.758578 | 0.108514 | 0.108514
22_Binnenwand_MS-01 | 02 2e verdieping | 1750.1 | 4050 | 0.107415 | 7.08266 | 4.63828 | 1.0624 | 0.695742
22_Binnenwand_MS-01 | 02 2e verdieping | 2102 | 4250 | 0.149601 | 7.33705 | 4.88957 | 1.11819 | 0.751073
22_Binnenwand_MS-01 | 02 2e verdieping | 28000 | 4050 | 3.06651 | 112.78 | 58.1308 | 16.9821 | 8.7847
22_Binnenwand_MS-01 | 02 2e verdieping | 5675 | 4050 | 0.85125 | 22.9199 | 22.9199 | 3.43799 | 3.43799
22_Binnenwand_MS-01 | 02 2e verdieping | 6335.1 | 4050 | 0.436796 | 25.4327 | 17.1587 | 3.81155 | 2.57045
22_Binnenwand_MS-01 | 02 2e verdieping | 3825 | 4050 | 0.02625 | 15.4858 | 4.54125 | 2.32311 | 0.681188
22_Binnenwand_MS-01 | 02 2e verdieping | 27825 | 4050 | 2.91111 | 112.17 | 57.6614 | 16.8997 | 8.72356
22_Binnenwand_MS-01 | 03 3e tussenverdieping | 6182.78 | 3017 | 0.247917 | 18.5003 | 7.92732 | 2.77505 | 1.1891
22_Binnenwand_MS-01 | 03 3e tussenverdieping | 4130 | 2987 | 0.624813 | 12.355 | 12.355 | 1.86631 | 1.86631
22_Binnenwand_MS-01 | 03 3e tussenverdieping | 6022.78 | 2987 | 0.245858 | 17.956 | 7.60171 | 2.69465 | 1.1415
22_Binnenwand_MS-01 | 03 3e tussenverdieping | 1578.8 | 3027 | 0.242133 | 4.79795 | 4.79795 | 0.732935 | 0.732935
22_Binnenwand_MS-01 | 03 3e tussenverdieping | 601.355 | 3027 | 0.0795782 | 1.78246 | 1.78246 | 0.240883 | 0.240883

# IfcWall: MS-02 GF 125 ECO DGS/2.75.2.A 125 (8)
Pset_WallCommon - IsExternal: no; LoadBearing: no
BaseQuantities - Width: 125 mm
Name | In | Length (mm) | Height (mm) | GrossFootprintArea (m2) = NetFootprintArea (m2) | GrossSideArea (m2) | NetSideArea (m2) | GrossVolume (m3) | NetVolume (m3)
22_Binnenwand_MS-02 | 00 Begane grond | 5446.5 | 4070 | 0.680812 | 21.6042 | 21.6042 | 2.70053 | 2.70053
2 x 22_Binnenwand_MS-02 | 00 Begane grond | 4893.96 | 4070 | 0.611745 | 18.494 | 18.494 | 2.31175 | 2.31175
22_Binnenwand_MS-02 | 00 Begane grond | 8693.96 | 4070 | 0.630495 | 33.9491 | 23.01 | 4.24363 | 2.87625
22_Binnenwand_MS-02 | 00 Begane grond | 5446.5 | 4070 | 0.680812 | 20.7027 | 20.7027 | 2.57298 | 2.57298
22_Binnenwand_MS-02 | 00 Begane grond | 2025 | 3600 | 0.253125 | 7.209 | 3.549 | 0.901125 | 0.443625
22_Binnenwand_MS-02 | 00 Begane grond | 5446.5 | 4070 | 0.680812 | 19.8865 | 19.8865 | 2.48582 | 2.48582
22_Binnenwand_MS-02 | 01 1e verdieping | 7447 | 4070 | 0.930875 | 30.2874 | 30.2874 | 3.78592 | 3.78592

# IfcWall: MS-03 GF 100 HTT DGS V/100.2 100 (25)
BaseQuantities - Width: 100 mm
Pset_WallCommon - IsExternal: no; LoadBearing: no
Name | In | Length (mm) | Height (mm) | GrossFootprintArea (m2) = NetFootprintArea (m2) | GrossSideArea (m2) = NetSideArea (m2) | GrossVolume (m3) = NetVolume (m3)
22_Binnenwand_MS-03 | 00 Begane grond | 6150 | 4100 | 0.60375 | 24.9075 | 2.47537
22_Binnenwand_MS-03 | 00 Begane grond | 3650 | 3008 | 0.365 | 10.9062 | 1.09617
22_Binnenwand_MS-03 | 00 Begane grond | 600 | 3005 | 0.06 | 1.803 | 0.1803
22_Binnenwand_MS-03 | 00 Begane grond | 959 | 3005 | 0.0959 | 2.86262 | 0.288172
22_Binnenwand_MS-03 | 00 Begane grond | 998.905 | 3008 | 0.0998905 | 2.96175 | 0.296175
22_Binnenwand_MS-03 | 00 Begane grond | 959.251 | 3008 | 0.0959251 | 2.86337 | 0.288212
22_Binnenwand_MS-03 | 00 Begane grond | 900 | 3008 | 0.09 | 2.70585 | 0.270558
22_Binnenwand_MS-03 | 00 Begane grond | 918.956 | 3008 | 0.0918956 | 2.76284 | 0.2762
22_Binnenwand_MS-03 | 01 1e tussenverdieping | 3650 | 3127 | 0.365 | 11.4135 | 1.14136
22_Binnenwand_MS-03 | 01 1e verdieping | 3950.23 | 4100 | 0.397992 | 16.3496 | 1.63176
22_Binnenwand_MS-03 | 01 1e verdieping | 500 | 4220 | 0.03875 | 1.91331 | 0.163395
22_Binnenwand_MS-03 | 01 1e verdieping | 3950.02 | 4100 | 0.392034 | 16.1695 | 1.60734
22_Binnenwand_MS-03 | 01 1e verdieping | 800 | 4220 | 0.08 | 3.376 | 0.3376
22_Binnenwand_MS-03 | 01 1e verdieping | 2337.5 | 1915 | 0.2225 | 4.33269 | 0.426087
22_Binnenwand_MS-03 | 02 2e tussenverdieping | 1740 | 3038 | 0.174 | 5.28612 | 0.528612
22_Binnenwand_MS-03 | 02 2e tussenverdieping | 600.956 | 1975 | 0.0600956 | 1.18599 | 0.118667
22_Binnenwand_MS-03 | 02 2e tussenverdieping | 900 | 3035 | 0.09 | 2.7315 | 0.27315
22_Binnenwand_MS-03 | 02 2e tussenverdieping | 899.97 | 1975 | 0.089997 | 1.77744 | 0.177744
22_Binnenwand_MS-03 | 02 2e verdieping | 499.993 | 4250 | 0.0409368 | 1.79922 | 0.17398
22_Binnenwand_MS-03 | 02 2e verdieping | 3950.23 | 4250 | 0.392055 | 16.7619 | 1.66623
22_Binnenwand_MS-03 | 02 2e verdieping | 3950.02 | 4250 | 0.392034 | 16.683 | 1.6661
22_Binnenwand_MS-03 | 02 2e verdieping | 800.007 | 4267 | 0.0800007 | 3.41363 | 0.341363
22_Binnenwand_MS-03 | 03 3e tussenverdieping | 1740 | 3027 | 0.174 | 5.26698 | 0.526698
22_Binnenwand_MS-03 | 03 3e tussenverdieping | 219.783 | 3024 | 0.0249471 | 0.778024 | 0.0754399
22_Binnenwand_MS-03 | 03 3e tussenverdieping | 220 | 3024 | 0.0190313 | 0.64638 | 0.0575505

# IfcWall: MS-04 GF 138 V/100.3.A 113 (43)
Pset_WallCommon - IsExternal: no; LoadBearing: no
BaseQuantities - Width: 112.5 mm
Name | In | Length (mm) | Height (mm) | GrossFootprintArea (m2) = NetFootprintArea (m2) | GrossSideArea (m2) | NetSideArea (m2) | GrossVolume (m3) | NetVolume (m3)
22_Binnenwand_MS-04 | 00 Begane grond | 1533.15 | 4070 | 0.169433 | 6.18434 | 6.18434 | 0.68869 | 0.68869
22_Binnenwand_MS-04 | 00 Begane grond | 1556.25 | 4100 | 0.178125 | 6.53156 | 6.53156 | 0.730031 | 0.730031
22_Binnenwand_MS-04 | 00 Begane grond | 2118.75 | 4070 | 0.238594 | 8.69962 | 8.69962 | 0.971077 | 0.971077
22_Binnenwand_MS-04 | 00 Begane grond | 593.794 | 3600 | 0.0726613 | 2.40766 | 2.40766 | 0.261581 | 0.261581
22_Binnenwand_MS-04 | 00 Begane grond | 1093.62 | 4070 | 0.126079 | 4.60365 | 4.60365 | 0.513141 | 0.513141
22_Binnenwand_MS-04 | 00 Begane grond | 650.045 | 4070 | 0.07313 | 2.77287 | 2.77287 | 0.297639 | 0.297639
22_Binnenwand_MS-04 | 00 Begane grond | 272.83 | 4070 | 0.0306933 | 1.23008 | 1.23008 | 0.124912 | 0.124912
22_Binnenwand_MS-04 | 00 Begane grond | 1093.62 | 4070 | 0.119985 | 4.40114 | 4.40114 | 0.487634 | 0.487634
22_Binnenwand_MS-04 | 00 Begane grond | 862.833 | 4070 | 0.090975 | 3.46086 | 3.46086 | 0.370268 | 0.370268
22_Binnenwand_MS-04 | 01 1e tussenverdieping | 946.25 | 2927 | 0.1095 | 2.87943 | 2.87943 | 0.320506 | 0.320506
22_Binnenwand_MS-04 | 01 1e tussenverdieping | 1256.25 | 3127 | 0.149531 | 3.66653 | 3.66653 | 0.405625 | 0.405625
22_Binnenwand_MS-04 | 01 1e tussenverdieping | 1666.25 | 2977 | 0.181594 | 4.886 | 4.886 | 0.540605 | 0.540605
22_Binnenwand_MS-04 | 01 1e tussenverdieping | 890 | 2977 | 0.102938 | 2.76117 | 2.76117 | 0.306445 | 0.306445
22_Binnenwand_MS-04 | 01 1e tussenverdieping | 946.25 | 2977 | 0.1095 | 2.92862 | 2.92862 | 0.325981 | 0.325981
22_Binnenwand_MS-04 | 01 1e verdieping | 3785.04 | 4250 | 0.420205 | 15.8744 | 15.8744 | 1.78587 | 1.78587
22_Binnenwand_MS-04 | 01 1e verdieping | 3861.78 | 4250 | 0.420193 | 15.842 | 15.842 | 1.78502 | 1.78502
22_Binnenwand_MS-04 | 01 1e verdieping | 2130 | 4250 | 0.241812 | 8.99937 | 8.99937 | 1.0277 | 1.0277
22_Binnenwand_MS-04 | 01 1e verdieping | 1750.06 | 4220 | 0.196882 | 7.38001 | 7.38001 | 0.830251 | 0.830251
3 x 22_Binnenwand_MS-04 | 01 1e verdieping | 557.5 | 4250 | 0.0688125 | 2.68812 | 2.68812 | 0.292453 | 0.292453
22_Binnenwand_MS-04 | 01 1e verdieping | 506.25 | 4250 | 0.06 | 2.28919 | 2.28919 | 0.2526 | 0.2526
22_Binnenwand_MS-04 | 01 1e verdieping | 526.25 | 4250 | 0.0561563 | 2.19645 | 2.19645 | 0.237971 | 0.237971
22_Binnenwand_MS-04 | 01 1e verdieping | 3912.5 | 4250 | 0.444688 | 16.9745 | 16.9745 | 1.88691 | 1.88691
2 x 22_Binnenwand_MS-04 | 01 1e verdieping | 980 | 4250 | 0.104156 | 4.11188 | 4.11188 | 0.442664 | 0.442664
22_Binnenwand_MS-04 | 01 1e verdieping | 617.681 | 4250 | 0.0694891 | 2.73527 | 2.73527 | 0.292827 | 0.292827
22_Binnenwand_MS-04 | 01 1e verdieping | 557.5 | 4250 | 0.0627187 | 2.4829 | 2.4829 | 0.264432 | 0.264432
22_Binnenwand_MS-04 | 01 1e verdieping | 617.681 | 4250 | 0.0633953 | 2.5719 | 2.5719 | 0.269423 | 0.269423
22_Binnenwand_MS-04 | 02 2e tussenverdieping | 1306.25 | 3038 | 0.143906 | 3.9224 | 3.9224 | 0.436512 | 0.436512
22_Binnenwand_MS-04 | 02 2e tussenverdieping | 946.25 | 3188 | 0.1095 | 2.99158 | 2.99158 | 0.33304 | 0.33304
22_Binnenwand_MS-04 | 02 2e tussenverdieping | 946.25 | 3038 | 0.1095 | 2.98863 | 2.98863 | 0.332661 | 0.332661
22_Binnenwand_MS-04 | 02 2e tussenverdieping | 1256.25 | 3038 | 0.138281 | 3.78997 | 3.78997 | 0.419251 | 0.419251
22_Binnenwand_MS-04 | 02 2e verdieping | 2148.75 | 4270 | 0.244781 | 9.33529 | 9.33529 | 1.04522 | 1.04522
22_Binnenwand_MS-04 | 02 2e verdieping | 506.25 | 4050 | 0.06 | 2.20219 | 2.20219 | 0.243 | 0.243
22_Binnenwand_MS-04 | 02 2e verdieping | 456.25 | 4050 | 0.0482813 | 1.8225 | 1.8225 | 0.195539 | 0.195539
22_Binnenwand_MS-04 | 02 2e verdieping | 3968.75 | 4270 | 0.443437 | 16.9199 | 16.9199 | 1.89348 | 1.89348
22_Binnenwand_MS-04 | 02 2e verdieping | 1750.06 | 4270 | 0.196882 | 7.39061 | 7.39061 | 0.831444 | 0.831444
22_Binnenwand_MS-04 | 02 2e verdieping | 1749.9 | 4050 | 0.196864 | 7.04519 | 7.04519 | 0.796376 | 0.796376
22_Binnenwand_MS-04 | 03 3e tussenverdieping | 1306.25 | 2987 | 0.143906 | 3.8831 | 3.8831 | 0.429848 | 0.429848
22_Binnenwand_MS-04 | 03 3e tussenverdieping | 1256.25 | 2987 | 0.138281 | 3.73375 | 3.73375 | 0.413046 | 0.413046
22_Binnenwand_MS-04 | 03 3e tussenverdieping | 946.25 | 2987 | 0.1095 | 2.93846 | 2.93846 | 0.327077 | 0.327077
22_Binnenwand_MS-04 | 03 3e tussenverdieping | 946.25 | 3207 | 0.1095 | 2.91846 | 3.01636 | 0.326976 | 0.327955

# IfcWall: beton 125, 22_Binnenwand_beton
In: -1 Fundering
Material: beton
Pset_WallCommon - IsExternal: no; LoadBearing: no
BaseQuantities - Length: 1389.45 mm; Height: 1150 mm; Width: 125 mm; GrossFootprintArea: 0.173682 m2; NetFootprintArea: 0.173682 m2; GrossSideArea: 1.59787 m2; NetSideArea: 1.59787 m2; GrossVolume: 0.199734 m3; NetVolume: 0.199734 m3

# IfcWall: beton 160 (5)
Material: beton
Pset_WallCommon - IsExternal: no
BaseQuantities - Width: 160 mm
Name | In | LoadBearing | Length (mm) | Height (mm) | GrossFootprintArea (m2) = NetFootprintArea (m2) | GrossSideArea (m2) | NetSideArea (m2) | GrossVolume (m3) | NetVolume (m3)
22_Binnenwand_beton | 00 Begane grond | yes | 7725 | 3188 | 1.236 | 23.2367 | 20.7892 | 3.71788 | 3.32629
22_Binnenwand_beton | 00 Begane grond | no | 15650 | 2487.5 | 1.78656 | 38.9294 | 26.7953 | 6.2287 | 4.28726
22_Binnenwand_beton | 01 1e tussenverdieping | no | 20000 | 2487 | 2.648 | 49.425 | 41.2588 | 7.908 | 6.60142
22_Binnenwand_beton | 02 2e tussenverdieping | no | 19825 | 2487.5 | 1.89456 | 49.3147 | 29.2189 | 7.89035 | 4.67503
22_Binnenwand_beton | 03 3e tussenverdieping | no | 20000 | 3207 | 3.2 | 47.14 | 39.1119 | 7.5424 | 6.2579

# IfcWall: beton 160 160 (7)
Material: beton_gewapend C
BaseQuantities - Width: 160 mm
Pset_WallCommon - IsExternal: no; LoadBearing: yes
Name | In | Length (mm) | Height (mm) | GrossFootprintArea (m2) = NetFootprintArea (m2) | GrossSideArea (m2) | NetSideArea (m2) | GrossVolume (m3) | NetVolume (m3)
22_Binnenwand_beton | 00 Begane grond | 7725 | 4250 | 1.23512 | 32.0483 | 27.1155 | 5.08379 | 4.29454
22_Binnenwand_beton | 01 1e tussenverdieping | 7960.91 | 3157 | 1.27375 | 24.7552 | 24.7552 | 3.96103 | 3.96103
22_Binnenwand_beton | 01 1e verdieping | 8290 | 4250 | 1.3264 | 34.127 | 34.127 | 5.46033 | 5.46033
22_Binnenwand_beton | 02 2e tussenverdieping | 7960.91 | 3218 | 1.27375 | 24.3372 | 24.3372 | 3.89396 | 3.89396
22_Binnenwand_beton | 02 2e verdieping | 7685.91 | 4050 | 1.22975 | 30.0307 | 30.0307 | 4.62952 | 4.62952
22_Binnenwand_beton | 02 2e verdieping | 530.586 | 2987.5 | 0.0848937 | 1.27937 | 1.27937 | 0.202279 | 0.202279
22_Binnenwand_beton | 03 3e tussenverdieping | 7685.91 | 2987 | 0.992806 | 18.9766 | 16.5498 | 2.79912 | 2.4129

# IfcWall: beton 200 (4)
In: -1 Fundering
Material: beton
Pset_WallCommon - IsExternal: no; LoadBearing: no
BaseQuantities - Height: 1300 mm; Width: 200 mm
Name | Length (mm) | GrossFootprintArea (m2) = NetFootprintArea (m2) | GrossSideArea (m2) = NetSideArea (m2) | GrossVolume (m3) = NetVolume (m3)
22_Binnenwand_beton | 2700 | 0.58 | 3.77 | 0.754
22_Binnenwand_beton | 2100 | 0.42 | 2.73 | 0.546
22_Binnenwand_beton | 2100 | 0.38 | 2.47 | 0.494
22_Binnenwand_beton | 2700 | 0.54 | 3.51 | 0.702

# IfcWall: beton 250 (10)
In: -1 Fundering
Material: beton
Pset_WallCommon - IsExternal: no; LoadBearing: no
BaseQuantities - Width: 250 mm
Name | Length (mm) | Height (mm) | GrossFootprintArea (m2) = NetFootprintArea (m2) | GrossSideArea (m2) | NetSideArea (m2) | GrossVolume (m3) | NetVolume (m3)
22_Binnenwand_beton | 3200.05 | 1170 | 0.852513 | 3.07025 | 3.35905 | 0.767562 | 0.830771
22_Binnenwand_beton | 7087.88 | 1050 | 1.77197 | 7.24628 | 7.24628 | 1.81157 | 1.81157
22_Binnenwand_beton | 3087.88 | 1050 | 0.803221 | 3.36853 | 3.36656 | 0.842132 | 0.84164
22_Binnenwand_beton | 125 | 1050 | 0.03125 | 0.13125 | 0.13125 | 0.0328125 | 0.0328125
22_Binnenwand_beton | 735 | 1050 | 0.215 | 0.903 | 0.903 | 0.22575 | 0.22575
22_Binnenwand_beton | 2425.05 | 1050 | 0.575013 | 2.41505 | 2.41505 | 0.603763 | 0.603763
22_Binnenwand_beton | 735 | 1050 | 0.24625 | 1.03425 | 1.03425 | 0.258562 | 0.258562
22_Binnenwand_beton | 735 | 1050 | 0.18375 | 0.77175 | 0.77175 | 0.192937 | 0.192937
22_Binnenwand_beton | 3150 | 1050 | 0.725 | 3.045 | 2.98791 | 0.76125 | 0.746978
22_Binnenwand_beton | 850 | 1050 | 0.15 | 0.63 | 0.63 | 0.1575 | 0.1575

# IfcWall: betonblok C 250 (4)
In: Kelder
Material: betonblok C
Pset_WallCommon - IsExternal: no; LoadBearing: yes
BaseQuantities - Width: 250 mm
Name | Length (mm) | Height (mm) | GrossFootprintArea (m2) = NetFootprintArea (m2) | GrossSideArea (m2) | NetSideArea (m2) | GrossVolume (m3) | NetVolume (m3)
22_Binnenwand_betonblok | 8420 | 3730 | 2.118 | 29.7109 | 29.7109 | 7.49733 | 7.49733
22_Binnenwand_betonblok | 16260 | 3730 | 4.0025 | 58.4847 | 55.7547 | 14.5842 | 13.9017
22_Binnenwand_betonblok | 8420 | 3730 | 2.1675 | 31.0138 | 31.0138 | 7.75345 | 7.75345
22_Binnenwand_betonblok | 16260 | 3530 | 3.7536 | 53.8648 | 53.8648 | 13.2096 | 13.2096

# IfcWall: kalkzandsteen 100 (5)
Material: kalkzandsteen
BaseQuantities - Width: 100 mm
Pset_WallCommon - IsExternal: no; LoadBearing: no
Name | In | Length (mm) | Height (mm) | GrossFootprintArea (m2) = NetFootprintArea (m2) | GrossSideArea (m2) = NetSideArea (m2) | GrossVolume (m3) = NetVolume (m3)
22_Binnenwand_kalkzandsteen | -1 Fundering | 425 | 1050 | 0.0375 | 0.33775 | 0.033775
22_Binnenwand_kalkzandsteen | -1 Fundering | 415.04 | 1050 | 0.046504 | 0.488292 | 0.0488292
22_Binnenwand_kalkzandsteen | 00 Begane grond | 875 | 2000 | 0.0925 | 1.85 | 0.185
22_Binnenwand_kalkzandsteen | 00 Begane grond | 625 | 2000 | 0.0575 | 1.15 | 0.115
22_Binnenwand_kalkzandsteen | 00 Begane grond | 2575.06 | 3440 | 0.257505 | 8.85818 | 0.885819

# IfcWall: kalkzandsteen 150 (12)
Material: kalkzandsteen
Pset_WallCommon - IsExternal: no; LoadBearing: no
BaseQuantities - Width: 150 mm
Name | In | Length (mm) | Height (mm) | GrossFootprintArea (m2) = NetFootprintArea (m2) | GrossSideArea (m2) | NetSideArea (m2) | GrossVolume (m3) | NetVolume (m3)
22_Binnenwand_kalkzandsteen | -1 Fundering | 2275.05 | 490 | 0.341258 | 1.11477 | 1.09706 | 0.167216 | 0.164559
22_Binnenwand_kalkzandsteen | 00 Begane grond | 3650 | 4100 | 0.3075 | 14.965 | 11.285 | 2.24475 | 1.69275
22_Binnenwand_kalkzandsteen | 00 Begane grond | 3080 | 3988 | 0.462 | 12.2553 | 12.2713 | 1.83415 | 1.83952
22_Binnenwand_kalkzandsteen | 00 Begane grond | 2575.05 | 3440 | 0.386258 | 8.85817 | 8.85817 | 1.32873 | 1.32873
22_Binnenwand_kalkzandsteen | 00 Begane grond | 8015 | 4100 | 1.2135 | 32.2021 | 32.2021 | 4.83031 | 4.83031
22_Binnenwand_kalkzandsteen | 00 Begane grond | 3154.6 | 3570 | 0.46194 | 10.9942 | 10.9942 | 1.64913 | 1.64913
22_Binnenwand_kalkzandsteen | 00 Begane grond | 84.991 | 2600 | 0.0127486 | 0.220977 | 0.220977 | 0.0331465 | 0.0331465
22_Binnenwand_kalkzandsteen | 00 Begane grond | 461 | 2600 | 0.06915 | 1.1986 | 1.1986 | 0.17979 | 0.17979
22_Binnenwand_kalkzandsteen | 00 Begane grond | 84.0081 | 2570 | 0.0126012 | 0.215901 | 0.215901 | 0.0323851 | 0.0323851
22_Binnenwand_kalkzandsteen | 01 1e verdieping | 3690 | 4100 | 0.3135 | 15.129 | 11.449 | 2.26935 | 1.71735
22_Binnenwand_kalkzandsteen | 02 2e verdieping | 3650 | 4270 | 0.3075 | 15.3885 | 11.7085 | 2.30828 | 1.75628
22_Binnenwand_kalkzandsteen | 04 4e verdieping | 2714 | 1102.52 | 0.4221 | 2.775 | 2.775 | 0.41625 | 0.41625

# IfcWall: kalkzandsteen 214 (13)
Material: kalkzandsteen
Pset_WallCommon - IsExternal: no; LoadBearing: no
BaseQuantities - Width: 214 mm
Name | In | Length (mm) | Height (mm) | GrossFootprintArea (m2) = NetFootprintArea (m2) | GrossSideArea (m2) | NetSideArea (m2) | GrossVolume (m3) | NetVolume (m3)
22_Binnenwand_kalkzandsteen | 00 Begane grond | 1900 | 4250 | 0.4066 | 8.075 | 8.075 | 1.72805 | 1.72805
22_Binnenwand_kalkzandsteen | 00 Begane grond | 3790 | 4250 | 0.84316 | 16.7258 | 16.7258 | 3.5796 | 3.5796
22_Binnenwand_kalkzandsteen | 00 Begane grond | 1900 | 4250 | 0.4066 | 7.9814 | 6.7106 | 1.68894 | 1.41699
22_Binnenwand_kalkzandsteen | 01 1e verdieping | 3365 | 4250 | 0.72011 | 14.3012 | 14.3012 | 3.06047 | 3.06047
22_Binnenwand_kalkzandsteen | 01 1e verdieping | 1900 | 4250 | 0.4066 | 8.075 | 8.075 | 1.72805 | 1.72805
22_Binnenwand_kalkzandsteen | 01 1e verdieping | 1900 | 4250 | 0.1498 | 7.9832 | 3.9134 | 1.68894 | 0.818388
22_Binnenwand_kalkzandsteen | 01 1e verdieping | 575 | 4250 | 0.12305 | 2.44375 | 2.44375 | 0.522963 | 0.522963
22_Binnenwand_kalkzandsteen | 02 2e verdieping | 1900 | 4050 | 0.4066 | 7.695 | 7.695 | 1.64673 | 1.64673
22_Binnenwand_kalkzandsteen | 02 2e verdieping | 3865 | 4050 | 0.84316 | 15.957 | 15.957 | 3.4148 | 3.4148
22_Binnenwand_kalkzandsteen | 02 2e verdieping | 1900 | 4050 | 0.4066 | 7.51141 | 4.755 | 1.60744 | 1.01757
22_Binnenwand_kalkzandsteen | 04 4e verdieping | 2082 | 1102.52 | 0.484496 | 2.44018 | 2.44087 | 0.522199 | 0.522345
22_Binnenwand_kalkzandsteen | 04 4e verdieping | 2082 | 1102.52 | 0.4387 | 2.2123 | 2.21298 | 0.473433 | 0.473579
22_Binnenwand_kalkzandsteen | 04 4e verdieping | 2714 | 1066.74 | 0.580796 | 2.88859 | 2.88859 | 0.618471 | 0.618471

# IfcWall: metaal - Aluminium RAL8000 10 (3)
In: 01 1e verdieping
Material: metaal - Aluminium RAL8000
Pset_WallCommon - IsExternal: yes; LoadBearing: no
BaseQuantities - Height: 3560 mm; Width: 10 mm
Name | Length (mm) | GrossFootprintArea (m2) = NetFootprintArea (m2) | GrossSideArea (m2) = NetSideArea (m2) | GrossVolume (m3) = NetVolume (m3)
41_Binnenwand_metaal | 143.092 | 0.00143092 | 0.509408 | 0.00509408
41_Binnenwand_metaal | 143.092 | 0.00135092 | 0.480928 | 0.00480928
41_Binnenwand_metaal | 171 | 0.00171 | 0.60876 | 0.0060876

# IfcWall: metalstud 70 70 (4)
Material: metal_stud
Pset_WallCommon - IsExternal: no; LoadBearing: no
BaseQuantities - Width: 70 mm
Name | In | Length (mm) | Height (mm) | GrossFootprintArea (m2) = NetFootprintArea (m2) | GrossSideArea (m2) | NetSideArea (m2) | GrossVolume (m3) | NetVolume (m3)
22_Binnenwand_metalstud | 00 Begane grond | 7725 | 2978 | 0.42987 | 21.3671 | 19.1958 | 1.4957 | 1.3437
22_Binnenwand_metalstud | 01 1e tussenverdieping | 8275 | 2927 | 0.50225 | 20.6923 | 20.6923 | 1.44846 | 1.44846
22_Binnenwand_metalstud | 02 2e tussenverdieping | 8275 | 3248 | 0.54075 | 22.3025 | 22.3025 | 1.56117 | 1.56117
22_Binnenwand_metalstud | 03 3e tussenverdieping | 8275 | 2327 | 0.427134 | 16.6053 | 14.2271 | 1.16237 | 0.995894

# IfcWall: metalstud-lucht-metalstud 190 190, 22_Binnenwand_metalstud-lucht-metalstud
In: 00 Begane grond
Pset_WallCommon - IsExternal: no; LoadBearing: no
BaseQuantities - Length: 3210.54 mm; Height: 4200 mm; Width: 190 mm; GrossFootprintArea: 0.540002 m2; NetFootprintArea: 0.540002 m2; GrossSideArea: 9.6224 m2; NetSideArea: 9.6224 m2; GrossVolume: 2.00209 m3; NetVolume: 2.00209 m3

# IfcWall: metalstud-lucht-metalstud 270 270 (5)
Pset_WallCommon - IsExternal: no; LoadBearing: no
BaseQuantities - Width: 270 mm
Name | In | Length (mm) | Height (mm) | GrossFootprintArea (m2) = NetFootprintArea (m2) | GrossSideArea (m2) | NetSideArea (m2) | GrossVolume (m3) | NetVolume (m3)
22_Binnenwand_metalstud-lucht-metalstud | 00 Begane grond | 5854 | 2978 | 0.57208 | 15.7953 | 5.52121 | 4.47766 | 1.70365
22_Binnenwand_metalstud-lucht-metalstud | 00 Begane grond | 6195.09 | 3188 | 1.58202 | 16.5069 | 16.5069 | 4.71955 | 4.71955
22_Binnenwand_metalstud-lucht-metalstud | 01 1e tussenverdieping | 8339 | 9392 | 2.17453 | 54.2136 | 47.1774 | 17.4701 | 15.5552
22_Binnenwand_metalstud-lucht-metalstud | 01 1e verdieping | 8225 | 4250 | 2.22075 | 25.8615 | 25.8615 | 8.03661 | 8.03661
22_Binnenwand_metalstud-lucht-metalstud | 02 2e verdieping | 7175 | 4050 | 1.93725 | 25.9018 | 25.9018 | 7.40388 | 7.40388

# IfcWall: metselwerk-lucht-kalkzandsteen 335 335 (7)
Pset_WallCommon - IsExternal: yes; LoadBearing: no
BaseQuantities - Width: 335 mm
Name | In | Length (mm) | Height (mm) | GrossFootprintArea (m2) = NetFootprintArea (m2) | GrossSideArea (m2) = NetSideArea (m2) | GrossVolume (m3) = NetVolume (m3)
21_Binnenwand_metselwerk-lucht-kalkzandsteen | 00 Begane grond | 167.5 | 5715 | 0.0221531 | 0.416446 | 0.124921 | Material: metselwerk AFW
21_Binnenwand_metselwerk-lucht-kalkzandsteen | 00 Begane grond | 12310 | 5715 | 3.95765 | 66.3508 | 22.0992
21_Binnenwand_metselwerk-lucht-kalkzandsteen | 00 Begane grond | 12142.5 | 5715 | 3.94349 | 66.0178 | 22.0021
21_Binnenwand_metselwerk-lucht-kalkzandsteen | 01 1e verdieping | 12310 | 5685 | 3.95765 | 66.2755 | 22.1087
21_Binnenwand_metselwerk-lucht-kalkzandsteen | 01 1e verdieping | 8335 | 3560 | 2.79222 | 29.6722 | 9.93362
21_Binnenwand_metselwerk-lucht-kalkzandsteen | 01 1e verdieping | 8600 | 3560 | 2.881 | 30.6094 | 10.2478
21_Binnenwand_metselwerk-lucht-kalkzandsteen | 01 1e verdieping | 12310 | 6395 | 3.95885 | 66.5356 | 22.7042

# IfcWall: metselwerk-lucht-metselwerk 270 270 (3)
Pset_WallCommon - IsExternal: yes; LoadBearing: no
BaseQuantities - Width: 270 mm
Name | In | Length (mm) | Height (mm) | GrossFootprintArea (m2) = NetFootprintArea (m2) | GrossSideArea (m2) | NetSideArea (m2) | GrossVolume (m3) | NetVolume (m3)
21_Binnenwand_metselwerk-lucht-metselwerk | 00 Begane grond | 12050 | 3700 | 2.18916 | 40.9273 | 30.5773 | 11.2254 | 8.43086
21_Binnenwand_metselwerk-lucht-metselwerk | 01 1e verdieping | 20650 | 3560 | 4.37832 | 68.9003 | 58.6021 | 18.7778 | 16.004
21_Binnenwand_metselwerk-lucht-metselwerk | 02 2e verdieping | 20650 | 3580 | 4.37831 | 68.978 | 58.697 | 18.8131 | 16.0448

# IfcWall: therm. voorzetwand 215mm 215 (11)
Pset_WallCommon - IsExternal: yes; LoadBearing: no
BaseQuantities - Width: 215 mm
Name | In | Length (mm) | Height (mm) | GrossFootprintArea (m2) = NetFootprintArea (m2) | GrossSideArea (m2) = NetSideArea (m2) | GrossVolume (m3) = NetVolume (m3)
22_Binnenwand_therm. | 00 Begane grond | 11000 | 6345 | 2.35889 | 64.8562 | 13.325
22_Binnenwand_therm. | 00 Begane grond | 1405 | 4100 | 0.302075 | 5.7605 | 1.23851
22_Binnenwand_therm. | 00 Begane grond | 11000 | 6195 | 2.36016 | 64.0312 | 13.3431
22_Binnenwand_therm. | 01 1e verdieping | 1405 | 4100 | 0.302075 | 5.7324 | 1.2378
22_Binnenwand_therm. | 01 1e verdieping | 7809 | 4250 | 1.69147 | 31.8186 | 6.89974
22_Binnenwand_therm. | 01 1e verdieping | 7749.03 | 4250 | 1.66604 | 31.6106 | 6.79627
22_Binnenwand_therm. | 01 1e verdieping | 7175 | 3570 | 1.54263 | 25.5983 | 5.50364
22_Binnenwand_therm. | 02 2e tussenverdieping | 11000 | 6425 | 2.365 | 70.1882 | 15.1479
22_Binnenwand_therm. | 02 2e tussenverdieping | 11000 | 6205 | 2.35889 | 64.1365 | 13.3571
22_Binnenwand_therm. | 02 2e verdieping | 7175 | 3610 | 1.54262 | 25.9017 | 5.56888
22_Binnenwand_therm. | 02 2e verdieping | 1405 | 4050 | 0.302075 | 5.69025 | 1.2234

# IfcWall: voorzetwand 150, 22_Binnenwand_voorzetwand
In: 00 Begane grond
Pset_WallCommon - IsExternal: no; LoadBearing: no
BaseQuantities - Length: 3790 mm; Height: 4067 mm; Width: 150 mm; GrossFootprintArea: 0.5685 m2; NetFootprintArea: 0.5685 m2; GrossSideArea: 15.4139 m2; NetSideArea: 15.4139 m2; GrossVolume: 2.31209 m3; NetVolume: 2.31209 m3

# IfcWindow: R1 27 (3)
In: 00 Begane grond
Type - OperationType: DOUBLE_PANEL_HORIZONTAL; ParameterTakesPrecedence: no; Sizeable: no
Pset_WindowCommon - IsExternal: yes
Material - Afwerking dagkant binnen: Gewapend beton - i.h.w. (02); Afwerking dagkant buiten: Gewapend beton - i.h.w. (02); Draaiend deel: arcering (02); Frame: arcering (01); Onderdorpel: %; Rollaag / latei: arcering (01); Spouwlat: Naaldhout (01); Vensterbank: Gewapend beton - i.h.w. (02); Ventilatierooster: %; Zonwering - behuizing: arcering (01); Zonwering - isolatie: Isolatie ruit; Glas: Glas - algemeen
Name | OverallHeight (mm) = Height (mm) | OverallWidth (mm) = Width (mm) | GrossArea (m2) = Area (m2) | Perimeter (mm) | Volume (m3) = NetVolume (m3) | Depth (mm)
22_BI-F-31_305 | 2479.5 | 484.078 | 1.20027 | 5927.16 | 0.00300827 | 150
22_BI-F-28_305 | 2400 | 1225 | 2.94 | 7250 | 0.00479866 | 125
22_BI-F-29_305 | 2400 | 430 | 1.032 | 5660 | 0.0034249 | 125

# IfcWindow: R1 27 (6)
Type - OperationType: SINGLE_PANEL; ParameterTakesPrecedence: no; Sizeable: no
Pset_WindowCommon - IsExternal: yes
Material - Glas: Glas - algemeen
Name | In | OverallHeight (mm) = Height (mm) | OverallWidth (mm) | Afwerking dagkant binnen = Afwerking dagkant buiten = Vensterbank | Draaiend deel | Frame = Rollaag / latei = Zonwering - behuizing | Onderdorpel = Ventilatierooster | Spouwlat | Zonwering - isolatie | GrossArea (m2) = Area (m2) | Width (mm) | Perimeter (mm) | Volume (m3) = NetVolume (m3) | Depth (mm)
22_BI-E-21_305 | 00 Begane grond | 1267 | 1200 | n.v.t. | n.v.t. | n.v.t. | n.v.t. | n.v.t. | n.v.t. | 1.5204 | 1200 | 4934 | 0.0356389 | 160
22__305 | 00 Begane grond | 1552 | 1608.04 | n.v.t. | n.v.t. | n.v.t. | n.v.t. | n.v.t. | n.v.t. | 2.39791 | 1545.04 | 6194.08 | 0.0179758 | 150
22_BI-F-10_305 | 01 1e verdieping | 3000 | 2183.11 | Gewapend beton - i.h.w. (02) | arcering (02) | arcering (01) | % | Naaldhout (01) | Isolatie ruit | 6.54935 | 2183.12 | 10366.2 | 0.00598945 | 150
2 x 22_BI-F-10_305 | 01 1e verdieping | 3000 | 2183.11 | Gewapend beton - i.h.w. (02) | arcering (02) | arcering (01) | % | Naaldhout (01) | Isolatie ruit | 6.54935 | 2183.12 | 10366.2 | 0.00591565 | 150
22_BI-E-21_305 | 02 2e tussenverdieping | 1267 | 1200 | n.v.t. | n.v.t. | n.v.t. | n.v.t. | n.v.t. | n.v.t. | 1.5204 | 1200 | 4934 | 0.0356389 | 160

# IfcWindow: R2 bl ol 27 (10)
Type - OperationType: DOUBLE_PANEL_VERTICAL; ParameterTakesPrecedence: no; Sizeable: no
Material - Afwerking dagkant binnen: n.v.t.; Afwerking dagkant buiten: n.v.t.; Draaiend deel: n.v.t.; Frame: n.v.t.; Onderdorpel: n.v.t.; Rollaag / latei: n.v.t.; Spouwlat: n.v.t.; Vensterbank: n.v.t.; Ventilatierooster: n.v.t.; Zonwering - behuizing: n.v.t.; Zonwering - isolatie: n.v.t.; Glas: Glas - algemeen
Pset_WindowCommon - IsExternal: yes
Name | In | OverallHeight (mm) = Height (mm) | OverallWidth (mm) = Width (mm) | GrossArea (m2) = Area (m2) | Perimeter (mm) | Volume (m3) = NetVolume (m3) | Depth (mm)
22_BI-E-01_305 | 00 Begane grond | 2000 | 3649.93 | 7.29987 | 11299.9 | 0.127019 | 150
21_BU-A-14a_305 | 01 1e verdieping | 3454 | 1758.99 | 6.07556 | 10426 | 0.0774251 | 420
22_BI-E-01_305 | 01 1e verdieping | 1700 | 1850 | 3.145 | 7100 | 0.0641439 | 150
21_BU-A-15a_305 | 01 1e verdieping | 3454 | 1837 | 6.345 | 10582 | 0.0861159 | 420
3 x 22_BI-E-01_305 | 02 2e verdieping | 1700 | 3649.93 | 6.20489 | 10699.9 | 0.115562 | 150
22_BI-E-01_305 | 02 2e verdieping | 1700 | 1743.22 | 2.96347 | 6886.43 | 0.0625127 | 150
22_BI-E-01_305 | 02 2e verdieping | 1700 | 1845.21 | 3.13686 | 7090.42 | 0.0640708 | 150
22_BI-E-01_305 | 02 2e verdieping | 1700 | 1839.66 | 3.12742 | 7079.31 | 0.0639859 | 150

# IfcWindow: R2 bl ol 27 (13)
In: 00 Begane grond
Type - OperationType: TRIPLE_PANEL_BOTTOM; ParameterTakesPrecedence: no; Sizeable: no
OverallHeight: 3450 mm; OverallWidth: 1702 mm
Pset_WindowCommon - IsExternal: yes
BaseQuantities - GrossArea: 5.8719 m2; Height: 3450 mm; Width: 1702 mm; Perimeter: 10304 mm; Area: 5.8719 m2; Volume: 0.0836093 m3; Depth: 420 mm; NetVolume: 0.0836093 m3
Material - Afwerking dagkant binnen: n.v.t.; Afwerking dagkant buiten: n.v.t.; Draaiend deel: n.v.t.; Frame: n.v.t.; Onderdorpel: n.v.t.; Rollaag / latei: n.v.t.; Spouwlat: n.v.t.; Vensterbank: n.v.t.; Ventilatierooster: n.v.t.; Zonwering - behuizing: n.v.t.; Zonwering - isolatie: n.v.t.; Glas: Glas - algemeen
Name
8 x 21_BU-A-01a_305
5 x 21_BU-A-01a sp_305

# IfcWindow: R2 bl ol 27 (53)
Type - OperationType: USERDEFINED; ParameterTakesPrecedence: no; Sizeable: no
Pset_WindowCommon - IsExternal: yes
Material - Afwerking dagkant binnen: n.v.t.; Afwerking dagkant buiten: n.v.t.; Draaiend deel: n.v.t.; Frame: n.v.t.; Onderdorpel: n.v.t.; Rollaag / latei: n.v.t.; Spouwlat: n.v.t.; Vensterbank: n.v.t.; Ventilatierooster: n.v.t.; Zonwering - behuizing: n.v.t.; Zonwering - isolatie: n.v.t.; Glas: Glas - algemeen
BaseQuantities - Depth: 420 mm
Name | In | OverallHeight (mm) = Height (mm) | OverallWidth (mm) = Width (mm) | GrossArea (m2) = Area (m2) | Perimeter (mm) | Volume (m3) = NetVolume (m3)
4 x 21_BU-A-13a sp_305 | 01 1e verdieping | 3259.59 | 1837 | 5.98787 | 10193.2 | 0.0907757
6 x 21_BU-A-12a_305 | 01 1e verdieping | 3450 | 1837 | 6.33765 | 10574 | 0.0944533
3 x 21_BU-A-12a_305 | 01 1e verdieping | 3454 | 1837 | 6.345 | 10582 | 0.0945305
8 x 21_BU-A-12a sp_305 | 01 1e verdieping | 3450 | 1702 | 5.8719 | 10304 | 0.0853376
4 x 21_BU-A-12a sp_305 | 01 1e verdieping | 3450 | 1837 | 6.33765 | 10574 | 0.0944533
10 x 21_BU-A-12a_305 | 01 1e verdieping | 3450 | 1702 | 5.8719 | 10304 | 0.0853376
8 x 21_BU-A-22a sp_305 | 02 2e verdieping | 3450 | 1702 | 5.8719 | 10304 | 0.0853376
10 x 21_BU-A-22a_305 | 02 2e verdieping | 3450 | 1702 | 5.8719 | 10304 | 0.0853376

# IfcWindow: R3 bl ol 27, 22_BI-E-04_305
In: 00 Begane grond
Type - OperationType: TRIPLE_PANEL_VERTICAL; ParameterTakesPrecedence: no; Sizeable: no
OverallHeight: 1464 mm; OverallWidth: 3111.63 mm
Material - Afwerking dagkant binnen: n.v.t.; Afwerking dagkant buiten: n.v.t.; Draaiend deel: n.v.t.; Frame: n.v.t.; Onderdorpel: n.v.t.; Rollaag / latei: n.v.t.; Spouwlat: n.v.t.; Vensterbank: n.v.t.; Ventilatierooster: n.v.t.; Zonwering - behuizing: n.v.t.; Zonwering - isolatie: n.v.t.; Glas: Glas - algemeen
BaseQuantities - GrossArea: 4.55543 m2; Height: 1464 mm; Width: 3111.63 mm; Perimeter: 9151.27 mm; Area: 4.55543 m2; Volume: 0.0881675 m3; Depth: 150 mm; NetVolume: 0.0881675 m3
Pset_WindowCommon - IsExternal: yes

# IfcWindow: RSH4 bl 27, 22__305
In: 00 Begane grond
Type - OperationType: USERDEFINED; ParameterTakesPrecedence: no; Sizeable: no
OverallHeight: 1552 mm; OverallWidth: 3416.39 mm
Pset_WindowCommon - IsExternal: yes
BaseQuantities - GrossArea: 5.1998 m2; Height: 1552 mm; Width: 3350.39 mm; Perimeter: 9804.78 mm; Area: 5.1998 m2; Volume: 0.0310205 m3; Depth: 150 mm; NetVolume: 0.0310205 m3
Material - Afwerking dagkant binnen: n.v.t.; Afwerking dagkant buiten: n.v.t.; Draaiend deel: n.v.t.; Frame: n.v.t.; Onderdorpel: n.v.t.; Rollaag / latei: n.v.t.; Spouwlat: n.v.t.; Vensterbank: n.v.t.; Ventilatierooster: n.v.t.; Zonwering - behuizing: n.v.t.; Zonwering - isolatie: n.v.t.; Glas: Glas - algemeen

# IfcWindow: Rmeerkeuze 27 (68)
Type - OperationType: TRIPLE_PANEL_HORIZONTAL; ParameterTakesPrecedence: no; Sizeable: no
Material - Afwerking dagkant binnen: n.v.t.; Afwerking dagkant buiten: n.v.t.; Draaiend deel: n.v.t.; Frame: n.v.t.; Onderdorpel: n.v.t.; Rollaag / latei: n.v.t.; Spouwlat: n.v.t.; Vensterbank: n.v.t.; Ventilatierooster: n.v.t.; Zonwering - behuizing: n.v.t.; Zonwering - isolatie: n.v.t.; Glas: Glas - algemeen
Pset_WindowCommon - IsExternal: yes
BaseQuantities - Depth: 420 mm
Name | In | OverallHeight (mm) = Height (mm) | OverallWidth (mm) = Width (mm) | GrossArea (m2) = Area (m2) | Perimeter (mm) | Volume (m3) = NetVolume (m3)
8 x 21_BU-A-01b_305 | 00 Begane grond | 3450 | 1326 | 4.5747 | 9552 | 0.0894829
6 x 21_BU-A-01b sp_305 | 00 Begane grond | 3450 | 1326 | 4.5747 | 9552 | 0.0894829
21_BU-A-13b sp_305 | 01 1e verdieping | 3254.59 | 1267 | 4.12357 | 9043.18 | 0.0884344
3 x 21_BU-A-13b sp_305 | 01 1e verdieping | 3259.59 | 1267 | 4.1299 | 9053.18 | 0.0885023
5 x 21_BU-A-12b_305 | 01 1e verdieping | 3450 | 1267 | 4.37115 | 9434 | 0.0910865
2 x 21_BU-A-12b_305 | 01 1e verdieping | 3454 | 1267 | 4.37622 | 9442 | 0.103448
21_BU-A-12b_305 | 01 1e verdieping | 3454 | 1267 | 4.37622 | 9442 | 0.097124
8 x 21_BU-A-12b sp_305 | 01 1e verdieping | 3450 | 1326 | 4.5747 | 9552 | 0.0863644
4 x 21_BU-A-12b sp_305 | 01 1e verdieping | 3450 | 1267 | 4.37115 | 9434 | 0.0910865
21_BU-A-14b_305 | 01 1e verdieping | 3454 | 1060.48 | 3.66291 | 9028.97 | 0.102038
21_BU-A-15b_305 | 01 1e verdieping | 3454 | 1267 | 4.37622 | 9442 | 0.097124
10 x 21_BU-A-12b_305 | 01 1e verdieping | 3450 | 1326 | 4.5747 | 9552 | 0.0863644
8 x 21_BU-A-22b sp_305 | 02 2e verdieping | 3450 | 1326 | 4.5747 | 9552 | 0.0863644
10 x 21_BU-A-22b_305 | 02 2e verdieping | 3450 | 1326 | 4.5747 | 9552 | 0.0863644

# IfcWindow: Rnx horizontaal 27 (4)
Type - OperationType: DOUBLE_PANEL_VERTICAL; ParameterTakesPrecedence: no; Sizeable: no
OverallHeight: 1700 mm; OverallWidth: 1850 mm
Material - Afwerking dagkant binnen: n.v.t.; Afwerking dagkant buiten: n.v.t.; Draaiend deel: n.v.t.; Frame: n.v.t.; Onderdorpel: n.v.t.; Rollaag / latei: n.v.t.; Spouwlat: n.v.t.; Vensterbank: n.v.t.; Ventilatierooster: n.v.t.; Zonwering - behuizing: n.v.t.; Zonwering - isolatie: n.v.t.; Glas: Glas - algemeen
Pset_WindowCommon - IsExternal: yes
BaseQuantities - GrossArea: 3.145 m2; Height: 1700 mm; Width: 1850 mm; Perimeter: 7100 mm; Area: 3.145 m2; Volume: 0.0641439 m3; Depth: 150 mm; NetVolume: 0.0641439 m3
Name | In
3 x 22_BI-E-01_305 | 01 1e verdieping
22_BI-E-01_305 | 02 2e verdieping

# IfcWindow: Rnx horizontaal 27 (12)
Type - OperationType: USERDEFINED; ParameterTakesPrecedence: no; Sizeable: no
Material - Afwerking dagkant binnen: n.v.t.; Afwerking dagkant buiten: n.v.t.; Draaiend deel: n.v.t.; Frame: n.v.t.; Onderdorpel: n.v.t.; Rollaag / latei: n.v.t.; Spouwlat: n.v.t.; Vensterbank: n.v.t.; Ventilatierooster: n.v.t.; Zonwering - behuizing: n.v.t.; Zonwering - isolatie: n.v.t.; Glas: Glas - algemeen
Pset_WindowCommon - IsExternal: yes
Name | In | OverallHeight (mm) = Height (mm) | OverallWidth (mm) = Width (mm) | GrossArea (m2) = Area (m2) | Perimeter (mm) | Volume (m3) = NetVolume (m3) | Depth (mm)
22_BU-B-02_305 | 00 Begane grond | 2377 | 5328.92 | 12.6669 | 15411.8 | 0.247398 | 312.5
21_BU-B-12_305 | 01 1e tussenverdieping | 2377 | 5328.92 | 12.6669 | 15411.8 | 0.247398 | 397.5
22_BI-E-14_305 | 01 1e tussenverdieping | 2367 | 3450 | 8.16615 | 11634 | 0.13798 | 160
22_BU-B-11_305 | 01 1e tussenverdieping | 2377 | 5328.92 | 12.6669 | 15411.8 | 0.235611 | 397.5
3 x 22_BI-E-01_305 | 01 1e verdieping | 1700 | 3649.9 | 6.20483 | 10699.8 | 0.115561 | 150
22_BI-E-01_305 | 01 1e verdieping | 1700 | 3650 | 6.205 | 10700 | 0.115563 | 150
21_BU-B-31_305 | 03 3e tussenverdieping | 2377 | 5328.92 | 12.6669 | 15411.8 | 0.247398 | 312.5
22_BI-E-14_305 | 03 3e tussenverdieping | 2367 | 3450 | 8.16615 | 11634 | 0.122248 | 160
21_BU-B-32_305 | 03 3e tussenverdieping | 2377 | 5328.92 | 12.6669 | 15411.8 | 0.205897 | 312.5
22_BI-E-01_305 | 02 2e verdieping | 1700 | 3649.9 | 6.20483 | 10699.8 | 0.115561 | 150

# IfcWindow: Rnx verticaal 27 (21)
Type - OperationType: DOUBLE_PANEL_HORIZONTAL; ParameterTakesPrecedence: no; Sizeable: no
Material - Glas: Glas - algemeen
Pset_WindowCommon - IsExternal: yes
Name | In | OverallHeight (mm) = Height (mm) | OverallWidth (mm) = Width (mm) | Afwerking dagkant binnen = Afwerking dagkant buiten = Vensterbank | Draaiend deel | Frame = Rollaag / latei = Zonwering - behuizing | Onderdorpel = Ventilatierooster | Spouwlat | Zonwering - isolatie | GrossArea (m2) = Area (m2) | Perimeter (mm) | Volume (m3) = NetVolume (m3) | Depth (mm)
21_BU-B-03_305 | 00 Begane grond | 3353.98 | 1940 | Gewapend beton - i.h.w. (02) | arcering (02) | arcering (01) | % | Naaldhout (01) | Isolatie ruit | 6.50671 | 10588 | 0.171278 | 420
8 x 21_BU-B-04_305 | 00 Begane grond | 3353.98 | 2000 | Gewapend beton - i.h.w. (02) | arcering (02) | arcering (01) | % | Naaldhout (01) | Isolatie ruit | 6.70795 | 10708 | 0.175669 | 420
21_BU-B-03 sp_305 | 00 Begane grond | 3353.98 | 1940 | Gewapend beton - i.h.w. (02) | arcering (02) | arcering (01) | % | Naaldhout (01) | Isolatie ruit | 6.50671 | 10588 | 0.171278 | 420
22_BI-C-04_305 | 00 Begane grond | 3200 | 2400 | n.v.t. | n.v.t. | n.v.t. | n.v.t. | n.v.t. | n.v.t. | 7.68 | 11200 | 0.100806 | 150
8 x 21_BU-B-24_305 | 02 2e tussenverdieping | 3453.97 | 2000 | Gewapend beton - i.h.w. (02) | arcering (02) | arcering (01) | % | Naaldhout (01) | Isolatie ruit | 6.90795 | 10907.9 | 0.162728 | 420
21_BU-B-23_305 | 02 2e tussenverdieping | 3453.97 | 1940 | Gewapend beton - i.h.w. (02) | arcering (02) | arcering (01) | % | Naaldhout (01) | Isolatie ruit | 6.70071 | 10787.9 | 0.158791 | 420
21_BU-B-23 sp_305 | 02 2e tussenverdieping | 3453.97 | 1940 | Gewapend beton - i.h.w. (02) | arcering (02) | arcering (01) | % | Naaldhout (01) | Isolatie ruit | 6.70071 | 10787.9 | 0.158791 | 420
